<?xml version="1.0" encoding="utf-8" standalone="no"?>
<device schemaVersion="1.1">
  <name>STM32F072VBT6</name>
  <version>1.0</version>
  <description>STM32F072C8T6,STM32F072C8T7,STM32F072C8U6,STM32F072C8U7,STM32F072CBT6,STM32F072CBT7,STM32F072CBU6,STM32F072CBU7,STM32F072CBY6,STM32F072CBY7,STM32F072R8T6,STM32F072R8T7,STM32F072RBH6,STM32F072RBH7,STM32F072RBI6,STM32F072RBI7,STM32F072RBT6,STM32F072RBT7,STM32F072V8H6,STM32F072V8T6,STM32F072VBH6,STM32F072VBT6</description>
  <addressUnitBits>8</addressUnitBits>
  <width>32</width>
  <size>0x20</size>
  <resetValue>0</resetValue>
  <resetMask>0xFFFFFFFF</resetMask>
  <peripherals>
    <peripheral>
      <name>OB</name>
      <baseAddress>0x1ffff800</baseAddress>
      <registers>
        <register>
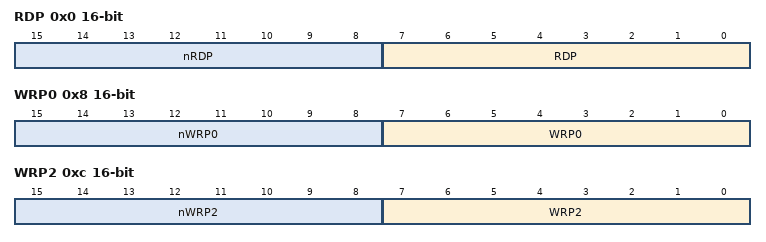
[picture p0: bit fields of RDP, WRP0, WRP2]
          <name>RDP</name>
          <addressOffset>0x0</addressOffset>
          <size>0x10</size>
          <fields>
            <field>
              <name>RDP</name>
              <bitOffset>0</bitOffset>
              <bitWidth>8</bitWidth>
            </field>
            <field>
              <name>nRDP</name>
              <bitOffset>8</bitOffset>
              <bitWidth>8</bitWidth>
            </field>
          </fields>
        </register>
        <register>
          <name>USER</name>
          <addressOffset>0x2</addressOffset>
          <size>0x10</size>
          <fields>
            <field>
              <name>USER</name>
              <bitOffset>16</bitOffset>
              <bitWidth>8</bitWidth>
            </field>
            <field>
              <name>nUSER</name>
              <bitOffset>24</bitOffset>
              <bitWidth>8</bitWidth>
            </field>
          </fields>
        </register>
        <register>
          <name>DATA0</name>
          <addressOffset>0x4</addressOffset>
          <size>0x10</size>
        </register>
        <register>
          <name>DATA1</name>
          <addressOffset>0x6</addressOffset>
          <size>0x10</size>
        </register>
        <register>
          <name>WRP0</name>
          <addressOffset>0x8</addressOffset>
          <size>0x10</size>
          <fields>
            <field>
              <name>WRP0</name>
              <bitOffset>0</bitOffset>
              <bitWidth>8</bitWidth>
            </field>
            <field>
              <name>nWRP0</name>
              <bitOffset>8</bitOffset>
              <bitWidth>8</bitWidth>
            </field>
          </fields>
        </register>
        <register>
          <name>WRP1</name>
          <addressOffset>0xa</addressOffset>
          <size>0x10</size>
          <fields>
            <field>
              <name>WRP1</name>
              <bitOffset>16</bitOffset>
              <bitWidth>8</bitWidth>
            </field>
            <field>
              <name>nWRP1</name>
              <bitOffset>24</bitOffset>
              <bitWidth>8</bitWidth>
            </field>
          </fields>
        </register>
        <register>
          <name>WRP2</name>
          <addressOffset>0xc</addressOffset>
          <size>0x10</size>
          <fields>
            <field>
              <name>WRP2</name>
              <bitOffset>0</bitOffset>
              <bitWidth>8</bitWidth>
            </field>
            <field>
              <name>nWRP2</name>
              <bitOffset>8</bitOffset>
              <bitWidth>8</bitWidth>
            </field>
          </fields>
        </register>
        <register>
          <name>WRP3</name>
          <addressOffset>0xe</addressOffset>
          <size>0x10</size>
          <fields>
            <field>
              <name>WRP3</name>
              <bitOffset>16</bitOffset>
              <bitWidth>8</bitWidth>
            </field>
            <field>
              <name>nWRP3</name>
              <bitOffset>24</bitOffset>
              <bitWidth>8</bitWidth>
            </field>
          </fields>
        </register>
      </registers>
    </peripheral>
    <peripheral>
      <name>TIM2</name>
      <baseAddress>0x40000000</baseAddress>
      <registers>
        <register>
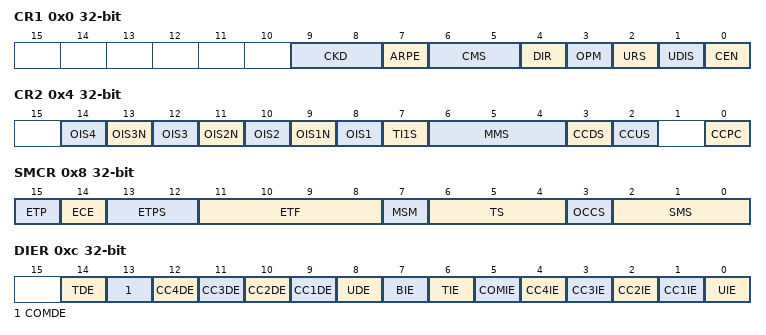
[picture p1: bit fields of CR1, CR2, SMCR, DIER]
          <name>CR1</name>
          <addressOffset>0x0</addressOffset>
          <size>0x20</size>
          <fields>
            <field>
              <name>CEN</name>
              <bitOffset>0</bitOffset>
              <bitWidth>1</bitWidth>
            </field>
            <field>
              <name>UDIS</name>
              <bitOffset>1</bitOffset>
              <bitWidth>1</bitWidth>
            </field>
            <field>
              <name>URS</name>
              <bitOffset>2</bitOffset>
              <bitWidth>1</bitWidth>
            </field>
            <field>
              <name>OPM</name>
              <bitOffset>3</bitOffset>
              <bitWidth>1</bitWidth>
            </field>
            <field>
              <name>DIR</name>
              <bitOffset>4</bitOffset>
              <bitWidth>1</bitWidth>
            </field>
            <field>
              <name>CMS</name>
              <bitOffset>5</bitOffset>
              <bitWidth>2</bitWidth>
            </field>
            <field>
              <name>ARPE</name>
              <bitOffset>7</bitOffset>
              <bitWidth>1</bitWidth>
            </field>
            <field>
              <name>CKD</name>
              <bitOffset>8</bitOffset>
              <bitWidth>2</bitWidth>
            </field>
          </fields>
        </register>
        <register>
          <name>CR2</name>
          <addressOffset>0x4</addressOffset>
          <size>0x20</size>
          <fields>
            <field>
              <name>CCPC</name>
              <bitOffset>0</bitOffset>
              <bitWidth>1</bitWidth>
            </field>
            <field>
              <name>CCUS</name>
              <bitOffset>2</bitOffset>
              <bitWidth>1</bitWidth>
            </field>
            <field>
              <name>CCDS</name>
              <bitOffset>3</bitOffset>
              <bitWidth>1</bitWidth>
            </field>
            <field>
              <name>MMS</name>
              <bitOffset>4</bitOffset>
              <bitWidth>3</bitWidth>
            </field>
            <field>
              <name>TI1S</name>
              <bitOffset>7</bitOffset>
              <bitWidth>1</bitWidth>
            </field>
            <field>
              <name>OIS1</name>
              <bitOffset>8</bitOffset>
              <bitWidth>1</bitWidth>
            </field>
            <field>
              <name>OIS1N</name>
              <bitOffset>9</bitOffset>
              <bitWidth>1</bitWidth>
            </field>
            <field>
              <name>OIS2</name>
              <bitOffset>10</bitOffset>
              <bitWidth>1</bitWidth>
            </field>
            <field>
              <name>OIS2N</name>
              <bitOffset>11</bitOffset>
              <bitWidth>1</bitWidth>
            </field>
            <field>
              <name>OIS3</name>
              <bitOffset>12</bitOffset>
              <bitWidth>1</bitWidth>
            </field>
            <field>
              <name>OIS3N</name>
              <bitOffset>13</bitOffset>
              <bitWidth>1</bitWidth>
            </field>
            <field>
              <name>OIS4</name>
              <bitOffset>14</bitOffset>
              <bitWidth>1</bitWidth>
            </field>
          </fields>
        </register>
        <register>
          <name>SMCR</name>
          <addressOffset>0x8</addressOffset>
          <size>0x20</size>
          <fields>
            <field>
              <name>SMS</name>
              <bitOffset>0</bitOffset>
              <bitWidth>3</bitWidth>
            </field>
            <field>
              <name>OCCS</name>
              <bitOffset>3</bitOffset>
              <bitWidth>1</bitWidth>
            </field>
            <field>
              <name>TS</name>
              <bitOffset>4</bitOffset>
              <bitWidth>3</bitWidth>
            </field>
            <field>
              <name>MSM</name>
              <bitOffset>7</bitOffset>
              <bitWidth>1</bitWidth>
            </field>
            <field>
              <name>ETF</name>
              <bitOffset>8</bitOffset>
              <bitWidth>4</bitWidth>
            </field>
            <field>
              <name>ETPS</name>
              <bitOffset>12</bitOffset>
              <bitWidth>2</bitWidth>
            </field>
            <field>
              <name>ECE</name>
              <bitOffset>14</bitOffset>
              <bitWidth>1</bitWidth>
            </field>
            <field>
              <name>ETP</name>
              <bitOffset>15</bitOffset>
              <bitWidth>1</bitWidth>
            </field>
          </fields>
        </register>
        <register>
          <name>DIER</name>
          <addressOffset>0xc</addressOffset>
          <size>0x20</size>
          <fields>
            <field>
              <name>UIE</name>
              <bitOffset>0</bitOffset>
              <bitWidth>1</bitWidth>
            </field>
            <field>
              <name>CC1IE</name>
              <bitOffset>1</bitOffset>
              <bitWidth>1</bitWidth>
            </field>
            <field>
              <name>CC2IE</name>
              <bitOffset>2</bitOffset>
              <bitWidth>1</bitWidth>
            </field>
            <field>
              <name>CC3IE</name>
              <bitOffset>3</bitOffset>
              <bitWidth>1</bitWidth>
            </field>
            <field>
              <name>CC4IE</name>
              <bitOffset>4</bitOffset>
              <bitWidth>1</bitWidth>
            </field>
            <field>
              <name>COMIE</name>
              <bitOffset>5</bitOffset>
              <bitWidth>1</bitWidth>
            </field>
            <field>
              <name>TIE</name>
              <bitOffset>6</bitOffset>
              <bitWidth>1</bitWidth>
            </field>
            <field>
              <name>BIE</name>
              <bitOffset>7</bitOffset>
              <bitWidth>1</bitWidth>
            </field>
            <field>
              <name>UDE</name>
              <bitOffset>8</bitOffset>
              <bitWidth>1</bitWidth>
            </field>
            <field>
              <name>CC1DE</name>
              <bitOffset>9</bitOffset>
              <bitWidth>1</bitWidth>
            </field>
            <field>
              <name>CC2DE</name>
              <bitOffset>10</bitOffset>
              <bitWidth>1</bitWidth>
            </field>
            <field>
              <name>CC3DE</name>
              <bitOffset>11</bitOffset>
              <bitWidth>1</bitWidth>
            </field>
            <field>
              <name>CC4DE</name>
              <bitOffset>12</bitOffset>
              <bitWidth>1</bitWidth>
            </field>
            <field>
              <name>COMDE</name>
              <bitOffset>13</bitOffset>
              <bitWidth>1</bitWidth>
            </field>
            <field>
              <name>TDE</name>
              <bitOffset>14</bitOffset>
              <bitWidth>1</bitWidth>
            </field>
          </fields>
        </register>
        <register>
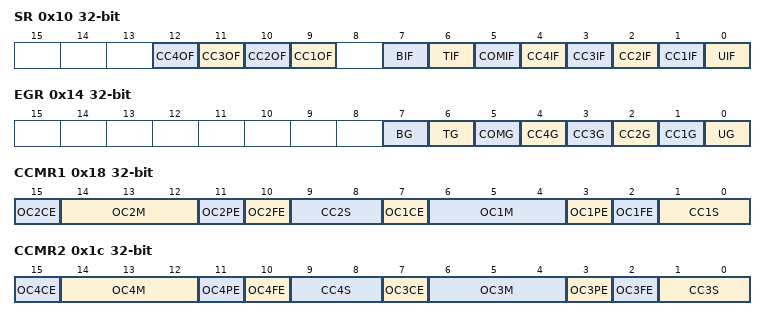
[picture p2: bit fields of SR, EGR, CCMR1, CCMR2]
          <name>SR</name>
          <addressOffset>0x10</addressOffset>
          <size>0x20</size>
          <fields>
            <field>
              <name>UIF</name>
              <bitOffset>0</bitOffset>
              <bitWidth>1</bitWidth>
            </field>
            <field>
              <name>CC1IF</name>
              <bitOffset>1</bitOffset>
              <bitWidth>1</bitWidth>
            </field>
            <field>
              <name>CC2IF</name>
              <bitOffset>2</bitOffset>
              <bitWidth>1</bitWidth>
            </field>
            <field>
              <name>CC3IF</name>
              <bitOffset>3</bitOffset>
              <bitWidth>1</bitWidth>
            </field>
            <field>
              <name>CC4IF</name>
              <bitOffset>4</bitOffset>
              <bitWidth>1</bitWidth>
            </field>
            <field>
              <name>COMIF</name>
              <bitOffset>5</bitOffset>
              <bitWidth>1</bitWidth>
            </field>
            <field>
              <name>TIF</name>
              <bitOffset>6</bitOffset>
              <bitWidth>1</bitWidth>
            </field>
            <field>
              <name>BIF</name>
              <bitOffset>7</bitOffset>
              <bitWidth>1</bitWidth>
            </field>
            <field>
              <name>CC1OF</name>
              <bitOffset>9</bitOffset>
              <bitWidth>1</bitWidth>
            </field>
            <field>
              <name>CC2OF</name>
              <bitOffset>10</bitOffset>
              <bitWidth>1</bitWidth>
            </field>
            <field>
              <name>CC3OF</name>
              <bitOffset>11</bitOffset>
              <bitWidth>1</bitWidth>
            </field>
            <field>
              <name>CC4OF</name>
              <bitOffset>12</bitOffset>
              <bitWidth>1</bitWidth>
            </field>
          </fields>
        </register>
        <register>
          <name>EGR</name>
          <addressOffset>0x14</addressOffset>
          <size>0x20</size>
          <fields>
            <field>
              <name>UG</name>
              <bitOffset>0</bitOffset>
              <bitWidth>1</bitWidth>
            </field>
            <field>
              <name>CC1G</name>
              <bitOffset>1</bitOffset>
              <bitWidth>1</bitWidth>
            </field>
            <field>
              <name>CC2G</name>
              <bitOffset>2</bitOffset>
              <bitWidth>1</bitWidth>
            </field>
            <field>
              <name>CC3G</name>
              <bitOffset>3</bitOffset>
              <bitWidth>1</bitWidth>
            </field>
            <field>
              <name>CC4G</name>
              <bitOffset>4</bitOffset>
              <bitWidth>1</bitWidth>
            </field>
            <field>
              <name>COMG</name>
              <bitOffset>5</bitOffset>
              <bitWidth>1</bitWidth>
            </field>
            <field>
              <name>TG</name>
              <bitOffset>6</bitOffset>
              <bitWidth>1</bitWidth>
            </field>
            <field>
              <name>BG</name>
              <bitOffset>7</bitOffset>
              <bitWidth>1</bitWidth>
            </field>
          </fields>
        </register>
        <register>
          <name>CCMR1</name>
          <addressOffset>0x18</addressOffset>
          <size>0x20</size>
          <fields>
            <field>
              <name>CC1S</name>
              <bitOffset>0</bitOffset>
              <bitWidth>2</bitWidth>
            </field>
            <field>
              <name>OC1FE</name>
              <bitOffset>2</bitOffset>
              <bitWidth>1</bitWidth>
            </field>
            <field>
              <name>OC1PE</name>
              <bitOffset>3</bitOffset>
              <bitWidth>1</bitWidth>
            </field>
            <field>
              <name>OC1M</name>
              <bitOffset>4</bitOffset>
              <bitWidth>3</bitWidth>
            </field>
            <field>
              <name>OC1CE</name>
              <bitOffset>7</bitOffset>
              <bitWidth>1</bitWidth>
            </field>
            <field>
              <name>CC2S</name>
              <bitOffset>8</bitOffset>
              <bitWidth>2</bitWidth>
            </field>
            <field>
              <name>OC2FE</name>
              <bitOffset>10</bitOffset>
              <bitWidth>1</bitWidth>
            </field>
            <field>
              <name>OC2PE</name>
              <bitOffset>11</bitOffset>
              <bitWidth>1</bitWidth>
            </field>
            <field>
              <name>OC2M</name>
              <bitOffset>12</bitOffset>
              <bitWidth>3</bitWidth>
            </field>
            <field>
              <name>OC2CE</name>
              <bitOffset>15</bitOffset>
              <bitWidth>1</bitWidth>
            </field>
          </fields>
        </register>
        <register>
          <name>CCMR2</name>
          <addressOffset>0x1c</addressOffset>
          <size>0x20</size>
          <fields>
            <field>
              <name>CC3S</name>
              <bitOffset>0</bitOffset>
              <bitWidth>2</bitWidth>
            </field>
            <field>
              <name>OC3FE</name>
              <bitOffset>2</bitOffset>
              <bitWidth>1</bitWidth>
            </field>
            <field>
              <name>OC3PE</name>
              <bitOffset>3</bitOffset>
              <bitWidth>1</bitWidth>
            </field>
            <field>
              <name>OC3M</name>
              <bitOffset>4</bitOffset>
              <bitWidth>3</bitWidth>
            </field>
            <field>
              <name>OC3CE</name>
              <bitOffset>7</bitOffset>
              <bitWidth>1</bitWidth>
            </field>
            <field>
              <name>CC4S</name>
              <bitOffset>8</bitOffset>
              <bitWidth>2</bitWidth>
            </field>
            <field>
              <name>OC4FE</name>
              <bitOffset>10</bitOffset>
              <bitWidth>1</bitWidth>
            </field>
            <field>
              <name>OC4PE</name>
              <bitOffset>11</bitOffset>
              <bitWidth>1</bitWidth>
            </field>
            <field>
              <name>OC4M</name>
              <bitOffset>12</bitOffset>
              <bitWidth>3</bitWidth>
            </field>
            <field>
              <name>OC4CE</name>
              <bitOffset>15</bitOffset>
              <bitWidth>1</bitWidth>
            </field>
          </fields>
        </register>
        <register>
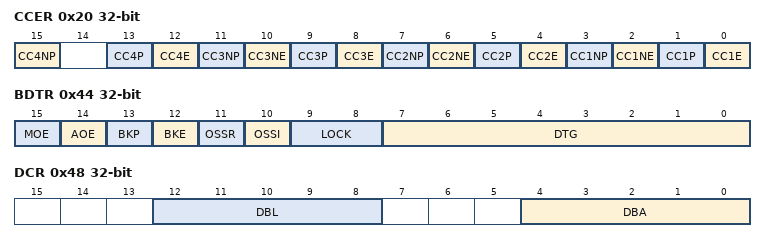
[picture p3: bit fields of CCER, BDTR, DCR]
          <name>CCER</name>
          <addressOffset>0x20</addressOffset>
          <size>0x20</size>
          <fields>
            <field>
              <name>CC1E</name>
              <bitOffset>0</bitOffset>
              <bitWidth>1</bitWidth>
            </field>
            <field>
              <name>CC1P</name>
              <bitOffset>1</bitOffset>
              <bitWidth>1</bitWidth>
            </field>
            <field>
              <name>CC1NE</name>
              <bitOffset>2</bitOffset>
              <bitWidth>1</bitWidth>
            </field>
            <field>
              <name>CC1NP</name>
              <bitOffset>3</bitOffset>
              <bitWidth>1</bitWidth>
            </field>
            <field>
              <name>CC2E</name>
              <bitOffset>4</bitOffset>
              <bitWidth>1</bitWidth>
            </field>
            <field>
              <name>CC2P</name>
              <bitOffset>5</bitOffset>
              <bitWidth>1</bitWidth>
            </field>
            <field>
              <name>CC2NE</name>
              <bitOffset>6</bitOffset>
              <bitWidth>1</bitWidth>
            </field>
            <field>
              <name>CC2NP</name>
              <bitOffset>7</bitOffset>
              <bitWidth>1</bitWidth>
            </field>
            <field>
              <name>CC3E</name>
              <bitOffset>8</bitOffset>
              <bitWidth>1</bitWidth>
            </field>
            <field>
              <name>CC3P</name>
              <bitOffset>9</bitOffset>
              <bitWidth>1</bitWidth>
            </field>
            <field>
              <name>CC3NE</name>
              <bitOffset>10</bitOffset>
              <bitWidth>1</bitWidth>
            </field>
            <field>
              <name>CC3NP</name>
              <bitOffset>11</bitOffset>
              <bitWidth>1</bitWidth>
            </field>
            <field>
              <name>CC4E</name>
              <bitOffset>12</bitOffset>
              <bitWidth>1</bitWidth>
            </field>
            <field>
              <name>CC4P</name>
              <bitOffset>13</bitOffset>
              <bitWidth>1</bitWidth>
            </field>
            <field>
              <name>CC4NP</name>
              <bitOffset>15</bitOffset>
              <bitWidth>1</bitWidth>
            </field>
          </fields>
        </register>
        <register>
          <name>CNT</name>
          <addressOffset>0x24</addressOffset>
          <size>0x20</size>
          <fields>
            <field>
              <name>CNT</name>
              <bitOffset>0</bitOffset>
              <bitWidth>32</bitWidth>
            </field>
          </fields>
        </register>
        <register>
          <name>PSC</name>
          <addressOffset>0x28</addressOffset>
          <size>0x20</size>
          <fields>
            <field>
              <name>PSC</name>
              <bitOffset>0</bitOffset>
              <bitWidth>16</bitWidth>
            </field>
          </fields>
        </register>
        <register>
          <name>ARR</name>
          <addressOffset>0x2c</addressOffset>
          <size>0x20</size>
          <fields>
            <field>
              <name>ARR</name>
              <bitOffset>0</bitOffset>
              <bitWidth>32</bitWidth>
            </field>
          </fields>
        </register>
        <register>
          <name>RCR</name>
          <addressOffset>0x30</addressOffset>
          <size>0x20</size>
          <fields>
            <field>
              <name>REP</name>
              <bitOffset>0</bitOffset>
              <bitWidth>8</bitWidth>
            </field>
          </fields>
        </register>
        <register>
          <name>CCR1</name>
          <addressOffset>0x34</addressOffset>
          <size>0x20</size>
          <fields>
            <field>
              <name>CCR1</name>
              <bitOffset>0</bitOffset>
              <bitWidth>16</bitWidth>
            </field>
          </fields>
        </register>
        <register>
          <name>CCR2</name>
          <addressOffset>0x38</addressOffset>
          <size>0x20</size>
          <fields>
            <field>
              <name>CCR2</name>
              <bitOffset>0</bitOffset>
              <bitWidth>16</bitWidth>
            </field>
          </fields>
        </register>
        <register>
          <name>CCR3</name>
          <addressOffset>0x3c</addressOffset>
          <size>0x20</size>
          <fields>
            <field>
              <name>CCR3</name>
              <bitOffset>0</bitOffset>
              <bitWidth>16</bitWidth>
            </field>
          </fields>
        </register>
        <register>
          <name>CCR4</name>
          <addressOffset>0x40</addressOffset>
          <size>0x20</size>
          <fields>
            <field>
              <name>CCR4</name>
              <bitOffset>0</bitOffset>
              <bitWidth>16</bitWidth>
            </field>
          </fields>
        </register>
        <register>
          <name>BDTR</name>
          <addressOffset>0x44</addressOffset>
          <size>0x20</size>
          <fields>
            <field>
              <name>DTG</name>
              <bitOffset>0</bitOffset>
              <bitWidth>8</bitWidth>
            </field>
            <field>
              <name>LOCK</name>
              <bitOffset>8</bitOffset>
              <bitWidth>2</bitWidth>
            </field>
            <field>
              <name>OSSI</name>
              <bitOffset>10</bitOffset>
              <bitWidth>1</bitWidth>
            </field>
            <field>
              <name>OSSR</name>
              <bitOffset>11</bitOffset>
              <bitWidth>1</bitWidth>
            </field>
            <field>
              <name>BKE</name>
              <bitOffset>12</bitOffset>
              <bitWidth>1</bitWidth>
            </field>
            <field>
              <name>BKP</name>
              <bitOffset>13</bitOffset>
              <bitWidth>1</bitWidth>
            </field>
            <field>
              <name>AOE</name>
              <bitOffset>14</bitOffset>
              <bitWidth>1</bitWidth>
            </field>
            <field>
              <name>MOE</name>
              <bitOffset>15</bitOffset>
              <bitWidth>1</bitWidth>
            </field>
          </fields>
        </register>
        <register>
          <name>DCR</name>
          <addressOffset>0x48</addressOffset>
          <size>0x20</size>
          <fields>
            <field>
              <name>DBA</name>
              <bitOffset>0</bitOffset>
              <bitWidth>5</bitWidth>
            </field>
            <field>
              <name>DBL</name>
              <bitOffset>8</bitOffset>
              <bitWidth>5</bitWidth>
            </field>
          </fields>
        </register>
        <register>
          <name>DMAR</name>
          <addressOffset>0x4c</addressOffset>
          <size>0x20</size>
          <fields>
            <field>
              <name>DMAB</name>
              <bitOffset>0</bitOffset>
              <bitWidth>16</bitWidth>
            </field>
          </fields>
        </register>
        <register>
          <name>OR</name>
          <addressOffset>0x50</addressOffset>
          <size>0x20</size>
        </register>
      </registers>
    </peripheral>
    <peripheral>
      <name>TIM3</name>
      <baseAddress>0x40000400</baseAddress>
      <registers>
        <register>
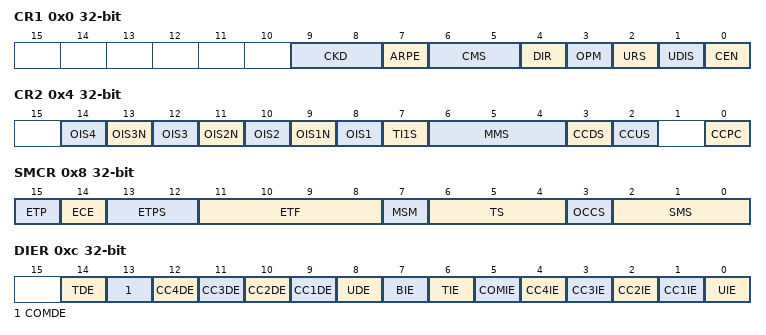
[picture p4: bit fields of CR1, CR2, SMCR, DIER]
          <name>CR1</name>
          <addressOffset>0x0</addressOffset>
          <size>0x20</size>
          <fields>
            <field>
              <name>CEN</name>
              <bitOffset>0</bitOffset>
              <bitWidth>1</bitWidth>
            </field>
            <field>
              <name>UDIS</name>
              <bitOffset>1</bitOffset>
              <bitWidth>1</bitWidth>
            </field>
            <field>
              <name>URS</name>
              <bitOffset>2</bitOffset>
              <bitWidth>1</bitWidth>
            </field>
            <field>
              <name>OPM</name>
              <bitOffset>3</bitOffset>
              <bitWidth>1</bitWidth>
            </field>
            <field>
              <name>DIR</name>
              <bitOffset>4</bitOffset>
              <bitWidth>1</bitWidth>
            </field>
            <field>
              <name>CMS</name>
              <bitOffset>5</bitOffset>
              <bitWidth>2</bitWidth>
            </field>
            <field>
              <name>ARPE</name>
              <bitOffset>7</bitOffset>
              <bitWidth>1</bitWidth>
            </field>
            <field>
              <name>CKD</name>
              <bitOffset>8</bitOffset>
              <bitWidth>2</bitWidth>
            </field>
          </fields>
        </register>
        <register>
          <name>CR2</name>
          <addressOffset>0x4</addressOffset>
          <size>0x20</size>
          <fields>
            <field>
              <name>CCPC</name>
              <bitOffset>0</bitOffset>
              <bitWidth>1</bitWidth>
            </field>
            <field>
              <name>CCUS</name>
              <bitOffset>2</bitOffset>
              <bitWidth>1</bitWidth>
            </field>
            <field>
              <name>CCDS</name>
              <bitOffset>3</bitOffset>
              <bitWidth>1</bitWidth>
            </field>
            <field>
              <name>MMS</name>
              <bitOffset>4</bitOffset>
              <bitWidth>3</bitWidth>
            </field>
            <field>
              <name>TI1S</name>
              <bitOffset>7</bitOffset>
              <bitWidth>1</bitWidth>
            </field>
            <field>
              <name>OIS1</name>
              <bitOffset>8</bitOffset>
              <bitWidth>1</bitWidth>
            </field>
            <field>
              <name>OIS1N</name>
              <bitOffset>9</bitOffset>
              <bitWidth>1</bitWidth>
            </field>
            <field>
              <name>OIS2</name>
              <bitOffset>10</bitOffset>
              <bitWidth>1</bitWidth>
            </field>
            <field>
              <name>OIS2N</name>
              <bitOffset>11</bitOffset>
              <bitWidth>1</bitWidth>
            </field>
            <field>
              <name>OIS3</name>
              <bitOffset>12</bitOffset>
              <bitWidth>1</bitWidth>
            </field>
            <field>
              <name>OIS3N</name>
              <bitOffset>13</bitOffset>
              <bitWidth>1</bitWidth>
            </field>
            <field>
              <name>OIS4</name>
              <bitOffset>14</bitOffset>
              <bitWidth>1</bitWidth>
            </field>
          </fields>
        </register>
        <register>
          <name>SMCR</name>
          <addressOffset>0x8</addressOffset>
          <size>0x20</size>
          <fields>
            <field>
              <name>SMS</name>
              <bitOffset>0</bitOffset>
              <bitWidth>3</bitWidth>
            </field>
            <field>
              <name>OCCS</name>
              <bitOffset>3</bitOffset>
              <bitWidth>1</bitWidth>
            </field>
            <field>
              <name>TS</name>
              <bitOffset>4</bitOffset>
              <bitWidth>3</bitWidth>
            </field>
            <field>
              <name>MSM</name>
              <bitOffset>7</bitOffset>
              <bitWidth>1</bitWidth>
            </field>
            <field>
              <name>ETF</name>
              <bitOffset>8</bitOffset>
              <bitWidth>4</bitWidth>
            </field>
            <field>
              <name>ETPS</name>
              <bitOffset>12</bitOffset>
              <bitWidth>2</bitWidth>
            </field>
            <field>
              <name>ECE</name>
              <bitOffset>14</bitOffset>
              <bitWidth>1</bitWidth>
            </field>
            <field>
              <name>ETP</name>
              <bitOffset>15</bitOffset>
              <bitWidth>1</bitWidth>
            </field>
          </fields>
        </register>
        <register>
          <name>DIER</name>
          <addressOffset>0xc</addressOffset>
          <size>0x20</size>
          <fields>
            <field>
              <name>UIE</name>
              <bitOffset>0</bitOffset>
              <bitWidth>1</bitWidth>
            </field>
            <field>
              <name>CC1IE</name>
              <bitOffset>1</bitOffset>
              <bitWidth>1</bitWidth>
            </field>
            <field>
              <name>CC2IE</name>
              <bitOffset>2</bitOffset>
              <bitWidth>1</bitWidth>
            </field>
            <field>
              <name>CC3IE</name>
              <bitOffset>3</bitOffset>
              <bitWidth>1</bitWidth>
            </field>
            <field>
              <name>CC4IE</name>
              <bitOffset>4</bitOffset>
              <bitWidth>1</bitWidth>
            </field>
            <field>
              <name>COMIE</name>
              <bitOffset>5</bitOffset>
              <bitWidth>1</bitWidth>
            </field>
            <field>
              <name>TIE</name>
              <bitOffset>6</bitOffset>
              <bitWidth>1</bitWidth>
            </field>
            <field>
              <name>BIE</name>
              <bitOffset>7</bitOffset>
              <bitWidth>1</bitWidth>
            </field>
            <field>
              <name>UDE</name>
              <bitOffset>8</bitOffset>
              <bitWidth>1</bitWidth>
            </field>
            <field>
              <name>CC1DE</name>
              <bitOffset>9</bitOffset>
              <bitWidth>1</bitWidth>
            </field>
            <field>
              <name>CC2DE</name>
              <bitOffset>10</bitOffset>
              <bitWidth>1</bitWidth>
            </field>
            <field>
              <name>CC3DE</name>
              <bitOffset>11</bitOffset>
              <bitWidth>1</bitWidth>
            </field>
            <field>
              <name>CC4DE</name>
              <bitOffset>12</bitOffset>
              <bitWidth>1</bitWidth>
            </field>
            <field>
              <name>COMDE</name>
              <bitOffset>13</bitOffset>
              <bitWidth>1</bitWidth>
            </field>
            <field>
              <name>TDE</name>
              <bitOffset>14</bitOffset>
              <bitWidth>1</bitWidth>
            </field>
          </fields>
        </register>
        <register>
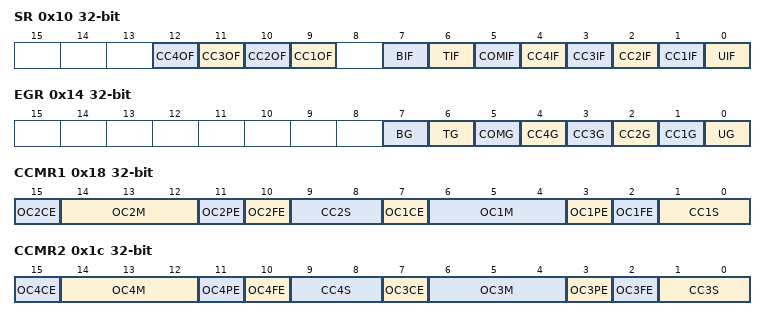
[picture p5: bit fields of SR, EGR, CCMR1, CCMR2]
          <name>SR</name>
          <addressOffset>0x10</addressOffset>
          <size>0x20</size>
          <fields>
            <field>
              <name>UIF</name>
              <bitOffset>0</bitOffset>
              <bitWidth>1</bitWidth>
            </field>
            <field>
              <name>CC1IF</name>
              <bitOffset>1</bitOffset>
              <bitWidth>1</bitWidth>
            </field>
            <field>
              <name>CC2IF</name>
              <bitOffset>2</bitOffset>
              <bitWidth>1</bitWidth>
            </field>
            <field>
              <name>CC3IF</name>
              <bitOffset>3</bitOffset>
              <bitWidth>1</bitWidth>
            </field>
            <field>
              <name>CC4IF</name>
              <bitOffset>4</bitOffset>
              <bitWidth>1</bitWidth>
            </field>
            <field>
              <name>COMIF</name>
              <bitOffset>5</bitOffset>
              <bitWidth>1</bitWidth>
            </field>
            <field>
              <name>TIF</name>
              <bitOffset>6</bitOffset>
              <bitWidth>1</bitWidth>
            </field>
            <field>
              <name>BIF</name>
              <bitOffset>7</bitOffset>
              <bitWidth>1</bitWidth>
            </field>
            <field>
              <name>CC1OF</name>
              <bitOffset>9</bitOffset>
              <bitWidth>1</bitWidth>
            </field>
            <field>
              <name>CC2OF</name>
              <bitOffset>10</bitOffset>
              <bitWidth>1</bitWidth>
            </field>
            <field>
              <name>CC3OF</name>
              <bitOffset>11</bitOffset>
              <bitWidth>1</bitWidth>
            </field>
            <field>
              <name>CC4OF</name>
              <bitOffset>12</bitOffset>
              <bitWidth>1</bitWidth>
            </field>
          </fields>
        </register>
        <register>
          <name>EGR</name>
          <addressOffset>0x14</addressOffset>
          <size>0x20</size>
          <fields>
            <field>
              <name>UG</name>
              <bitOffset>0</bitOffset>
              <bitWidth>1</bitWidth>
            </field>
            <field>
              <name>CC1G</name>
              <bitOffset>1</bitOffset>
              <bitWidth>1</bitWidth>
            </field>
            <field>
              <name>CC2G</name>
              <bitOffset>2</bitOffset>
              <bitWidth>1</bitWidth>
            </field>
            <field>
              <name>CC3G</name>
              <bitOffset>3</bitOffset>
              <bitWidth>1</bitWidth>
            </field>
            <field>
              <name>CC4G</name>
              <bitOffset>4</bitOffset>
              <bitWidth>1</bitWidth>
            </field>
            <field>
              <name>COMG</name>
              <bitOffset>5</bitOffset>
              <bitWidth>1</bitWidth>
            </field>
            <field>
              <name>TG</name>
              <bitOffset>6</bitOffset>
              <bitWidth>1</bitWidth>
            </field>
            <field>
              <name>BG</name>
              <bitOffset>7</bitOffset>
              <bitWidth>1</bitWidth>
            </field>
          </fields>
        </register>
        <register>
          <name>CCMR1</name>
          <addressOffset>0x18</addressOffset>
          <size>0x20</size>
          <fields>
            <field>
              <name>CC1S</name>
              <bitOffset>0</bitOffset>
              <bitWidth>2</bitWidth>
            </field>
            <field>
              <name>OC1FE</name>
              <bitOffset>2</bitOffset>
              <bitWidth>1</bitWidth>
            </field>
            <field>
              <name>OC1PE</name>
              <bitOffset>3</bitOffset>
              <bitWidth>1</bitWidth>
            </field>
            <field>
              <name>OC1M</name>
              <bitOffset>4</bitOffset>
              <bitWidth>3</bitWidth>
            </field>
            <field>
              <name>OC1CE</name>
              <bitOffset>7</bitOffset>
              <bitWidth>1</bitWidth>
            </field>
            <field>
              <name>CC2S</name>
              <bitOffset>8</bitOffset>
              <bitWidth>2</bitWidth>
            </field>
            <field>
              <name>OC2FE</name>
              <bitOffset>10</bitOffset>
              <bitWidth>1</bitWidth>
            </field>
            <field>
              <name>OC2PE</name>
              <bitOffset>11</bitOffset>
              <bitWidth>1</bitWidth>
            </field>
            <field>
              <name>OC2M</name>
              <bitOffset>12</bitOffset>
              <bitWidth>3</bitWidth>
            </field>
            <field>
              <name>OC2CE</name>
              <bitOffset>15</bitOffset>
              <bitWidth>1</bitWidth>
            </field>
          </fields>
        </register>
        <register>
          <name>CCMR2</name>
          <addressOffset>0x1c</addressOffset>
          <size>0x20</size>
          <fields>
            <field>
              <name>CC3S</name>
              <bitOffset>0</bitOffset>
              <bitWidth>2</bitWidth>
            </field>
            <field>
              <name>OC3FE</name>
              <bitOffset>2</bitOffset>
              <bitWidth>1</bitWidth>
            </field>
            <field>
              <name>OC3PE</name>
              <bitOffset>3</bitOffset>
              <bitWidth>1</bitWidth>
            </field>
            <field>
              <name>OC3M</name>
              <bitOffset>4</bitOffset>
              <bitWidth>3</bitWidth>
            </field>
            <field>
              <name>OC3CE</name>
              <bitOffset>7</bitOffset>
              <bitWidth>1</bitWidth>
            </field>
            <field>
              <name>CC4S</name>
              <bitOffset>8</bitOffset>
              <bitWidth>2</bitWidth>
            </field>
            <field>
              <name>OC4FE</name>
              <bitOffset>10</bitOffset>
              <bitWidth>1</bitWidth>
            </field>
            <field>
              <name>OC4PE</name>
              <bitOffset>11</bitOffset>
              <bitWidth>1</bitWidth>
            </field>
            <field>
              <name>OC4M</name>
              <bitOffset>12</bitOffset>
              <bitWidth>3</bitWidth>
            </field>
            <field>
              <name>OC4CE</name>
              <bitOffset>15</bitOffset>
              <bitWidth>1</bitWidth>
            </field>
          </fields>
        </register>
        <register>
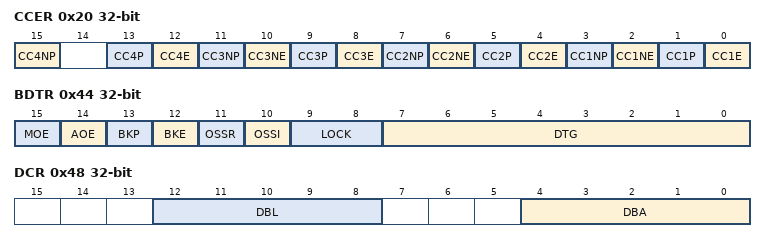
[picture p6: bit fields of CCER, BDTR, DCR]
          <name>CCER</name>
          <addressOffset>0x20</addressOffset>
          <size>0x20</size>
          <fields>
            <field>
              <name>CC1E</name>
              <bitOffset>0</bitOffset>
              <bitWidth>1</bitWidth>
            </field>
            <field>
              <name>CC1P</name>
              <bitOffset>1</bitOffset>
              <bitWidth>1</bitWidth>
            </field>
            <field>
              <name>CC1NE</name>
              <bitOffset>2</bitOffset>
              <bitWidth>1</bitWidth>
            </field>
            <field>
              <name>CC1NP</name>
              <bitOffset>3</bitOffset>
              <bitWidth>1</bitWidth>
            </field>
            <field>
              <name>CC2E</name>
              <bitOffset>4</bitOffset>
              <bitWidth>1</bitWidth>
            </field>
            <field>
              <name>CC2P</name>
              <bitOffset>5</bitOffset>
              <bitWidth>1</bitWidth>
            </field>
            <field>
              <name>CC2NE</name>
              <bitOffset>6</bitOffset>
              <bitWidth>1</bitWidth>
            </field>
            <field>
              <name>CC2NP</name>
              <bitOffset>7</bitOffset>
              <bitWidth>1</bitWidth>
            </field>
            <field>
              <name>CC3E</name>
              <bitOffset>8</bitOffset>
              <bitWidth>1</bitWidth>
            </field>
            <field>
              <name>CC3P</name>
              <bitOffset>9</bitOffset>
              <bitWidth>1</bitWidth>
            </field>
            <field>
              <name>CC3NE</name>
              <bitOffset>10</bitOffset>
              <bitWidth>1</bitWidth>
            </field>
            <field>
              <name>CC3NP</name>
              <bitOffset>11</bitOffset>
              <bitWidth>1</bitWidth>
            </field>
            <field>
              <name>CC4E</name>
              <bitOffset>12</bitOffset>
              <bitWidth>1</bitWidth>
            </field>
            <field>
              <name>CC4P</name>
              <bitOffset>13</bitOffset>
              <bitWidth>1</bitWidth>
            </field>
            <field>
              <name>CC4NP</name>
              <bitOffset>15</bitOffset>
              <bitWidth>1</bitWidth>
            </field>
          </fields>
        </register>
        <register>
          <name>CNT</name>
          <addressOffset>0x24</addressOffset>
          <size>0x20</size>
          <fields>
            <field>
              <name>CNT</name>
              <bitOffset>0</bitOffset>
              <bitWidth>32</bitWidth>
            </field>
          </fields>
        </register>
        <register>
          <name>PSC</name>
          <addressOffset>0x28</addressOffset>
          <size>0x20</size>
          <fields>
            <field>
              <name>PSC</name>
              <bitOffset>0</bitOffset>
              <bitWidth>16</bitWidth>
            </field>
          </fields>
        </register>
        <register>
          <name>ARR</name>
          <addressOffset>0x2c</addressOffset>
          <size>0x20</size>
          <fields>
            <field>
              <name>ARR</name>
              <bitOffset>0</bitOffset>
              <bitWidth>32</bitWidth>
            </field>
          </fields>
        </register>
        <register>
          <name>RCR</name>
          <addressOffset>0x30</addressOffset>
          <size>0x20</size>
          <fields>
            <field>
              <name>REP</name>
              <bitOffset>0</bitOffset>
              <bitWidth>8</bitWidth>
            </field>
          </fields>
        </register>
        <register>
          <name>CCR1</name>
          <addressOffset>0x34</addressOffset>
          <size>0x20</size>
          <fields>
            <field>
              <name>CCR1</name>
              <bitOffset>0</bitOffset>
              <bitWidth>16</bitWidth>
            </field>
          </fields>
        </register>
        <register>
          <name>CCR2</name>
          <addressOffset>0x38</addressOffset>
          <size>0x20</size>
          <fields>
            <field>
              <name>CCR2</name>
              <bitOffset>0</bitOffset>
              <bitWidth>16</bitWidth>
            </field>
          </fields>
        </register>
        <register>
          <name>CCR3</name>
          <addressOffset>0x3c</addressOffset>
          <size>0x20</size>
          <fields>
            <field>
              <name>CCR3</name>
              <bitOffset>0</bitOffset>
              <bitWidth>16</bitWidth>
            </field>
          </fields>
        </register>
        <register>
          <name>CCR4</name>
          <addressOffset>0x40</addressOffset>
          <size>0x20</size>
          <fields>
            <field>
              <name>CCR4</name>
              <bitOffset>0</bitOffset>
              <bitWidth>16</bitWidth>
            </field>
          </fields>
        </register>
        <register>
          <name>BDTR</name>
          <addressOffset>0x44</addressOffset>
          <size>0x20</size>
          <fields>
            <field>
              <name>DTG</name>
              <bitOffset>0</bitOffset>
              <bitWidth>8</bitWidth>
            </field>
            <field>
              <name>LOCK</name>
              <bitOffset>8</bitOffset>
              <bitWidth>2</bitWidth>
            </field>
            <field>
              <name>OSSI</name>
              <bitOffset>10</bitOffset>
              <bitWidth>1</bitWidth>
            </field>
            <field>
              <name>OSSR</name>
              <bitOffset>11</bitOffset>
              <bitWidth>1</bitWidth>
            </field>
            <field>
              <name>BKE</name>
              <bitOffset>12</bitOffset>
              <bitWidth>1</bitWidth>
            </field>
            <field>
              <name>BKP</name>
              <bitOffset>13</bitOffset>
              <bitWidth>1</bitWidth>
            </field>
            <field>
              <name>AOE</name>
              <bitOffset>14</bitOffset>
              <bitWidth>1</bitWidth>
            </field>
            <field>
              <name>MOE</name>
              <bitOffset>15</bitOffset>
              <bitWidth>1</bitWidth>
            </field>
          </fields>
        </register>
        <register>
          <name>DCR</name>
          <addressOffset>0x48</addressOffset>
          <size>0x20</size>
          <fields>
            <field>
              <name>DBA</name>
              <bitOffset>0</bitOffset>
              <bitWidth>5</bitWidth>
            </field>
            <field>
              <name>DBL</name>
              <bitOffset>8</bitOffset>
              <bitWidth>5</bitWidth>
            </field>
          </fields>
        </register>
        <register>
          <name>DMAR</name>
          <addressOffset>0x4c</addressOffset>
          <size>0x20</size>
          <fields>
            <field>
              <name>DMAB</name>
              <bitOffset>0</bitOffset>
              <bitWidth>16</bitWidth>
            </field>
          </fields>
        </register>
        <register>
          <name>OR</name>
          <addressOffset>0x50</addressOffset>
          <size>0x20</size>
        </register>
      </registers>
    </peripheral>
    <peripheral>
      <name>TIM6</name>
      <baseAddress>0x40001000</baseAddress>
      <registers>
        <register>
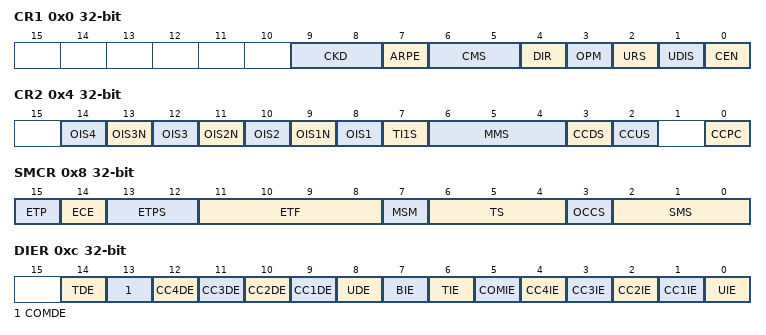
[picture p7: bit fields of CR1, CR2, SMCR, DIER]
          <name>CR1</name>
          <addressOffset>0x0</addressOffset>
          <size>0x20</size>
          <fields>
            <field>
              <name>CEN</name>
              <bitOffset>0</bitOffset>
              <bitWidth>1</bitWidth>
            </field>
            <field>
              <name>UDIS</name>
              <bitOffset>1</bitOffset>
              <bitWidth>1</bitWidth>
            </field>
            <field>
              <name>URS</name>
              <bitOffset>2</bitOffset>
              <bitWidth>1</bitWidth>
            </field>
            <field>
              <name>OPM</name>
              <bitOffset>3</bitOffset>
              <bitWidth>1</bitWidth>
            </field>
            <field>
              <name>DIR</name>
              <bitOffset>4</bitOffset>
              <bitWidth>1</bitWidth>
            </field>
            <field>
              <name>CMS</name>
              <bitOffset>5</bitOffset>
              <bitWidth>2</bitWidth>
            </field>
            <field>
              <name>ARPE</name>
              <bitOffset>7</bitOffset>
              <bitWidth>1</bitWidth>
            </field>
            <field>
              <name>CKD</name>
              <bitOffset>8</bitOffset>
              <bitWidth>2</bitWidth>
            </field>
          </fields>
        </register>
        <register>
          <name>CR2</name>
          <addressOffset>0x4</addressOffset>
          <size>0x20</size>
          <fields>
            <field>
              <name>CCPC</name>
              <bitOffset>0</bitOffset>
              <bitWidth>1</bitWidth>
            </field>
            <field>
              <name>CCUS</name>
              <bitOffset>2</bitOffset>
              <bitWidth>1</bitWidth>
            </field>
            <field>
              <name>CCDS</name>
              <bitOffset>3</bitOffset>
              <bitWidth>1</bitWidth>
            </field>
            <field>
              <name>MMS</name>
              <bitOffset>4</bitOffset>
              <bitWidth>3</bitWidth>
            </field>
            <field>
              <name>TI1S</name>
              <bitOffset>7</bitOffset>
              <bitWidth>1</bitWidth>
            </field>
            <field>
              <name>OIS1</name>
              <bitOffset>8</bitOffset>
              <bitWidth>1</bitWidth>
            </field>
            <field>
              <name>OIS1N</name>
              <bitOffset>9</bitOffset>
              <bitWidth>1</bitWidth>
            </field>
            <field>
              <name>OIS2</name>
              <bitOffset>10</bitOffset>
              <bitWidth>1</bitWidth>
            </field>
            <field>
              <name>OIS2N</name>
              <bitOffset>11</bitOffset>
              <bitWidth>1</bitWidth>
            </field>
            <field>
              <name>OIS3</name>
              <bitOffset>12</bitOffset>
              <bitWidth>1</bitWidth>
            </field>
            <field>
              <name>OIS3N</name>
              <bitOffset>13</bitOffset>
              <bitWidth>1</bitWidth>
            </field>
            <field>
              <name>OIS4</name>
              <bitOffset>14</bitOffset>
              <bitWidth>1</bitWidth>
            </field>
          </fields>
        </register>
        <register>
          <name>SMCR</name>
          <addressOffset>0x8</addressOffset>
          <size>0x20</size>
          <fields>
            <field>
              <name>SMS</name>
              <bitOffset>0</bitOffset>
              <bitWidth>3</bitWidth>
            </field>
            <field>
              <name>OCCS</name>
              <bitOffset>3</bitOffset>
              <bitWidth>1</bitWidth>
            </field>
            <field>
              <name>TS</name>
              <bitOffset>4</bitOffset>
              <bitWidth>3</bitWidth>
            </field>
            <field>
              <name>MSM</name>
              <bitOffset>7</bitOffset>
              <bitWidth>1</bitWidth>
            </field>
            <field>
              <name>ETF</name>
              <bitOffset>8</bitOffset>
              <bitWidth>4</bitWidth>
            </field>
            <field>
              <name>ETPS</name>
              <bitOffset>12</bitOffset>
              <bitWidth>2</bitWidth>
            </field>
            <field>
              <name>ECE</name>
              <bitOffset>14</bitOffset>
              <bitWidth>1</bitWidth>
            </field>
            <field>
              <name>ETP</name>
              <bitOffset>15</bitOffset>
              <bitWidth>1</bitWidth>
            </field>
          </fields>
        </register>
        <register>
          <name>DIER</name>
          <addressOffset>0xc</addressOffset>
          <size>0x20</size>
          <fields>
            <field>
              <name>UIE</name>
              <bitOffset>0</bitOffset>
              <bitWidth>1</bitWidth>
            </field>
            <field>
              <name>CC1IE</name>
              <bitOffset>1</bitOffset>
              <bitWidth>1</bitWidth>
            </field>
            <field>
              <name>CC2IE</name>
              <bitOffset>2</bitOffset>
              <bitWidth>1</bitWidth>
            </field>
            <field>
              <name>CC3IE</name>
              <bitOffset>3</bitOffset>
              <bitWidth>1</bitWidth>
            </field>
            <field>
              <name>CC4IE</name>
              <bitOffset>4</bitOffset>
              <bitWidth>1</bitWidth>
            </field>
            <field>
              <name>COMIE</name>
              <bitOffset>5</bitOffset>
              <bitWidth>1</bitWidth>
            </field>
            <field>
              <name>TIE</name>
              <bitOffset>6</bitOffset>
              <bitWidth>1</bitWidth>
            </field>
            <field>
              <name>BIE</name>
              <bitOffset>7</bitOffset>
              <bitWidth>1</bitWidth>
            </field>
            <field>
              <name>UDE</name>
              <bitOffset>8</bitOffset>
              <bitWidth>1</bitWidth>
            </field>
            <field>
              <name>CC1DE</name>
              <bitOffset>9</bitOffset>
              <bitWidth>1</bitWidth>
            </field>
            <field>
              <name>CC2DE</name>
              <bitOffset>10</bitOffset>
              <bitWidth>1</bitWidth>
            </field>
            <field>
              <name>CC3DE</name>
              <bitOffset>11</bitOffset>
              <bitWidth>1</bitWidth>
            </field>
            <field>
              <name>CC4DE</name>
              <bitOffset>12</bitOffset>
              <bitWidth>1</bitWidth>
            </field>
            <field>
              <name>COMDE</name>
              <bitOffset>13</bitOffset>
              <bitWidth>1</bitWidth>
            </field>
            <field>
              <name>TDE</name>
              <bitOffset>14</bitOffset>
              <bitWidth>1</bitWidth>
            </field>
          </fields>
        </register>
        <register>
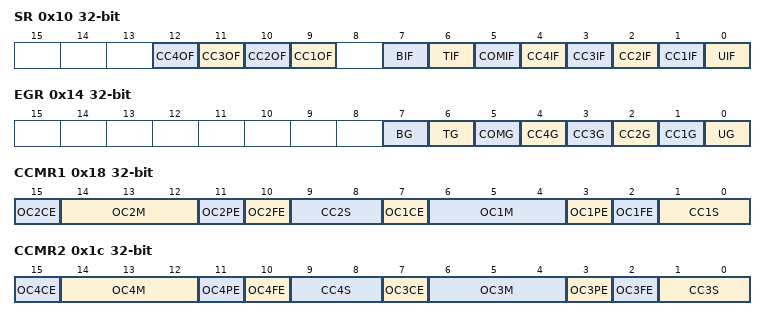
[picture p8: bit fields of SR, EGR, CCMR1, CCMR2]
          <name>SR</name>
          <addressOffset>0x10</addressOffset>
          <size>0x20</size>
          <fields>
            <field>
              <name>UIF</name>
              <bitOffset>0</bitOffset>
              <bitWidth>1</bitWidth>
            </field>
            <field>
              <name>CC1IF</name>
              <bitOffset>1</bitOffset>
              <bitWidth>1</bitWidth>
            </field>
            <field>
              <name>CC2IF</name>
              <bitOffset>2</bitOffset>
              <bitWidth>1</bitWidth>
            </field>
            <field>
              <name>CC3IF</name>
              <bitOffset>3</bitOffset>
              <bitWidth>1</bitWidth>
            </field>
            <field>
              <name>CC4IF</name>
              <bitOffset>4</bitOffset>
              <bitWidth>1</bitWidth>
            </field>
            <field>
              <name>COMIF</name>
              <bitOffset>5</bitOffset>
              <bitWidth>1</bitWidth>
            </field>
            <field>
              <name>TIF</name>
              <bitOffset>6</bitOffset>
              <bitWidth>1</bitWidth>
            </field>
            <field>
              <name>BIF</name>
              <bitOffset>7</bitOffset>
              <bitWidth>1</bitWidth>
            </field>
            <field>
              <name>CC1OF</name>
              <bitOffset>9</bitOffset>
              <bitWidth>1</bitWidth>
            </field>
            <field>
              <name>CC2OF</name>
              <bitOffset>10</bitOffset>
              <bitWidth>1</bitWidth>
            </field>
            <field>
              <name>CC3OF</name>
              <bitOffset>11</bitOffset>
              <bitWidth>1</bitWidth>
            </field>
            <field>
              <name>CC4OF</name>
              <bitOffset>12</bitOffset>
              <bitWidth>1</bitWidth>
            </field>
          </fields>
        </register>
        <register>
          <name>EGR</name>
          <addressOffset>0x14</addressOffset>
          <size>0x20</size>
          <fields>
            <field>
              <name>UG</name>
              <bitOffset>0</bitOffset>
              <bitWidth>1</bitWidth>
            </field>
            <field>
              <name>CC1G</name>
              <bitOffset>1</bitOffset>
              <bitWidth>1</bitWidth>
            </field>
            <field>
              <name>CC2G</name>
              <bitOffset>2</bitOffset>
              <bitWidth>1</bitWidth>
            </field>
            <field>
              <name>CC3G</name>
              <bitOffset>3</bitOffset>
              <bitWidth>1</bitWidth>
            </field>
            <field>
              <name>CC4G</name>
              <bitOffset>4</bitOffset>
              <bitWidth>1</bitWidth>
            </field>
            <field>
              <name>COMG</name>
              <bitOffset>5</bitOffset>
              <bitWidth>1</bitWidth>
            </field>
            <field>
              <name>TG</name>
              <bitOffset>6</bitOffset>
              <bitWidth>1</bitWidth>
            </field>
            <field>
              <name>BG</name>
              <bitOffset>7</bitOffset>
              <bitWidth>1</bitWidth>
            </field>
          </fields>
        </register>
        <register>
          <name>CCMR1</name>
          <addressOffset>0x18</addressOffset>
          <size>0x20</size>
          <fields>
            <field>
              <name>CC1S</name>
              <bitOffset>0</bitOffset>
              <bitWidth>2</bitWidth>
            </field>
            <field>
              <name>OC1FE</name>
              <bitOffset>2</bitOffset>
              <bitWidth>1</bitWidth>
            </field>
            <field>
              <name>OC1PE</name>
              <bitOffset>3</bitOffset>
              <bitWidth>1</bitWidth>
            </field>
            <field>
              <name>OC1M</name>
              <bitOffset>4</bitOffset>
              <bitWidth>3</bitWidth>
            </field>
            <field>
              <name>OC1CE</name>
              <bitOffset>7</bitOffset>
              <bitWidth>1</bitWidth>
            </field>
            <field>
              <name>CC2S</name>
              <bitOffset>8</bitOffset>
              <bitWidth>2</bitWidth>
            </field>
            <field>
              <name>OC2FE</name>
              <bitOffset>10</bitOffset>
              <bitWidth>1</bitWidth>
            </field>
            <field>
              <name>OC2PE</name>
              <bitOffset>11</bitOffset>
              <bitWidth>1</bitWidth>
            </field>
            <field>
              <name>OC2M</name>
              <bitOffset>12</bitOffset>
              <bitWidth>3</bitWidth>
            </field>
            <field>
              <name>OC2CE</name>
              <bitOffset>15</bitOffset>
              <bitWidth>1</bitWidth>
            </field>
          </fields>
        </register>
        <register>
          <name>CCMR2</name>
          <addressOffset>0x1c</addressOffset>
          <size>0x20</size>
          <fields>
            <field>
              <name>CC3S</name>
              <bitOffset>0</bitOffset>
              <bitWidth>2</bitWidth>
            </field>
            <field>
              <name>OC3FE</name>
              <bitOffset>2</bitOffset>
              <bitWidth>1</bitWidth>
            </field>
            <field>
              <name>OC3PE</name>
              <bitOffset>3</bitOffset>
              <bitWidth>1</bitWidth>
            </field>
            <field>
              <name>OC3M</name>
              <bitOffset>4</bitOffset>
              <bitWidth>3</bitWidth>
            </field>
            <field>
              <name>OC3CE</name>
              <bitOffset>7</bitOffset>
              <bitWidth>1</bitWidth>
            </field>
            <field>
              <name>CC4S</name>
              <bitOffset>8</bitOffset>
              <bitWidth>2</bitWidth>
            </field>
            <field>
              <name>OC4FE</name>
              <bitOffset>10</bitOffset>
              <bitWidth>1</bitWidth>
            </field>
            <field>
              <name>OC4PE</name>
              <bitOffset>11</bitOffset>
              <bitWidth>1</bitWidth>
            </field>
            <field>
              <name>OC4M</name>
              <bitOffset>12</bitOffset>
              <bitWidth>3</bitWidth>
            </field>
            <field>
              <name>OC4CE</name>
              <bitOffset>15</bitOffset>
              <bitWidth>1</bitWidth>
            </field>
          </fields>
        </register>
        <register>
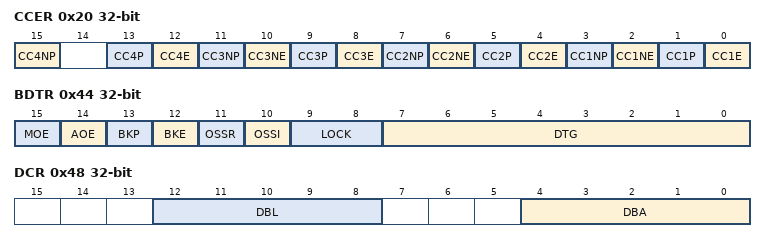
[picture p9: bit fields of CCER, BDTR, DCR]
          <name>CCER</name>
          <addressOffset>0x20</addressOffset>
          <size>0x20</size>
          <fields>
            <field>
              <name>CC1E</name>
              <bitOffset>0</bitOffset>
              <bitWidth>1</bitWidth>
            </field>
            <field>
              <name>CC1P</name>
              <bitOffset>1</bitOffset>
              <bitWidth>1</bitWidth>
            </field>
            <field>
              <name>CC1NE</name>
              <bitOffset>2</bitOffset>
              <bitWidth>1</bitWidth>
            </field>
            <field>
              <name>CC1NP</name>
              <bitOffset>3</bitOffset>
              <bitWidth>1</bitWidth>
            </field>
            <field>
              <name>CC2E</name>
              <bitOffset>4</bitOffset>
              <bitWidth>1</bitWidth>
            </field>
            <field>
              <name>CC2P</name>
              <bitOffset>5</bitOffset>
              <bitWidth>1</bitWidth>
            </field>
            <field>
              <name>CC2NE</name>
              <bitOffset>6</bitOffset>
              <bitWidth>1</bitWidth>
            </field>
            <field>
              <name>CC2NP</name>
              <bitOffset>7</bitOffset>
              <bitWidth>1</bitWidth>
            </field>
            <field>
              <name>CC3E</name>
              <bitOffset>8</bitOffset>
              <bitWidth>1</bitWidth>
            </field>
            <field>
              <name>CC3P</name>
              <bitOffset>9</bitOffset>
              <bitWidth>1</bitWidth>
            </field>
            <field>
              <name>CC3NE</name>
              <bitOffset>10</bitOffset>
              <bitWidth>1</bitWidth>
            </field>
            <field>
              <name>CC3NP</name>
              <bitOffset>11</bitOffset>
              <bitWidth>1</bitWidth>
            </field>
            <field>
              <name>CC4E</name>
              <bitOffset>12</bitOffset>
              <bitWidth>1</bitWidth>
            </field>
            <field>
              <name>CC4P</name>
              <bitOffset>13</bitOffset>
              <bitWidth>1</bitWidth>
            </field>
            <field>
              <name>CC4NP</name>
              <bitOffset>15</bitOffset>
              <bitWidth>1</bitWidth>
            </field>
          </fields>
        </register>
        <register>
          <name>CNT</name>
          <addressOffset>0x24</addressOffset>
          <size>0x20</size>
          <fields>
            <field>
              <name>CNT</name>
              <bitOffset>0</bitOffset>
              <bitWidth>32</bitWidth>
            </field>
          </fields>
        </register>
        <register>
          <name>PSC</name>
          <addressOffset>0x28</addressOffset>
          <size>0x20</size>
          <fields>
            <field>
              <name>PSC</name>
              <bitOffset>0</bitOffset>
              <bitWidth>16</bitWidth>
            </field>
          </fields>
        </register>
        <register>
          <name>ARR</name>
          <addressOffset>0x2c</addressOffset>
          <size>0x20</size>
          <fields>
            <field>
              <name>ARR</name>
              <bitOffset>0</bitOffset>
              <bitWidth>32</bitWidth>
            </field>
          </fields>
        </register>
        <register>
          <name>RCR</name>
          <addressOffset>0x30</addressOffset>
          <size>0x20</size>
          <fields>
            <field>
              <name>REP</name>
              <bitOffset>0</bitOffset>
              <bitWidth>8</bitWidth>
            </field>
          </fields>
        </register>
        <register>
          <name>CCR1</name>
          <addressOffset>0x34</addressOffset>
          <size>0x20</size>
          <fields>
            <field>
              <name>CCR1</name>
              <bitOffset>0</bitOffset>
              <bitWidth>16</bitWidth>
            </field>
          </fields>
        </register>
        <register>
          <name>CCR2</name>
          <addressOffset>0x38</addressOffset>
          <size>0x20</size>
          <fields>
            <field>
              <name>CCR2</name>
              <bitOffset>0</bitOffset>
              <bitWidth>16</bitWidth>
            </field>
          </fields>
        </register>
        <register>
          <name>CCR3</name>
          <addressOffset>0x3c</addressOffset>
          <size>0x20</size>
          <fields>
            <field>
              <name>CCR3</name>
              <bitOffset>0</bitOffset>
              <bitWidth>16</bitWidth>
            </field>
          </fields>
        </register>
        <register>
          <name>CCR4</name>
          <addressOffset>0x40</addressOffset>
          <size>0x20</size>
          <fields>
            <field>
              <name>CCR4</name>
              <bitOffset>0</bitOffset>
              <bitWidth>16</bitWidth>
            </field>
          </fields>
        </register>
        <register>
          <name>BDTR</name>
          <addressOffset>0x44</addressOffset>
          <size>0x20</size>
          <fields>
            <field>
              <name>DTG</name>
              <bitOffset>0</bitOffset>
              <bitWidth>8</bitWidth>
            </field>
            <field>
              <name>LOCK</name>
              <bitOffset>8</bitOffset>
              <bitWidth>2</bitWidth>
            </field>
            <field>
              <name>OSSI</name>
              <bitOffset>10</bitOffset>
              <bitWidth>1</bitWidth>
            </field>
            <field>
              <name>OSSR</name>
              <bitOffset>11</bitOffset>
              <bitWidth>1</bitWidth>
            </field>
            <field>
              <name>BKE</name>
              <bitOffset>12</bitOffset>
              <bitWidth>1</bitWidth>
            </field>
            <field>
              <name>BKP</name>
              <bitOffset>13</bitOffset>
              <bitWidth>1</bitWidth>
            </field>
            <field>
              <name>AOE</name>
              <bitOffset>14</bitOffset>
              <bitWidth>1</bitWidth>
            </field>
            <field>
              <name>MOE</name>
              <bitOffset>15</bitOffset>
              <bitWidth>1</bitWidth>
            </field>
          </fields>
        </register>
        <register>
          <name>DCR</name>
          <addressOffset>0x48</addressOffset>
          <size>0x20</size>
          <fields>
            <field>
              <name>DBA</name>
              <bitOffset>0</bitOffset>
              <bitWidth>5</bitWidth>
            </field>
            <field>
              <name>DBL</name>
              <bitOffset>8</bitOffset>
              <bitWidth>5</bitWidth>
            </field>
          </fields>
        </register>
        <register>
          <name>DMAR</name>
          <addressOffset>0x4c</addressOffset>
          <size>0x20</size>
          <fields>
            <field>
              <name>DMAB</name>
              <bitOffset>0</bitOffset>
              <bitWidth>16</bitWidth>
            </field>
          </fields>
        </register>
        <register>
          <name>OR</name>
          <addressOffset>0x50</addressOffset>
          <size>0x20</size>
        </register>
      </registers>
    </peripheral>
    <peripheral>
      <name>TIM7</name>
      <baseAddress>0x40001400</baseAddress>
      <registers>
        <register>
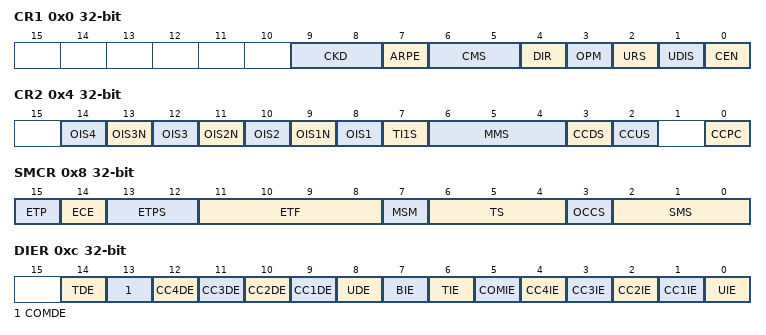
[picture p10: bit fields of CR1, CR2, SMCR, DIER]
          <name>CR1</name>
          <addressOffset>0x0</addressOffset>
          <size>0x20</size>
          <fields>
            <field>
              <name>CEN</name>
              <bitOffset>0</bitOffset>
              <bitWidth>1</bitWidth>
            </field>
            <field>
              <name>UDIS</name>
              <bitOffset>1</bitOffset>
              <bitWidth>1</bitWidth>
            </field>
            <field>
              <name>URS</name>
              <bitOffset>2</bitOffset>
              <bitWidth>1</bitWidth>
            </field>
            <field>
              <name>OPM</name>
              <bitOffset>3</bitOffset>
              <bitWidth>1</bitWidth>
            </field>
            <field>
              <name>DIR</name>
              <bitOffset>4</bitOffset>
              <bitWidth>1</bitWidth>
            </field>
            <field>
              <name>CMS</name>
              <bitOffset>5</bitOffset>
              <bitWidth>2</bitWidth>
            </field>
            <field>
              <name>ARPE</name>
              <bitOffset>7</bitOffset>
              <bitWidth>1</bitWidth>
            </field>
            <field>
              <name>CKD</name>
              <bitOffset>8</bitOffset>
              <bitWidth>2</bitWidth>
            </field>
          </fields>
        </register>
        <register>
          <name>CR2</name>
          <addressOffset>0x4</addressOffset>
          <size>0x20</size>
          <fields>
            <field>
              <name>CCPC</name>
              <bitOffset>0</bitOffset>
              <bitWidth>1</bitWidth>
            </field>
            <field>
              <name>CCUS</name>
              <bitOffset>2</bitOffset>
              <bitWidth>1</bitWidth>
            </field>
            <field>
              <name>CCDS</name>
              <bitOffset>3</bitOffset>
              <bitWidth>1</bitWidth>
            </field>
            <field>
              <name>MMS</name>
              <bitOffset>4</bitOffset>
              <bitWidth>3</bitWidth>
            </field>
            <field>
              <name>TI1S</name>
              <bitOffset>7</bitOffset>
              <bitWidth>1</bitWidth>
            </field>
            <field>
              <name>OIS1</name>
              <bitOffset>8</bitOffset>
              <bitWidth>1</bitWidth>
            </field>
            <field>
              <name>OIS1N</name>
              <bitOffset>9</bitOffset>
              <bitWidth>1</bitWidth>
            </field>
            <field>
              <name>OIS2</name>
              <bitOffset>10</bitOffset>
              <bitWidth>1</bitWidth>
            </field>
            <field>
              <name>OIS2N</name>
              <bitOffset>11</bitOffset>
              <bitWidth>1</bitWidth>
            </field>
            <field>
              <name>OIS3</name>
              <bitOffset>12</bitOffset>
              <bitWidth>1</bitWidth>
            </field>
            <field>
              <name>OIS3N</name>
              <bitOffset>13</bitOffset>
              <bitWidth>1</bitWidth>
            </field>
            <field>
              <name>OIS4</name>
              <bitOffset>14</bitOffset>
              <bitWidth>1</bitWidth>
            </field>
          </fields>
        </register>
        <register>
          <name>SMCR</name>
          <addressOffset>0x8</addressOffset>
          <size>0x20</size>
          <fields>
            <field>
              <name>SMS</name>
              <bitOffset>0</bitOffset>
              <bitWidth>3</bitWidth>
            </field>
            <field>
              <name>OCCS</name>
              <bitOffset>3</bitOffset>
              <bitWidth>1</bitWidth>
            </field>
            <field>
              <name>TS</name>
              <bitOffset>4</bitOffset>
              <bitWidth>3</bitWidth>
            </field>
            <field>
              <name>MSM</name>
              <bitOffset>7</bitOffset>
              <bitWidth>1</bitWidth>
            </field>
            <field>
              <name>ETF</name>
              <bitOffset>8</bitOffset>
              <bitWidth>4</bitWidth>
            </field>
            <field>
              <name>ETPS</name>
              <bitOffset>12</bitOffset>
              <bitWidth>2</bitWidth>
            </field>
            <field>
              <name>ECE</name>
              <bitOffset>14</bitOffset>
              <bitWidth>1</bitWidth>
            </field>
            <field>
              <name>ETP</name>
              <bitOffset>15</bitOffset>
              <bitWidth>1</bitWidth>
            </field>
          </fields>
        </register>
        <register>
          <name>DIER</name>
          <addressOffset>0xc</addressOffset>
          <size>0x20</size>
          <fields>
            <field>
              <name>UIE</name>
              <bitOffset>0</bitOffset>
              <bitWidth>1</bitWidth>
            </field>
            <field>
              <name>CC1IE</name>
              <bitOffset>1</bitOffset>
              <bitWidth>1</bitWidth>
            </field>
            <field>
              <name>CC2IE</name>
              <bitOffset>2</bitOffset>
              <bitWidth>1</bitWidth>
            </field>
            <field>
              <name>CC3IE</name>
              <bitOffset>3</bitOffset>
              <bitWidth>1</bitWidth>
            </field>
            <field>
              <name>CC4IE</name>
              <bitOffset>4</bitOffset>
              <bitWidth>1</bitWidth>
            </field>
            <field>
              <name>COMIE</name>
              <bitOffset>5</bitOffset>
              <bitWidth>1</bitWidth>
            </field>
            <field>
              <name>TIE</name>
              <bitOffset>6</bitOffset>
              <bitWidth>1</bitWidth>
            </field>
            <field>
              <name>BIE</name>
              <bitOffset>7</bitOffset>
              <bitWidth>1</bitWidth>
            </field>
            <field>
              <name>UDE</name>
              <bitOffset>8</bitOffset>
              <bitWidth>1</bitWidth>
            </field>
            <field>
              <name>CC1DE</name>
              <bitOffset>9</bitOffset>
              <bitWidth>1</bitWidth>
            </field>
            <field>
              <name>CC2DE</name>
              <bitOffset>10</bitOffset>
              <bitWidth>1</bitWidth>
            </field>
            <field>
              <name>CC3DE</name>
              <bitOffset>11</bitOffset>
              <bitWidth>1</bitWidth>
            </field>
            <field>
              <name>CC4DE</name>
              <bitOffset>12</bitOffset>
              <bitWidth>1</bitWidth>
            </field>
            <field>
              <name>COMDE</name>
              <bitOffset>13</bitOffset>
              <bitWidth>1</bitWidth>
            </field>
            <field>
              <name>TDE</name>
              <bitOffset>14</bitOffset>
              <bitWidth>1</bitWidth>
            </field>
          </fields>
        </register>
        <register>
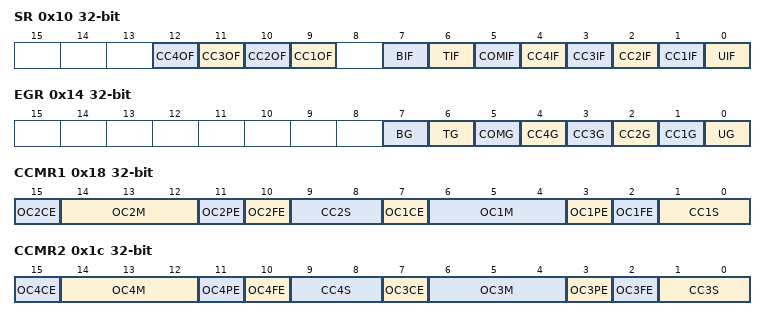
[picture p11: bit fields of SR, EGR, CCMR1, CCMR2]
          <name>SR</name>
          <addressOffset>0x10</addressOffset>
          <size>0x20</size>
          <fields>
            <field>
              <name>UIF</name>
              <bitOffset>0</bitOffset>
              <bitWidth>1</bitWidth>
            </field>
            <field>
              <name>CC1IF</name>
              <bitOffset>1</bitOffset>
              <bitWidth>1</bitWidth>
            </field>
            <field>
              <name>CC2IF</name>
              <bitOffset>2</bitOffset>
              <bitWidth>1</bitWidth>
            </field>
            <field>
              <name>CC3IF</name>
              <bitOffset>3</bitOffset>
              <bitWidth>1</bitWidth>
            </field>
            <field>
              <name>CC4IF</name>
              <bitOffset>4</bitOffset>
              <bitWidth>1</bitWidth>
            </field>
            <field>
              <name>COMIF</name>
              <bitOffset>5</bitOffset>
              <bitWidth>1</bitWidth>
            </field>
            <field>
              <name>TIF</name>
              <bitOffset>6</bitOffset>
              <bitWidth>1</bitWidth>
            </field>
            <field>
              <name>BIF</name>
              <bitOffset>7</bitOffset>
              <bitWidth>1</bitWidth>
            </field>
            <field>
              <name>CC1OF</name>
              <bitOffset>9</bitOffset>
              <bitWidth>1</bitWidth>
            </field>
            <field>
              <name>CC2OF</name>
              <bitOffset>10</bitOffset>
              <bitWidth>1</bitWidth>
            </field>
            <field>
              <name>CC3OF</name>
              <bitOffset>11</bitOffset>
              <bitWidth>1</bitWidth>
            </field>
            <field>
              <name>CC4OF</name>
              <bitOffset>12</bitOffset>
              <bitWidth>1</bitWidth>
            </field>
          </fields>
        </register>
        <register>
          <name>EGR</name>
          <addressOffset>0x14</addressOffset>
          <size>0x20</size>
          <fields>
            <field>
              <name>UG</name>
              <bitOffset>0</bitOffset>
              <bitWidth>1</bitWidth>
            </field>
            <field>
              <name>CC1G</name>
              <bitOffset>1</bitOffset>
              <bitWidth>1</bitWidth>
            </field>
            <field>
              <name>CC2G</name>
              <bitOffset>2</bitOffset>
              <bitWidth>1</bitWidth>
            </field>
            <field>
              <name>CC3G</name>
              <bitOffset>3</bitOffset>
              <bitWidth>1</bitWidth>
            </field>
            <field>
              <name>CC4G</name>
              <bitOffset>4</bitOffset>
              <bitWidth>1</bitWidth>
            </field>
            <field>
              <name>COMG</name>
              <bitOffset>5</bitOffset>
              <bitWidth>1</bitWidth>
            </field>
            <field>
              <name>TG</name>
              <bitOffset>6</bitOffset>
              <bitWidth>1</bitWidth>
            </field>
            <field>
              <name>BG</name>
              <bitOffset>7</bitOffset>
              <bitWidth>1</bitWidth>
            </field>
          </fields>
        </register>
        <register>
          <name>CCMR1</name>
          <addressOffset>0x18</addressOffset>
          <size>0x20</size>
          <fields>
            <field>
              <name>CC1S</name>
              <bitOffset>0</bitOffset>
              <bitWidth>2</bitWidth>
            </field>
            <field>
              <name>OC1FE</name>
              <bitOffset>2</bitOffset>
              <bitWidth>1</bitWidth>
            </field>
            <field>
              <name>OC1PE</name>
              <bitOffset>3</bitOffset>
              <bitWidth>1</bitWidth>
            </field>
            <field>
              <name>OC1M</name>
              <bitOffset>4</bitOffset>
              <bitWidth>3</bitWidth>
            </field>
            <field>
              <name>OC1CE</name>
              <bitOffset>7</bitOffset>
              <bitWidth>1</bitWidth>
            </field>
            <field>
              <name>CC2S</name>
              <bitOffset>8</bitOffset>
              <bitWidth>2</bitWidth>
            </field>
            <field>
              <name>OC2FE</name>
              <bitOffset>10</bitOffset>
              <bitWidth>1</bitWidth>
            </field>
            <field>
              <name>OC2PE</name>
              <bitOffset>11</bitOffset>
              <bitWidth>1</bitWidth>
            </field>
            <field>
              <name>OC2M</name>
              <bitOffset>12</bitOffset>
              <bitWidth>3</bitWidth>
            </field>
            <field>
              <name>OC2CE</name>
              <bitOffset>15</bitOffset>
              <bitWidth>1</bitWidth>
            </field>
          </fields>
        </register>
        <register>
          <name>CCMR2</name>
          <addressOffset>0x1c</addressOffset>
          <size>0x20</size>
          <fields>
            <field>
              <name>CC3S</name>
              <bitOffset>0</bitOffset>
              <bitWidth>2</bitWidth>
            </field>
            <field>
              <name>OC3FE</name>
              <bitOffset>2</bitOffset>
              <bitWidth>1</bitWidth>
            </field>
            <field>
              <name>OC3PE</name>
              <bitOffset>3</bitOffset>
              <bitWidth>1</bitWidth>
            </field>
            <field>
              <name>OC3M</name>
              <bitOffset>4</bitOffset>
              <bitWidth>3</bitWidth>
            </field>
            <field>
              <name>OC3CE</name>
              <bitOffset>7</bitOffset>
              <bitWidth>1</bitWidth>
            </field>
            <field>
              <name>CC4S</name>
              <bitOffset>8</bitOffset>
              <bitWidth>2</bitWidth>
            </field>
            <field>
              <name>OC4FE</name>
              <bitOffset>10</bitOffset>
              <bitWidth>1</bitWidth>
            </field>
            <field>
              <name>OC4PE</name>
              <bitOffset>11</bitOffset>
              <bitWidth>1</bitWidth>
            </field>
            <field>
              <name>OC4M</name>
              <bitOffset>12</bitOffset>
              <bitWidth>3</bitWidth>
            </field>
            <field>
              <name>OC4CE</name>
              <bitOffset>15</bitOffset>
              <bitWidth>1</bitWidth>
            </field>
          </fields>
        </register>
        <register>
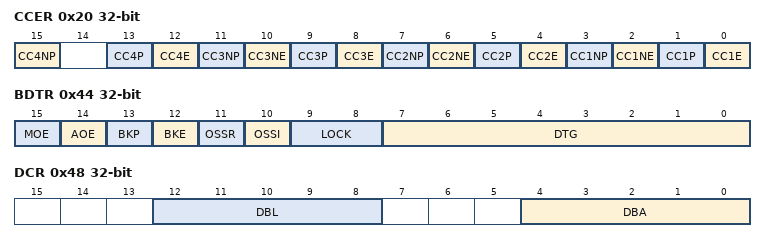
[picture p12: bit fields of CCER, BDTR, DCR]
          <name>CCER</name>
          <addressOffset>0x20</addressOffset>
          <size>0x20</size>
          <fields>
            <field>
              <name>CC1E</name>
              <bitOffset>0</bitOffset>
              <bitWidth>1</bitWidth>
            </field>
            <field>
              <name>CC1P</name>
              <bitOffset>1</bitOffset>
              <bitWidth>1</bitWidth>
            </field>
            <field>
              <name>CC1NE</name>
              <bitOffset>2</bitOffset>
              <bitWidth>1</bitWidth>
            </field>
            <field>
              <name>CC1NP</name>
              <bitOffset>3</bitOffset>
              <bitWidth>1</bitWidth>
            </field>
            <field>
              <name>CC2E</name>
              <bitOffset>4</bitOffset>
              <bitWidth>1</bitWidth>
            </field>
            <field>
              <name>CC2P</name>
              <bitOffset>5</bitOffset>
              <bitWidth>1</bitWidth>
            </field>
            <field>
              <name>CC2NE</name>
              <bitOffset>6</bitOffset>
              <bitWidth>1</bitWidth>
            </field>
            <field>
              <name>CC2NP</name>
              <bitOffset>7</bitOffset>
              <bitWidth>1</bitWidth>
            </field>
            <field>
              <name>CC3E</name>
              <bitOffset>8</bitOffset>
              <bitWidth>1</bitWidth>
            </field>
            <field>
              <name>CC3P</name>
              <bitOffset>9</bitOffset>
              <bitWidth>1</bitWidth>
            </field>
            <field>
              <name>CC3NE</name>
              <bitOffset>10</bitOffset>
              <bitWidth>1</bitWidth>
            </field>
            <field>
              <name>CC3NP</name>
              <bitOffset>11</bitOffset>
              <bitWidth>1</bitWidth>
            </field>
            <field>
              <name>CC4E</name>
              <bitOffset>12</bitOffset>
              <bitWidth>1</bitWidth>
            </field>
            <field>
              <name>CC4P</name>
              <bitOffset>13</bitOffset>
              <bitWidth>1</bitWidth>
            </field>
            <field>
              <name>CC4NP</name>
              <bitOffset>15</bitOffset>
              <bitWidth>1</bitWidth>
            </field>
          </fields>
        </register>
        <register>
          <name>CNT</name>
          <addressOffset>0x24</addressOffset>
          <size>0x20</size>
          <fields>
            <field>
              <name>CNT</name>
              <bitOffset>0</bitOffset>
              <bitWidth>32</bitWidth>
            </field>
          </fields>
        </register>
        <register>
          <name>PSC</name>
          <addressOffset>0x28</addressOffset>
          <size>0x20</size>
          <fields>
            <field>
              <name>PSC</name>
              <bitOffset>0</bitOffset>
              <bitWidth>16</bitWidth>
            </field>
          </fields>
        </register>
        <register>
          <name>ARR</name>
          <addressOffset>0x2c</addressOffset>
          <size>0x20</size>
          <fields>
            <field>
              <name>ARR</name>
              <bitOffset>0</bitOffset>
              <bitWidth>32</bitWidth>
            </field>
          </fields>
        </register>
        <register>
          <name>RCR</name>
          <addressOffset>0x30</addressOffset>
          <size>0x20</size>
          <fields>
            <field>
              <name>REP</name>
              <bitOffset>0</bitOffset>
              <bitWidth>8</bitWidth>
            </field>
          </fields>
        </register>
        <register>
          <name>CCR1</name>
          <addressOffset>0x34</addressOffset>
          <size>0x20</size>
          <fields>
            <field>
              <name>CCR1</name>
              <bitOffset>0</bitOffset>
              <bitWidth>16</bitWidth>
            </field>
          </fields>
        </register>
        <register>
          <name>CCR2</name>
          <addressOffset>0x38</addressOffset>
          <size>0x20</size>
          <fields>
            <field>
              <name>CCR2</name>
              <bitOffset>0</bitOffset>
              <bitWidth>16</bitWidth>
            </field>
          </fields>
        </register>
        <register>
          <name>CCR3</name>
          <addressOffset>0x3c</addressOffset>
          <size>0x20</size>
          <fields>
            <field>
              <name>CCR3</name>
              <bitOffset>0</bitOffset>
              <bitWidth>16</bitWidth>
            </field>
          </fields>
        </register>
        <register>
          <name>CCR4</name>
          <addressOffset>0x40</addressOffset>
          <size>0x20</size>
          <fields>
            <field>
              <name>CCR4</name>
              <bitOffset>0</bitOffset>
              <bitWidth>16</bitWidth>
            </field>
          </fields>
        </register>
        <register>
          <name>BDTR</name>
          <addressOffset>0x44</addressOffset>
          <size>0x20</size>
          <fields>
            <field>
              <name>DTG</name>
              <bitOffset>0</bitOffset>
              <bitWidth>8</bitWidth>
            </field>
            <field>
              <name>LOCK</name>
              <bitOffset>8</bitOffset>
              <bitWidth>2</bitWidth>
            </field>
            <field>
              <name>OSSI</name>
              <bitOffset>10</bitOffset>
              <bitWidth>1</bitWidth>
            </field>
            <field>
              <name>OSSR</name>
              <bitOffset>11</bitOffset>
              <bitWidth>1</bitWidth>
            </field>
            <field>
              <name>BKE</name>
              <bitOffset>12</bitOffset>
              <bitWidth>1</bitWidth>
            </field>
            <field>
              <name>BKP</name>
              <bitOffset>13</bitOffset>
              <bitWidth>1</bitWidth>
            </field>
            <field>
              <name>AOE</name>
              <bitOffset>14</bitOffset>
              <bitWidth>1</bitWidth>
            </field>
            <field>
              <name>MOE</name>
              <bitOffset>15</bitOffset>
              <bitWidth>1</bitWidth>
            </field>
          </fields>
        </register>
        <register>
          <name>DCR</name>
          <addressOffset>0x48</addressOffset>
          <size>0x20</size>
          <fields>
            <field>
              <name>DBA</name>
              <bitOffset>0</bitOffset>
              <bitWidth>5</bitWidth>
            </field>
            <field>
              <name>DBL</name>
              <bitOffset>8</bitOffset>
              <bitWidth>5</bitWidth>
            </field>
          </fields>
        </register>
        <register>
          <name>DMAR</name>
          <addressOffset>0x4c</addressOffset>
          <size>0x20</size>
          <fields>
            <field>
              <name>DMAB</name>
              <bitOffset>0</bitOffset>
              <bitWidth>16</bitWidth>
            </field>
          </fields>
        </register>
        <register>
          <name>OR</name>
          <addressOffset>0x50</addressOffset>
          <size>0x20</size>
        </register>
      </registers>
    </peripheral>
    <peripheral>
      <name>TIM14</name>
      <baseAddress>0x40002000</baseAddress>
      <registers>
        <register>
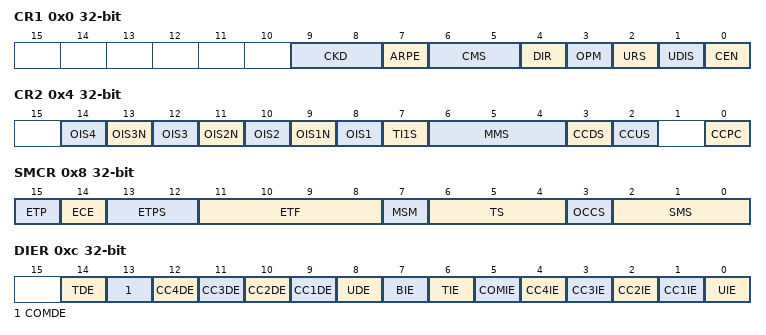
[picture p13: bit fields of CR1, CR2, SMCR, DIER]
          <name>CR1</name>
          <addressOffset>0x0</addressOffset>
          <size>0x20</size>
          <fields>
            <field>
              <name>CEN</name>
              <bitOffset>0</bitOffset>
              <bitWidth>1</bitWidth>
            </field>
            <field>
              <name>UDIS</name>
              <bitOffset>1</bitOffset>
              <bitWidth>1</bitWidth>
            </field>
            <field>
              <name>URS</name>
              <bitOffset>2</bitOffset>
              <bitWidth>1</bitWidth>
            </field>
            <field>
              <name>OPM</name>
              <bitOffset>3</bitOffset>
              <bitWidth>1</bitWidth>
            </field>
            <field>
              <name>DIR</name>
              <bitOffset>4</bitOffset>
              <bitWidth>1</bitWidth>
            </field>
            <field>
              <name>CMS</name>
              <bitOffset>5</bitOffset>
              <bitWidth>2</bitWidth>
            </field>
            <field>
              <name>ARPE</name>
              <bitOffset>7</bitOffset>
              <bitWidth>1</bitWidth>
            </field>
            <field>
              <name>CKD</name>
              <bitOffset>8</bitOffset>
              <bitWidth>2</bitWidth>
            </field>
          </fields>
        </register>
        <register>
          <name>CR2</name>
          <addressOffset>0x4</addressOffset>
          <size>0x20</size>
          <fields>
            <field>
              <name>CCPC</name>
              <bitOffset>0</bitOffset>
              <bitWidth>1</bitWidth>
            </field>
            <field>
              <name>CCUS</name>
              <bitOffset>2</bitOffset>
              <bitWidth>1</bitWidth>
            </field>
            <field>
              <name>CCDS</name>
              <bitOffset>3</bitOffset>
              <bitWidth>1</bitWidth>
            </field>
            <field>
              <name>MMS</name>
              <bitOffset>4</bitOffset>
              <bitWidth>3</bitWidth>
            </field>
            <field>
              <name>TI1S</name>
              <bitOffset>7</bitOffset>
              <bitWidth>1</bitWidth>
            </field>
            <field>
              <name>OIS1</name>
              <bitOffset>8</bitOffset>
              <bitWidth>1</bitWidth>
            </field>
            <field>
              <name>OIS1N</name>
              <bitOffset>9</bitOffset>
              <bitWidth>1</bitWidth>
            </field>
            <field>
              <name>OIS2</name>
              <bitOffset>10</bitOffset>
              <bitWidth>1</bitWidth>
            </field>
            <field>
              <name>OIS2N</name>
              <bitOffset>11</bitOffset>
              <bitWidth>1</bitWidth>
            </field>
            <field>
              <name>OIS3</name>
              <bitOffset>12</bitOffset>
              <bitWidth>1</bitWidth>
            </field>
            <field>
              <name>OIS3N</name>
              <bitOffset>13</bitOffset>
              <bitWidth>1</bitWidth>
            </field>
            <field>
              <name>OIS4</name>
              <bitOffset>14</bitOffset>
              <bitWidth>1</bitWidth>
            </field>
          </fields>
        </register>
        <register>
          <name>SMCR</name>
          <addressOffset>0x8</addressOffset>
          <size>0x20</size>
          <fields>
            <field>
              <name>SMS</name>
              <bitOffset>0</bitOffset>
              <bitWidth>3</bitWidth>
            </field>
            <field>
              <name>OCCS</name>
              <bitOffset>3</bitOffset>
              <bitWidth>1</bitWidth>
            </field>
            <field>
              <name>TS</name>
              <bitOffset>4</bitOffset>
              <bitWidth>3</bitWidth>
            </field>
            <field>
              <name>MSM</name>
              <bitOffset>7</bitOffset>
              <bitWidth>1</bitWidth>
            </field>
            <field>
              <name>ETF</name>
              <bitOffset>8</bitOffset>
              <bitWidth>4</bitWidth>
            </field>
            <field>
              <name>ETPS</name>
              <bitOffset>12</bitOffset>
              <bitWidth>2</bitWidth>
            </field>
            <field>
              <name>ECE</name>
              <bitOffset>14</bitOffset>
              <bitWidth>1</bitWidth>
            </field>
            <field>
              <name>ETP</name>
              <bitOffset>15</bitOffset>
              <bitWidth>1</bitWidth>
            </field>
          </fields>
        </register>
        <register>
          <name>DIER</name>
          <addressOffset>0xc</addressOffset>
          <size>0x20</size>
          <fields>
            <field>
              <name>UIE</name>
              <bitOffset>0</bitOffset>
              <bitWidth>1</bitWidth>
            </field>
            <field>
              <name>CC1IE</name>
              <bitOffset>1</bitOffset>
              <bitWidth>1</bitWidth>
            </field>
            <field>
              <name>CC2IE</name>
              <bitOffset>2</bitOffset>
              <bitWidth>1</bitWidth>
            </field>
            <field>
              <name>CC3IE</name>
              <bitOffset>3</bitOffset>
              <bitWidth>1</bitWidth>
            </field>
            <field>
              <name>CC4IE</name>
              <bitOffset>4</bitOffset>
              <bitWidth>1</bitWidth>
            </field>
            <field>
              <name>COMIE</name>
              <bitOffset>5</bitOffset>
              <bitWidth>1</bitWidth>
            </field>
            <field>
              <name>TIE</name>
              <bitOffset>6</bitOffset>
              <bitWidth>1</bitWidth>
            </field>
            <field>
              <name>BIE</name>
              <bitOffset>7</bitOffset>
              <bitWidth>1</bitWidth>
            </field>
            <field>
              <name>UDE</name>
              <bitOffset>8</bitOffset>
              <bitWidth>1</bitWidth>
            </field>
            <field>
              <name>CC1DE</name>
              <bitOffset>9</bitOffset>
              <bitWidth>1</bitWidth>
            </field>
            <field>
              <name>CC2DE</name>
              <bitOffset>10</bitOffset>
              <bitWidth>1</bitWidth>
            </field>
            <field>
              <name>CC3DE</name>
              <bitOffset>11</bitOffset>
              <bitWidth>1</bitWidth>
            </field>
            <field>
              <name>CC4DE</name>
              <bitOffset>12</bitOffset>
              <bitWidth>1</bitWidth>
            </field>
            <field>
              <name>COMDE</name>
              <bitOffset>13</bitOffset>
              <bitWidth>1</bitWidth>
            </field>
            <field>
              <name>TDE</name>
              <bitOffset>14</bitOffset>
              <bitWidth>1</bitWidth>
            </field>
          </fields>
        </register>
        <register>
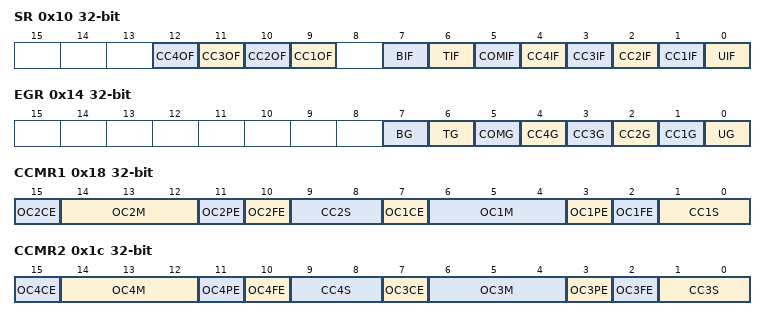
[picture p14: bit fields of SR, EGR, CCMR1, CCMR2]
          <name>SR</name>
          <addressOffset>0x10</addressOffset>
          <size>0x20</size>
          <fields>
            <field>
              <name>UIF</name>
              <bitOffset>0</bitOffset>
              <bitWidth>1</bitWidth>
            </field>
            <field>
              <name>CC1IF</name>
              <bitOffset>1</bitOffset>
              <bitWidth>1</bitWidth>
            </field>
            <field>
              <name>CC2IF</name>
              <bitOffset>2</bitOffset>
              <bitWidth>1</bitWidth>
            </field>
            <field>
              <name>CC3IF</name>
              <bitOffset>3</bitOffset>
              <bitWidth>1</bitWidth>
            </field>
            <field>
              <name>CC4IF</name>
              <bitOffset>4</bitOffset>
              <bitWidth>1</bitWidth>
            </field>
            <field>
              <name>COMIF</name>
              <bitOffset>5</bitOffset>
              <bitWidth>1</bitWidth>
            </field>
            <field>
              <name>TIF</name>
              <bitOffset>6</bitOffset>
              <bitWidth>1</bitWidth>
            </field>
            <field>
              <name>BIF</name>
              <bitOffset>7</bitOffset>
              <bitWidth>1</bitWidth>
            </field>
            <field>
              <name>CC1OF</name>
              <bitOffset>9</bitOffset>
              <bitWidth>1</bitWidth>
            </field>
            <field>
              <name>CC2OF</name>
              <bitOffset>10</bitOffset>
              <bitWidth>1</bitWidth>
            </field>
            <field>
              <name>CC3OF</name>
              <bitOffset>11</bitOffset>
              <bitWidth>1</bitWidth>
            </field>
            <field>
              <name>CC4OF</name>
              <bitOffset>12</bitOffset>
              <bitWidth>1</bitWidth>
            </field>
          </fields>
        </register>
        <register>
          <name>EGR</name>
          <addressOffset>0x14</addressOffset>
          <size>0x20</size>
          <fields>
            <field>
              <name>UG</name>
              <bitOffset>0</bitOffset>
              <bitWidth>1</bitWidth>
            </field>
            <field>
              <name>CC1G</name>
              <bitOffset>1</bitOffset>
              <bitWidth>1</bitWidth>
            </field>
            <field>
              <name>CC2G</name>
              <bitOffset>2</bitOffset>
              <bitWidth>1</bitWidth>
            </field>
            <field>
              <name>CC3G</name>
              <bitOffset>3</bitOffset>
              <bitWidth>1</bitWidth>
            </field>
            <field>
              <name>CC4G</name>
              <bitOffset>4</bitOffset>
              <bitWidth>1</bitWidth>
            </field>
            <field>
              <name>COMG</name>
              <bitOffset>5</bitOffset>
              <bitWidth>1</bitWidth>
            </field>
            <field>
              <name>TG</name>
              <bitOffset>6</bitOffset>
              <bitWidth>1</bitWidth>
            </field>
            <field>
              <name>BG</name>
              <bitOffset>7</bitOffset>
              <bitWidth>1</bitWidth>
            </field>
          </fields>
        </register>
        <register>
          <name>CCMR1</name>
          <addressOffset>0x18</addressOffset>
          <size>0x20</size>
          <fields>
            <field>
              <name>CC1S</name>
              <bitOffset>0</bitOffset>
              <bitWidth>2</bitWidth>
            </field>
            <field>
              <name>OC1FE</name>
              <bitOffset>2</bitOffset>
              <bitWidth>1</bitWidth>
            </field>
            <field>
              <name>OC1PE</name>
              <bitOffset>3</bitOffset>
              <bitWidth>1</bitWidth>
            </field>
            <field>
              <name>OC1M</name>
              <bitOffset>4</bitOffset>
              <bitWidth>3</bitWidth>
            </field>
            <field>
              <name>OC1CE</name>
              <bitOffset>7</bitOffset>
              <bitWidth>1</bitWidth>
            </field>
            <field>
              <name>CC2S</name>
              <bitOffset>8</bitOffset>
              <bitWidth>2</bitWidth>
            </field>
            <field>
              <name>OC2FE</name>
              <bitOffset>10</bitOffset>
              <bitWidth>1</bitWidth>
            </field>
            <field>
              <name>OC2PE</name>
              <bitOffset>11</bitOffset>
              <bitWidth>1</bitWidth>
            </field>
            <field>
              <name>OC2M</name>
              <bitOffset>12</bitOffset>
              <bitWidth>3</bitWidth>
            </field>
            <field>
              <name>OC2CE</name>
              <bitOffset>15</bitOffset>
              <bitWidth>1</bitWidth>
            </field>
          </fields>
        </register>
        <register>
          <name>CCMR2</name>
          <addressOffset>0x1c</addressOffset>
          <size>0x20</size>
          <fields>
            <field>
              <name>CC3S</name>
              <bitOffset>0</bitOffset>
              <bitWidth>2</bitWidth>
            </field>
            <field>
              <name>OC3FE</name>
              <bitOffset>2</bitOffset>
              <bitWidth>1</bitWidth>
            </field>
            <field>
              <name>OC3PE</name>
              <bitOffset>3</bitOffset>
              <bitWidth>1</bitWidth>
            </field>
            <field>
              <name>OC3M</name>
              <bitOffset>4</bitOffset>
              <bitWidth>3</bitWidth>
            </field>
            <field>
              <name>OC3CE</name>
              <bitOffset>7</bitOffset>
              <bitWidth>1</bitWidth>
            </field>
            <field>
              <name>CC4S</name>
              <bitOffset>8</bitOffset>
              <bitWidth>2</bitWidth>
            </field>
            <field>
              <name>OC4FE</name>
              <bitOffset>10</bitOffset>
              <bitWidth>1</bitWidth>
            </field>
            <field>
              <name>OC4PE</name>
              <bitOffset>11</bitOffset>
              <bitWidth>1</bitWidth>
            </field>
            <field>
              <name>OC4M</name>
              <bitOffset>12</bitOffset>
              <bitWidth>3</bitWidth>
            </field>
            <field>
              <name>OC4CE</name>
              <bitOffset>15</bitOffset>
              <bitWidth>1</bitWidth>
            </field>
          </fields>
        </register>
        <register>
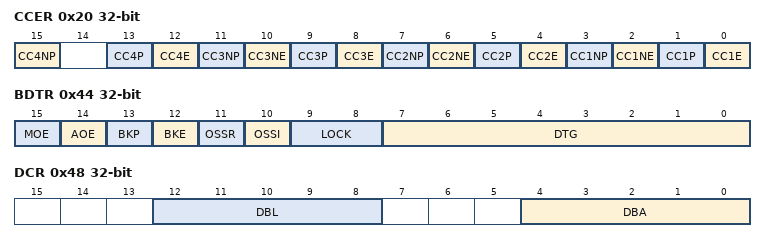
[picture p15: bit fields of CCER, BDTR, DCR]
          <name>CCER</name>
          <addressOffset>0x20</addressOffset>
          <size>0x20</size>
          <fields>
            <field>
              <name>CC1E</name>
              <bitOffset>0</bitOffset>
              <bitWidth>1</bitWidth>
            </field>
            <field>
              <name>CC1P</name>
              <bitOffset>1</bitOffset>
              <bitWidth>1</bitWidth>
            </field>
            <field>
              <name>CC1NE</name>
              <bitOffset>2</bitOffset>
              <bitWidth>1</bitWidth>
            </field>
            <field>
              <name>CC1NP</name>
              <bitOffset>3</bitOffset>
              <bitWidth>1</bitWidth>
            </field>
            <field>
              <name>CC2E</name>
              <bitOffset>4</bitOffset>
              <bitWidth>1</bitWidth>
            </field>
            <field>
              <name>CC2P</name>
              <bitOffset>5</bitOffset>
              <bitWidth>1</bitWidth>
            </field>
            <field>
              <name>CC2NE</name>
              <bitOffset>6</bitOffset>
              <bitWidth>1</bitWidth>
            </field>
            <field>
              <name>CC2NP</name>
              <bitOffset>7</bitOffset>
              <bitWidth>1</bitWidth>
            </field>
            <field>
              <name>CC3E</name>
              <bitOffset>8</bitOffset>
              <bitWidth>1</bitWidth>
            </field>
            <field>
              <name>CC3P</name>
              <bitOffset>9</bitOffset>
              <bitWidth>1</bitWidth>
            </field>
            <field>
              <name>CC3NE</name>
              <bitOffset>10</bitOffset>
              <bitWidth>1</bitWidth>
            </field>
            <field>
              <name>CC3NP</name>
              <bitOffset>11</bitOffset>
              <bitWidth>1</bitWidth>
            </field>
            <field>
              <name>CC4E</name>
              <bitOffset>12</bitOffset>
              <bitWidth>1</bitWidth>
            </field>
            <field>
              <name>CC4P</name>
              <bitOffset>13</bitOffset>
              <bitWidth>1</bitWidth>
            </field>
            <field>
              <name>CC4NP</name>
              <bitOffset>15</bitOffset>
              <bitWidth>1</bitWidth>
            </field>
          </fields>
        </register>
        <register>
          <name>CNT</name>
          <addressOffset>0x24</addressOffset>
          <size>0x20</size>
          <fields>
            <field>
              <name>CNT</name>
              <bitOffset>0</bitOffset>
              <bitWidth>32</bitWidth>
            </field>
          </fields>
        </register>
        <register>
          <name>PSC</name>
          <addressOffset>0x28</addressOffset>
          <size>0x20</size>
          <fields>
            <field>
              <name>PSC</name>
              <bitOffset>0</bitOffset>
              <bitWidth>16</bitWidth>
            </field>
          </fields>
        </register>
        <register>
          <name>ARR</name>
          <addressOffset>0x2c</addressOffset>
          <size>0x20</size>
          <fields>
            <field>
              <name>ARR</name>
              <bitOffset>0</bitOffset>
              <bitWidth>32</bitWidth>
            </field>
          </fields>
        </register>
        <register>
          <name>RCR</name>
          <addressOffset>0x30</addressOffset>
          <size>0x20</size>
          <fields>
            <field>
              <name>REP</name>
              <bitOffset>0</bitOffset>
              <bitWidth>8</bitWidth>
            </field>
          </fields>
        </register>
        <register>
          <name>CCR1</name>
          <addressOffset>0x34</addressOffset>
          <size>0x20</size>
          <fields>
            <field>
              <name>CCR1</name>
              <bitOffset>0</bitOffset>
              <bitWidth>16</bitWidth>
            </field>
          </fields>
        </register>
        <register>
          <name>CCR2</name>
          <addressOffset>0x38</addressOffset>
          <size>0x20</size>
          <fields>
            <field>
              <name>CCR2</name>
              <bitOffset>0</bitOffset>
              <bitWidth>16</bitWidth>
            </field>
          </fields>
        </register>
        <register>
          <name>CCR3</name>
          <addressOffset>0x3c</addressOffset>
          <size>0x20</size>
          <fields>
            <field>
              <name>CCR3</name>
              <bitOffset>0</bitOffset>
              <bitWidth>16</bitWidth>
            </field>
          </fields>
        </register>
        <register>
          <name>CCR4</name>
          <addressOffset>0x40</addressOffset>
          <size>0x20</size>
          <fields>
            <field>
              <name>CCR4</name>
              <bitOffset>0</bitOffset>
              <bitWidth>16</bitWidth>
            </field>
          </fields>
        </register>
        <register>
          <name>BDTR</name>
          <addressOffset>0x44</addressOffset>
          <size>0x20</size>
          <fields>
            <field>
              <name>DTG</name>
              <bitOffset>0</bitOffset>
              <bitWidth>8</bitWidth>
            </field>
            <field>
              <name>LOCK</name>
              <bitOffset>8</bitOffset>
              <bitWidth>2</bitWidth>
            </field>
            <field>
              <name>OSSI</name>
              <bitOffset>10</bitOffset>
              <bitWidth>1</bitWidth>
            </field>
            <field>
              <name>OSSR</name>
              <bitOffset>11</bitOffset>
              <bitWidth>1</bitWidth>
            </field>
            <field>
              <name>BKE</name>
              <bitOffset>12</bitOffset>
              <bitWidth>1</bitWidth>
            </field>
            <field>
              <name>BKP</name>
              <bitOffset>13</bitOffset>
              <bitWidth>1</bitWidth>
            </field>
            <field>
              <name>AOE</name>
              <bitOffset>14</bitOffset>
              <bitWidth>1</bitWidth>
            </field>
            <field>
              <name>MOE</name>
              <bitOffset>15</bitOffset>
              <bitWidth>1</bitWidth>
            </field>
          </fields>
        </register>
        <register>
          <name>DCR</name>
          <addressOffset>0x48</addressOffset>
          <size>0x20</size>
          <fields>
            <field>
              <name>DBA</name>
              <bitOffset>0</bitOffset>
              <bitWidth>5</bitWidth>
            </field>
            <field>
              <name>DBL</name>
              <bitOffset>8</bitOffset>
              <bitWidth>5</bitWidth>
            </field>
          </fields>
        </register>
        <register>
          <name>DMAR</name>
          <addressOffset>0x4c</addressOffset>
          <size>0x20</size>
          <fields>
            <field>
              <name>DMAB</name>
              <bitOffset>0</bitOffset>
              <bitWidth>16</bitWidth>
            </field>
          </fields>
        </register>
        <register>
          <name>OR</name>
          <addressOffset>0x50</addressOffset>
          <size>0x20</size>
        </register>
      </registers>
    </peripheral>
    <peripheral>
      <name>RTC</name>
      <baseAddress>0x40002800</baseAddress>
      <registers>
        <register>
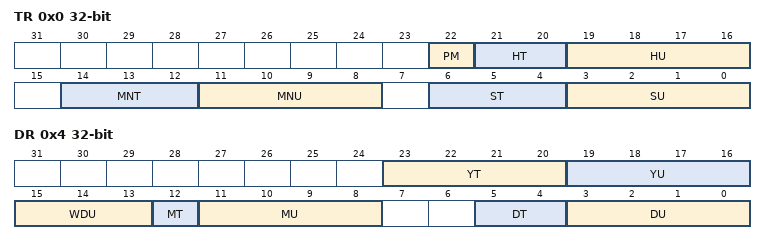
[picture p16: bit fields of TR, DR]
          <name>TR</name>
          <addressOffset>0x0</addressOffset>
          <size>0x20</size>
          <fields>
            <field>
              <name>SU</name>
              <bitOffset>0</bitOffset>
              <bitWidth>4</bitWidth>
            </field>
            <field>
              <name>ST</name>
              <bitOffset>4</bitOffset>
              <bitWidth>3</bitWidth>
            </field>
            <field>
              <name>MNU</name>
              <bitOffset>8</bitOffset>
              <bitWidth>4</bitWidth>
            </field>
            <field>
              <name>MNT</name>
              <bitOffset>12</bitOffset>
              <bitWidth>3</bitWidth>
            </field>
            <field>
              <name>HU</name>
              <bitOffset>16</bitOffset>
              <bitWidth>4</bitWidth>
            </field>
            <field>
              <name>HT</name>
              <bitOffset>20</bitOffset>
              <bitWidth>2</bitWidth>
            </field>
            <field>
              <name>PM</name>
              <bitOffset>22</bitOffset>
              <bitWidth>1</bitWidth>
            </field>
          </fields>
        </register>
        <register>
          <name>DR</name>
          <addressOffset>0x4</addressOffset>
          <size>0x20</size>
          <fields>
            <field>
              <name>DU</name>
              <bitOffset>0</bitOffset>
              <bitWidth>4</bitWidth>
            </field>
            <field>
              <name>DT</name>
              <bitOffset>4</bitOffset>
              <bitWidth>2</bitWidth>
            </field>
            <field>
              <name>MU</name>
              <bitOffset>8</bitOffset>
              <bitWidth>4</bitWidth>
            </field>
            <field>
              <name>MT</name>
              <bitOffset>12</bitOffset>
              <bitWidth>1</bitWidth>
            </field>
            <field>
              <name>WDU</name>
              <bitOffset>13</bitOffset>
              <bitWidth>3</bitWidth>
            </field>
            <field>
              <name>YU</name>
              <bitOffset>16</bitOffset>
              <bitWidth>4</bitWidth>
            </field>
            <field>
              <name>YT</name>
              <bitOffset>20</bitOffset>
              <bitWidth>4</bitWidth>
            </field>
          </fields>
        </register>
        <register>
          <name>CR</name>
          <addressOffset>0x8</addressOffset>
          <size>0x20</size>
          <fields>
            <field>
              <name>WUCKSEL</name>
              <bitOffset>0</bitOffset>
              <bitWidth>3</bitWidth>
            </field>
            <field>
              <name>TSEDGE</name>
              <bitOffset>3</bitOffset>
              <bitWidth>1</bitWidth>
            </field>
            <field>
              <name>REFCKON</name>
              <bitOffset>4</bitOffset>
              <bitWidth>1</bitWidth>
            </field>
            <field>
              <name>BYPSHAD</name>
              <bitOffset>5</bitOffset>
              <bitWidth>1</bitWidth>
            </field>
            <field>
              <name>FMT</name>
              <bitOffset>6</bitOffset>
              <bitWidth>1</bitWidth>
            </field>
            <field>
              <name>ALRAE</name>
              <bitOffset>8</bitOffset>
              <bitWidth>1</bitWidth>
            </field>
            <field>
              <name>WUTE</name>
              <bitOffset>10</bitOffset>
              <bitWidth>1</bitWidth>
            </field>
            <field>
              <name>TSE</name>
              <bitOffset>11</bitOffset>
              <bitWidth>1</bitWidth>
            </field>
            <field>
              <name>ALRAIE</name>
              <bitOffset>12</bitOffset>
              <bitWidth>1</bitWidth>
            </field>
            <field>
              <name>WUTIE</name>
              <bitOffset>14</bitOffset>
              <bitWidth>1</bitWidth>
            </field>
            <field>
              <name>TSIE</name>
              <bitOffset>15</bitOffset>
              <bitWidth>1</bitWidth>
            </field>
            <field>
              <name>ADD1H</name>
              <bitOffset>16</bitOffset>
              <bitWidth>1</bitWidth>
            </field>
            <field>
              <name>SUB1H</name>
              <bitOffset>17</bitOffset>
              <bitWidth>1</bitWidth>
            </field>
            <field>
              <name>BKP</name>
              <bitOffset>18</bitOffset>
              <bitWidth>1</bitWidth>
            </field>
            <field>
              <name>COSEL</name>
              <bitOffset>19</bitOffset>
              <bitWidth>1</bitWidth>
            </field>
            <field>
              <name>POL</name>
              <bitOffset>20</bitOffset>
              <bitWidth>1</bitWidth>
            </field>
            <field>
              <name>OSEL</name>
              <bitOffset>21</bitOffset>
              <bitWidth>2</bitWidth>
            </field>
            <field>
              <name>COE</name>
              <bitOffset>23</bitOffset>
              <bitWidth>1</bitWidth>
            </field>
          </fields>
        </register>
        <register>
          <name>ISR</name>
          <addressOffset>0xc</addressOffset>
          <size>0x20</size>
          <fields>
            <field>
              <name>ALRAWF</name>
              <bitOffset>0</bitOffset>
              <bitWidth>1</bitWidth>
            </field>
            <field>
              <name>WUTWF</name>
              <bitOffset>2</bitOffset>
              <bitWidth>1</bitWidth>
            </field>
            <field>
              <name>SHPF</name>
              <bitOffset>3</bitOffset>
              <bitWidth>1</bitWidth>
            </field>
            <field>
              <name>INITS</name>
              <bitOffset>4</bitOffset>
              <bitWidth>1</bitWidth>
            </field>
            <field>
              <name>RSF</name>
              <bitOffset>5</bitOffset>
              <bitWidth>1</bitWidth>
            </field>
            <field>
              <name>INITF</name>
              <bitOffset>6</bitOffset>
              <bitWidth>1</bitWidth>
            </field>
            <field>
              <name>INIT</name>
              <bitOffset>7</bitOffset>
              <bitWidth>1</bitWidth>
            </field>
            <field>
              <name>ALRAF</name>
              <bitOffset>8</bitOffset>
              <bitWidth>1</bitWidth>
            </field>
            <field>
              <name>WUTF</name>
              <bitOffset>10</bitOffset>
              <bitWidth>1</bitWidth>
            </field>
            <field>
              <name>TSF</name>
              <bitOffset>11</bitOffset>
              <bitWidth>1</bitWidth>
            </field>
            <field>
              <name>TSOVF</name>
              <bitOffset>12</bitOffset>
              <bitWidth>1</bitWidth>
            </field>
            <field>
              <name>TAMP1F</name>
              <bitOffset>13</bitOffset>
              <bitWidth>1</bitWidth>
            </field>
            <field>
              <name>TAMP2F</name>
              <bitOffset>14</bitOffset>
              <bitWidth>1</bitWidth>
            </field>
            <field>
              <name>TAMP3F</name>
              <bitOffset>15</bitOffset>
              <bitWidth>1</bitWidth>
            </field>
            <field>
              <name>RECALPF</name>
              <bitOffset>16</bitOffset>
              <bitWidth>1</bitWidth>
            </field>
          </fields>
        </register>
        <register>
          <name>PRER</name>
          <addressOffset>0x10</addressOffset>
          <size>0x20</size>
          <fields>
            <field>
              <name>PREDIV_S</name>
              <bitOffset>0</bitOffset>
              <bitWidth>15</bitWidth>
            </field>
            <field>
              <name>PREDIV_A</name>
              <bitOffset>16</bitOffset>
              <bitWidth>7</bitWidth>
            </field>
          </fields>
        </register>
        <register>
          <name>WUTR</name>
          <addressOffset>0x14</addressOffset>
          <size>0x20</size>
          <fields>
            <field>
              <name>WUT</name>
              <bitOffset>0</bitOffset>
              <bitWidth>16</bitWidth>
            </field>
          </fields>
        </register>
        <register>
          <name>ALRMAR</name>
          <addressOffset>0x1c</addressOffset>
          <size>0x20</size>
          <fields>
            <field>
              <name>SU</name>
              <bitOffset>0</bitOffset>
              <bitWidth>4</bitWidth>
            </field>
            <field>
              <name>ST</name>
              <bitOffset>4</bitOffset>
              <bitWidth>3</bitWidth>
            </field>
            <field>
              <name>MSK1</name>
              <bitOffset>7</bitOffset>
              <bitWidth>1</bitWidth>
            </field>
            <field>
              <name>MNU</name>
              <bitOffset>8</bitOffset>
              <bitWidth>4</bitWidth>
            </field>
            <field>
              <name>MNT</name>
              <bitOffset>12</bitOffset>
              <bitWidth>3</bitWidth>
            </field>
            <field>
              <name>MSK2</name>
              <bitOffset>15</bitOffset>
              <bitWidth>1</bitWidth>
            </field>
            <field>
              <name>HU</name>
              <bitOffset>16</bitOffset>
              <bitWidth>4</bitWidth>
            </field>
            <field>
              <name>HT</name>
              <bitOffset>20</bitOffset>
              <bitWidth>2</bitWidth>
            </field>
            <field>
              <name>PM</name>
              <bitOffset>22</bitOffset>
              <bitWidth>1</bitWidth>
            </field>
            <field>
              <name>MSK3</name>
              <bitOffset>23</bitOffset>
              <bitWidth>1</bitWidth>
            </field>
            <field>
              <name>DU</name>
              <bitOffset>24</bitOffset>
              <bitWidth>4</bitWidth>
            </field>
            <field>
              <name>DT</name>
              <bitOffset>28</bitOffset>
              <bitWidth>2</bitWidth>
            </field>
            <field>
              <name>WDSEL</name>
              <bitOffset>30</bitOffset>
              <bitWidth>1</bitWidth>
            </field>
            <field>
              <name>MSK4</name>
              <bitOffset>31</bitOffset>
              <bitWidth>1</bitWidth>
            </field>
          </fields>
        </register>
        <register>
          <name>WPR</name>
          <addressOffset>0x24</addressOffset>
          <size>0x20</size>
          <fields>
            <field>
              <name>KEY</name>
              <bitOffset>0</bitOffset>
              <bitWidth>8</bitWidth>
            </field>
          </fields>
        </register>
        <register>
          <name>SSR</name>
          <addressOffset>0x28</addressOffset>
          <size>0x20</size>
          <fields>
            <field>
              <name>SS</name>
              <bitOffset>0</bitOffset>
              <bitWidth>16</bitWidth>
            </field>
          </fields>
        </register>
        <register>
          <name>SHIFTR</name>
          <addressOffset>0x2c</addressOffset>
          <size>0x20</size>
          <fields>
            <field>
              <name>SUBFS</name>
              <bitOffset>0</bitOffset>
              <bitWidth>15</bitWidth>
            </field>
            <field>
              <name>ADD1S</name>
              <bitOffset>31</bitOffset>
              <bitWidth>1</bitWidth>
            </field>
          </fields>
        </register>
        <register>
          <name>TSTR</name>
          <addressOffset>0x30</addressOffset>
          <size>0x20</size>
          <fields>
            <field>
              <name>SU</name>
              <bitOffset>0</bitOffset>
              <bitWidth>4</bitWidth>
            </field>
            <field>
              <name>ST</name>
              <bitOffset>4</bitOffset>
              <bitWidth>3</bitWidth>
            </field>
            <field>
              <name>MNU</name>
              <bitOffset>8</bitOffset>
              <bitWidth>4</bitWidth>
            </field>
            <field>
              <name>MNT</name>
              <bitOffset>12</bitOffset>
              <bitWidth>3</bitWidth>
            </field>
            <field>
              <name>HU</name>
              <bitOffset>16</bitOffset>
              <bitWidth>4</bitWidth>
            </field>
            <field>
              <name>HT</name>
              <bitOffset>20</bitOffset>
              <bitWidth>2</bitWidth>
            </field>
            <field>
              <name>PM</name>
              <bitOffset>22</bitOffset>
              <bitWidth>1</bitWidth>
            </field>
          </fields>
        </register>
        <register>
          <name>TSDR</name>
          <addressOffset>0x34</addressOffset>
          <size>0x20</size>
          <fields>
            <field>
              <name>DU</name>
              <bitOffset>0</bitOffset>
              <bitWidth>4</bitWidth>
            </field>
            <field>
              <name>DT</name>
              <bitOffset>4</bitOffset>
              <bitWidth>2</bitWidth>
            </field>
            <field>
              <name>MU</name>
              <bitOffset>8</bitOffset>
              <bitWidth>4</bitWidth>
            </field>
            <field>
              <name>MT</name>
              <bitOffset>12</bitOffset>
              <bitWidth>1</bitWidth>
            </field>
            <field>
              <name>WDU</name>
              <bitOffset>13</bitOffset>
              <bitWidth>3</bitWidth>
            </field>
          </fields>
        </register>
        <register>
          <name>TSSSR</name>
          <addressOffset>0x38</addressOffset>
          <size>0x20</size>
          <fields>
            <field>
              <name>SS</name>
              <bitOffset>0</bitOffset>
              <bitWidth>16</bitWidth>
            </field>
          </fields>
        </register>
        <register>
          <name>CALR</name>
          <addressOffset>0x3c</addressOffset>
          <size>0x20</size>
          <fields>
            <field>
              <name>CALM</name>
              <bitOffset>0</bitOffset>
              <bitWidth>9</bitWidth>
            </field>
            <field>
              <name>CALW16</name>
              <bitOffset>13</bitOffset>
              <bitWidth>1</bitWidth>
            </field>
            <field>
              <name>CALW8</name>
              <bitOffset>14</bitOffset>
              <bitWidth>1</bitWidth>
            </field>
            <field>
              <name>CALP</name>
              <bitOffset>15</bitOffset>
              <bitWidth>1</bitWidth>
            </field>
          </fields>
        </register>
        <register>
          <name>TAFCR</name>
          <addressOffset>0x40</addressOffset>
          <size>0x20</size>
          <fields>
            <field>
              <name>TAMP1E</name>
              <bitOffset>0</bitOffset>
              <bitWidth>1</bitWidth>
            </field>
            <field>
              <name>TAMP1TRG</name>
              <bitOffset>1</bitOffset>
              <bitWidth>1</bitWidth>
            </field>
            <field>
              <name>TAMPIE</name>
              <bitOffset>2</bitOffset>
              <bitWidth>1</bitWidth>
            </field>
            <field>
              <name>TAMP2E</name>
              <bitOffset>3</bitOffset>
              <bitWidth>1</bitWidth>
            </field>
            <field>
              <name>TAMP2TRG</name>
              <bitOffset>4</bitOffset>
              <bitWidth>1</bitWidth>
            </field>
            <field>
              <name>TAMP3E</name>
              <bitOffset>5</bitOffset>
              <bitWidth>1</bitWidth>
            </field>
            <field>
              <name>TAMP3TRG</name>
              <bitOffset>6</bitOffset>
              <bitWidth>1</bitWidth>
            </field>
            <field>
              <name>TAMPTS</name>
              <bitOffset>7</bitOffset>
              <bitWidth>1</bitWidth>
            </field>
            <field>
              <name>TAMPFREQ</name>
              <bitOffset>8</bitOffset>
              <bitWidth>3</bitWidth>
            </field>
            <field>
              <name>TAMPFLT</name>
              <bitOffset>11</bitOffset>
              <bitWidth>2</bitWidth>
            </field>
            <field>
              <name>TAMPPRCH</name>
              <bitOffset>13</bitOffset>
              <bitWidth>2</bitWidth>
            </field>
            <field>
              <name>TAMPPUDIS</name>
              <bitOffset>15</bitOffset>
              <bitWidth>1</bitWidth>
            </field>
            <field>
              <name>PC13VALUE</name>
              <bitOffset>18</bitOffset>
              <bitWidth>1</bitWidth>
            </field>
            <field>
              <name>PC13MODE</name>
              <bitOffset>19</bitOffset>
              <bitWidth>1</bitWidth>
            </field>
            <field>
              <name>PC14VALUE</name>
              <bitOffset>20</bitOffset>
              <bitWidth>1</bitWidth>
            </field>
            <field>
              <name>PC14MODE</name>
              <bitOffset>21</bitOffset>
              <bitWidth>1</bitWidth>
            </field>
            <field>
              <name>PC15VALUE</name>
              <bitOffset>22</bitOffset>
              <bitWidth>1</bitWidth>
            </field>
            <field>
              <name>PC15MODE</name>
              <bitOffset>23</bitOffset>
              <bitWidth>1</bitWidth>
            </field>
          </fields>
        </register>
        <register>
          <name>ALRMASSR</name>
          <addressOffset>0x44</addressOffset>
          <size>0x20</size>
          <fields>
            <field>
              <name>SS</name>
              <bitOffset>0</bitOffset>
              <bitWidth>15</bitWidth>
            </field>
            <field>
              <name>MASKSS</name>
              <bitOffset>24</bitOffset>
              <bitWidth>4</bitWidth>
            </field>
          </fields>
        </register>
        <register>
          <name>BKP0R</name>
          <addressOffset>0x50</addressOffset>
          <size>0x20</size>
        </register>
        <register>
          <name>BKP1R</name>
          <addressOffset>0x54</addressOffset>
          <size>0x20</size>
        </register>
        <register>
          <name>BKP2R</name>
          <addressOffset>0x58</addressOffset>
          <size>0x20</size>
        </register>
        <register>
          <name>BKP3R</name>
          <addressOffset>0x5c</addressOffset>
          <size>0x20</size>
        </register>
        <register>
          <name>BKP4R</name>
          <addressOffset>0x60</addressOffset>
          <size>0x20</size>
        </register>
      </registers>
    </peripheral>
    <peripheral>
      <name>WWDG</name>
      <baseAddress>0x40002c00</baseAddress>
      <registers>
        <register>
          <name>CR</name>
          <addressOffset>0x0</addressOffset>
          <size>0x20</size>
          <fields>
            <field>
              <name>T</name>
              <bitOffset>0</bitOffset>
              <bitWidth>7</bitWidth>
            </field>
            <field>
              <name>WDGA</name>
              <bitOffset>7</bitOffset>
              <bitWidth>1</bitWidth>
            </field>
          </fields>
        </register>
        <register>
          <name>CFR</name>
          <addressOffset>0x4</addressOffset>
          <size>0x20</size>
          <fields>
            <field>
              <name>W</name>
              <bitOffset>0</bitOffset>
              <bitWidth>7</bitWidth>
            </field>
            <field>
              <name>WDGTB</name>
              <bitOffset>7</bitOffset>
              <bitWidth>2</bitWidth>
            </field>
            <field>
              <name>EWI</name>
              <bitOffset>9</bitOffset>
              <bitWidth>1</bitWidth>
            </field>
          </fields>
        </register>
        <register>
          <name>SR</name>
          <addressOffset>0x8</addressOffset>
          <size>0x20</size>
          <fields>
            <field>
              <name>EWIF</name>
              <bitOffset>0</bitOffset>
              <bitWidth>1</bitWidth>
            </field>
          </fields>
        </register>
      </registers>
    </peripheral>
    <peripheral>
      <name>IWDG</name>
      <baseAddress>0x40003000</baseAddress>
      <registers>
        <register>
          <name>KR</name>
          <addressOffset>0x0</addressOffset>
          <size>0x20</size>
          <fields>
            <field>
              <name>KEY</name>
              <bitOffset>0</bitOffset>
              <bitWidth>16</bitWidth>
            </field>
          </fields>
        </register>
        <register>
          <name>PR</name>
          <addressOffset>0x4</addressOffset>
          <size>0x20</size>
          <fields>
            <field>
              <name>PR</name>
              <bitOffset>0</bitOffset>
              <bitWidth>3</bitWidth>
            </field>
          </fields>
        </register>
        <register>
          <name>RLR</name>
          <addressOffset>0x8</addressOffset>
          <size>0x20</size>
          <fields>
            <field>
              <name>RL</name>
              <bitOffset>0</bitOffset>
              <bitWidth>12</bitWidth>
            </field>
          </fields>
        </register>
        <register>
          <name>SR</name>
          <addressOffset>0xc</addressOffset>
          <size>0x20</size>
          <fields>
            <field>
              <name>PVU</name>
              <bitOffset>0</bitOffset>
              <bitWidth>1</bitWidth>
            </field>
            <field>
              <name>RVU</name>
              <bitOffset>1</bitOffset>
              <bitWidth>1</bitWidth>
            </field>
            <field>
              <name>WVU</name>
              <bitOffset>2</bitOffset>
              <bitWidth>1</bitWidth>
            </field>
          </fields>
        </register>
        <register>
          <name>WINR</name>
          <addressOffset>0x10</addressOffset>
          <size>0x20</size>
          <fields>
            <field>
              <name>WIN</name>
              <bitOffset>0</bitOffset>
              <bitWidth>12</bitWidth>
            </field>
          </fields>
        </register>
      </registers>
    </peripheral>
    <peripheral>
      <name>SPI2</name>
      <baseAddress>0x40003800</baseAddress>
      <registers>
        <register>
          <name>CR1</name>
          <addressOffset>0x0</addressOffset>
          <size>0x20</size>
          <fields>
            <field>
              <name>CPHA</name>
              <bitOffset>0</bitOffset>
              <bitWidth>1</bitWidth>
            </field>
            <field>
              <name>CPOL</name>
              <bitOffset>1</bitOffset>
              <bitWidth>1</bitWidth>
            </field>
            <field>
              <name>MSTR</name>
              <bitOffset>2</bitOffset>
              <bitWidth>1</bitWidth>
            </field>
            <field>
              <name>BR</name>
              <bitOffset>3</bitOffset>
              <bitWidth>3</bitWidth>
            </field>
            <field>
              <name>SPE</name>
              <bitOffset>6</bitOffset>
              <bitWidth>1</bitWidth>
            </field>
            <field>
              <name>LSBFIRST</name>
              <bitOffset>7</bitOffset>
              <bitWidth>1</bitWidth>
            </field>
            <field>
              <name>SSI</name>
              <bitOffset>8</bitOffset>
              <bitWidth>1</bitWidth>
            </field>
            <field>
              <name>SSM</name>
              <bitOffset>9</bitOffset>
              <bitWidth>1</bitWidth>
            </field>
            <field>
              <name>RXONLY</name>
              <bitOffset>10</bitOffset>
              <bitWidth>1</bitWidth>
            </field>
            <field>
              <name>CRCL</name>
              <bitOffset>11</bitOffset>
              <bitWidth>1</bitWidth>
            </field>
            <field>
              <name>CRCNEXT</name>
              <bitOffset>12</bitOffset>
              <bitWidth>1</bitWidth>
            </field>
            <field>
              <name>CRCEN</name>
              <bitOffset>13</bitOffset>
              <bitWidth>1</bitWidth>
            </field>
            <field>
              <name>BIDIOE</name>
              <bitOffset>14</bitOffset>
              <bitWidth>1</bitWidth>
            </field>
            <field>
              <name>BIDIMODE</name>
              <bitOffset>15</bitOffset>
              <bitWidth>1</bitWidth>
            </field>
          </fields>
        </register>
        <register>
          <name>CR2</name>
          <addressOffset>0x4</addressOffset>
          <size>0x20</size>
          <fields>
            <field>
              <name>RXDMAEN</name>
              <bitOffset>0</bitOffset>
              <bitWidth>1</bitWidth>
            </field>
            <field>
              <name>TXDMAEN</name>
              <bitOffset>1</bitOffset>
              <bitWidth>1</bitWidth>
            </field>
            <field>
              <name>SSOE</name>
              <bitOffset>2</bitOffset>
              <bitWidth>1</bitWidth>
            </field>
            <field>
              <name>NSSP</name>
              <bitOffset>3</bitOffset>
              <bitWidth>1</bitWidth>
            </field>
            <field>
              <name>FRF</name>
              <bitOffset>4</bitOffset>
              <bitWidth>1</bitWidth>
            </field>
            <field>
              <name>ERRIE</name>
              <bitOffset>5</bitOffset>
              <bitWidth>1</bitWidth>
            </field>
            <field>
              <name>RXNEIE</name>
              <bitOffset>6</bitOffset>
              <bitWidth>1</bitWidth>
            </field>
            <field>
              <name>TXEIE</name>
              <bitOffset>7</bitOffset>
              <bitWidth>1</bitWidth>
            </field>
            <field>
              <name>DS</name>
              <bitOffset>8</bitOffset>
              <bitWidth>4</bitWidth>
            </field>
            <field>
              <name>FRXTH</name>
              <bitOffset>12</bitOffset>
              <bitWidth>1</bitWidth>
            </field>
            <field>
              <name>LDMARX</name>
              <bitOffset>13</bitOffset>
              <bitWidth>1</bitWidth>
            </field>
            <field>
              <name>LDMATX</name>
              <bitOffset>14</bitOffset>
              <bitWidth>1</bitWidth>
            </field>
          </fields>
        </register>
        <register>
          <name>SR</name>
          <addressOffset>0x8</addressOffset>
          <size>0x20</size>
          <fields>
            <field>
              <name>RXNE</name>
              <bitOffset>0</bitOffset>
              <bitWidth>1</bitWidth>
            </field>
            <field>
              <name>TXE</name>
              <bitOffset>1</bitOffset>
              <bitWidth>1</bitWidth>
            </field>
            <field>
              <name>CHSIDE</name>
              <bitOffset>2</bitOffset>
              <bitWidth>1</bitWidth>
            </field>
            <field>
              <name>UDR</name>
              <bitOffset>3</bitOffset>
              <bitWidth>1</bitWidth>
            </field>
            <field>
              <name>CRCERR</name>
              <bitOffset>4</bitOffset>
              <bitWidth>1</bitWidth>
            </field>
            <field>
              <name>MODF</name>
              <bitOffset>5</bitOffset>
              <bitWidth>1</bitWidth>
            </field>
            <field>
              <name>OVR</name>
              <bitOffset>6</bitOffset>
              <bitWidth>1</bitWidth>
            </field>
            <field>
              <name>BSY</name>
              <bitOffset>7</bitOffset>
              <bitWidth>1</bitWidth>
            </field>
            <field>
              <name>FRE</name>
              <bitOffset>8</bitOffset>
              <bitWidth>1</bitWidth>
            </field>
            <field>
              <name>FRLVL</name>
              <bitOffset>9</bitOffset>
              <bitWidth>2</bitWidth>
            </field>
            <field>
              <name>FTLVL</name>
              <bitOffset>11</bitOffset>
              <bitWidth>2</bitWidth>
            </field>
          </fields>
        </register>
        <register>
          <name>DR</name>
          <addressOffset>0xc</addressOffset>
          <size>0x20</size>
          <fields>
            <field>
              <name>DR</name>
              <bitOffset>0</bitOffset>
              <bitWidth>32</bitWidth>
            </field>
          </fields>
        </register>
        <register>
          <name>CRCPR</name>
          <addressOffset>0x10</addressOffset>
          <size>0x20</size>
          <fields>
            <field>
              <name>CRCPOLY</name>
              <bitOffset>0</bitOffset>
              <bitWidth>32</bitWidth>
            </field>
          </fields>
        </register>
        <register>
          <name>RXCRCR</name>
          <addressOffset>0x14</addressOffset>
          <size>0x20</size>
          <fields>
            <field>
              <name>RXCRC</name>
              <bitOffset>0</bitOffset>
              <bitWidth>32</bitWidth>
            </field>
          </fields>
        </register>
        <register>
          <name>TXCRCR</name>
          <addressOffset>0x18</addressOffset>
          <size>0x20</size>
          <fields>
            <field>
              <name>TXCRC</name>
              <bitOffset>0</bitOffset>
              <bitWidth>32</bitWidth>
            </field>
          </fields>
        </register>
        <register>
          <name>I2SCFGR</name>
          <addressOffset>0x1c</addressOffset>
          <size>0x20</size>
          <fields>
            <field>
              <name>CHLEN</name>
              <bitOffset>0</bitOffset>
              <bitWidth>1</bitWidth>
            </field>
            <field>
              <name>DATLEN</name>
              <bitOffset>1</bitOffset>
              <bitWidth>2</bitWidth>
            </field>
            <field>
              <name>CKPOL</name>
              <bitOffset>3</bitOffset>
              <bitWidth>1</bitWidth>
            </field>
            <field>
              <name>I2SSTD</name>
              <bitOffset>4</bitOffset>
              <bitWidth>2</bitWidth>
            </field>
            <field>
              <name>PCMSYNC</name>
              <bitOffset>7</bitOffset>
              <bitWidth>1</bitWidth>
            </field>
            <field>
              <name>I2SCFG</name>
              <bitOffset>8</bitOffset>
              <bitWidth>2</bitWidth>
            </field>
            <field>
              <name>I2SE</name>
              <bitOffset>10</bitOffset>
              <bitWidth>1</bitWidth>
            </field>
            <field>
              <name>I2SMOD</name>
              <bitOffset>11</bitOffset>
              <bitWidth>1</bitWidth>
            </field>
          </fields>
        </register>
        <register>
          <name>I2SPR</name>
          <addressOffset>0x20</addressOffset>
          <size>0x20</size>
          <fields>
            <field>
              <name>I2SDIV</name>
              <bitOffset>0</bitOffset>
              <bitWidth>8</bitWidth>
            </field>
            <field>
              <name>ODD</name>
              <bitOffset>8</bitOffset>
              <bitWidth>1</bitWidth>
            </field>
            <field>
              <name>MCKOE</name>
              <bitOffset>9</bitOffset>
              <bitWidth>1</bitWidth>
            </field>
          </fields>
        </register>
      </registers>
    </peripheral>
    <peripheral>
      <name>USART2</name>
      <baseAddress>0x40004400</baseAddress>
      <registers>
        <register>
          <name>CR1</name>
          <addressOffset>0x0</addressOffset>
          <size>0x20</size>
          <fields>
            <field>
              <name>UE</name>
              <bitOffset>0</bitOffset>
              <bitWidth>1</bitWidth>
            </field>
            <field>
              <name>UESM</name>
              <bitOffset>1</bitOffset>
              <bitWidth>1</bitWidth>
            </field>
            <field>
              <name>RE</name>
              <bitOffset>2</bitOffset>
              <bitWidth>1</bitWidth>
            </field>
            <field>
              <name>TE</name>
              <bitOffset>3</bitOffset>
              <bitWidth>1</bitWidth>
            </field>
            <field>
              <name>IDLEIE</name>
              <bitOffset>4</bitOffset>
              <bitWidth>1</bitWidth>
            </field>
            <field>
              <name>RXNEIE</name>
              <bitOffset>5</bitOffset>
              <bitWidth>1</bitWidth>
            </field>
            <field>
              <name>TCIE</name>
              <bitOffset>6</bitOffset>
              <bitWidth>1</bitWidth>
            </field>
            <field>
              <name>TXEIE</name>
              <bitOffset>7</bitOffset>
              <bitWidth>1</bitWidth>
            </field>
            <field>
              <name>PEIE</name>
              <bitOffset>8</bitOffset>
              <bitWidth>1</bitWidth>
            </field>
            <field>
              <name>PS</name>
              <bitOffset>9</bitOffset>
              <bitWidth>1</bitWidth>
            </field>
            <field>
              <name>PCE</name>
              <bitOffset>10</bitOffset>
              <bitWidth>1</bitWidth>
            </field>
            <field>
              <name>WAKE</name>
              <bitOffset>11</bitOffset>
              <bitWidth>1</bitWidth>
            </field>
            <field>
              <name>M0</name>
              <bitOffset>12</bitOffset>
              <bitWidth>1</bitWidth>
            </field>
            <field>
              <name>MME</name>
              <bitOffset>13</bitOffset>
              <bitWidth>1</bitWidth>
            </field>
            <field>
              <name>CMIE</name>
              <bitOffset>14</bitOffset>
              <bitWidth>1</bitWidth>
            </field>
            <field>
              <name>OVER8</name>
              <bitOffset>15</bitOffset>
              <bitWidth>1</bitWidth>
            </field>
            <field>
              <name>DEDT</name>
              <bitOffset>16</bitOffset>
              <bitWidth>5</bitWidth>
            </field>
            <field>
              <name>DEAT</name>
              <bitOffset>21</bitOffset>
              <bitWidth>5</bitWidth>
            </field>
            <field>
              <name>RTOIE</name>
              <bitOffset>26</bitOffset>
              <bitWidth>1</bitWidth>
            </field>
            <field>
              <name>EOBIE</name>
              <bitOffset>27</bitOffset>
              <bitWidth>1</bitWidth>
            </field>
            <field>
              <name>M1</name>
              <bitOffset>28</bitOffset>
              <bitWidth>1</bitWidth>
            </field>
          </fields>
        </register>
        <register>
          <name>CR2</name>
          <addressOffset>0x4</addressOffset>
          <size>0x20</size>
          <fields>
            <field>
              <name>ADDM7</name>
              <bitOffset>4</bitOffset>
              <bitWidth>1</bitWidth>
            </field>
            <field>
              <name>LBDL</name>
              <bitOffset>5</bitOffset>
              <bitWidth>1</bitWidth>
            </field>
            <field>
              <name>LBDIE</name>
              <bitOffset>6</bitOffset>
              <bitWidth>1</bitWidth>
            </field>
            <field>
              <name>LBCL</name>
              <bitOffset>8</bitOffset>
              <bitWidth>1</bitWidth>
            </field>
            <field>
              <name>CPHA</name>
              <bitOffset>9</bitOffset>
              <bitWidth>1</bitWidth>
            </field>
            <field>
              <name>CPOL</name>
              <bitOffset>10</bitOffset>
              <bitWidth>1</bitWidth>
            </field>
            <field>
              <name>CLKEN</name>
              <bitOffset>11</bitOffset>
              <bitWidth>1</bitWidth>
            </field>
            <field>
              <name>STOP</name>
              <bitOffset>12</bitOffset>
              <bitWidth>2</bitWidth>
            </field>
            <field>
              <name>LINEN</name>
              <bitOffset>14</bitOffset>
              <bitWidth>1</bitWidth>
            </field>
            <field>
              <name>SWAP</name>
              <bitOffset>15</bitOffset>
              <bitWidth>1</bitWidth>
            </field>
            <field>
              <name>RXINV</name>
              <bitOffset>16</bitOffset>
              <bitWidth>1</bitWidth>
            </field>
            <field>
              <name>TXINV</name>
              <bitOffset>17</bitOffset>
              <bitWidth>1</bitWidth>
            </field>
            <field>
              <name>DATAINV</name>
              <bitOffset>18</bitOffset>
              <bitWidth>1</bitWidth>
            </field>
            <field>
              <name>MSBFIRST</name>
              <bitOffset>19</bitOffset>
              <bitWidth>1</bitWidth>
            </field>
            <field>
              <name>ABREN</name>
              <bitOffset>20</bitOffset>
              <bitWidth>1</bitWidth>
            </field>
            <field>
              <name>ABRMODE</name>
              <bitOffset>21</bitOffset>
              <bitWidth>2</bitWidth>
            </field>
            <field>
              <name>RTOEN</name>
              <bitOffset>23</bitOffset>
              <bitWidth>1</bitWidth>
            </field>
            <field>
              <name>ADD</name>
              <bitOffset>24</bitOffset>
              <bitWidth>8</bitWidth>
            </field>
          </fields>
        </register>
        <register>
          <name>CR3</name>
          <addressOffset>0x8</addressOffset>
          <size>0x20</size>
          <fields>
            <field>
              <name>EIE</name>
              <bitOffset>0</bitOffset>
              <bitWidth>1</bitWidth>
            </field>
            <field>
              <name>IREN</name>
              <bitOffset>1</bitOffset>
              <bitWidth>1</bitWidth>
            </field>
            <field>
              <name>IRLP</name>
              <bitOffset>2</bitOffset>
              <bitWidth>1</bitWidth>
            </field>
            <field>
              <name>HDSEL</name>
              <bitOffset>3</bitOffset>
              <bitWidth>1</bitWidth>
            </field>
            <field>
              <name>NACK</name>
              <bitOffset>4</bitOffset>
              <bitWidth>1</bitWidth>
            </field>
            <field>
              <name>SCEN</name>
              <bitOffset>5</bitOffset>
              <bitWidth>1</bitWidth>
            </field>
            <field>
              <name>DMAR</name>
              <bitOffset>6</bitOffset>
              <bitWidth>1</bitWidth>
            </field>
            <field>
              <name>DMAT</name>
              <bitOffset>7</bitOffset>
              <bitWidth>1</bitWidth>
            </field>
            <field>
              <name>RTSE</name>
              <bitOffset>8</bitOffset>
              <bitWidth>1</bitWidth>
            </field>
            <field>
              <name>CTSE</name>
              <bitOffset>9</bitOffset>
              <bitWidth>1</bitWidth>
            </field>
            <field>
              <name>CTSIE</name>
              <bitOffset>10</bitOffset>
              <bitWidth>1</bitWidth>
            </field>
            <field>
              <name>ONEBIT</name>
              <bitOffset>11</bitOffset>
              <bitWidth>1</bitWidth>
            </field>
            <field>
              <name>OVRDIS</name>
              <bitOffset>12</bitOffset>
              <bitWidth>1</bitWidth>
            </field>
            <field>
              <name>DDRE</name>
              <bitOffset>13</bitOffset>
              <bitWidth>1</bitWidth>
            </field>
            <field>
              <name>DEM</name>
              <bitOffset>14</bitOffset>
              <bitWidth>1</bitWidth>
            </field>
            <field>
              <name>DEP</name>
              <bitOffset>15</bitOffset>
              <bitWidth>1</bitWidth>
            </field>
            <field>
              <name>SCARCNT</name>
              <bitOffset>17</bitOffset>
              <bitWidth>3</bitWidth>
            </field>
            <field>
              <name>WUS</name>
              <bitOffset>20</bitOffset>
              <bitWidth>2</bitWidth>
            </field>
            <field>
              <name>WUFIE</name>
              <bitOffset>22</bitOffset>
              <bitWidth>1</bitWidth>
            </field>
          </fields>
        </register>
        <register>
          <name>BRR</name>
          <addressOffset>0xc</addressOffset>
          <size>0x20</size>
          <fields>
            <field>
              <name>DIV_FRACTION</name>
              <bitOffset>0</bitOffset>
              <bitWidth>4</bitWidth>
            </field>
            <field>
              <name>DIV_MANTISSA</name>
              <bitOffset>4</bitOffset>
              <bitWidth>12</bitWidth>
            </field>
          </fields>
        </register>
        <register>
          <name>GTPR</name>
          <addressOffset>0x10</addressOffset>
          <size>0x20</size>
          <fields>
            <field>
              <name>PSC</name>
              <bitOffset>0</bitOffset>
              <bitWidth>8</bitWidth>
            </field>
            <field>
              <name>GT</name>
              <bitOffset>8</bitOffset>
              <bitWidth>8</bitWidth>
            </field>
          </fields>
        </register>
        <register>
          <name>RTOR</name>
          <addressOffset>0x14</addressOffset>
          <size>0x20</size>
          <fields>
            <field>
              <name>RTO</name>
              <bitOffset>0</bitOffset>
              <bitWidth>24</bitWidth>
            </field>
            <field>
              <name>BLEN</name>
              <bitOffset>24</bitOffset>
              <bitWidth>8</bitWidth>
            </field>
          </fields>
        </register>
        <register>
          <name>RQR</name>
          <addressOffset>0x18</addressOffset>
          <size>0x20</size>
          <fields>
            <field>
              <name>ABRRQ</name>
              <bitOffset>0</bitOffset>
              <bitWidth>1</bitWidth>
            </field>
            <field>
              <name>SBKRQ</name>
              <bitOffset>1</bitOffset>
              <bitWidth>1</bitWidth>
            </field>
            <field>
              <name>MMRQ</name>
              <bitOffset>2</bitOffset>
              <bitWidth>1</bitWidth>
            </field>
            <field>
              <name>RXFRQ</name>
              <bitOffset>3</bitOffset>
              <bitWidth>1</bitWidth>
            </field>
            <field>
              <name>TXFRQ</name>
              <bitOffset>4</bitOffset>
              <bitWidth>1</bitWidth>
            </field>
          </fields>
        </register>
        <register>
          <name>ISR</name>
          <addressOffset>0x1c</addressOffset>
          <size>0x20</size>
          <fields>
            <field>
              <name>PE</name>
              <bitOffset>0</bitOffset>
              <bitWidth>1</bitWidth>
            </field>
            <field>
              <name>FE</name>
              <bitOffset>1</bitOffset>
              <bitWidth>1</bitWidth>
            </field>
            <field>
              <name>NE</name>
              <bitOffset>2</bitOffset>
              <bitWidth>1</bitWidth>
            </field>
            <field>
              <name>ORE</name>
              <bitOffset>3</bitOffset>
              <bitWidth>1</bitWidth>
            </field>
            <field>
              <name>IDLE</name>
              <bitOffset>4</bitOffset>
              <bitWidth>1</bitWidth>
            </field>
            <field>
              <name>RXNE</name>
              <bitOffset>5</bitOffset>
              <bitWidth>1</bitWidth>
            </field>
            <field>
              <name>TC</name>
              <bitOffset>6</bitOffset>
              <bitWidth>1</bitWidth>
            </field>
            <field>
              <name>TXE</name>
              <bitOffset>7</bitOffset>
              <bitWidth>1</bitWidth>
            </field>
            <field>
              <name>LBDF</name>
              <bitOffset>8</bitOffset>
              <bitWidth>1</bitWidth>
            </field>
            <field>
              <name>CTSIF</name>
              <bitOffset>9</bitOffset>
              <bitWidth>1</bitWidth>
            </field>
            <field>
              <name>CTS</name>
              <bitOffset>10</bitOffset>
              <bitWidth>1</bitWidth>
            </field>
            <field>
              <name>RTOF</name>
              <bitOffset>11</bitOffset>
              <bitWidth>1</bitWidth>
            </field>
            <field>
              <name>EOBF</name>
              <bitOffset>12</bitOffset>
              <bitWidth>1</bitWidth>
            </field>
            <field>
              <name>ABRE</name>
              <bitOffset>14</bitOffset>
              <bitWidth>1</bitWidth>
            </field>
            <field>
              <name>ABRF</name>
              <bitOffset>15</bitOffset>
              <bitWidth>1</bitWidth>
            </field>
            <field>
              <name>BUSY</name>
              <bitOffset>16</bitOffset>
              <bitWidth>1</bitWidth>
            </field>
            <field>
              <name>CMF</name>
              <bitOffset>17</bitOffset>
              <bitWidth>1</bitWidth>
            </field>
            <field>
              <name>SBKF</name>
              <bitOffset>18</bitOffset>
              <bitWidth>1</bitWidth>
            </field>
            <field>
              <name>RWU</name>
              <bitOffset>19</bitOffset>
              <bitWidth>1</bitWidth>
            </field>
            <field>
              <name>WUF</name>
              <bitOffset>20</bitOffset>
              <bitWidth>1</bitWidth>
            </field>
            <field>
              <name>TEACK</name>
              <bitOffset>21</bitOffset>
              <bitWidth>1</bitWidth>
            </field>
            <field>
              <name>REACK</name>
              <bitOffset>22</bitOffset>
              <bitWidth>1</bitWidth>
            </field>
          </fields>
        </register>
        <register>
          <name>ICR</name>
          <addressOffset>0x20</addressOffset>
          <size>0x20</size>
          <fields>
            <field>
              <name>PECF</name>
              <bitOffset>0</bitOffset>
              <bitWidth>1</bitWidth>
            </field>
            <field>
              <name>FECF</name>
              <bitOffset>1</bitOffset>
              <bitWidth>1</bitWidth>
            </field>
            <field>
              <name>NCF</name>
              <bitOffset>2</bitOffset>
              <bitWidth>1</bitWidth>
            </field>
            <field>
              <name>ORECF</name>
              <bitOffset>3</bitOffset>
              <bitWidth>1</bitWidth>
            </field>
            <field>
              <name>IDLECF</name>
              <bitOffset>4</bitOffset>
              <bitWidth>1</bitWidth>
            </field>
            <field>
              <name>TCCF</name>
              <bitOffset>6</bitOffset>
              <bitWidth>1</bitWidth>
            </field>
            <field>
              <name>LBDCF</name>
              <bitOffset>8</bitOffset>
              <bitWidth>1</bitWidth>
            </field>
            <field>
              <name>CTSCF</name>
              <bitOffset>9</bitOffset>
              <bitWidth>1</bitWidth>
            </field>
            <field>
              <name>RTOCF</name>
              <bitOffset>11</bitOffset>
              <bitWidth>1</bitWidth>
            </field>
            <field>
              <name>EOBCF</name>
              <bitOffset>12</bitOffset>
              <bitWidth>1</bitWidth>
            </field>
            <field>
              <name>CMCF</name>
              <bitOffset>17</bitOffset>
              <bitWidth>1</bitWidth>
            </field>
            <field>
              <name>WUCF</name>
              <bitOffset>20</bitOffset>
              <bitWidth>1</bitWidth>
            </field>
          </fields>
        </register>
        <register>
          <name>RDR</name>
          <addressOffset>0x24</addressOffset>
          <size>0x10</size>
        </register>
        <register>
          <name>TDR</name>
          <addressOffset>0x28</addressOffset>
          <size>0x10</size>
        </register>
      </registers>
    </peripheral>
    <peripheral>
      <name>USART3</name>
      <baseAddress>0x40004800</baseAddress>
      <registers>
        <register>
          <name>CR1</name>
          <addressOffset>0x0</addressOffset>
          <size>0x20</size>
          <fields>
            <field>
              <name>UE</name>
              <bitOffset>0</bitOffset>
              <bitWidth>1</bitWidth>
            </field>
            <field>
              <name>UESM</name>
              <bitOffset>1</bitOffset>
              <bitWidth>1</bitWidth>
            </field>
            <field>
              <name>RE</name>
              <bitOffset>2</bitOffset>
              <bitWidth>1</bitWidth>
            </field>
            <field>
              <name>TE</name>
              <bitOffset>3</bitOffset>
              <bitWidth>1</bitWidth>
            </field>
            <field>
              <name>IDLEIE</name>
              <bitOffset>4</bitOffset>
              <bitWidth>1</bitWidth>
            </field>
            <field>
              <name>RXNEIE</name>
              <bitOffset>5</bitOffset>
              <bitWidth>1</bitWidth>
            </field>
            <field>
              <name>TCIE</name>
              <bitOffset>6</bitOffset>
              <bitWidth>1</bitWidth>
            </field>
            <field>
              <name>TXEIE</name>
              <bitOffset>7</bitOffset>
              <bitWidth>1</bitWidth>
            </field>
            <field>
              <name>PEIE</name>
              <bitOffset>8</bitOffset>
              <bitWidth>1</bitWidth>
            </field>
            <field>
              <name>PS</name>
              <bitOffset>9</bitOffset>
              <bitWidth>1</bitWidth>
            </field>
            <field>
              <name>PCE</name>
              <bitOffset>10</bitOffset>
              <bitWidth>1</bitWidth>
            </field>
            <field>
              <name>WAKE</name>
              <bitOffset>11</bitOffset>
              <bitWidth>1</bitWidth>
            </field>
            <field>
              <name>M0</name>
              <bitOffset>12</bitOffset>
              <bitWidth>1</bitWidth>
            </field>
            <field>
              <name>MME</name>
              <bitOffset>13</bitOffset>
              <bitWidth>1</bitWidth>
            </field>
            <field>
              <name>CMIE</name>
              <bitOffset>14</bitOffset>
              <bitWidth>1</bitWidth>
            </field>
            <field>
              <name>OVER8</name>
              <bitOffset>15</bitOffset>
              <bitWidth>1</bitWidth>
            </field>
            <field>
              <name>DEDT</name>
              <bitOffset>16</bitOffset>
              <bitWidth>5</bitWidth>
            </field>
            <field>
              <name>DEAT</name>
              <bitOffset>21</bitOffset>
              <bitWidth>5</bitWidth>
            </field>
            <field>
              <name>RTOIE</name>
              <bitOffset>26</bitOffset>
              <bitWidth>1</bitWidth>
            </field>
            <field>
              <name>EOBIE</name>
              <bitOffset>27</bitOffset>
              <bitWidth>1</bitWidth>
            </field>
            <field>
              <name>M1</name>
              <bitOffset>28</bitOffset>
              <bitWidth>1</bitWidth>
            </field>
          </fields>
        </register>
        <register>
          <name>CR2</name>
          <addressOffset>0x4</addressOffset>
          <size>0x20</size>
          <fields>
            <field>
              <name>ADDM7</name>
              <bitOffset>4</bitOffset>
              <bitWidth>1</bitWidth>
            </field>
            <field>
              <name>LBDL</name>
              <bitOffset>5</bitOffset>
              <bitWidth>1</bitWidth>
            </field>
            <field>
              <name>LBDIE</name>
              <bitOffset>6</bitOffset>
              <bitWidth>1</bitWidth>
            </field>
            <field>
              <name>LBCL</name>
              <bitOffset>8</bitOffset>
              <bitWidth>1</bitWidth>
            </field>
            <field>
              <name>CPHA</name>
              <bitOffset>9</bitOffset>
              <bitWidth>1</bitWidth>
            </field>
            <field>
              <name>CPOL</name>
              <bitOffset>10</bitOffset>
              <bitWidth>1</bitWidth>
            </field>
            <field>
              <name>CLKEN</name>
              <bitOffset>11</bitOffset>
              <bitWidth>1</bitWidth>
            </field>
            <field>
              <name>STOP</name>
              <bitOffset>12</bitOffset>
              <bitWidth>2</bitWidth>
            </field>
            <field>
              <name>LINEN</name>
              <bitOffset>14</bitOffset>
              <bitWidth>1</bitWidth>
            </field>
            <field>
              <name>SWAP</name>
              <bitOffset>15</bitOffset>
              <bitWidth>1</bitWidth>
            </field>
            <field>
              <name>RXINV</name>
              <bitOffset>16</bitOffset>
              <bitWidth>1</bitWidth>
            </field>
            <field>
              <name>TXINV</name>
              <bitOffset>17</bitOffset>
              <bitWidth>1</bitWidth>
            </field>
            <field>
              <name>DATAINV</name>
              <bitOffset>18</bitOffset>
              <bitWidth>1</bitWidth>
            </field>
            <field>
              <name>MSBFIRST</name>
              <bitOffset>19</bitOffset>
              <bitWidth>1</bitWidth>
            </field>
            <field>
              <name>ABREN</name>
              <bitOffset>20</bitOffset>
              <bitWidth>1</bitWidth>
            </field>
            <field>
              <name>ABRMODE</name>
              <bitOffset>21</bitOffset>
              <bitWidth>2</bitWidth>
            </field>
            <field>
              <name>RTOEN</name>
              <bitOffset>23</bitOffset>
              <bitWidth>1</bitWidth>
            </field>
            <field>
              <name>ADD</name>
              <bitOffset>24</bitOffset>
              <bitWidth>8</bitWidth>
            </field>
          </fields>
        </register>
        <register>
          <name>CR3</name>
          <addressOffset>0x8</addressOffset>
          <size>0x20</size>
          <fields>
            <field>
              <name>EIE</name>
              <bitOffset>0</bitOffset>
              <bitWidth>1</bitWidth>
            </field>
            <field>
              <name>IREN</name>
              <bitOffset>1</bitOffset>
              <bitWidth>1</bitWidth>
            </field>
            <field>
              <name>IRLP</name>
              <bitOffset>2</bitOffset>
              <bitWidth>1</bitWidth>
            </field>
            <field>
              <name>HDSEL</name>
              <bitOffset>3</bitOffset>
              <bitWidth>1</bitWidth>
            </field>
            <field>
              <name>NACK</name>
              <bitOffset>4</bitOffset>
              <bitWidth>1</bitWidth>
            </field>
            <field>
              <name>SCEN</name>
              <bitOffset>5</bitOffset>
              <bitWidth>1</bitWidth>
            </field>
            <field>
              <name>DMAR</name>
              <bitOffset>6</bitOffset>
              <bitWidth>1</bitWidth>
            </field>
            <field>
              <name>DMAT</name>
              <bitOffset>7</bitOffset>
              <bitWidth>1</bitWidth>
            </field>
            <field>
              <name>RTSE</name>
              <bitOffset>8</bitOffset>
              <bitWidth>1</bitWidth>
            </field>
            <field>
              <name>CTSE</name>
              <bitOffset>9</bitOffset>
              <bitWidth>1</bitWidth>
            </field>
            <field>
              <name>CTSIE</name>
              <bitOffset>10</bitOffset>
              <bitWidth>1</bitWidth>
            </field>
            <field>
              <name>ONEBIT</name>
              <bitOffset>11</bitOffset>
              <bitWidth>1</bitWidth>
            </field>
            <field>
              <name>OVRDIS</name>
              <bitOffset>12</bitOffset>
              <bitWidth>1</bitWidth>
            </field>
            <field>
              <name>DDRE</name>
              <bitOffset>13</bitOffset>
              <bitWidth>1</bitWidth>
            </field>
            <field>
              <name>DEM</name>
              <bitOffset>14</bitOffset>
              <bitWidth>1</bitWidth>
            </field>
            <field>
              <name>DEP</name>
              <bitOffset>15</bitOffset>
              <bitWidth>1</bitWidth>
            </field>
            <field>
              <name>SCARCNT</name>
              <bitOffset>17</bitOffset>
              <bitWidth>3</bitWidth>
            </field>
            <field>
              <name>WUS</name>
              <bitOffset>20</bitOffset>
              <bitWidth>2</bitWidth>
            </field>
            <field>
              <name>WUFIE</name>
              <bitOffset>22</bitOffset>
              <bitWidth>1</bitWidth>
            </field>
          </fields>
        </register>
        <register>
          <name>BRR</name>
          <addressOffset>0xc</addressOffset>
          <size>0x20</size>
          <fields>
            <field>
              <name>DIV_FRACTION</name>
              <bitOffset>0</bitOffset>
              <bitWidth>4</bitWidth>
            </field>
            <field>
              <name>DIV_MANTISSA</name>
              <bitOffset>4</bitOffset>
              <bitWidth>12</bitWidth>
            </field>
          </fields>
        </register>
        <register>
          <name>GTPR</name>
          <addressOffset>0x10</addressOffset>
          <size>0x20</size>
          <fields>
            <field>
              <name>PSC</name>
              <bitOffset>0</bitOffset>
              <bitWidth>8</bitWidth>
            </field>
            <field>
              <name>GT</name>
              <bitOffset>8</bitOffset>
              <bitWidth>8</bitWidth>
            </field>
          </fields>
        </register>
        <register>
          <name>RTOR</name>
          <addressOffset>0x14</addressOffset>
          <size>0x20</size>
          <fields>
            <field>
              <name>RTO</name>
              <bitOffset>0</bitOffset>
              <bitWidth>24</bitWidth>
            </field>
            <field>
              <name>BLEN</name>
              <bitOffset>24</bitOffset>
              <bitWidth>8</bitWidth>
            </field>
          </fields>
        </register>
        <register>
          <name>RQR</name>
          <addressOffset>0x18</addressOffset>
          <size>0x20</size>
          <fields>
            <field>
              <name>ABRRQ</name>
              <bitOffset>0</bitOffset>
              <bitWidth>1</bitWidth>
            </field>
            <field>
              <name>SBKRQ</name>
              <bitOffset>1</bitOffset>
              <bitWidth>1</bitWidth>
            </field>
            <field>
              <name>MMRQ</name>
              <bitOffset>2</bitOffset>
              <bitWidth>1</bitWidth>
            </field>
            <field>
              <name>RXFRQ</name>
              <bitOffset>3</bitOffset>
              <bitWidth>1</bitWidth>
            </field>
            <field>
              <name>TXFRQ</name>
              <bitOffset>4</bitOffset>
              <bitWidth>1</bitWidth>
            </field>
          </fields>
        </register>
        <register>
          <name>ISR</name>
          <addressOffset>0x1c</addressOffset>
          <size>0x20</size>
          <fields>
            <field>
              <name>PE</name>
              <bitOffset>0</bitOffset>
              <bitWidth>1</bitWidth>
            </field>
            <field>
              <name>FE</name>
              <bitOffset>1</bitOffset>
              <bitWidth>1</bitWidth>
            </field>
            <field>
              <name>NE</name>
              <bitOffset>2</bitOffset>
              <bitWidth>1</bitWidth>
            </field>
            <field>
              <name>ORE</name>
              <bitOffset>3</bitOffset>
              <bitWidth>1</bitWidth>
            </field>
            <field>
              <name>IDLE</name>
              <bitOffset>4</bitOffset>
              <bitWidth>1</bitWidth>
            </field>
            <field>
              <name>RXNE</name>
              <bitOffset>5</bitOffset>
              <bitWidth>1</bitWidth>
            </field>
            <field>
              <name>TC</name>
              <bitOffset>6</bitOffset>
              <bitWidth>1</bitWidth>
            </field>
            <field>
              <name>TXE</name>
              <bitOffset>7</bitOffset>
              <bitWidth>1</bitWidth>
            </field>
            <field>
              <name>LBDF</name>
              <bitOffset>8</bitOffset>
              <bitWidth>1</bitWidth>
            </field>
            <field>
              <name>CTSIF</name>
              <bitOffset>9</bitOffset>
              <bitWidth>1</bitWidth>
            </field>
            <field>
              <name>CTS</name>
              <bitOffset>10</bitOffset>
              <bitWidth>1</bitWidth>
            </field>
            <field>
              <name>RTOF</name>
              <bitOffset>11</bitOffset>
              <bitWidth>1</bitWidth>
            </field>
            <field>
              <name>EOBF</name>
              <bitOffset>12</bitOffset>
              <bitWidth>1</bitWidth>
            </field>
            <field>
              <name>ABRE</name>
              <bitOffset>14</bitOffset>
              <bitWidth>1</bitWidth>
            </field>
            <field>
              <name>ABRF</name>
              <bitOffset>15</bitOffset>
              <bitWidth>1</bitWidth>
            </field>
            <field>
              <name>BUSY</name>
              <bitOffset>16</bitOffset>
              <bitWidth>1</bitWidth>
            </field>
            <field>
              <name>CMF</name>
              <bitOffset>17</bitOffset>
              <bitWidth>1</bitWidth>
            </field>
            <field>
              <name>SBKF</name>
              <bitOffset>18</bitOffset>
              <bitWidth>1</bitWidth>
            </field>
            <field>
              <name>RWU</name>
              <bitOffset>19</bitOffset>
              <bitWidth>1</bitWidth>
            </field>
            <field>
              <name>WUF</name>
              <bitOffset>20</bitOffset>
              <bitWidth>1</bitWidth>
            </field>
            <field>
              <name>TEACK</name>
              <bitOffset>21</bitOffset>
              <bitWidth>1</bitWidth>
            </field>
            <field>
              <name>REACK</name>
              <bitOffset>22</bitOffset>
              <bitWidth>1</bitWidth>
            </field>
          </fields>
        </register>
        <register>
          <name>ICR</name>
          <addressOffset>0x20</addressOffset>
          <size>0x20</size>
          <fields>
            <field>
              <name>PECF</name>
              <bitOffset>0</bitOffset>
              <bitWidth>1</bitWidth>
            </field>
            <field>
              <name>FECF</name>
              <bitOffset>1</bitOffset>
              <bitWidth>1</bitWidth>
            </field>
            <field>
              <name>NCF</name>
              <bitOffset>2</bitOffset>
              <bitWidth>1</bitWidth>
            </field>
            <field>
              <name>ORECF</name>
              <bitOffset>3</bitOffset>
              <bitWidth>1</bitWidth>
            </field>
            <field>
              <name>IDLECF</name>
              <bitOffset>4</bitOffset>
              <bitWidth>1</bitWidth>
            </field>
            <field>
              <name>TCCF</name>
              <bitOffset>6</bitOffset>
              <bitWidth>1</bitWidth>
            </field>
            <field>
              <name>LBDCF</name>
              <bitOffset>8</bitOffset>
              <bitWidth>1</bitWidth>
            </field>
            <field>
              <name>CTSCF</name>
              <bitOffset>9</bitOffset>
              <bitWidth>1</bitWidth>
            </field>
            <field>
              <name>RTOCF</name>
              <bitOffset>11</bitOffset>
              <bitWidth>1</bitWidth>
            </field>
            <field>
              <name>EOBCF</name>
              <bitOffset>12</bitOffset>
              <bitWidth>1</bitWidth>
            </field>
            <field>
              <name>CMCF</name>
              <bitOffset>17</bitOffset>
              <bitWidth>1</bitWidth>
            </field>
            <field>
              <name>WUCF</name>
              <bitOffset>20</bitOffset>
              <bitWidth>1</bitWidth>
            </field>
          </fields>
        </register>
        <register>
          <name>RDR</name>
          <addressOffset>0x24</addressOffset>
          <size>0x10</size>
        </register>
        <register>
          <name>TDR</name>
          <addressOffset>0x28</addressOffset>
          <size>0x10</size>
        </register>
      </registers>
    </peripheral>
    <peripheral>
      <name>USART4</name>
      <baseAddress>0x40004c00</baseAddress>
      <registers>
        <register>
          <name>CR1</name>
          <addressOffset>0x0</addressOffset>
          <size>0x20</size>
          <fields>
            <field>
              <name>UE</name>
              <bitOffset>0</bitOffset>
              <bitWidth>1</bitWidth>
            </field>
            <field>
              <name>UESM</name>
              <bitOffset>1</bitOffset>
              <bitWidth>1</bitWidth>
            </field>
            <field>
              <name>RE</name>
              <bitOffset>2</bitOffset>
              <bitWidth>1</bitWidth>
            </field>
            <field>
              <name>TE</name>
              <bitOffset>3</bitOffset>
              <bitWidth>1</bitWidth>
            </field>
            <field>
              <name>IDLEIE</name>
              <bitOffset>4</bitOffset>
              <bitWidth>1</bitWidth>
            </field>
            <field>
              <name>RXNEIE</name>
              <bitOffset>5</bitOffset>
              <bitWidth>1</bitWidth>
            </field>
            <field>
              <name>TCIE</name>
              <bitOffset>6</bitOffset>
              <bitWidth>1</bitWidth>
            </field>
            <field>
              <name>TXEIE</name>
              <bitOffset>7</bitOffset>
              <bitWidth>1</bitWidth>
            </field>
            <field>
              <name>PEIE</name>
              <bitOffset>8</bitOffset>
              <bitWidth>1</bitWidth>
            </field>
            <field>
              <name>PS</name>
              <bitOffset>9</bitOffset>
              <bitWidth>1</bitWidth>
            </field>
            <field>
              <name>PCE</name>
              <bitOffset>10</bitOffset>
              <bitWidth>1</bitWidth>
            </field>
            <field>
              <name>WAKE</name>
              <bitOffset>11</bitOffset>
              <bitWidth>1</bitWidth>
            </field>
            <field>
              <name>M0</name>
              <bitOffset>12</bitOffset>
              <bitWidth>1</bitWidth>
            </field>
            <field>
              <name>MME</name>
              <bitOffset>13</bitOffset>
              <bitWidth>1</bitWidth>
            </field>
            <field>
              <name>CMIE</name>
              <bitOffset>14</bitOffset>
              <bitWidth>1</bitWidth>
            </field>
            <field>
              <name>OVER8</name>
              <bitOffset>15</bitOffset>
              <bitWidth>1</bitWidth>
            </field>
            <field>
              <name>DEDT</name>
              <bitOffset>16</bitOffset>
              <bitWidth>5</bitWidth>
            </field>
            <field>
              <name>DEAT</name>
              <bitOffset>21</bitOffset>
              <bitWidth>5</bitWidth>
            </field>
            <field>
              <name>RTOIE</name>
              <bitOffset>26</bitOffset>
              <bitWidth>1</bitWidth>
            </field>
            <field>
              <name>EOBIE</name>
              <bitOffset>27</bitOffset>
              <bitWidth>1</bitWidth>
            </field>
            <field>
              <name>M1</name>
              <bitOffset>28</bitOffset>
              <bitWidth>1</bitWidth>
            </field>
          </fields>
        </register>
        <register>
          <name>CR2</name>
          <addressOffset>0x4</addressOffset>
          <size>0x20</size>
          <fields>
            <field>
              <name>ADDM7</name>
              <bitOffset>4</bitOffset>
              <bitWidth>1</bitWidth>
            </field>
            <field>
              <name>LBDL</name>
              <bitOffset>5</bitOffset>
              <bitWidth>1</bitWidth>
            </field>
            <field>
              <name>LBDIE</name>
              <bitOffset>6</bitOffset>
              <bitWidth>1</bitWidth>
            </field>
            <field>
              <name>LBCL</name>
              <bitOffset>8</bitOffset>
              <bitWidth>1</bitWidth>
            </field>
            <field>
              <name>CPHA</name>
              <bitOffset>9</bitOffset>
              <bitWidth>1</bitWidth>
            </field>
            <field>
              <name>CPOL</name>
              <bitOffset>10</bitOffset>
              <bitWidth>1</bitWidth>
            </field>
            <field>
              <name>CLKEN</name>
              <bitOffset>11</bitOffset>
              <bitWidth>1</bitWidth>
            </field>
            <field>
              <name>STOP</name>
              <bitOffset>12</bitOffset>
              <bitWidth>2</bitWidth>
            </field>
            <field>
              <name>LINEN</name>
              <bitOffset>14</bitOffset>
              <bitWidth>1</bitWidth>
            </field>
            <field>
              <name>SWAP</name>
              <bitOffset>15</bitOffset>
              <bitWidth>1</bitWidth>
            </field>
            <field>
              <name>RXINV</name>
              <bitOffset>16</bitOffset>
              <bitWidth>1</bitWidth>
            </field>
            <field>
              <name>TXINV</name>
              <bitOffset>17</bitOffset>
              <bitWidth>1</bitWidth>
            </field>
            <field>
              <name>DATAINV</name>
              <bitOffset>18</bitOffset>
              <bitWidth>1</bitWidth>
            </field>
            <field>
              <name>MSBFIRST</name>
              <bitOffset>19</bitOffset>
              <bitWidth>1</bitWidth>
            </field>
            <field>
              <name>ABREN</name>
              <bitOffset>20</bitOffset>
              <bitWidth>1</bitWidth>
            </field>
            <field>
              <name>ABRMODE</name>
              <bitOffset>21</bitOffset>
              <bitWidth>2</bitWidth>
            </field>
            <field>
              <name>RTOEN</name>
              <bitOffset>23</bitOffset>
              <bitWidth>1</bitWidth>
            </field>
            <field>
              <name>ADD</name>
              <bitOffset>24</bitOffset>
              <bitWidth>8</bitWidth>
            </field>
          </fields>
        </register>
        <register>
          <name>CR3</name>
          <addressOffset>0x8</addressOffset>
          <size>0x20</size>
          <fields>
            <field>
              <name>EIE</name>
              <bitOffset>0</bitOffset>
              <bitWidth>1</bitWidth>
            </field>
            <field>
              <name>IREN</name>
              <bitOffset>1</bitOffset>
              <bitWidth>1</bitWidth>
            </field>
            <field>
              <name>IRLP</name>
              <bitOffset>2</bitOffset>
              <bitWidth>1</bitWidth>
            </field>
            <field>
              <name>HDSEL</name>
              <bitOffset>3</bitOffset>
              <bitWidth>1</bitWidth>
            </field>
            <field>
              <name>NACK</name>
              <bitOffset>4</bitOffset>
              <bitWidth>1</bitWidth>
            </field>
            <field>
              <name>SCEN</name>
              <bitOffset>5</bitOffset>
              <bitWidth>1</bitWidth>
            </field>
            <field>
              <name>DMAR</name>
              <bitOffset>6</bitOffset>
              <bitWidth>1</bitWidth>
            </field>
            <field>
              <name>DMAT</name>
              <bitOffset>7</bitOffset>
              <bitWidth>1</bitWidth>
            </field>
            <field>
              <name>RTSE</name>
              <bitOffset>8</bitOffset>
              <bitWidth>1</bitWidth>
            </field>
            <field>
              <name>CTSE</name>
              <bitOffset>9</bitOffset>
              <bitWidth>1</bitWidth>
            </field>
            <field>
              <name>CTSIE</name>
              <bitOffset>10</bitOffset>
              <bitWidth>1</bitWidth>
            </field>
            <field>
              <name>ONEBIT</name>
              <bitOffset>11</bitOffset>
              <bitWidth>1</bitWidth>
            </field>
            <field>
              <name>OVRDIS</name>
              <bitOffset>12</bitOffset>
              <bitWidth>1</bitWidth>
            </field>
            <field>
              <name>DDRE</name>
              <bitOffset>13</bitOffset>
              <bitWidth>1</bitWidth>
            </field>
            <field>
              <name>DEM</name>
              <bitOffset>14</bitOffset>
              <bitWidth>1</bitWidth>
            </field>
            <field>
              <name>DEP</name>
              <bitOffset>15</bitOffset>
              <bitWidth>1</bitWidth>
            </field>
            <field>
              <name>SCARCNT</name>
              <bitOffset>17</bitOffset>
              <bitWidth>3</bitWidth>
            </field>
            <field>
              <name>WUS</name>
              <bitOffset>20</bitOffset>
              <bitWidth>2</bitWidth>
            </field>
            <field>
              <name>WUFIE</name>
              <bitOffset>22</bitOffset>
              <bitWidth>1</bitWidth>
            </field>
          </fields>
        </register>
        <register>
          <name>BRR</name>
          <addressOffset>0xc</addressOffset>
          <size>0x20</size>
          <fields>
            <field>
              <name>DIV_FRACTION</name>
              <bitOffset>0</bitOffset>
              <bitWidth>4</bitWidth>
            </field>
            <field>
              <name>DIV_MANTISSA</name>
              <bitOffset>4</bitOffset>
              <bitWidth>12</bitWidth>
            </field>
          </fields>
        </register>
        <register>
          <name>GTPR</name>
          <addressOffset>0x10</addressOffset>
          <size>0x20</size>
          <fields>
            <field>
              <name>PSC</name>
              <bitOffset>0</bitOffset>
              <bitWidth>8</bitWidth>
            </field>
            <field>
              <name>GT</name>
              <bitOffset>8</bitOffset>
              <bitWidth>8</bitWidth>
            </field>
          </fields>
        </register>
        <register>
          <name>RTOR</name>
          <addressOffset>0x14</addressOffset>
          <size>0x20</size>
          <fields>
            <field>
              <name>RTO</name>
              <bitOffset>0</bitOffset>
              <bitWidth>24</bitWidth>
            </field>
            <field>
              <name>BLEN</name>
              <bitOffset>24</bitOffset>
              <bitWidth>8</bitWidth>
            </field>
          </fields>
        </register>
        <register>
          <name>RQR</name>
          <addressOffset>0x18</addressOffset>
          <size>0x20</size>
          <fields>
            <field>
              <name>ABRRQ</name>
              <bitOffset>0</bitOffset>
              <bitWidth>1</bitWidth>
            </field>
            <field>
              <name>SBKRQ</name>
              <bitOffset>1</bitOffset>
              <bitWidth>1</bitWidth>
            </field>
            <field>
              <name>MMRQ</name>
              <bitOffset>2</bitOffset>
              <bitWidth>1</bitWidth>
            </field>
            <field>
              <name>RXFRQ</name>
              <bitOffset>3</bitOffset>
              <bitWidth>1</bitWidth>
            </field>
            <field>
              <name>TXFRQ</name>
              <bitOffset>4</bitOffset>
              <bitWidth>1</bitWidth>
            </field>
          </fields>
        </register>
        <register>
          <name>ISR</name>
          <addressOffset>0x1c</addressOffset>
          <size>0x20</size>
          <fields>
            <field>
              <name>PE</name>
              <bitOffset>0</bitOffset>
              <bitWidth>1</bitWidth>
            </field>
            <field>
              <name>FE</name>
              <bitOffset>1</bitOffset>
              <bitWidth>1</bitWidth>
            </field>
            <field>
              <name>NE</name>
              <bitOffset>2</bitOffset>
              <bitWidth>1</bitWidth>
            </field>
            <field>
              <name>ORE</name>
              <bitOffset>3</bitOffset>
              <bitWidth>1</bitWidth>
            </field>
            <field>
              <name>IDLE</name>
              <bitOffset>4</bitOffset>
              <bitWidth>1</bitWidth>
            </field>
            <field>
              <name>RXNE</name>
              <bitOffset>5</bitOffset>
              <bitWidth>1</bitWidth>
            </field>
            <field>
              <name>TC</name>
              <bitOffset>6</bitOffset>
              <bitWidth>1</bitWidth>
            </field>
            <field>
              <name>TXE</name>
              <bitOffset>7</bitOffset>
              <bitWidth>1</bitWidth>
            </field>
            <field>
              <name>LBDF</name>
              <bitOffset>8</bitOffset>
              <bitWidth>1</bitWidth>
            </field>
            <field>
              <name>CTSIF</name>
              <bitOffset>9</bitOffset>
              <bitWidth>1</bitWidth>
            </field>
            <field>
              <name>CTS</name>
              <bitOffset>10</bitOffset>
              <bitWidth>1</bitWidth>
            </field>
            <field>
              <name>RTOF</name>
              <bitOffset>11</bitOffset>
              <bitWidth>1</bitWidth>
            </field>
            <field>
              <name>EOBF</name>
              <bitOffset>12</bitOffset>
              <bitWidth>1</bitWidth>
            </field>
            <field>
              <name>ABRE</name>
              <bitOffset>14</bitOffset>
              <bitWidth>1</bitWidth>
            </field>
            <field>
              <name>ABRF</name>
              <bitOffset>15</bitOffset>
              <bitWidth>1</bitWidth>
            </field>
            <field>
              <name>BUSY</name>
              <bitOffset>16</bitOffset>
              <bitWidth>1</bitWidth>
            </field>
            <field>
              <name>CMF</name>
              <bitOffset>17</bitOffset>
              <bitWidth>1</bitWidth>
            </field>
            <field>
              <name>SBKF</name>
              <bitOffset>18</bitOffset>
              <bitWidth>1</bitWidth>
            </field>
            <field>
              <name>RWU</name>
              <bitOffset>19</bitOffset>
              <bitWidth>1</bitWidth>
            </field>
            <field>
              <name>WUF</name>
              <bitOffset>20</bitOffset>
              <bitWidth>1</bitWidth>
            </field>
            <field>
              <name>TEACK</name>
              <bitOffset>21</bitOffset>
              <bitWidth>1</bitWidth>
            </field>
            <field>
              <name>REACK</name>
              <bitOffset>22</bitOffset>
              <bitWidth>1</bitWidth>
            </field>
          </fields>
        </register>
        <register>
          <name>ICR</name>
          <addressOffset>0x20</addressOffset>
          <size>0x20</size>
          <fields>
            <field>
              <name>PECF</name>
              <bitOffset>0</bitOffset>
              <bitWidth>1</bitWidth>
            </field>
            <field>
              <name>FECF</name>
              <bitOffset>1</bitOffset>
              <bitWidth>1</bitWidth>
            </field>
            <field>
              <name>NCF</name>
              <bitOffset>2</bitOffset>
              <bitWidth>1</bitWidth>
            </field>
            <field>
              <name>ORECF</name>
              <bitOffset>3</bitOffset>
              <bitWidth>1</bitWidth>
            </field>
            <field>
              <name>IDLECF</name>
              <bitOffset>4</bitOffset>
              <bitWidth>1</bitWidth>
            </field>
            <field>
              <name>TCCF</name>
              <bitOffset>6</bitOffset>
              <bitWidth>1</bitWidth>
            </field>
            <field>
              <name>LBDCF</name>
              <bitOffset>8</bitOffset>
              <bitWidth>1</bitWidth>
            </field>
            <field>
              <name>CTSCF</name>
              <bitOffset>9</bitOffset>
              <bitWidth>1</bitWidth>
            </field>
            <field>
              <name>RTOCF</name>
              <bitOffset>11</bitOffset>
              <bitWidth>1</bitWidth>
            </field>
            <field>
              <name>EOBCF</name>
              <bitOffset>12</bitOffset>
              <bitWidth>1</bitWidth>
            </field>
            <field>
              <name>CMCF</name>
              <bitOffset>17</bitOffset>
              <bitWidth>1</bitWidth>
            </field>
            <field>
              <name>WUCF</name>
              <bitOffset>20</bitOffset>
              <bitWidth>1</bitWidth>
            </field>
          </fields>
        </register>
        <register>
          <name>RDR</name>
          <addressOffset>0x24</addressOffset>
          <size>0x10</size>
        </register>
        <register>
          <name>TDR</name>
          <addressOffset>0x28</addressOffset>
          <size>0x10</size>
        </register>
      </registers>
    </peripheral>
    <peripheral>
      <name>I2C1</name>
      <baseAddress>0x40005400</baseAddress>
      <registers>
        <register>
          <name>CR1</name>
          <addressOffset>0x0</addressOffset>
          <size>0x20</size>
          <fields>
            <field>
              <name>PE</name>
              <bitOffset>0</bitOffset>
              <bitWidth>1</bitWidth>
            </field>
            <field>
              <name>TXIE</name>
              <bitOffset>1</bitOffset>
              <bitWidth>1</bitWidth>
            </field>
            <field>
              <name>RXIE</name>
              <bitOffset>2</bitOffset>
              <bitWidth>1</bitWidth>
            </field>
            <field>
              <name>ADDRIE</name>
              <bitOffset>3</bitOffset>
              <bitWidth>1</bitWidth>
            </field>
            <field>
              <name>NACKIE</name>
              <bitOffset>4</bitOffset>
              <bitWidth>1</bitWidth>
            </field>
            <field>
              <name>STOPIE</name>
              <bitOffset>5</bitOffset>
              <bitWidth>1</bitWidth>
            </field>
            <field>
              <name>TCIE</name>
              <bitOffset>6</bitOffset>
              <bitWidth>1</bitWidth>
            </field>
            <field>
              <name>ERRIE</name>
              <bitOffset>7</bitOffset>
              <bitWidth>1</bitWidth>
            </field>
            <field>
              <name>DNF</name>
              <bitOffset>8</bitOffset>
              <bitWidth>4</bitWidth>
            </field>
            <field>
              <name>ANFOFF</name>
              <bitOffset>12</bitOffset>
              <bitWidth>1</bitWidth>
            </field>
            <field>
              <name>SWRST</name>
              <bitOffset>13</bitOffset>
              <bitWidth>1</bitWidth>
            </field>
            <field>
              <name>TXDMAEN</name>
              <bitOffset>14</bitOffset>
              <bitWidth>1</bitWidth>
            </field>
            <field>
              <name>RXDMAEN</name>
              <bitOffset>15</bitOffset>
              <bitWidth>1</bitWidth>
            </field>
            <field>
              <name>SBC</name>
              <bitOffset>16</bitOffset>
              <bitWidth>1</bitWidth>
            </field>
            <field>
              <name>NOSTRETCH</name>
              <bitOffset>17</bitOffset>
              <bitWidth>1</bitWidth>
            </field>
            <field>
              <name>WUPEN</name>
              <bitOffset>18</bitOffset>
              <bitWidth>1</bitWidth>
            </field>
            <field>
              <name>GCEN</name>
              <bitOffset>19</bitOffset>
              <bitWidth>1</bitWidth>
            </field>
            <field>
              <name>SMBHEN</name>
              <bitOffset>20</bitOffset>
              <bitWidth>1</bitWidth>
            </field>
            <field>
              <name>SMBDEN</name>
              <bitOffset>21</bitOffset>
              <bitWidth>1</bitWidth>
            </field>
            <field>
              <name>ALERTEN</name>
              <bitOffset>22</bitOffset>
              <bitWidth>1</bitWidth>
            </field>
            <field>
              <name>PECEN</name>
              <bitOffset>23</bitOffset>
              <bitWidth>1</bitWidth>
            </field>
          </fields>
        </register>
        <register>
          <name>CR2</name>
          <addressOffset>0x4</addressOffset>
          <size>0x20</size>
          <fields>
            <field>
              <name>SADD</name>
              <bitOffset>0</bitOffset>
              <bitWidth>10</bitWidth>
            </field>
            <field>
              <name>RD_WRN</name>
              <bitOffset>10</bitOffset>
              <bitWidth>1</bitWidth>
            </field>
            <field>
              <name>ADD10</name>
              <bitOffset>11</bitOffset>
              <bitWidth>1</bitWidth>
            </field>
            <field>
              <name>HEAD10R</name>
              <bitOffset>12</bitOffset>
              <bitWidth>1</bitWidth>
            </field>
            <field>
              <name>START</name>
              <bitOffset>13</bitOffset>
              <bitWidth>1</bitWidth>
            </field>
            <field>
              <name>STOP</name>
              <bitOffset>14</bitOffset>
              <bitWidth>1</bitWidth>
            </field>
            <field>
              <name>NACK</name>
              <bitOffset>15</bitOffset>
              <bitWidth>1</bitWidth>
            </field>
            <field>
              <name>NBYTES</name>
              <bitOffset>16</bitOffset>
              <bitWidth>8</bitWidth>
            </field>
            <field>
              <name>RELOAD</name>
              <bitOffset>24</bitOffset>
              <bitWidth>1</bitWidth>
            </field>
            <field>
              <name>AUTOEND</name>
              <bitOffset>25</bitOffset>
              <bitWidth>1</bitWidth>
            </field>
            <field>
              <name>PECBYTE</name>
              <bitOffset>26</bitOffset>
              <bitWidth>1</bitWidth>
            </field>
          </fields>
        </register>
        <register>
          <name>OAR1</name>
          <addressOffset>0x8</addressOffset>
          <size>0x20</size>
          <fields>
            <field>
              <name>OA1</name>
              <bitOffset>0</bitOffset>
              <bitWidth>10</bitWidth>
            </field>
            <field>
              <name>OA1MODE</name>
              <bitOffset>10</bitOffset>
              <bitWidth>1</bitWidth>
            </field>
            <field>
              <name>OA1EN</name>
              <bitOffset>15</bitOffset>
              <bitWidth>1</bitWidth>
            </field>
          </fields>
        </register>
        <register>
          <name>OAR2</name>
          <addressOffset>0xc</addressOffset>
          <size>0x20</size>
          <fields>
            <field>
              <name>OA2</name>
              <bitOffset>1</bitOffset>
              <bitWidth>7</bitWidth>
            </field>
            <field>
              <name>OA2MSK</name>
              <bitOffset>8</bitOffset>
              <bitWidth>3</bitWidth>
            </field>
            <field>
              <name>OA2MASK06</name>
              <bitOffset>9</bitOffset>
              <bitWidth>2</bitWidth>
            </field>
            <field>
              <name>OA2MASK04</name>
              <bitOffset>10</bitOffset>
              <bitWidth>1</bitWidth>
            </field>
            <field>
              <name>OA2EN</name>
              <bitOffset>15</bitOffset>
              <bitWidth>1</bitWidth>
            </field>
          </fields>
        </register>
        <register>
          <name>TIMINGR</name>
          <addressOffset>0x10</addressOffset>
          <size>0x20</size>
          <fields>
            <field>
              <name>SCLL</name>
              <bitOffset>0</bitOffset>
              <bitWidth>8</bitWidth>
            </field>
            <field>
              <name>SCLH</name>
              <bitOffset>8</bitOffset>
              <bitWidth>8</bitWidth>
            </field>
            <field>
              <name>SDADEL</name>
              <bitOffset>16</bitOffset>
              <bitWidth>4</bitWidth>
            </field>
            <field>
              <name>SCLDEL</name>
              <bitOffset>20</bitOffset>
              <bitWidth>4</bitWidth>
            </field>
            <field>
              <name>PRESC</name>
              <bitOffset>28</bitOffset>
              <bitWidth>4</bitWidth>
            </field>
          </fields>
        </register>
        <register>
          <name>TIMEOUTR</name>
          <addressOffset>0x14</addressOffset>
          <size>0x20</size>
          <fields>
            <field>
              <name>TIMEOUTA</name>
              <bitOffset>0</bitOffset>
              <bitWidth>12</bitWidth>
            </field>
            <field>
              <name>TIDLE</name>
              <bitOffset>12</bitOffset>
              <bitWidth>1</bitWidth>
            </field>
            <field>
              <name>TIMOUTEN</name>
              <bitOffset>15</bitOffset>
              <bitWidth>1</bitWidth>
            </field>
            <field>
              <name>TIMEOUTB</name>
              <bitOffset>16</bitOffset>
              <bitWidth>12</bitWidth>
            </field>
            <field>
              <name>TEXTEN</name>
              <bitOffset>31</bitOffset>
              <bitWidth>1</bitWidth>
            </field>
          </fields>
        </register>
        <register>
          <name>ISR</name>
          <addressOffset>0x18</addressOffset>
          <size>0x20</size>
          <fields>
            <field>
              <name>TXE</name>
              <bitOffset>0</bitOffset>
              <bitWidth>1</bitWidth>
            </field>
            <field>
              <name>TXIS</name>
              <bitOffset>1</bitOffset>
              <bitWidth>1</bitWidth>
            </field>
            <field>
              <name>RXNE</name>
              <bitOffset>2</bitOffset>
              <bitWidth>1</bitWidth>
            </field>
            <field>
              <name>ADDR</name>
              <bitOffset>3</bitOffset>
              <bitWidth>1</bitWidth>
            </field>
            <field>
              <name>NACKF</name>
              <bitOffset>4</bitOffset>
              <bitWidth>1</bitWidth>
            </field>
            <field>
              <name>STOPF</name>
              <bitOffset>5</bitOffset>
              <bitWidth>1</bitWidth>
            </field>
            <field>
              <name>TC</name>
              <bitOffset>6</bitOffset>
              <bitWidth>1</bitWidth>
            </field>
            <field>
              <name>TCR</name>
              <bitOffset>7</bitOffset>
              <bitWidth>1</bitWidth>
            </field>
            <field>
              <name>BERR</name>
              <bitOffset>8</bitOffset>
              <bitWidth>1</bitWidth>
            </field>
            <field>
              <name>ARLO</name>
              <bitOffset>9</bitOffset>
              <bitWidth>1</bitWidth>
            </field>
            <field>
              <name>OVR</name>
              <bitOffset>10</bitOffset>
              <bitWidth>1</bitWidth>
            </field>
            <field>
              <name>PECERR</name>
              <bitOffset>11</bitOffset>
              <bitWidth>1</bitWidth>
            </field>
            <field>
              <name>TIMEOUT</name>
              <bitOffset>12</bitOffset>
              <bitWidth>1</bitWidth>
            </field>
            <field>
              <name>ALERT</name>
              <bitOffset>13</bitOffset>
              <bitWidth>1</bitWidth>
            </field>
            <field>
              <name>BUSY</name>
              <bitOffset>15</bitOffset>
              <bitWidth>1</bitWidth>
            </field>
            <field>
              <name>DIR</name>
              <bitOffset>16</bitOffset>
              <bitWidth>1</bitWidth>
            </field>
            <field>
              <name>ADDCODE</name>
              <bitOffset>17</bitOffset>
              <bitWidth>7</bitWidth>
            </field>
          </fields>
        </register>
        <register>
          <name>ICR</name>
          <addressOffset>0x1c</addressOffset>
          <size>0x20</size>
          <fields>
            <field>
              <name>ADDRCF</name>
              <bitOffset>3</bitOffset>
              <bitWidth>1</bitWidth>
            </field>
            <field>
              <name>NACKCF</name>
              <bitOffset>4</bitOffset>
              <bitWidth>1</bitWidth>
            </field>
            <field>
              <name>STOPCF</name>
              <bitOffset>5</bitOffset>
              <bitWidth>1</bitWidth>
            </field>
            <field>
              <name>BERRCF</name>
              <bitOffset>8</bitOffset>
              <bitWidth>1</bitWidth>
            </field>
            <field>
              <name>ARLOCF</name>
              <bitOffset>9</bitOffset>
              <bitWidth>1</bitWidth>
            </field>
            <field>
              <name>OVRCF</name>
              <bitOffset>10</bitOffset>
              <bitWidth>1</bitWidth>
            </field>
            <field>
              <name>PECCF</name>
              <bitOffset>11</bitOffset>
              <bitWidth>1</bitWidth>
            </field>
            <field>
              <name>TIMOUTCF</name>
              <bitOffset>12</bitOffset>
              <bitWidth>1</bitWidth>
            </field>
            <field>
              <name>ALERTCF</name>
              <bitOffset>13</bitOffset>
              <bitWidth>1</bitWidth>
            </field>
          </fields>
        </register>
        <register>
          <name>PECR</name>
          <addressOffset>0x20</addressOffset>
          <size>0x20</size>
          <fields>
            <field>
              <name>PEC</name>
              <bitOffset>0</bitOffset>
              <bitWidth>8</bitWidth>
            </field>
          </fields>
        </register>
        <register>
          <name>RXDR</name>
          <addressOffset>0x24</addressOffset>
          <size>0x20</size>
          <fields>
            <field>
              <name>RXDATA</name>
              <bitOffset>0</bitOffset>
              <bitWidth>8</bitWidth>
            </field>
          </fields>
        </register>
        <register>
          <name>TXDR</name>
          <addressOffset>0x28</addressOffset>
          <size>0x20</size>
          <fields>
            <field>
              <name>TXDATA</name>
              <bitOffset>0</bitOffset>
              <bitWidth>8</bitWidth>
            </field>
          </fields>
        </register>
      </registers>
    </peripheral>
    <peripheral>
      <name>I2C2</name>
      <baseAddress>0x40005800</baseAddress>
      <registers>
        <register>
          <name>CR1</name>
          <addressOffset>0x0</addressOffset>
          <size>0x20</size>
          <fields>
            <field>
              <name>PE</name>
              <bitOffset>0</bitOffset>
              <bitWidth>1</bitWidth>
            </field>
            <field>
              <name>TXIE</name>
              <bitOffset>1</bitOffset>
              <bitWidth>1</bitWidth>
            </field>
            <field>
              <name>RXIE</name>
              <bitOffset>2</bitOffset>
              <bitWidth>1</bitWidth>
            </field>
            <field>
              <name>ADDRIE</name>
              <bitOffset>3</bitOffset>
              <bitWidth>1</bitWidth>
            </field>
            <field>
              <name>NACKIE</name>
              <bitOffset>4</bitOffset>
              <bitWidth>1</bitWidth>
            </field>
            <field>
              <name>STOPIE</name>
              <bitOffset>5</bitOffset>
              <bitWidth>1</bitWidth>
            </field>
            <field>
              <name>TCIE</name>
              <bitOffset>6</bitOffset>
              <bitWidth>1</bitWidth>
            </field>
            <field>
              <name>ERRIE</name>
              <bitOffset>7</bitOffset>
              <bitWidth>1</bitWidth>
            </field>
            <field>
              <name>DNF</name>
              <bitOffset>8</bitOffset>
              <bitWidth>4</bitWidth>
            </field>
            <field>
              <name>ANFOFF</name>
              <bitOffset>12</bitOffset>
              <bitWidth>1</bitWidth>
            </field>
            <field>
              <name>SWRST</name>
              <bitOffset>13</bitOffset>
              <bitWidth>1</bitWidth>
            </field>
            <field>
              <name>TXDMAEN</name>
              <bitOffset>14</bitOffset>
              <bitWidth>1</bitWidth>
            </field>
            <field>
              <name>RXDMAEN</name>
              <bitOffset>15</bitOffset>
              <bitWidth>1</bitWidth>
            </field>
            <field>
              <name>SBC</name>
              <bitOffset>16</bitOffset>
              <bitWidth>1</bitWidth>
            </field>
            <field>
              <name>NOSTRETCH</name>
              <bitOffset>17</bitOffset>
              <bitWidth>1</bitWidth>
            </field>
            <field>
              <name>WUPEN</name>
              <bitOffset>18</bitOffset>
              <bitWidth>1</bitWidth>
            </field>
            <field>
              <name>GCEN</name>
              <bitOffset>19</bitOffset>
              <bitWidth>1</bitWidth>
            </field>
            <field>
              <name>SMBHEN</name>
              <bitOffset>20</bitOffset>
              <bitWidth>1</bitWidth>
            </field>
            <field>
              <name>SMBDEN</name>
              <bitOffset>21</bitOffset>
              <bitWidth>1</bitWidth>
            </field>
            <field>
              <name>ALERTEN</name>
              <bitOffset>22</bitOffset>
              <bitWidth>1</bitWidth>
            </field>
            <field>
              <name>PECEN</name>
              <bitOffset>23</bitOffset>
              <bitWidth>1</bitWidth>
            </field>
          </fields>
        </register>
        <register>
          <name>CR2</name>
          <addressOffset>0x4</addressOffset>
          <size>0x20</size>
          <fields>
            <field>
              <name>SADD</name>
              <bitOffset>0</bitOffset>
              <bitWidth>10</bitWidth>
            </field>
            <field>
              <name>RD_WRN</name>
              <bitOffset>10</bitOffset>
              <bitWidth>1</bitWidth>
            </field>
            <field>
              <name>ADD10</name>
              <bitOffset>11</bitOffset>
              <bitWidth>1</bitWidth>
            </field>
            <field>
              <name>HEAD10R</name>
              <bitOffset>12</bitOffset>
              <bitWidth>1</bitWidth>
            </field>
            <field>
              <name>START</name>
              <bitOffset>13</bitOffset>
              <bitWidth>1</bitWidth>
            </field>
            <field>
              <name>STOP</name>
              <bitOffset>14</bitOffset>
              <bitWidth>1</bitWidth>
            </field>
            <field>
              <name>NACK</name>
              <bitOffset>15</bitOffset>
              <bitWidth>1</bitWidth>
            </field>
            <field>
              <name>NBYTES</name>
              <bitOffset>16</bitOffset>
              <bitWidth>8</bitWidth>
            </field>
            <field>
              <name>RELOAD</name>
              <bitOffset>24</bitOffset>
              <bitWidth>1</bitWidth>
            </field>
            <field>
              <name>AUTOEND</name>
              <bitOffset>25</bitOffset>
              <bitWidth>1</bitWidth>
            </field>
            <field>
              <name>PECBYTE</name>
              <bitOffset>26</bitOffset>
              <bitWidth>1</bitWidth>
            </field>
          </fields>
        </register>
        <register>
          <name>OAR1</name>
          <addressOffset>0x8</addressOffset>
          <size>0x20</size>
          <fields>
            <field>
              <name>OA1</name>
              <bitOffset>0</bitOffset>
              <bitWidth>10</bitWidth>
            </field>
            <field>
              <name>OA1MODE</name>
              <bitOffset>10</bitOffset>
              <bitWidth>1</bitWidth>
            </field>
            <field>
              <name>OA1EN</name>
              <bitOffset>15</bitOffset>
              <bitWidth>1</bitWidth>
            </field>
          </fields>
        </register>
        <register>
          <name>OAR2</name>
          <addressOffset>0xc</addressOffset>
          <size>0x20</size>
          <fields>
            <field>
              <name>OA2</name>
              <bitOffset>1</bitOffset>
              <bitWidth>7</bitWidth>
            </field>
            <field>
              <name>OA2MSK</name>
              <bitOffset>8</bitOffset>
              <bitWidth>3</bitWidth>
            </field>
            <field>
              <name>OA2MASK06</name>
              <bitOffset>9</bitOffset>
              <bitWidth>2</bitWidth>
            </field>
            <field>
              <name>OA2MASK04</name>
              <bitOffset>10</bitOffset>
              <bitWidth>1</bitWidth>
            </field>
            <field>
              <name>OA2EN</name>
              <bitOffset>15</bitOffset>
              <bitWidth>1</bitWidth>
            </field>
          </fields>
        </register>
        <register>
          <name>TIMINGR</name>
          <addressOffset>0x10</addressOffset>
          <size>0x20</size>
          <fields>
            <field>
              <name>SCLL</name>
              <bitOffset>0</bitOffset>
              <bitWidth>8</bitWidth>
            </field>
            <field>
              <name>SCLH</name>
              <bitOffset>8</bitOffset>
              <bitWidth>8</bitWidth>
            </field>
            <field>
              <name>SDADEL</name>
              <bitOffset>16</bitOffset>
              <bitWidth>4</bitWidth>
            </field>
            <field>
              <name>SCLDEL</name>
              <bitOffset>20</bitOffset>
              <bitWidth>4</bitWidth>
            </field>
            <field>
              <name>PRESC</name>
              <bitOffset>28</bitOffset>
              <bitWidth>4</bitWidth>
            </field>
          </fields>
        </register>
        <register>
          <name>TIMEOUTR</name>
          <addressOffset>0x14</addressOffset>
          <size>0x20</size>
          <fields>
            <field>
              <name>TIMEOUTA</name>
              <bitOffset>0</bitOffset>
              <bitWidth>12</bitWidth>
            </field>
            <field>
              <name>TIDLE</name>
              <bitOffset>12</bitOffset>
              <bitWidth>1</bitWidth>
            </field>
            <field>
              <name>TIMOUTEN</name>
              <bitOffset>15</bitOffset>
              <bitWidth>1</bitWidth>
            </field>
            <field>
              <name>TIMEOUTB</name>
              <bitOffset>16</bitOffset>
              <bitWidth>12</bitWidth>
            </field>
            <field>
              <name>TEXTEN</name>
              <bitOffset>31</bitOffset>
              <bitWidth>1</bitWidth>
            </field>
          </fields>
        </register>
        <register>
          <name>ISR</name>
          <addressOffset>0x18</addressOffset>
          <size>0x20</size>
          <fields>
            <field>
              <name>TXE</name>
              <bitOffset>0</bitOffset>
              <bitWidth>1</bitWidth>
            </field>
            <field>
              <name>TXIS</name>
              <bitOffset>1</bitOffset>
              <bitWidth>1</bitWidth>
            </field>
            <field>
              <name>RXNE</name>
              <bitOffset>2</bitOffset>
              <bitWidth>1</bitWidth>
            </field>
            <field>
              <name>ADDR</name>
              <bitOffset>3</bitOffset>
              <bitWidth>1</bitWidth>
            </field>
            <field>
              <name>NACKF</name>
              <bitOffset>4</bitOffset>
              <bitWidth>1</bitWidth>
            </field>
            <field>
              <name>STOPF</name>
              <bitOffset>5</bitOffset>
              <bitWidth>1</bitWidth>
            </field>
            <field>
              <name>TC</name>
              <bitOffset>6</bitOffset>
              <bitWidth>1</bitWidth>
            </field>
            <field>
              <name>TCR</name>
              <bitOffset>7</bitOffset>
              <bitWidth>1</bitWidth>
            </field>
            <field>
              <name>BERR</name>
              <bitOffset>8</bitOffset>
              <bitWidth>1</bitWidth>
            </field>
            <field>
              <name>ARLO</name>
              <bitOffset>9</bitOffset>
              <bitWidth>1</bitWidth>
            </field>
            <field>
              <name>OVR</name>
              <bitOffset>10</bitOffset>
              <bitWidth>1</bitWidth>
            </field>
            <field>
              <name>PECERR</name>
              <bitOffset>11</bitOffset>
              <bitWidth>1</bitWidth>
            </field>
            <field>
              <name>TIMEOUT</name>
              <bitOffset>12</bitOffset>
              <bitWidth>1</bitWidth>
            </field>
            <field>
              <name>ALERT</name>
              <bitOffset>13</bitOffset>
              <bitWidth>1</bitWidth>
            </field>
            <field>
              <name>BUSY</name>
              <bitOffset>15</bitOffset>
              <bitWidth>1</bitWidth>
            </field>
            <field>
              <name>DIR</name>
              <bitOffset>16</bitOffset>
              <bitWidth>1</bitWidth>
            </field>
            <field>
              <name>ADDCODE</name>
              <bitOffset>17</bitOffset>
              <bitWidth>7</bitWidth>
            </field>
          </fields>
        </register>
        <register>
          <name>ICR</name>
          <addressOffset>0x1c</addressOffset>
          <size>0x20</size>
          <fields>
            <field>
              <name>ADDRCF</name>
              <bitOffset>3</bitOffset>
              <bitWidth>1</bitWidth>
            </field>
            <field>
              <name>NACKCF</name>
              <bitOffset>4</bitOffset>
              <bitWidth>1</bitWidth>
            </field>
            <field>
              <name>STOPCF</name>
              <bitOffset>5</bitOffset>
              <bitWidth>1</bitWidth>
            </field>
            <field>
              <name>BERRCF</name>
              <bitOffset>8</bitOffset>
              <bitWidth>1</bitWidth>
            </field>
            <field>
              <name>ARLOCF</name>
              <bitOffset>9</bitOffset>
              <bitWidth>1</bitWidth>
            </field>
            <field>
              <name>OVRCF</name>
              <bitOffset>10</bitOffset>
              <bitWidth>1</bitWidth>
            </field>
            <field>
              <name>PECCF</name>
              <bitOffset>11</bitOffset>
              <bitWidth>1</bitWidth>
            </field>
            <field>
              <name>TIMOUTCF</name>
              <bitOffset>12</bitOffset>
              <bitWidth>1</bitWidth>
            </field>
            <field>
              <name>ALERTCF</name>
              <bitOffset>13</bitOffset>
              <bitWidth>1</bitWidth>
            </field>
          </fields>
        </register>
        <register>
          <name>PECR</name>
          <addressOffset>0x20</addressOffset>
          <size>0x20</size>
          <fields>
            <field>
              <name>PEC</name>
              <bitOffset>0</bitOffset>
              <bitWidth>8</bitWidth>
            </field>
          </fields>
        </register>
        <register>
          <name>RXDR</name>
          <addressOffset>0x24</addressOffset>
          <size>0x20</size>
          <fields>
            <field>
              <name>RXDATA</name>
              <bitOffset>0</bitOffset>
              <bitWidth>8</bitWidth>
            </field>
          </fields>
        </register>
        <register>
          <name>TXDR</name>
          <addressOffset>0x28</addressOffset>
          <size>0x20</size>
          <fields>
            <field>
              <name>TXDATA</name>
              <bitOffset>0</bitOffset>
              <bitWidth>8</bitWidth>
            </field>
          </fields>
        </register>
      </registers>
    </peripheral>
    <peripheral>
      <name>USB</name>
      <baseAddress>0x40005c00</baseAddress>
      <registers>
        <register>
          <name>EP0R</name>
          <addressOffset>0x0</addressOffset>
          <size>0x10</size>
        </register>
        <register>
          <name>EP1R</name>
          <addressOffset>0x4</addressOffset>
          <size>0x10</size>
        </register>
        <register>
          <name>EP2R</name>
          <addressOffset>0x8</addressOffset>
          <size>0x10</size>
        </register>
        <register>
          <name>EP3R</name>
          <addressOffset>0xc</addressOffset>
          <size>0x10</size>
        </register>
        <register>
          <name>EP4R</name>
          <addressOffset>0x10</addressOffset>
          <size>0x10</size>
        </register>
        <register>
          <name>EP5R</name>
          <addressOffset>0x14</addressOffset>
          <size>0x10</size>
        </register>
        <register>
          <name>EP6R</name>
          <addressOffset>0x18</addressOffset>
          <size>0x10</size>
        </register>
        <register>
          <name>EP7R</name>
          <addressOffset>0x1c</addressOffset>
          <size>0x10</size>
        </register>
        <register>
          <name>CNTR</name>
          <addressOffset>0x40</addressOffset>
          <size>0x10</size>
        </register>
        <register>
          <name>ISTR</name>
          <addressOffset>0x44</addressOffset>
          <size>0x10</size>
        </register>
        <register>
          <name>FNR</name>
          <addressOffset>0x48</addressOffset>
          <size>0x10</size>
        </register>
        <register>
          <name>DADDR</name>
          <addressOffset>0x4c</addressOffset>
          <size>0x10</size>
        </register>
        <register>
          <name>BTABLE</name>
          <addressOffset>0x50</addressOffset>
          <size>0x10</size>
        </register>
        <register>
          <name>LPMCSR</name>
          <addressOffset>0x54</addressOffset>
          <size>0x10</size>
        </register>
        <register>
          <name>BCDR</name>
          <addressOffset>0x58</addressOffset>
          <size>0x10</size>
        </register>
      </registers>
    </peripheral>
    <peripheral>
      <name>CAN</name>
      <baseAddress>0x40006400</baseAddress>
      <registers>
        <register>
          <name>MCR</name>
          <addressOffset>0x0</addressOffset>
          <size>0x20</size>
          <fields>
            <field>
              <name>INRQ</name>
              <bitOffset>0</bitOffset>
              <bitWidth>1</bitWidth>
            </field>
            <field>
              <name>SLEEP</name>
              <bitOffset>1</bitOffset>
              <bitWidth>1</bitWidth>
            </field>
            <field>
              <name>TXFP</name>
              <bitOffset>2</bitOffset>
              <bitWidth>1</bitWidth>
            </field>
            <field>
              <name>RFLM</name>
              <bitOffset>3</bitOffset>
              <bitWidth>1</bitWidth>
            </field>
            <field>
              <name>NART</name>
              <bitOffset>4</bitOffset>
              <bitWidth>1</bitWidth>
            </field>
            <field>
              <name>AWUM</name>
              <bitOffset>5</bitOffset>
              <bitWidth>1</bitWidth>
            </field>
            <field>
              <name>ABOM</name>
              <bitOffset>6</bitOffset>
              <bitWidth>1</bitWidth>
            </field>
            <field>
              <name>TTCM</name>
              <bitOffset>7</bitOffset>
              <bitWidth>1</bitWidth>
            </field>
            <field>
              <name>RESET</name>
              <bitOffset>15</bitOffset>
              <bitWidth>1</bitWidth>
            </field>
          </fields>
        </register>
        <register>
          <name>MSR</name>
          <addressOffset>0x4</addressOffset>
          <size>0x20</size>
          <fields>
            <field>
              <name>INAK</name>
              <bitOffset>0</bitOffset>
              <bitWidth>1</bitWidth>
            </field>
            <field>
              <name>SLAK</name>
              <bitOffset>1</bitOffset>
              <bitWidth>1</bitWidth>
            </field>
            <field>
              <name>ERRI</name>
              <bitOffset>2</bitOffset>
              <bitWidth>1</bitWidth>
            </field>
            <field>
              <name>WKUI</name>
              <bitOffset>3</bitOffset>
              <bitWidth>1</bitWidth>
            </field>
            <field>
              <name>SLAKI</name>
              <bitOffset>4</bitOffset>
              <bitWidth>1</bitWidth>
            </field>
            <field>
              <name>TXM</name>
              <bitOffset>8</bitOffset>
              <bitWidth>1</bitWidth>
            </field>
            <field>
              <name>RXM</name>
              <bitOffset>9</bitOffset>
              <bitWidth>1</bitWidth>
            </field>
            <field>
              <name>SAMP</name>
              <bitOffset>10</bitOffset>
              <bitWidth>1</bitWidth>
            </field>
            <field>
              <name>RX</name>
              <bitOffset>11</bitOffset>
              <bitWidth>1</bitWidth>
            </field>
          </fields>
        </register>
        <register>
          <name>TSR</name>
          <addressOffset>0x8</addressOffset>
          <size>0x20</size>
          <fields>
            <field>
              <name>RQCP0</name>
              <bitOffset>0</bitOffset>
              <bitWidth>1</bitWidth>
            </field>
            <field>
              <name>TXOK0</name>
              <bitOffset>1</bitOffset>
              <bitWidth>1</bitWidth>
            </field>
            <field>
              <name>ALST0</name>
              <bitOffset>2</bitOffset>
              <bitWidth>1</bitWidth>
            </field>
            <field>
              <name>TERR0</name>
              <bitOffset>3</bitOffset>
              <bitWidth>1</bitWidth>
            </field>
            <field>
              <name>ABRQ0</name>
              <bitOffset>7</bitOffset>
              <bitWidth>1</bitWidth>
            </field>
            <field>
              <name>RQCP1</name>
              <bitOffset>8</bitOffset>
              <bitWidth>1</bitWidth>
            </field>
            <field>
              <name>TXOK1</name>
              <bitOffset>9</bitOffset>
              <bitWidth>1</bitWidth>
            </field>
            <field>
              <name>ALST1</name>
              <bitOffset>10</bitOffset>
              <bitWidth>1</bitWidth>
            </field>
            <field>
              <name>TERR1</name>
              <bitOffset>11</bitOffset>
              <bitWidth>1</bitWidth>
            </field>
            <field>
              <name>ABRQ1</name>
              <bitOffset>15</bitOffset>
              <bitWidth>1</bitWidth>
            </field>
            <field>
              <name>RQCP2</name>
              <bitOffset>16</bitOffset>
              <bitWidth>1</bitWidth>
            </field>
            <field>
              <name>TXOK2</name>
              <bitOffset>17</bitOffset>
              <bitWidth>1</bitWidth>
            </field>
            <field>
              <name>ALST2</name>
              <bitOffset>18</bitOffset>
              <bitWidth>1</bitWidth>
            </field>
            <field>
              <name>TERR2</name>
              <bitOffset>19</bitOffset>
              <bitWidth>1</bitWidth>
            </field>
            <field>
              <name>ABRQ2</name>
              <bitOffset>23</bitOffset>
              <bitWidth>1</bitWidth>
            </field>
            <field>
              <name>CODE</name>
              <bitOffset>24</bitOffset>
              <bitWidth>2</bitWidth>
            </field>
            <field>
              <name>TME0</name>
              <bitOffset>26</bitOffset>
              <bitWidth>1</bitWidth>
            </field>
            <field>
              <name>TME1</name>
              <bitOffset>27</bitOffset>
              <bitWidth>1</bitWidth>
            </field>
            <field>
              <name>TME2</name>
              <bitOffset>28</bitOffset>
              <bitWidth>1</bitWidth>
            </field>
            <field>
              <name>LOW0</name>
              <bitOffset>29</bitOffset>
              <bitWidth>1</bitWidth>
            </field>
            <field>
              <name>LOW1</name>
              <bitOffset>30</bitOffset>
              <bitWidth>1</bitWidth>
            </field>
            <field>
              <name>LOW2</name>
              <bitOffset>31</bitOffset>
              <bitWidth>1</bitWidth>
            </field>
          </fields>
        </register>
        <register>
          <name>RF0R</name>
          <addressOffset>0xc</addressOffset>
          <size>0x20</size>
          <fields>
            <field>
              <name>FMP0</name>
              <bitOffset>0</bitOffset>
              <bitWidth>2</bitWidth>
            </field>
            <field>
              <name>FULL0</name>
              <bitOffset>3</bitOffset>
              <bitWidth>1</bitWidth>
            </field>
            <field>
              <name>FOVR0</name>
              <bitOffset>4</bitOffset>
              <bitWidth>1</bitWidth>
            </field>
            <field>
              <name>RFOM0</name>
              <bitOffset>5</bitOffset>
              <bitWidth>1</bitWidth>
            </field>
          </fields>
        </register>
        <register>
          <name>RF1R</name>
          <addressOffset>0x10</addressOffset>
          <size>0x20</size>
          <fields>
            <field>
              <name>FMP1</name>
              <bitOffset>0</bitOffset>
              <bitWidth>2</bitWidth>
            </field>
            <field>
              <name>FULL1</name>
              <bitOffset>3</bitOffset>
              <bitWidth>1</bitWidth>
            </field>
            <field>
              <name>FOVR1</name>
              <bitOffset>4</bitOffset>
              <bitWidth>1</bitWidth>
            </field>
            <field>
              <name>RFOM1</name>
              <bitOffset>5</bitOffset>
              <bitWidth>1</bitWidth>
            </field>
          </fields>
        </register>
        <register>
          <name>IER</name>
          <addressOffset>0x14</addressOffset>
          <size>0x20</size>
          <fields>
            <field>
              <name>TMEIE</name>
              <bitOffset>0</bitOffset>
              <bitWidth>1</bitWidth>
            </field>
            <field>
              <name>FMPIE0</name>
              <bitOffset>1</bitOffset>
              <bitWidth>1</bitWidth>
            </field>
            <field>
              <name>FFIE0</name>
              <bitOffset>2</bitOffset>
              <bitWidth>1</bitWidth>
            </field>
            <field>
              <name>FOVIE0</name>
              <bitOffset>3</bitOffset>
              <bitWidth>1</bitWidth>
            </field>
            <field>
              <name>FMPIE1</name>
              <bitOffset>4</bitOffset>
              <bitWidth>1</bitWidth>
            </field>
            <field>
              <name>FFIE1</name>
              <bitOffset>5</bitOffset>
              <bitWidth>1</bitWidth>
            </field>
            <field>
              <name>FOVIE1</name>
              <bitOffset>6</bitOffset>
              <bitWidth>1</bitWidth>
            </field>
            <field>
              <name>EWGIE</name>
              <bitOffset>8</bitOffset>
              <bitWidth>1</bitWidth>
            </field>
            <field>
              <name>EPVIE</name>
              <bitOffset>9</bitOffset>
              <bitWidth>1</bitWidth>
            </field>
            <field>
              <name>BOFIE</name>
              <bitOffset>10</bitOffset>
              <bitWidth>1</bitWidth>
            </field>
            <field>
              <name>LECIE</name>
              <bitOffset>11</bitOffset>
              <bitWidth>1</bitWidth>
            </field>
            <field>
              <name>ERRIE</name>
              <bitOffset>15</bitOffset>
              <bitWidth>1</bitWidth>
            </field>
            <field>
              <name>WKUIE</name>
              <bitOffset>16</bitOffset>
              <bitWidth>1</bitWidth>
            </field>
            <field>
              <name>SLKIE</name>
              <bitOffset>17</bitOffset>
              <bitWidth>1</bitWidth>
            </field>
          </fields>
        </register>
        <register>
          <name>ESR</name>
          <addressOffset>0x18</addressOffset>
          <size>0x20</size>
          <fields>
            <field>
              <name>EWGF</name>
              <bitOffset>0</bitOffset>
              <bitWidth>1</bitWidth>
            </field>
            <field>
              <name>EPVF</name>
              <bitOffset>1</bitOffset>
              <bitWidth>1</bitWidth>
            </field>
            <field>
              <name>BOFF</name>
              <bitOffset>2</bitOffset>
              <bitWidth>1</bitWidth>
            </field>
            <field>
              <name>LEC</name>
              <bitOffset>4</bitOffset>
              <bitWidth>3</bitWidth>
            </field>
            <field>
              <name>TEC</name>
              <bitOffset>16</bitOffset>
              <bitWidth>8</bitWidth>
            </field>
            <field>
              <name>REC</name>
              <bitOffset>24</bitOffset>
              <bitWidth>8</bitWidth>
            </field>
          </fields>
        </register>
        <register>
          <name>BTR</name>
          <addressOffset>0x1c</addressOffset>
          <size>0x20</size>
          <fields>
            <field>
              <name>BRP</name>
              <bitOffset>0</bitOffset>
              <bitWidth>10</bitWidth>
            </field>
            <field>
              <name>TS1</name>
              <bitOffset>16</bitOffset>
              <bitWidth>4</bitWidth>
            </field>
            <field>
              <name>TS2</name>
              <bitOffset>20</bitOffset>
              <bitWidth>3</bitWidth>
            </field>
            <field>
              <name>SJW</name>
              <bitOffset>24</bitOffset>
              <bitWidth>2</bitWidth>
            </field>
            <field>
              <name>LBKM</name>
              <bitOffset>30</bitOffset>
              <bitWidth>1</bitWidth>
            </field>
            <field>
              <name>SILM</name>
              <bitOffset>31</bitOffset>
              <bitWidth>1</bitWidth>
            </field>
          </fields>
        </register>
        <register>
          <name>sTxMailBox.0.TIR</name>
          <addressOffset>0x180</addressOffset>
          <size>0x20</size>
          <fields>
            <field>
              <name>TXRQ</name>
              <bitOffset>0</bitOffset>
              <bitWidth>1</bitWidth>
            </field>
            <field>
              <name>RTR</name>
              <bitOffset>1</bitOffset>
              <bitWidth>1</bitWidth>
            </field>
            <field>
              <name>IDE</name>
              <bitOffset>2</bitOffset>
              <bitWidth>1</bitWidth>
            </field>
            <field>
              <name>EXID</name>
              <bitOffset>3</bitOffset>
              <bitWidth>18</bitWidth>
            </field>
            <field>
              <name>STID</name>
              <bitOffset>21</bitOffset>
              <bitWidth>11</bitWidth>
            </field>
          </fields>
        </register>
        <register>
          <name>sTxMailBox.0.TDTR</name>
          <addressOffset>0x184</addressOffset>
          <size>0x20</size>
          <fields>
            <field>
              <name>DLC</name>
              <bitOffset>0</bitOffset>
              <bitWidth>4</bitWidth>
            </field>
            <field>
              <name>TGT</name>
              <bitOffset>8</bitOffset>
              <bitWidth>1</bitWidth>
            </field>
            <field>
              <name>TIME</name>
              <bitOffset>16</bitOffset>
              <bitWidth>16</bitWidth>
            </field>
          </fields>
        </register>
        <register>
          <name>sTxMailBox.0.TDLR</name>
          <addressOffset>0x188</addressOffset>
          <size>0x20</size>
          <fields>
            <field>
              <name>DATA0</name>
              <bitOffset>0</bitOffset>
              <bitWidth>8</bitWidth>
            </field>
            <field>
              <name>DATA1</name>
              <bitOffset>8</bitOffset>
              <bitWidth>8</bitWidth>
            </field>
            <field>
              <name>DATA2</name>
              <bitOffset>16</bitOffset>
              <bitWidth>8</bitWidth>
            </field>
            <field>
              <name>DATA3</name>
              <bitOffset>24</bitOffset>
              <bitWidth>8</bitWidth>
            </field>
          </fields>
        </register>
        <register>
          <name>sTxMailBox.0.TDHR</name>
          <addressOffset>0x18c</addressOffset>
          <size>0x20</size>
          <fields>
            <field>
              <name>DATA4</name>
              <bitOffset>0</bitOffset>
              <bitWidth>8</bitWidth>
            </field>
            <field>
              <name>DATA5</name>
              <bitOffset>8</bitOffset>
              <bitWidth>8</bitWidth>
            </field>
            <field>
              <name>DATA6</name>
              <bitOffset>16</bitOffset>
              <bitWidth>8</bitWidth>
            </field>
            <field>
              <name>DATA7</name>
              <bitOffset>24</bitOffset>
              <bitWidth>8</bitWidth>
            </field>
          </fields>
        </register>
        <register>
          <name>sTxMailBox.1.TIR</name>
          <addressOffset>0x190</addressOffset>
          <size>0x20</size>
          <fields>
            <field>
              <name>TXRQ</name>
              <bitOffset>0</bitOffset>
              <bitWidth>1</bitWidth>
            </field>
            <field>
              <name>RTR</name>
              <bitOffset>1</bitOffset>
              <bitWidth>1</bitWidth>
            </field>
            <field>
              <name>IDE</name>
              <bitOffset>2</bitOffset>
              <bitWidth>1</bitWidth>
            </field>
            <field>
              <name>EXID</name>
              <bitOffset>3</bitOffset>
              <bitWidth>18</bitWidth>
            </field>
            <field>
              <name>STID</name>
              <bitOffset>21</bitOffset>
              <bitWidth>11</bitWidth>
            </field>
          </fields>
        </register>
        <register>
          <name>sTxMailBox.1.TDTR</name>
          <addressOffset>0x194</addressOffset>
          <size>0x20</size>
          <fields>
            <field>
              <name>DLC</name>
              <bitOffset>0</bitOffset>
              <bitWidth>4</bitWidth>
            </field>
            <field>
              <name>TGT</name>
              <bitOffset>8</bitOffset>
              <bitWidth>1</bitWidth>
            </field>
            <field>
              <name>TIME</name>
              <bitOffset>16</bitOffset>
              <bitWidth>16</bitWidth>
            </field>
          </fields>
        </register>
        <register>
          <name>sTxMailBox.1.TDLR</name>
          <addressOffset>0x198</addressOffset>
          <size>0x20</size>
          <fields>
            <field>
              <name>DATA0</name>
              <bitOffset>0</bitOffset>
              <bitWidth>8</bitWidth>
            </field>
            <field>
              <name>DATA1</name>
              <bitOffset>8</bitOffset>
              <bitWidth>8</bitWidth>
            </field>
            <field>
              <name>DATA2</name>
              <bitOffset>16</bitOffset>
              <bitWidth>8</bitWidth>
            </field>
            <field>
              <name>DATA3</name>
              <bitOffset>24</bitOffset>
              <bitWidth>8</bitWidth>
            </field>
          </fields>
        </register>
        <register>
          <name>sTxMailBox.1.TDHR</name>
          <addressOffset>0x19c</addressOffset>
          <size>0x20</size>
          <fields>
            <field>
              <name>DATA4</name>
              <bitOffset>0</bitOffset>
              <bitWidth>8</bitWidth>
            </field>
            <field>
              <name>DATA5</name>
              <bitOffset>8</bitOffset>
              <bitWidth>8</bitWidth>
            </field>
            <field>
              <name>DATA6</name>
              <bitOffset>16</bitOffset>
              <bitWidth>8</bitWidth>
            </field>
            <field>
              <name>DATA7</name>
              <bitOffset>24</bitOffset>
              <bitWidth>8</bitWidth>
            </field>
          </fields>
        </register>
        <register>
          <name>sTxMailBox.2.TIR</name>
          <addressOffset>0x1a0</addressOffset>
          <size>0x20</size>
          <fields>
            <field>
              <name>TXRQ</name>
              <bitOffset>0</bitOffset>
              <bitWidth>1</bitWidth>
            </field>
            <field>
              <name>RTR</name>
              <bitOffset>1</bitOffset>
              <bitWidth>1</bitWidth>
            </field>
            <field>
              <name>IDE</name>
              <bitOffset>2</bitOffset>
              <bitWidth>1</bitWidth>
            </field>
            <field>
              <name>EXID</name>
              <bitOffset>3</bitOffset>
              <bitWidth>18</bitWidth>
            </field>
            <field>
              <name>STID</name>
              <bitOffset>21</bitOffset>
              <bitWidth>11</bitWidth>
            </field>
          </fields>
        </register>
        <register>
          <name>sTxMailBox.2.TDTR</name>
          <addressOffset>0x1a4</addressOffset>
          <size>0x20</size>
          <fields>
            <field>
              <name>DLC</name>
              <bitOffset>0</bitOffset>
              <bitWidth>4</bitWidth>
            </field>
            <field>
              <name>TGT</name>
              <bitOffset>8</bitOffset>
              <bitWidth>1</bitWidth>
            </field>
            <field>
              <name>TIME</name>
              <bitOffset>16</bitOffset>
              <bitWidth>16</bitWidth>
            </field>
          </fields>
        </register>
        <register>
          <name>sTxMailBox.2.TDLR</name>
          <addressOffset>0x1a8</addressOffset>
          <size>0x20</size>
          <fields>
            <field>
              <name>DATA0</name>
              <bitOffset>0</bitOffset>
              <bitWidth>8</bitWidth>
            </field>
            <field>
              <name>DATA1</name>
              <bitOffset>8</bitOffset>
              <bitWidth>8</bitWidth>
            </field>
            <field>
              <name>DATA2</name>
              <bitOffset>16</bitOffset>
              <bitWidth>8</bitWidth>
            </field>
            <field>
              <name>DATA3</name>
              <bitOffset>24</bitOffset>
              <bitWidth>8</bitWidth>
            </field>
          </fields>
        </register>
        <register>
          <name>sTxMailBox.2.TDHR</name>
          <addressOffset>0x1ac</addressOffset>
          <size>0x20</size>
          <fields>
            <field>
              <name>DATA4</name>
              <bitOffset>0</bitOffset>
              <bitWidth>8</bitWidth>
            </field>
            <field>
              <name>DATA5</name>
              <bitOffset>8</bitOffset>
              <bitWidth>8</bitWidth>
            </field>
            <field>
              <name>DATA6</name>
              <bitOffset>16</bitOffset>
              <bitWidth>8</bitWidth>
            </field>
            <field>
              <name>DATA7</name>
              <bitOffset>24</bitOffset>
              <bitWidth>8</bitWidth>
            </field>
          </fields>
        </register>
        <register>
          <name>sFIFOMailBox.0.RIR</name>
          <addressOffset>0x1b0</addressOffset>
          <size>0x20</size>
          <fields>
            <field>
              <name>RTR</name>
              <bitOffset>1</bitOffset>
              <bitWidth>1</bitWidth>
            </field>
            <field>
              <name>IDE</name>
              <bitOffset>2</bitOffset>
              <bitWidth>1</bitWidth>
            </field>
            <field>
              <name>EXID</name>
              <bitOffset>3</bitOffset>
              <bitWidth>18</bitWidth>
            </field>
            <field>
              <name>STID</name>
              <bitOffset>21</bitOffset>
              <bitWidth>11</bitWidth>
            </field>
          </fields>
        </register>
        <register>
          <name>sFIFOMailBox.0.RDTR</name>
          <addressOffset>0x1b4</addressOffset>
          <size>0x20</size>
          <fields>
            <field>
              <name>DLC</name>
              <bitOffset>0</bitOffset>
              <bitWidth>4</bitWidth>
            </field>
            <field>
              <name>FMI</name>
              <bitOffset>8</bitOffset>
              <bitWidth>8</bitWidth>
            </field>
            <field>
              <name>TIME</name>
              <bitOffset>16</bitOffset>
              <bitWidth>16</bitWidth>
            </field>
          </fields>
        </register>
        <register>
          <name>sFIFOMailBox.0.RDLR</name>
          <addressOffset>0x1b8</addressOffset>
          <size>0x20</size>
          <fields>
            <field>
              <name>DATA0</name>
              <bitOffset>0</bitOffset>
              <bitWidth>8</bitWidth>
            </field>
            <field>
              <name>DATA1</name>
              <bitOffset>8</bitOffset>
              <bitWidth>8</bitWidth>
            </field>
            <field>
              <name>DATA2</name>
              <bitOffset>16</bitOffset>
              <bitWidth>8</bitWidth>
            </field>
            <field>
              <name>DATA3</name>
              <bitOffset>24</bitOffset>
              <bitWidth>8</bitWidth>
            </field>
          </fields>
        </register>
        <register>
          <name>sFIFOMailBox.0.RDHR</name>
          <addressOffset>0x1bc</addressOffset>
          <size>0x20</size>
          <fields>
            <field>
              <name>DATA4</name>
              <bitOffset>0</bitOffset>
              <bitWidth>8</bitWidth>
            </field>
            <field>
              <name>DATA5</name>
              <bitOffset>8</bitOffset>
              <bitWidth>8</bitWidth>
            </field>
            <field>
              <name>DATA6</name>
              <bitOffset>16</bitOffset>
              <bitWidth>8</bitWidth>
            </field>
            <field>
              <name>DATA7</name>
              <bitOffset>24</bitOffset>
              <bitWidth>8</bitWidth>
            </field>
          </fields>
        </register>
        <register>
          <name>sFIFOMailBox.1.RIR</name>
          <addressOffset>0x1c0</addressOffset>
          <size>0x20</size>
          <fields>
            <field>
              <name>RTR</name>
              <bitOffset>1</bitOffset>
              <bitWidth>1</bitWidth>
            </field>
            <field>
              <name>IDE</name>
              <bitOffset>2</bitOffset>
              <bitWidth>1</bitWidth>
            </field>
            <field>
              <name>EXID</name>
              <bitOffset>3</bitOffset>
              <bitWidth>18</bitWidth>
            </field>
            <field>
              <name>STID</name>
              <bitOffset>21</bitOffset>
              <bitWidth>11</bitWidth>
            </field>
          </fields>
        </register>
        <register>
          <name>sFIFOMailBox.1.RDTR</name>
          <addressOffset>0x1c4</addressOffset>
          <size>0x20</size>
          <fields>
            <field>
              <name>DLC</name>
              <bitOffset>0</bitOffset>
              <bitWidth>4</bitWidth>
            </field>
            <field>
              <name>FMI</name>
              <bitOffset>8</bitOffset>
              <bitWidth>8</bitWidth>
            </field>
            <field>
              <name>TIME</name>
              <bitOffset>16</bitOffset>
              <bitWidth>16</bitWidth>
            </field>
          </fields>
        </register>
        <register>
          <name>sFIFOMailBox.1.RDLR</name>
          <addressOffset>0x1c8</addressOffset>
          <size>0x20</size>
          <fields>
            <field>
              <name>DATA0</name>
              <bitOffset>0</bitOffset>
              <bitWidth>8</bitWidth>
            </field>
            <field>
              <name>DATA1</name>
              <bitOffset>8</bitOffset>
              <bitWidth>8</bitWidth>
            </field>
            <field>
              <name>DATA2</name>
              <bitOffset>16</bitOffset>
              <bitWidth>8</bitWidth>
            </field>
            <field>
              <name>DATA3</name>
              <bitOffset>24</bitOffset>
              <bitWidth>8</bitWidth>
            </field>
          </fields>
        </register>
        <register>
          <name>sFIFOMailBox.1.RDHR</name>
          <addressOffset>0x1cc</addressOffset>
          <size>0x20</size>
          <fields>
            <field>
              <name>DATA4</name>
              <bitOffset>0</bitOffset>
              <bitWidth>8</bitWidth>
            </field>
            <field>
              <name>DATA5</name>
              <bitOffset>8</bitOffset>
              <bitWidth>8</bitWidth>
            </field>
            <field>
              <name>DATA6</name>
              <bitOffset>16</bitOffset>
              <bitWidth>8</bitWidth>
            </field>
            <field>
              <name>DATA7</name>
              <bitOffset>24</bitOffset>
              <bitWidth>8</bitWidth>
            </field>
          </fields>
        </register>
        <register>
          <name>FMR</name>
          <addressOffset>0x200</addressOffset>
          <size>0x20</size>
          <fields>
            <field>
              <name>FINIT</name>
              <bitOffset>0</bitOffset>
              <bitWidth>1</bitWidth>
            </field>
            <field>
              <name>CAN2SB</name>
              <bitOffset>8</bitOffset>
              <bitWidth>6</bitWidth>
            </field>
          </fields>
        </register>
        <register>
          <name>FM1R</name>
          <addressOffset>0x204</addressOffset>
          <size>0x20</size>
          <fields>
            <field>
              <name>FBM0</name>
              <bitOffset>0</bitOffset>
              <bitWidth>1</bitWidth>
            </field>
            <field>
              <name>FBM1</name>
              <bitOffset>1</bitOffset>
              <bitWidth>1</bitWidth>
            </field>
            <field>
              <name>FBM2</name>
              <bitOffset>2</bitOffset>
              <bitWidth>1</bitWidth>
            </field>
            <field>
              <name>FBM3</name>
              <bitOffset>3</bitOffset>
              <bitWidth>1</bitWidth>
            </field>
            <field>
              <name>FBM4</name>
              <bitOffset>4</bitOffset>
              <bitWidth>1</bitWidth>
            </field>
            <field>
              <name>FBM5</name>
              <bitOffset>5</bitOffset>
              <bitWidth>1</bitWidth>
            </field>
            <field>
              <name>FBM6</name>
              <bitOffset>6</bitOffset>
              <bitWidth>1</bitWidth>
            </field>
            <field>
              <name>FBM7</name>
              <bitOffset>7</bitOffset>
              <bitWidth>1</bitWidth>
            </field>
            <field>
              <name>FBM8</name>
              <bitOffset>8</bitOffset>
              <bitWidth>1</bitWidth>
            </field>
            <field>
              <name>FBM9</name>
              <bitOffset>9</bitOffset>
              <bitWidth>1</bitWidth>
            </field>
            <field>
              <name>FBM10</name>
              <bitOffset>10</bitOffset>
              <bitWidth>1</bitWidth>
            </field>
            <field>
              <name>FBM11</name>
              <bitOffset>11</bitOffset>
              <bitWidth>1</bitWidth>
            </field>
            <field>
              <name>FBM12</name>
              <bitOffset>12</bitOffset>
              <bitWidth>1</bitWidth>
            </field>
            <field>
              <name>FBM13</name>
              <bitOffset>13</bitOffset>
              <bitWidth>1</bitWidth>
            </field>
            <field>
              <name>FBM14</name>
              <bitOffset>14</bitOffset>
              <bitWidth>1</bitWidth>
            </field>
            <field>
              <name>FBM15</name>
              <bitOffset>15</bitOffset>
              <bitWidth>1</bitWidth>
            </field>
            <field>
              <name>FBM16</name>
              <bitOffset>16</bitOffset>
              <bitWidth>1</bitWidth>
            </field>
            <field>
              <name>FBM17</name>
              <bitOffset>17</bitOffset>
              <bitWidth>1</bitWidth>
            </field>
            <field>
              <name>FBM18</name>
              <bitOffset>18</bitOffset>
              <bitWidth>1</bitWidth>
            </field>
            <field>
              <name>FBM19</name>
              <bitOffset>19</bitOffset>
              <bitWidth>1</bitWidth>
            </field>
            <field>
              <name>FBM20</name>
              <bitOffset>20</bitOffset>
              <bitWidth>1</bitWidth>
            </field>
            <field>
              <name>FBM21</name>
              <bitOffset>21</bitOffset>
              <bitWidth>1</bitWidth>
            </field>
            <field>
              <name>FBM22</name>
              <bitOffset>22</bitOffset>
              <bitWidth>1</bitWidth>
            </field>
            <field>
              <name>FBM23</name>
              <bitOffset>23</bitOffset>
              <bitWidth>1</bitWidth>
            </field>
            <field>
              <name>FBM24</name>
              <bitOffset>24</bitOffset>
              <bitWidth>1</bitWidth>
            </field>
            <field>
              <name>FBM25</name>
              <bitOffset>25</bitOffset>
              <bitWidth>1</bitWidth>
            </field>
            <field>
              <name>FBM26</name>
              <bitOffset>26</bitOffset>
              <bitWidth>1</bitWidth>
            </field>
            <field>
              <name>FBM27</name>
              <bitOffset>27</bitOffset>
              <bitWidth>1</bitWidth>
            </field>
          </fields>
        </register>
        <register>
          <name>FS1R</name>
          <addressOffset>0x20c</addressOffset>
          <size>0x20</size>
          <fields>
            <field>
              <name>FSC0</name>
              <bitOffset>0</bitOffset>
              <bitWidth>1</bitWidth>
            </field>
            <field>
              <name>FSC1</name>
              <bitOffset>1</bitOffset>
              <bitWidth>1</bitWidth>
            </field>
            <field>
              <name>FSC2</name>
              <bitOffset>2</bitOffset>
              <bitWidth>1</bitWidth>
            </field>
            <field>
              <name>FSC3</name>
              <bitOffset>3</bitOffset>
              <bitWidth>1</bitWidth>
            </field>
            <field>
              <name>FSC4</name>
              <bitOffset>4</bitOffset>
              <bitWidth>1</bitWidth>
            </field>
            <field>
              <name>FSC5</name>
              <bitOffset>5</bitOffset>
              <bitWidth>1</bitWidth>
            </field>
            <field>
              <name>FSC6</name>
              <bitOffset>6</bitOffset>
              <bitWidth>1</bitWidth>
            </field>
            <field>
              <name>FSC7</name>
              <bitOffset>7</bitOffset>
              <bitWidth>1</bitWidth>
            </field>
            <field>
              <name>FSC8</name>
              <bitOffset>8</bitOffset>
              <bitWidth>1</bitWidth>
            </field>
            <field>
              <name>FSC9</name>
              <bitOffset>9</bitOffset>
              <bitWidth>1</bitWidth>
            </field>
            <field>
              <name>FSC10</name>
              <bitOffset>10</bitOffset>
              <bitWidth>1</bitWidth>
            </field>
            <field>
              <name>FSC11</name>
              <bitOffset>11</bitOffset>
              <bitWidth>1</bitWidth>
            </field>
            <field>
              <name>FSC12</name>
              <bitOffset>12</bitOffset>
              <bitWidth>1</bitWidth>
            </field>
            <field>
              <name>FSC13</name>
              <bitOffset>13</bitOffset>
              <bitWidth>1</bitWidth>
            </field>
            <field>
              <name>FSC14</name>
              <bitOffset>14</bitOffset>
              <bitWidth>1</bitWidth>
            </field>
            <field>
              <name>FSC15</name>
              <bitOffset>15</bitOffset>
              <bitWidth>1</bitWidth>
            </field>
            <field>
              <name>FSC16</name>
              <bitOffset>16</bitOffset>
              <bitWidth>1</bitWidth>
            </field>
            <field>
              <name>FSC17</name>
              <bitOffset>17</bitOffset>
              <bitWidth>1</bitWidth>
            </field>
            <field>
              <name>FSC18</name>
              <bitOffset>18</bitOffset>
              <bitWidth>1</bitWidth>
            </field>
            <field>
              <name>FSC19</name>
              <bitOffset>19</bitOffset>
              <bitWidth>1</bitWidth>
            </field>
            <field>
              <name>FSC20</name>
              <bitOffset>20</bitOffset>
              <bitWidth>1</bitWidth>
            </field>
            <field>
              <name>FSC21</name>
              <bitOffset>21</bitOffset>
              <bitWidth>1</bitWidth>
            </field>
            <field>
              <name>FSC22</name>
              <bitOffset>22</bitOffset>
              <bitWidth>1</bitWidth>
            </field>
            <field>
              <name>FSC23</name>
              <bitOffset>23</bitOffset>
              <bitWidth>1</bitWidth>
            </field>
            <field>
              <name>FSC24</name>
              <bitOffset>24</bitOffset>
              <bitWidth>1</bitWidth>
            </field>
            <field>
              <name>FSC25</name>
              <bitOffset>25</bitOffset>
              <bitWidth>1</bitWidth>
            </field>
            <field>
              <name>FSC26</name>
              <bitOffset>26</bitOffset>
              <bitWidth>1</bitWidth>
            </field>
            <field>
              <name>FSC27</name>
              <bitOffset>27</bitOffset>
              <bitWidth>1</bitWidth>
            </field>
          </fields>
        </register>
        <register>
          <name>FFA1R</name>
          <addressOffset>0x214</addressOffset>
          <size>0x20</size>
          <fields>
            <field>
              <name>FFA0</name>
              <bitOffset>0</bitOffset>
              <bitWidth>1</bitWidth>
            </field>
            <field>
              <name>FFA1</name>
              <bitOffset>1</bitOffset>
              <bitWidth>1</bitWidth>
            </field>
            <field>
              <name>FFA2</name>
              <bitOffset>2</bitOffset>
              <bitWidth>1</bitWidth>
            </field>
            <field>
              <name>FFA3</name>
              <bitOffset>3</bitOffset>
              <bitWidth>1</bitWidth>
            </field>
            <field>
              <name>FFA4</name>
              <bitOffset>4</bitOffset>
              <bitWidth>1</bitWidth>
            </field>
            <field>
              <name>FFA5</name>
              <bitOffset>5</bitOffset>
              <bitWidth>1</bitWidth>
            </field>
            <field>
              <name>FFA6</name>
              <bitOffset>6</bitOffset>
              <bitWidth>1</bitWidth>
            </field>
            <field>
              <name>FFA7</name>
              <bitOffset>7</bitOffset>
              <bitWidth>1</bitWidth>
            </field>
            <field>
              <name>FFA8</name>
              <bitOffset>8</bitOffset>
              <bitWidth>1</bitWidth>
            </field>
            <field>
              <name>FFA9</name>
              <bitOffset>9</bitOffset>
              <bitWidth>1</bitWidth>
            </field>
            <field>
              <name>FFA10</name>
              <bitOffset>10</bitOffset>
              <bitWidth>1</bitWidth>
            </field>
            <field>
              <name>FFA11</name>
              <bitOffset>11</bitOffset>
              <bitWidth>1</bitWidth>
            </field>
            <field>
              <name>FFA12</name>
              <bitOffset>12</bitOffset>
              <bitWidth>1</bitWidth>
            </field>
            <field>
              <name>FFA13</name>
              <bitOffset>13</bitOffset>
              <bitWidth>1</bitWidth>
            </field>
            <field>
              <name>FFA14</name>
              <bitOffset>14</bitOffset>
              <bitWidth>1</bitWidth>
            </field>
            <field>
              <name>FFA15</name>
              <bitOffset>15</bitOffset>
              <bitWidth>1</bitWidth>
            </field>
            <field>
              <name>FFA16</name>
              <bitOffset>16</bitOffset>
              <bitWidth>1</bitWidth>
            </field>
            <field>
              <name>FFA17</name>
              <bitOffset>17</bitOffset>
              <bitWidth>1</bitWidth>
            </field>
            <field>
              <name>FFA18</name>
              <bitOffset>18</bitOffset>
              <bitWidth>1</bitWidth>
            </field>
            <field>
              <name>FFA19</name>
              <bitOffset>19</bitOffset>
              <bitWidth>1</bitWidth>
            </field>
            <field>
              <name>FFA20</name>
              <bitOffset>20</bitOffset>
              <bitWidth>1</bitWidth>
            </field>
            <field>
              <name>FFA21</name>
              <bitOffset>21</bitOffset>
              <bitWidth>1</bitWidth>
            </field>
            <field>
              <name>FFA22</name>
              <bitOffset>22</bitOffset>
              <bitWidth>1</bitWidth>
            </field>
            <field>
              <name>FFA23</name>
              <bitOffset>23</bitOffset>
              <bitWidth>1</bitWidth>
            </field>
            <field>
              <name>FFA24</name>
              <bitOffset>24</bitOffset>
              <bitWidth>1</bitWidth>
            </field>
            <field>
              <name>FFA25</name>
              <bitOffset>25</bitOffset>
              <bitWidth>1</bitWidth>
            </field>
            <field>
              <name>FFA26</name>
              <bitOffset>26</bitOffset>
              <bitWidth>1</bitWidth>
            </field>
            <field>
              <name>FFA27</name>
              <bitOffset>27</bitOffset>
              <bitWidth>1</bitWidth>
            </field>
          </fields>
        </register>
        <register>
          <name>FA1R</name>
          <addressOffset>0x21c</addressOffset>
          <size>0x20</size>
          <fields>
            <field>
              <name>FACT0</name>
              <bitOffset>0</bitOffset>
              <bitWidth>1</bitWidth>
            </field>
            <field>
              <name>FACT1</name>
              <bitOffset>1</bitOffset>
              <bitWidth>1</bitWidth>
            </field>
            <field>
              <name>FACT2</name>
              <bitOffset>2</bitOffset>
              <bitWidth>1</bitWidth>
            </field>
            <field>
              <name>FACT3</name>
              <bitOffset>3</bitOffset>
              <bitWidth>1</bitWidth>
            </field>
            <field>
              <name>FACT4</name>
              <bitOffset>4</bitOffset>
              <bitWidth>1</bitWidth>
            </field>
            <field>
              <name>FACT5</name>
              <bitOffset>5</bitOffset>
              <bitWidth>1</bitWidth>
            </field>
            <field>
              <name>FACT6</name>
              <bitOffset>6</bitOffset>
              <bitWidth>1</bitWidth>
            </field>
            <field>
              <name>FACT7</name>
              <bitOffset>7</bitOffset>
              <bitWidth>1</bitWidth>
            </field>
            <field>
              <name>FACT8</name>
              <bitOffset>8</bitOffset>
              <bitWidth>1</bitWidth>
            </field>
            <field>
              <name>FACT9</name>
              <bitOffset>9</bitOffset>
              <bitWidth>1</bitWidth>
            </field>
            <field>
              <name>FACT10</name>
              <bitOffset>10</bitOffset>
              <bitWidth>1</bitWidth>
            </field>
            <field>
              <name>FACT11</name>
              <bitOffset>11</bitOffset>
              <bitWidth>1</bitWidth>
            </field>
            <field>
              <name>FACT12</name>
              <bitOffset>12</bitOffset>
              <bitWidth>1</bitWidth>
            </field>
            <field>
              <name>FACT13</name>
              <bitOffset>13</bitOffset>
              <bitWidth>1</bitWidth>
            </field>
            <field>
              <name>FACT14</name>
              <bitOffset>14</bitOffset>
              <bitWidth>1</bitWidth>
            </field>
            <field>
              <name>FACT15</name>
              <bitOffset>15</bitOffset>
              <bitWidth>1</bitWidth>
            </field>
            <field>
              <name>FACT16</name>
              <bitOffset>16</bitOffset>
              <bitWidth>1</bitWidth>
            </field>
            <field>
              <name>FACT17</name>
              <bitOffset>17</bitOffset>
              <bitWidth>1</bitWidth>
            </field>
            <field>
              <name>FACT18</name>
              <bitOffset>18</bitOffset>
              <bitWidth>1</bitWidth>
            </field>
            <field>
              <name>FACT19</name>
              <bitOffset>19</bitOffset>
              <bitWidth>1</bitWidth>
            </field>
            <field>
              <name>FACT20</name>
              <bitOffset>20</bitOffset>
              <bitWidth>1</bitWidth>
            </field>
            <field>
              <name>FACT21</name>
              <bitOffset>21</bitOffset>
              <bitWidth>1</bitWidth>
            </field>
            <field>
              <name>FACT22</name>
              <bitOffset>22</bitOffset>
              <bitWidth>1</bitWidth>
            </field>
            <field>
              <name>FACT23</name>
              <bitOffset>23</bitOffset>
              <bitWidth>1</bitWidth>
            </field>
            <field>
              <name>FACT24</name>
              <bitOffset>24</bitOffset>
              <bitWidth>1</bitWidth>
            </field>
            <field>
              <name>FACT25</name>
              <bitOffset>25</bitOffset>
              <bitWidth>1</bitWidth>
            </field>
            <field>
              <name>FACT26</name>
              <bitOffset>26</bitOffset>
              <bitWidth>1</bitWidth>
            </field>
            <field>
              <name>FACT27</name>
              <bitOffset>27</bitOffset>
              <bitWidth>1</bitWidth>
            </field>
          </fields>
        </register>
        <register>
          <name>sFilterRegister.0.FR1</name>
          <addressOffset>0x240</addressOffset>
          <size>0x20</size>
          <fields>
            <field>
              <name>FB0</name>
              <bitOffset>0</bitOffset>
              <bitWidth>1</bitWidth>
            </field>
            <field>
              <name>FB1</name>
              <bitOffset>1</bitOffset>
              <bitWidth>1</bitWidth>
            </field>
            <field>
              <name>FB2</name>
              <bitOffset>2</bitOffset>
              <bitWidth>1</bitWidth>
            </field>
            <field>
              <name>FB3</name>
              <bitOffset>3</bitOffset>
              <bitWidth>1</bitWidth>
            </field>
            <field>
              <name>FB4</name>
              <bitOffset>4</bitOffset>
              <bitWidth>1</bitWidth>
            </field>
            <field>
              <name>FB5</name>
              <bitOffset>5</bitOffset>
              <bitWidth>1</bitWidth>
            </field>
            <field>
              <name>FB6</name>
              <bitOffset>6</bitOffset>
              <bitWidth>1</bitWidth>
            </field>
            <field>
              <name>FB7</name>
              <bitOffset>7</bitOffset>
              <bitWidth>1</bitWidth>
            </field>
            <field>
              <name>FB8</name>
              <bitOffset>8</bitOffset>
              <bitWidth>1</bitWidth>
            </field>
            <field>
              <name>FB9</name>
              <bitOffset>9</bitOffset>
              <bitWidth>1</bitWidth>
            </field>
            <field>
              <name>FB10</name>
              <bitOffset>10</bitOffset>
              <bitWidth>1</bitWidth>
            </field>
            <field>
              <name>FB11</name>
              <bitOffset>11</bitOffset>
              <bitWidth>1</bitWidth>
            </field>
            <field>
              <name>FB12</name>
              <bitOffset>12</bitOffset>
              <bitWidth>1</bitWidth>
            </field>
            <field>
              <name>FB13</name>
              <bitOffset>13</bitOffset>
              <bitWidth>1</bitWidth>
            </field>
            <field>
              <name>FB14</name>
              <bitOffset>14</bitOffset>
              <bitWidth>1</bitWidth>
            </field>
            <field>
              <name>FB15</name>
              <bitOffset>15</bitOffset>
              <bitWidth>1</bitWidth>
            </field>
            <field>
              <name>FB16</name>
              <bitOffset>16</bitOffset>
              <bitWidth>1</bitWidth>
            </field>
            <field>
              <name>FB17</name>
              <bitOffset>17</bitOffset>
              <bitWidth>1</bitWidth>
            </field>
            <field>
              <name>FB18</name>
              <bitOffset>18</bitOffset>
              <bitWidth>1</bitWidth>
            </field>
            <field>
              <name>FB19</name>
              <bitOffset>19</bitOffset>
              <bitWidth>1</bitWidth>
            </field>
            <field>
              <name>FB20</name>
              <bitOffset>20</bitOffset>
              <bitWidth>1</bitWidth>
            </field>
            <field>
              <name>FB21</name>
              <bitOffset>21</bitOffset>
              <bitWidth>1</bitWidth>
            </field>
            <field>
              <name>FB22</name>
              <bitOffset>22</bitOffset>
              <bitWidth>1</bitWidth>
            </field>
            <field>
              <name>FB23</name>
              <bitOffset>23</bitOffset>
              <bitWidth>1</bitWidth>
            </field>
            <field>
              <name>FB24</name>
              <bitOffset>24</bitOffset>
              <bitWidth>1</bitWidth>
            </field>
            <field>
              <name>FB25</name>
              <bitOffset>25</bitOffset>
              <bitWidth>1</bitWidth>
            </field>
            <field>
              <name>FB26</name>
              <bitOffset>26</bitOffset>
              <bitWidth>1</bitWidth>
            </field>
            <field>
              <name>FB27</name>
              <bitOffset>27</bitOffset>
              <bitWidth>1</bitWidth>
            </field>
            <field>
              <name>FB28</name>
              <bitOffset>28</bitOffset>
              <bitWidth>1</bitWidth>
            </field>
            <field>
              <name>FB29</name>
              <bitOffset>29</bitOffset>
              <bitWidth>1</bitWidth>
            </field>
            <field>
              <name>FB30</name>
              <bitOffset>30</bitOffset>
              <bitWidth>1</bitWidth>
            </field>
            <field>
              <name>FB31</name>
              <bitOffset>31</bitOffset>
              <bitWidth>1</bitWidth>
            </field>
          </fields>
        </register>
        <register>
          <name>sFilterRegister.0.FR2</name>
          <addressOffset>0x244</addressOffset>
          <size>0x20</size>
          <fields>
            <field>
              <name>FB0</name>
              <bitOffset>0</bitOffset>
              <bitWidth>1</bitWidth>
            </field>
            <field>
              <name>FB1</name>
              <bitOffset>1</bitOffset>
              <bitWidth>1</bitWidth>
            </field>
            <field>
              <name>FB2</name>
              <bitOffset>2</bitOffset>
              <bitWidth>1</bitWidth>
            </field>
            <field>
              <name>FB3</name>
              <bitOffset>3</bitOffset>
              <bitWidth>1</bitWidth>
            </field>
            <field>
              <name>FB4</name>
              <bitOffset>4</bitOffset>
              <bitWidth>1</bitWidth>
            </field>
            <field>
              <name>FB5</name>
              <bitOffset>5</bitOffset>
              <bitWidth>1</bitWidth>
            </field>
            <field>
              <name>FB6</name>
              <bitOffset>6</bitOffset>
              <bitWidth>1</bitWidth>
            </field>
            <field>
              <name>FB7</name>
              <bitOffset>7</bitOffset>
              <bitWidth>1</bitWidth>
            </field>
            <field>
              <name>FB8</name>
              <bitOffset>8</bitOffset>
              <bitWidth>1</bitWidth>
            </field>
            <field>
              <name>FB9</name>
              <bitOffset>9</bitOffset>
              <bitWidth>1</bitWidth>
            </field>
            <field>
              <name>FB10</name>
              <bitOffset>10</bitOffset>
              <bitWidth>1</bitWidth>
            </field>
            <field>
              <name>FB11</name>
              <bitOffset>11</bitOffset>
              <bitWidth>1</bitWidth>
            </field>
            <field>
              <name>FB12</name>
              <bitOffset>12</bitOffset>
              <bitWidth>1</bitWidth>
            </field>
            <field>
              <name>FB13</name>
              <bitOffset>13</bitOffset>
              <bitWidth>1</bitWidth>
            </field>
            <field>
              <name>FB14</name>
              <bitOffset>14</bitOffset>
              <bitWidth>1</bitWidth>
            </field>
            <field>
              <name>FB15</name>
              <bitOffset>15</bitOffset>
              <bitWidth>1</bitWidth>
            </field>
            <field>
              <name>FB16</name>
              <bitOffset>16</bitOffset>
              <bitWidth>1</bitWidth>
            </field>
            <field>
              <name>FB17</name>
              <bitOffset>17</bitOffset>
              <bitWidth>1</bitWidth>
            </field>
            <field>
              <name>FB18</name>
              <bitOffset>18</bitOffset>
              <bitWidth>1</bitWidth>
            </field>
            <field>
              <name>FB19</name>
              <bitOffset>19</bitOffset>
              <bitWidth>1</bitWidth>
            </field>
            <field>
              <name>FB20</name>
              <bitOffset>20</bitOffset>
              <bitWidth>1</bitWidth>
            </field>
            <field>
              <name>FB21</name>
              <bitOffset>21</bitOffset>
              <bitWidth>1</bitWidth>
            </field>
            <field>
              <name>FB22</name>
              <bitOffset>22</bitOffset>
              <bitWidth>1</bitWidth>
            </field>
            <field>
              <name>FB23</name>
              <bitOffset>23</bitOffset>
              <bitWidth>1</bitWidth>
            </field>
            <field>
              <name>FB24</name>
              <bitOffset>24</bitOffset>
              <bitWidth>1</bitWidth>
            </field>
            <field>
              <name>FB25</name>
              <bitOffset>25</bitOffset>
              <bitWidth>1</bitWidth>
            </field>
            <field>
              <name>FB26</name>
              <bitOffset>26</bitOffset>
              <bitWidth>1</bitWidth>
            </field>
            <field>
              <name>FB27</name>
              <bitOffset>27</bitOffset>
              <bitWidth>1</bitWidth>
            </field>
            <field>
              <name>FB28</name>
              <bitOffset>28</bitOffset>
              <bitWidth>1</bitWidth>
            </field>
            <field>
              <name>FB29</name>
              <bitOffset>29</bitOffset>
              <bitWidth>1</bitWidth>
            </field>
            <field>
              <name>FB30</name>
              <bitOffset>30</bitOffset>
              <bitWidth>1</bitWidth>
            </field>
            <field>
              <name>FB31</name>
              <bitOffset>31</bitOffset>
              <bitWidth>1</bitWidth>
            </field>
          </fields>
        </register>
        <register>
          <name>sFilterRegister.1.FR1</name>
          <addressOffset>0x248</addressOffset>
          <size>0x20</size>
          <fields>
            <field>
              <name>FB0</name>
              <bitOffset>0</bitOffset>
              <bitWidth>1</bitWidth>
            </field>
            <field>
              <name>FB1</name>
              <bitOffset>1</bitOffset>
              <bitWidth>1</bitWidth>
            </field>
            <field>
              <name>FB2</name>
              <bitOffset>2</bitOffset>
              <bitWidth>1</bitWidth>
            </field>
            <field>
              <name>FB3</name>
              <bitOffset>3</bitOffset>
              <bitWidth>1</bitWidth>
            </field>
            <field>
              <name>FB4</name>
              <bitOffset>4</bitOffset>
              <bitWidth>1</bitWidth>
            </field>
            <field>
              <name>FB5</name>
              <bitOffset>5</bitOffset>
              <bitWidth>1</bitWidth>
            </field>
            <field>
              <name>FB6</name>
              <bitOffset>6</bitOffset>
              <bitWidth>1</bitWidth>
            </field>
            <field>
              <name>FB7</name>
              <bitOffset>7</bitOffset>
              <bitWidth>1</bitWidth>
            </field>
            <field>
              <name>FB8</name>
              <bitOffset>8</bitOffset>
              <bitWidth>1</bitWidth>
            </field>
            <field>
              <name>FB9</name>
              <bitOffset>9</bitOffset>
              <bitWidth>1</bitWidth>
            </field>
            <field>
              <name>FB10</name>
              <bitOffset>10</bitOffset>
              <bitWidth>1</bitWidth>
            </field>
            <field>
              <name>FB11</name>
              <bitOffset>11</bitOffset>
              <bitWidth>1</bitWidth>
            </field>
            <field>
              <name>FB12</name>
              <bitOffset>12</bitOffset>
              <bitWidth>1</bitWidth>
            </field>
            <field>
              <name>FB13</name>
              <bitOffset>13</bitOffset>
              <bitWidth>1</bitWidth>
            </field>
            <field>
              <name>FB14</name>
              <bitOffset>14</bitOffset>
              <bitWidth>1</bitWidth>
            </field>
            <field>
              <name>FB15</name>
              <bitOffset>15</bitOffset>
              <bitWidth>1</bitWidth>
            </field>
            <field>
              <name>FB16</name>
              <bitOffset>16</bitOffset>
              <bitWidth>1</bitWidth>
            </field>
            <field>
              <name>FB17</name>
              <bitOffset>17</bitOffset>
              <bitWidth>1</bitWidth>
            </field>
            <field>
              <name>FB18</name>
              <bitOffset>18</bitOffset>
              <bitWidth>1</bitWidth>
            </field>
            <field>
              <name>FB19</name>
              <bitOffset>19</bitOffset>
              <bitWidth>1</bitWidth>
            </field>
            <field>
              <name>FB20</name>
              <bitOffset>20</bitOffset>
              <bitWidth>1</bitWidth>
            </field>
            <field>
              <name>FB21</name>
              <bitOffset>21</bitOffset>
              <bitWidth>1</bitWidth>
            </field>
            <field>
              <name>FB22</name>
              <bitOffset>22</bitOffset>
              <bitWidth>1</bitWidth>
            </field>
            <field>
              <name>FB23</name>
              <bitOffset>23</bitOffset>
              <bitWidth>1</bitWidth>
            </field>
            <field>
              <name>FB24</name>
              <bitOffset>24</bitOffset>
              <bitWidth>1</bitWidth>
            </field>
            <field>
              <name>FB25</name>
              <bitOffset>25</bitOffset>
              <bitWidth>1</bitWidth>
            </field>
            <field>
              <name>FB26</name>
              <bitOffset>26</bitOffset>
              <bitWidth>1</bitWidth>
            </field>
            <field>
              <name>FB27</name>
              <bitOffset>27</bitOffset>
              <bitWidth>1</bitWidth>
            </field>
            <field>
              <name>FB28</name>
              <bitOffset>28</bitOffset>
              <bitWidth>1</bitWidth>
            </field>
            <field>
              <name>FB29</name>
              <bitOffset>29</bitOffset>
              <bitWidth>1</bitWidth>
            </field>
            <field>
              <name>FB30</name>
              <bitOffset>30</bitOffset>
              <bitWidth>1</bitWidth>
            </field>
            <field>
              <name>FB31</name>
              <bitOffset>31</bitOffset>
              <bitWidth>1</bitWidth>
            </field>
          </fields>
        </register>
        <register>
          <name>sFilterRegister.1.FR2</name>
          <addressOffset>0x24c</addressOffset>
          <size>0x20</size>
          <fields>
            <field>
              <name>FB0</name>
              <bitOffset>0</bitOffset>
              <bitWidth>1</bitWidth>
            </field>
            <field>
              <name>FB1</name>
              <bitOffset>1</bitOffset>
              <bitWidth>1</bitWidth>
            </field>
            <field>
              <name>FB2</name>
              <bitOffset>2</bitOffset>
              <bitWidth>1</bitWidth>
            </field>
            <field>
              <name>FB3</name>
              <bitOffset>3</bitOffset>
              <bitWidth>1</bitWidth>
            </field>
            <field>
              <name>FB4</name>
              <bitOffset>4</bitOffset>
              <bitWidth>1</bitWidth>
            </field>
            <field>
              <name>FB5</name>
              <bitOffset>5</bitOffset>
              <bitWidth>1</bitWidth>
            </field>
            <field>
              <name>FB6</name>
              <bitOffset>6</bitOffset>
              <bitWidth>1</bitWidth>
            </field>
            <field>
              <name>FB7</name>
              <bitOffset>7</bitOffset>
              <bitWidth>1</bitWidth>
            </field>
            <field>
              <name>FB8</name>
              <bitOffset>8</bitOffset>
              <bitWidth>1</bitWidth>
            </field>
            <field>
              <name>FB9</name>
              <bitOffset>9</bitOffset>
              <bitWidth>1</bitWidth>
            </field>
            <field>
              <name>FB10</name>
              <bitOffset>10</bitOffset>
              <bitWidth>1</bitWidth>
            </field>
            <field>
              <name>FB11</name>
              <bitOffset>11</bitOffset>
              <bitWidth>1</bitWidth>
            </field>
            <field>
              <name>FB12</name>
              <bitOffset>12</bitOffset>
              <bitWidth>1</bitWidth>
            </field>
            <field>
              <name>FB13</name>
              <bitOffset>13</bitOffset>
              <bitWidth>1</bitWidth>
            </field>
            <field>
              <name>FB14</name>
              <bitOffset>14</bitOffset>
              <bitWidth>1</bitWidth>
            </field>
            <field>
              <name>FB15</name>
              <bitOffset>15</bitOffset>
              <bitWidth>1</bitWidth>
            </field>
            <field>
              <name>FB16</name>
              <bitOffset>16</bitOffset>
              <bitWidth>1</bitWidth>
            </field>
            <field>
              <name>FB17</name>
              <bitOffset>17</bitOffset>
              <bitWidth>1</bitWidth>
            </field>
            <field>
              <name>FB18</name>
              <bitOffset>18</bitOffset>
              <bitWidth>1</bitWidth>
            </field>
            <field>
              <name>FB19</name>
              <bitOffset>19</bitOffset>
              <bitWidth>1</bitWidth>
            </field>
            <field>
              <name>FB20</name>
              <bitOffset>20</bitOffset>
              <bitWidth>1</bitWidth>
            </field>
            <field>
              <name>FB21</name>
              <bitOffset>21</bitOffset>
              <bitWidth>1</bitWidth>
            </field>
            <field>
              <name>FB22</name>
              <bitOffset>22</bitOffset>
              <bitWidth>1</bitWidth>
            </field>
            <field>
              <name>FB23</name>
              <bitOffset>23</bitOffset>
              <bitWidth>1</bitWidth>
            </field>
            <field>
              <name>FB24</name>
              <bitOffset>24</bitOffset>
              <bitWidth>1</bitWidth>
            </field>
            <field>
              <name>FB25</name>
              <bitOffset>25</bitOffset>
              <bitWidth>1</bitWidth>
            </field>
            <field>
              <name>FB26</name>
              <bitOffset>26</bitOffset>
              <bitWidth>1</bitWidth>
            </field>
            <field>
              <name>FB27</name>
              <bitOffset>27</bitOffset>
              <bitWidth>1</bitWidth>
            </field>
            <field>
              <name>FB28</name>
              <bitOffset>28</bitOffset>
              <bitWidth>1</bitWidth>
            </field>
            <field>
              <name>FB29</name>
              <bitOffset>29</bitOffset>
              <bitWidth>1</bitWidth>
            </field>
            <field>
              <name>FB30</name>
              <bitOffset>30</bitOffset>
              <bitWidth>1</bitWidth>
            </field>
            <field>
              <name>FB31</name>
              <bitOffset>31</bitOffset>
              <bitWidth>1</bitWidth>
            </field>
          </fields>
        </register>
        <register>
          <name>sFilterRegister.2.FR1</name>
          <addressOffset>0x250</addressOffset>
          <size>0x20</size>
          <fields>
            <field>
              <name>FB0</name>
              <bitOffset>0</bitOffset>
              <bitWidth>1</bitWidth>
            </field>
            <field>
              <name>FB1</name>
              <bitOffset>1</bitOffset>
              <bitWidth>1</bitWidth>
            </field>
            <field>
              <name>FB2</name>
              <bitOffset>2</bitOffset>
              <bitWidth>1</bitWidth>
            </field>
            <field>
              <name>FB3</name>
              <bitOffset>3</bitOffset>
              <bitWidth>1</bitWidth>
            </field>
            <field>
              <name>FB4</name>
              <bitOffset>4</bitOffset>
              <bitWidth>1</bitWidth>
            </field>
            <field>
              <name>FB5</name>
              <bitOffset>5</bitOffset>
              <bitWidth>1</bitWidth>
            </field>
            <field>
              <name>FB6</name>
              <bitOffset>6</bitOffset>
              <bitWidth>1</bitWidth>
            </field>
            <field>
              <name>FB7</name>
              <bitOffset>7</bitOffset>
              <bitWidth>1</bitWidth>
            </field>
            <field>
              <name>FB8</name>
              <bitOffset>8</bitOffset>
              <bitWidth>1</bitWidth>
            </field>
            <field>
              <name>FB9</name>
              <bitOffset>9</bitOffset>
              <bitWidth>1</bitWidth>
            </field>
            <field>
              <name>FB10</name>
              <bitOffset>10</bitOffset>
              <bitWidth>1</bitWidth>
            </field>
            <field>
              <name>FB11</name>
              <bitOffset>11</bitOffset>
              <bitWidth>1</bitWidth>
            </field>
            <field>
              <name>FB12</name>
              <bitOffset>12</bitOffset>
              <bitWidth>1</bitWidth>
            </field>
            <field>
              <name>FB13</name>
              <bitOffset>13</bitOffset>
              <bitWidth>1</bitWidth>
            </field>
            <field>
              <name>FB14</name>
              <bitOffset>14</bitOffset>
              <bitWidth>1</bitWidth>
            </field>
            <field>
              <name>FB15</name>
              <bitOffset>15</bitOffset>
              <bitWidth>1</bitWidth>
            </field>
            <field>
              <name>FB16</name>
              <bitOffset>16</bitOffset>
              <bitWidth>1</bitWidth>
            </field>
            <field>
              <name>FB17</name>
              <bitOffset>17</bitOffset>
              <bitWidth>1</bitWidth>
            </field>
            <field>
              <name>FB18</name>
              <bitOffset>18</bitOffset>
              <bitWidth>1</bitWidth>
            </field>
            <field>
              <name>FB19</name>
              <bitOffset>19</bitOffset>
              <bitWidth>1</bitWidth>
            </field>
            <field>
              <name>FB20</name>
              <bitOffset>20</bitOffset>
              <bitWidth>1</bitWidth>
            </field>
            <field>
              <name>FB21</name>
              <bitOffset>21</bitOffset>
              <bitWidth>1</bitWidth>
            </field>
            <field>
              <name>FB22</name>
              <bitOffset>22</bitOffset>
              <bitWidth>1</bitWidth>
            </field>
            <field>
              <name>FB23</name>
              <bitOffset>23</bitOffset>
              <bitWidth>1</bitWidth>
            </field>
            <field>
              <name>FB24</name>
              <bitOffset>24</bitOffset>
              <bitWidth>1</bitWidth>
            </field>
            <field>
              <name>FB25</name>
              <bitOffset>25</bitOffset>
              <bitWidth>1</bitWidth>
            </field>
            <field>
              <name>FB26</name>
              <bitOffset>26</bitOffset>
              <bitWidth>1</bitWidth>
            </field>
            <field>
              <name>FB27</name>
              <bitOffset>27</bitOffset>
              <bitWidth>1</bitWidth>
            </field>
            <field>
              <name>FB28</name>
              <bitOffset>28</bitOffset>
              <bitWidth>1</bitWidth>
            </field>
            <field>
              <name>FB29</name>
              <bitOffset>29</bitOffset>
              <bitWidth>1</bitWidth>
            </field>
            <field>
              <name>FB30</name>
              <bitOffset>30</bitOffset>
              <bitWidth>1</bitWidth>
            </field>
            <field>
              <name>FB31</name>
              <bitOffset>31</bitOffset>
              <bitWidth>1</bitWidth>
            </field>
          </fields>
        </register>
        <register>
          <name>sFilterRegister.2.FR2</name>
          <addressOffset>0x254</addressOffset>
          <size>0x20</size>
          <fields>
            <field>
              <name>FB0</name>
              <bitOffset>0</bitOffset>
              <bitWidth>1</bitWidth>
            </field>
            <field>
              <name>FB1</name>
              <bitOffset>1</bitOffset>
              <bitWidth>1</bitWidth>
            </field>
            <field>
              <name>FB2</name>
              <bitOffset>2</bitOffset>
              <bitWidth>1</bitWidth>
            </field>
            <field>
              <name>FB3</name>
              <bitOffset>3</bitOffset>
              <bitWidth>1</bitWidth>
            </field>
            <field>
              <name>FB4</name>
              <bitOffset>4</bitOffset>
              <bitWidth>1</bitWidth>
            </field>
            <field>
              <name>FB5</name>
              <bitOffset>5</bitOffset>
              <bitWidth>1</bitWidth>
            </field>
            <field>
              <name>FB6</name>
              <bitOffset>6</bitOffset>
              <bitWidth>1</bitWidth>
            </field>
            <field>
              <name>FB7</name>
              <bitOffset>7</bitOffset>
              <bitWidth>1</bitWidth>
            </field>
            <field>
              <name>FB8</name>
              <bitOffset>8</bitOffset>
              <bitWidth>1</bitWidth>
            </field>
            <field>
              <name>FB9</name>
              <bitOffset>9</bitOffset>
              <bitWidth>1</bitWidth>
            </field>
            <field>
              <name>FB10</name>
              <bitOffset>10</bitOffset>
              <bitWidth>1</bitWidth>
            </field>
            <field>
              <name>FB11</name>
              <bitOffset>11</bitOffset>
              <bitWidth>1</bitWidth>
            </field>
            <field>
              <name>FB12</name>
              <bitOffset>12</bitOffset>
              <bitWidth>1</bitWidth>
            </field>
            <field>
              <name>FB13</name>
              <bitOffset>13</bitOffset>
              <bitWidth>1</bitWidth>
            </field>
            <field>
              <name>FB14</name>
              <bitOffset>14</bitOffset>
              <bitWidth>1</bitWidth>
            </field>
            <field>
              <name>FB15</name>
              <bitOffset>15</bitOffset>
              <bitWidth>1</bitWidth>
            </field>
            <field>
              <name>FB16</name>
              <bitOffset>16</bitOffset>
              <bitWidth>1</bitWidth>
            </field>
            <field>
              <name>FB17</name>
              <bitOffset>17</bitOffset>
              <bitWidth>1</bitWidth>
            </field>
            <field>
              <name>FB18</name>
              <bitOffset>18</bitOffset>
              <bitWidth>1</bitWidth>
            </field>
            <field>
              <name>FB19</name>
              <bitOffset>19</bitOffset>
              <bitWidth>1</bitWidth>
            </field>
            <field>
              <name>FB20</name>
              <bitOffset>20</bitOffset>
              <bitWidth>1</bitWidth>
            </field>
            <field>
              <name>FB21</name>
              <bitOffset>21</bitOffset>
              <bitWidth>1</bitWidth>
            </field>
            <field>
              <name>FB22</name>
              <bitOffset>22</bitOffset>
              <bitWidth>1</bitWidth>
            </field>
            <field>
              <name>FB23</name>
              <bitOffset>23</bitOffset>
              <bitWidth>1</bitWidth>
            </field>
            <field>
              <name>FB24</name>
              <bitOffset>24</bitOffset>
              <bitWidth>1</bitWidth>
            </field>
            <field>
              <name>FB25</name>
              <bitOffset>25</bitOffset>
              <bitWidth>1</bitWidth>
            </field>
            <field>
              <name>FB26</name>
              <bitOffset>26</bitOffset>
              <bitWidth>1</bitWidth>
            </field>
            <field>
              <name>FB27</name>
              <bitOffset>27</bitOffset>
              <bitWidth>1</bitWidth>
            </field>
            <field>
              <name>FB28</name>
              <bitOffset>28</bitOffset>
              <bitWidth>1</bitWidth>
            </field>
            <field>
              <name>FB29</name>
              <bitOffset>29</bitOffset>
              <bitWidth>1</bitWidth>
            </field>
            <field>
              <name>FB30</name>
              <bitOffset>30</bitOffset>
              <bitWidth>1</bitWidth>
            </field>
            <field>
              <name>FB31</name>
              <bitOffset>31</bitOffset>
              <bitWidth>1</bitWidth>
            </field>
          </fields>
        </register>
        <register>
          <name>sFilterRegister.3.FR1</name>
          <addressOffset>0x258</addressOffset>
          <size>0x20</size>
          <fields>
            <field>
              <name>FB0</name>
              <bitOffset>0</bitOffset>
              <bitWidth>1</bitWidth>
            </field>
            <field>
              <name>FB1</name>
              <bitOffset>1</bitOffset>
              <bitWidth>1</bitWidth>
            </field>
            <field>
              <name>FB2</name>
              <bitOffset>2</bitOffset>
              <bitWidth>1</bitWidth>
            </field>
            <field>
              <name>FB3</name>
              <bitOffset>3</bitOffset>
              <bitWidth>1</bitWidth>
            </field>
            <field>
              <name>FB4</name>
              <bitOffset>4</bitOffset>
              <bitWidth>1</bitWidth>
            </field>
            <field>
              <name>FB5</name>
              <bitOffset>5</bitOffset>
              <bitWidth>1</bitWidth>
            </field>
            <field>
              <name>FB6</name>
              <bitOffset>6</bitOffset>
              <bitWidth>1</bitWidth>
            </field>
            <field>
              <name>FB7</name>
              <bitOffset>7</bitOffset>
              <bitWidth>1</bitWidth>
            </field>
            <field>
              <name>FB8</name>
              <bitOffset>8</bitOffset>
              <bitWidth>1</bitWidth>
            </field>
            <field>
              <name>FB9</name>
              <bitOffset>9</bitOffset>
              <bitWidth>1</bitWidth>
            </field>
            <field>
              <name>FB10</name>
              <bitOffset>10</bitOffset>
              <bitWidth>1</bitWidth>
            </field>
            <field>
              <name>FB11</name>
              <bitOffset>11</bitOffset>
              <bitWidth>1</bitWidth>
            </field>
            <field>
              <name>FB12</name>
              <bitOffset>12</bitOffset>
              <bitWidth>1</bitWidth>
            </field>
            <field>
              <name>FB13</name>
              <bitOffset>13</bitOffset>
              <bitWidth>1</bitWidth>
            </field>
            <field>
              <name>FB14</name>
              <bitOffset>14</bitOffset>
              <bitWidth>1</bitWidth>
            </field>
            <field>
              <name>FB15</name>
              <bitOffset>15</bitOffset>
              <bitWidth>1</bitWidth>
            </field>
            <field>
              <name>FB16</name>
              <bitOffset>16</bitOffset>
              <bitWidth>1</bitWidth>
            </field>
            <field>
              <name>FB17</name>
              <bitOffset>17</bitOffset>
              <bitWidth>1</bitWidth>
            </field>
            <field>
              <name>FB18</name>
              <bitOffset>18</bitOffset>
              <bitWidth>1</bitWidth>
            </field>
            <field>
              <name>FB19</name>
              <bitOffset>19</bitOffset>
              <bitWidth>1</bitWidth>
            </field>
            <field>
              <name>FB20</name>
              <bitOffset>20</bitOffset>
              <bitWidth>1</bitWidth>
            </field>
            <field>
              <name>FB21</name>
              <bitOffset>21</bitOffset>
              <bitWidth>1</bitWidth>
            </field>
            <field>
              <name>FB22</name>
              <bitOffset>22</bitOffset>
              <bitWidth>1</bitWidth>
            </field>
            <field>
              <name>FB23</name>
              <bitOffset>23</bitOffset>
              <bitWidth>1</bitWidth>
            </field>
            <field>
              <name>FB24</name>
              <bitOffset>24</bitOffset>
              <bitWidth>1</bitWidth>
            </field>
            <field>
              <name>FB25</name>
              <bitOffset>25</bitOffset>
              <bitWidth>1</bitWidth>
            </field>
            <field>
              <name>FB26</name>
              <bitOffset>26</bitOffset>
              <bitWidth>1</bitWidth>
            </field>
            <field>
              <name>FB27</name>
              <bitOffset>27</bitOffset>
              <bitWidth>1</bitWidth>
            </field>
            <field>
              <name>FB28</name>
              <bitOffset>28</bitOffset>
              <bitWidth>1</bitWidth>
            </field>
            <field>
              <name>FB29</name>
              <bitOffset>29</bitOffset>
              <bitWidth>1</bitWidth>
            </field>
            <field>
              <name>FB30</name>
              <bitOffset>30</bitOffset>
              <bitWidth>1</bitWidth>
            </field>
            <field>
              <name>FB31</name>
              <bitOffset>31</bitOffset>
              <bitWidth>1</bitWidth>
            </field>
          </fields>
        </register>
        <register>
          <name>sFilterRegister.3.FR2</name>
          <addressOffset>0x25c</addressOffset>
          <size>0x20</size>
          <fields>
            <field>
              <name>FB0</name>
              <bitOffset>0</bitOffset>
              <bitWidth>1</bitWidth>
            </field>
            <field>
              <name>FB1</name>
              <bitOffset>1</bitOffset>
              <bitWidth>1</bitWidth>
            </field>
            <field>
              <name>FB2</name>
              <bitOffset>2</bitOffset>
              <bitWidth>1</bitWidth>
            </field>
            <field>
              <name>FB3</name>
              <bitOffset>3</bitOffset>
              <bitWidth>1</bitWidth>
            </field>
            <field>
              <name>FB4</name>
              <bitOffset>4</bitOffset>
              <bitWidth>1</bitWidth>
            </field>
            <field>
              <name>FB5</name>
              <bitOffset>5</bitOffset>
              <bitWidth>1</bitWidth>
            </field>
            <field>
              <name>FB6</name>
              <bitOffset>6</bitOffset>
              <bitWidth>1</bitWidth>
            </field>
            <field>
              <name>FB7</name>
              <bitOffset>7</bitOffset>
              <bitWidth>1</bitWidth>
            </field>
            <field>
              <name>FB8</name>
              <bitOffset>8</bitOffset>
              <bitWidth>1</bitWidth>
            </field>
            <field>
              <name>FB9</name>
              <bitOffset>9</bitOffset>
              <bitWidth>1</bitWidth>
            </field>
            <field>
              <name>FB10</name>
              <bitOffset>10</bitOffset>
              <bitWidth>1</bitWidth>
            </field>
            <field>
              <name>FB11</name>
              <bitOffset>11</bitOffset>
              <bitWidth>1</bitWidth>
            </field>
            <field>
              <name>FB12</name>
              <bitOffset>12</bitOffset>
              <bitWidth>1</bitWidth>
            </field>
            <field>
              <name>FB13</name>
              <bitOffset>13</bitOffset>
              <bitWidth>1</bitWidth>
            </field>
            <field>
              <name>FB14</name>
              <bitOffset>14</bitOffset>
              <bitWidth>1</bitWidth>
            </field>
            <field>
              <name>FB15</name>
              <bitOffset>15</bitOffset>
              <bitWidth>1</bitWidth>
            </field>
            <field>
              <name>FB16</name>
              <bitOffset>16</bitOffset>
              <bitWidth>1</bitWidth>
            </field>
            <field>
              <name>FB17</name>
              <bitOffset>17</bitOffset>
              <bitWidth>1</bitWidth>
            </field>
            <field>
              <name>FB18</name>
              <bitOffset>18</bitOffset>
              <bitWidth>1</bitWidth>
            </field>
            <field>
              <name>FB19</name>
              <bitOffset>19</bitOffset>
              <bitWidth>1</bitWidth>
            </field>
            <field>
              <name>FB20</name>
              <bitOffset>20</bitOffset>
              <bitWidth>1</bitWidth>
            </field>
            <field>
              <name>FB21</name>
              <bitOffset>21</bitOffset>
              <bitWidth>1</bitWidth>
            </field>
            <field>
              <name>FB22</name>
              <bitOffset>22</bitOffset>
              <bitWidth>1</bitWidth>
            </field>
            <field>
              <name>FB23</name>
              <bitOffset>23</bitOffset>
              <bitWidth>1</bitWidth>
            </field>
            <field>
              <name>FB24</name>
              <bitOffset>24</bitOffset>
              <bitWidth>1</bitWidth>
            </field>
            <field>
              <name>FB25</name>
              <bitOffset>25</bitOffset>
              <bitWidth>1</bitWidth>
            </field>
            <field>
              <name>FB26</name>
              <bitOffset>26</bitOffset>
              <bitWidth>1</bitWidth>
            </field>
            <field>
              <name>FB27</name>
              <bitOffset>27</bitOffset>
              <bitWidth>1</bitWidth>
            </field>
            <field>
              <name>FB28</name>
              <bitOffset>28</bitOffset>
              <bitWidth>1</bitWidth>
            </field>
            <field>
              <name>FB29</name>
              <bitOffset>29</bitOffset>
              <bitWidth>1</bitWidth>
            </field>
            <field>
              <name>FB30</name>
              <bitOffset>30</bitOffset>
              <bitWidth>1</bitWidth>
            </field>
            <field>
              <name>FB31</name>
              <bitOffset>31</bitOffset>
              <bitWidth>1</bitWidth>
            </field>
          </fields>
        </register>
        <register>
          <name>sFilterRegister.4.FR1</name>
          <addressOffset>0x260</addressOffset>
          <size>0x20</size>
          <fields>
            <field>
              <name>FB0</name>
              <bitOffset>0</bitOffset>
              <bitWidth>1</bitWidth>
            </field>
            <field>
              <name>FB1</name>
              <bitOffset>1</bitOffset>
              <bitWidth>1</bitWidth>
            </field>
            <field>
              <name>FB2</name>
              <bitOffset>2</bitOffset>
              <bitWidth>1</bitWidth>
            </field>
            <field>
              <name>FB3</name>
              <bitOffset>3</bitOffset>
              <bitWidth>1</bitWidth>
            </field>
            <field>
              <name>FB4</name>
              <bitOffset>4</bitOffset>
              <bitWidth>1</bitWidth>
            </field>
            <field>
              <name>FB5</name>
              <bitOffset>5</bitOffset>
              <bitWidth>1</bitWidth>
            </field>
            <field>
              <name>FB6</name>
              <bitOffset>6</bitOffset>
              <bitWidth>1</bitWidth>
            </field>
            <field>
              <name>FB7</name>
              <bitOffset>7</bitOffset>
              <bitWidth>1</bitWidth>
            </field>
            <field>
              <name>FB8</name>
              <bitOffset>8</bitOffset>
              <bitWidth>1</bitWidth>
            </field>
            <field>
              <name>FB9</name>
              <bitOffset>9</bitOffset>
              <bitWidth>1</bitWidth>
            </field>
            <field>
              <name>FB10</name>
              <bitOffset>10</bitOffset>
              <bitWidth>1</bitWidth>
            </field>
            <field>
              <name>FB11</name>
              <bitOffset>11</bitOffset>
              <bitWidth>1</bitWidth>
            </field>
            <field>
              <name>FB12</name>
              <bitOffset>12</bitOffset>
              <bitWidth>1</bitWidth>
            </field>
            <field>
              <name>FB13</name>
              <bitOffset>13</bitOffset>
              <bitWidth>1</bitWidth>
            </field>
            <field>
              <name>FB14</name>
              <bitOffset>14</bitOffset>
              <bitWidth>1</bitWidth>
            </field>
            <field>
              <name>FB15</name>
              <bitOffset>15</bitOffset>
              <bitWidth>1</bitWidth>
            </field>
            <field>
              <name>FB16</name>
              <bitOffset>16</bitOffset>
              <bitWidth>1</bitWidth>
            </field>
            <field>
              <name>FB17</name>
              <bitOffset>17</bitOffset>
              <bitWidth>1</bitWidth>
            </field>
            <field>
              <name>FB18</name>
              <bitOffset>18</bitOffset>
              <bitWidth>1</bitWidth>
            </field>
            <field>
              <name>FB19</name>
              <bitOffset>19</bitOffset>
              <bitWidth>1</bitWidth>
            </field>
            <field>
              <name>FB20</name>
              <bitOffset>20</bitOffset>
              <bitWidth>1</bitWidth>
            </field>
            <field>
              <name>FB21</name>
              <bitOffset>21</bitOffset>
              <bitWidth>1</bitWidth>
            </field>
            <field>
              <name>FB22</name>
              <bitOffset>22</bitOffset>
              <bitWidth>1</bitWidth>
            </field>
            <field>
              <name>FB23</name>
              <bitOffset>23</bitOffset>
              <bitWidth>1</bitWidth>
            </field>
            <field>
              <name>FB24</name>
              <bitOffset>24</bitOffset>
              <bitWidth>1</bitWidth>
            </field>
            <field>
              <name>FB25</name>
              <bitOffset>25</bitOffset>
              <bitWidth>1</bitWidth>
            </field>
            <field>
              <name>FB26</name>
              <bitOffset>26</bitOffset>
              <bitWidth>1</bitWidth>
            </field>
            <field>
              <name>FB27</name>
              <bitOffset>27</bitOffset>
              <bitWidth>1</bitWidth>
            </field>
            <field>
              <name>FB28</name>
              <bitOffset>28</bitOffset>
              <bitWidth>1</bitWidth>
            </field>
            <field>
              <name>FB29</name>
              <bitOffset>29</bitOffset>
              <bitWidth>1</bitWidth>
            </field>
            <field>
              <name>FB30</name>
              <bitOffset>30</bitOffset>
              <bitWidth>1</bitWidth>
            </field>
            <field>
              <name>FB31</name>
              <bitOffset>31</bitOffset>
              <bitWidth>1</bitWidth>
            </field>
          </fields>
        </register>
        <register>
          <name>sFilterRegister.4.FR2</name>
          <addressOffset>0x264</addressOffset>
          <size>0x20</size>
          <fields>
            <field>
              <name>FB0</name>
              <bitOffset>0</bitOffset>
              <bitWidth>1</bitWidth>
            </field>
            <field>
              <name>FB1</name>
              <bitOffset>1</bitOffset>
              <bitWidth>1</bitWidth>
            </field>
            <field>
              <name>FB2</name>
              <bitOffset>2</bitOffset>
              <bitWidth>1</bitWidth>
            </field>
            <field>
              <name>FB3</name>
              <bitOffset>3</bitOffset>
              <bitWidth>1</bitWidth>
            </field>
            <field>
              <name>FB4</name>
              <bitOffset>4</bitOffset>
              <bitWidth>1</bitWidth>
            </field>
            <field>
              <name>FB5</name>
              <bitOffset>5</bitOffset>
              <bitWidth>1</bitWidth>
            </field>
            <field>
              <name>FB6</name>
              <bitOffset>6</bitOffset>
              <bitWidth>1</bitWidth>
            </field>
            <field>
              <name>FB7</name>
              <bitOffset>7</bitOffset>
              <bitWidth>1</bitWidth>
            </field>
            <field>
              <name>FB8</name>
              <bitOffset>8</bitOffset>
              <bitWidth>1</bitWidth>
            </field>
            <field>
              <name>FB9</name>
              <bitOffset>9</bitOffset>
              <bitWidth>1</bitWidth>
            </field>
            <field>
              <name>FB10</name>
              <bitOffset>10</bitOffset>
              <bitWidth>1</bitWidth>
            </field>
            <field>
              <name>FB11</name>
              <bitOffset>11</bitOffset>
              <bitWidth>1</bitWidth>
            </field>
            <field>
              <name>FB12</name>
              <bitOffset>12</bitOffset>
              <bitWidth>1</bitWidth>
            </field>
            <field>
              <name>FB13</name>
              <bitOffset>13</bitOffset>
              <bitWidth>1</bitWidth>
            </field>
            <field>
              <name>FB14</name>
              <bitOffset>14</bitOffset>
              <bitWidth>1</bitWidth>
            </field>
            <field>
              <name>FB15</name>
              <bitOffset>15</bitOffset>
              <bitWidth>1</bitWidth>
            </field>
            <field>
              <name>FB16</name>
              <bitOffset>16</bitOffset>
              <bitWidth>1</bitWidth>
            </field>
            <field>
              <name>FB17</name>
              <bitOffset>17</bitOffset>
              <bitWidth>1</bitWidth>
            </field>
            <field>
              <name>FB18</name>
              <bitOffset>18</bitOffset>
              <bitWidth>1</bitWidth>
            </field>
            <field>
              <name>FB19</name>
              <bitOffset>19</bitOffset>
              <bitWidth>1</bitWidth>
            </field>
            <field>
              <name>FB20</name>
              <bitOffset>20</bitOffset>
              <bitWidth>1</bitWidth>
            </field>
            <field>
              <name>FB21</name>
              <bitOffset>21</bitOffset>
              <bitWidth>1</bitWidth>
            </field>
            <field>
              <name>FB22</name>
              <bitOffset>22</bitOffset>
              <bitWidth>1</bitWidth>
            </field>
            <field>
              <name>FB23</name>
              <bitOffset>23</bitOffset>
              <bitWidth>1</bitWidth>
            </field>
            <field>
              <name>FB24</name>
              <bitOffset>24</bitOffset>
              <bitWidth>1</bitWidth>
            </field>
            <field>
              <name>FB25</name>
              <bitOffset>25</bitOffset>
              <bitWidth>1</bitWidth>
            </field>
            <field>
              <name>FB26</name>
              <bitOffset>26</bitOffset>
              <bitWidth>1</bitWidth>
            </field>
            <field>
              <name>FB27</name>
              <bitOffset>27</bitOffset>
              <bitWidth>1</bitWidth>
            </field>
            <field>
              <name>FB28</name>
              <bitOffset>28</bitOffset>
              <bitWidth>1</bitWidth>
            </field>
            <field>
              <name>FB29</name>
              <bitOffset>29</bitOffset>
              <bitWidth>1</bitWidth>
            </field>
            <field>
              <name>FB30</name>
              <bitOffset>30</bitOffset>
              <bitWidth>1</bitWidth>
            </field>
            <field>
              <name>FB31</name>
              <bitOffset>31</bitOffset>
              <bitWidth>1</bitWidth>
            </field>
          </fields>
        </register>
        <register>
          <name>sFilterRegister.5.FR1</name>
          <addressOffset>0x268</addressOffset>
          <size>0x20</size>
          <fields>
            <field>
              <name>FB0</name>
              <bitOffset>0</bitOffset>
              <bitWidth>1</bitWidth>
            </field>
            <field>
              <name>FB1</name>
              <bitOffset>1</bitOffset>
              <bitWidth>1</bitWidth>
            </field>
            <field>
              <name>FB2</name>
              <bitOffset>2</bitOffset>
              <bitWidth>1</bitWidth>
            </field>
            <field>
              <name>FB3</name>
              <bitOffset>3</bitOffset>
              <bitWidth>1</bitWidth>
            </field>
            <field>
              <name>FB4</name>
              <bitOffset>4</bitOffset>
              <bitWidth>1</bitWidth>
            </field>
            <field>
              <name>FB5</name>
              <bitOffset>5</bitOffset>
              <bitWidth>1</bitWidth>
            </field>
            <field>
              <name>FB6</name>
              <bitOffset>6</bitOffset>
              <bitWidth>1</bitWidth>
            </field>
            <field>
              <name>FB7</name>
              <bitOffset>7</bitOffset>
              <bitWidth>1</bitWidth>
            </field>
            <field>
              <name>FB8</name>
              <bitOffset>8</bitOffset>
              <bitWidth>1</bitWidth>
            </field>
            <field>
              <name>FB9</name>
              <bitOffset>9</bitOffset>
              <bitWidth>1</bitWidth>
            </field>
            <field>
              <name>FB10</name>
              <bitOffset>10</bitOffset>
              <bitWidth>1</bitWidth>
            </field>
            <field>
              <name>FB11</name>
              <bitOffset>11</bitOffset>
              <bitWidth>1</bitWidth>
            </field>
            <field>
              <name>FB12</name>
              <bitOffset>12</bitOffset>
              <bitWidth>1</bitWidth>
            </field>
            <field>
              <name>FB13</name>
              <bitOffset>13</bitOffset>
              <bitWidth>1</bitWidth>
            </field>
            <field>
              <name>FB14</name>
              <bitOffset>14</bitOffset>
              <bitWidth>1</bitWidth>
            </field>
            <field>
              <name>FB15</name>
              <bitOffset>15</bitOffset>
              <bitWidth>1</bitWidth>
            </field>
            <field>
              <name>FB16</name>
              <bitOffset>16</bitOffset>
              <bitWidth>1</bitWidth>
            </field>
            <field>
              <name>FB17</name>
              <bitOffset>17</bitOffset>
              <bitWidth>1</bitWidth>
            </field>
            <field>
              <name>FB18</name>
              <bitOffset>18</bitOffset>
              <bitWidth>1</bitWidth>
            </field>
            <field>
              <name>FB19</name>
              <bitOffset>19</bitOffset>
              <bitWidth>1</bitWidth>
            </field>
            <field>
              <name>FB20</name>
              <bitOffset>20</bitOffset>
              <bitWidth>1</bitWidth>
            </field>
            <field>
              <name>FB21</name>
              <bitOffset>21</bitOffset>
              <bitWidth>1</bitWidth>
            </field>
            <field>
              <name>FB22</name>
              <bitOffset>22</bitOffset>
              <bitWidth>1</bitWidth>
            </field>
            <field>
              <name>FB23</name>
              <bitOffset>23</bitOffset>
              <bitWidth>1</bitWidth>
            </field>
            <field>
              <name>FB24</name>
              <bitOffset>24</bitOffset>
              <bitWidth>1</bitWidth>
            </field>
            <field>
              <name>FB25</name>
              <bitOffset>25</bitOffset>
              <bitWidth>1</bitWidth>
            </field>
            <field>
              <name>FB26</name>
              <bitOffset>26</bitOffset>
              <bitWidth>1</bitWidth>
            </field>
            <field>
              <name>FB27</name>
              <bitOffset>27</bitOffset>
              <bitWidth>1</bitWidth>
            </field>
            <field>
              <name>FB28</name>
              <bitOffset>28</bitOffset>
              <bitWidth>1</bitWidth>
            </field>
            <field>
              <name>FB29</name>
              <bitOffset>29</bitOffset>
              <bitWidth>1</bitWidth>
            </field>
            <field>
              <name>FB30</name>
              <bitOffset>30</bitOffset>
              <bitWidth>1</bitWidth>
            </field>
            <field>
              <name>FB31</name>
              <bitOffset>31</bitOffset>
              <bitWidth>1</bitWidth>
            </field>
          </fields>
        </register>
        <register>
          <name>sFilterRegister.5.FR2</name>
          <addressOffset>0x26c</addressOffset>
          <size>0x20</size>
          <fields>
            <field>
              <name>FB0</name>
              <bitOffset>0</bitOffset>
              <bitWidth>1</bitWidth>
            </field>
            <field>
              <name>FB1</name>
              <bitOffset>1</bitOffset>
              <bitWidth>1</bitWidth>
            </field>
            <field>
              <name>FB2</name>
              <bitOffset>2</bitOffset>
              <bitWidth>1</bitWidth>
            </field>
            <field>
              <name>FB3</name>
              <bitOffset>3</bitOffset>
              <bitWidth>1</bitWidth>
            </field>
            <field>
              <name>FB4</name>
              <bitOffset>4</bitOffset>
              <bitWidth>1</bitWidth>
            </field>
            <field>
              <name>FB5</name>
              <bitOffset>5</bitOffset>
              <bitWidth>1</bitWidth>
            </field>
            <field>
              <name>FB6</name>
              <bitOffset>6</bitOffset>
              <bitWidth>1</bitWidth>
            </field>
            <field>
              <name>FB7</name>
              <bitOffset>7</bitOffset>
              <bitWidth>1</bitWidth>
            </field>
            <field>
              <name>FB8</name>
              <bitOffset>8</bitOffset>
              <bitWidth>1</bitWidth>
            </field>
            <field>
              <name>FB9</name>
              <bitOffset>9</bitOffset>
              <bitWidth>1</bitWidth>
            </field>
            <field>
              <name>FB10</name>
              <bitOffset>10</bitOffset>
              <bitWidth>1</bitWidth>
            </field>
            <field>
              <name>FB11</name>
              <bitOffset>11</bitOffset>
              <bitWidth>1</bitWidth>
            </field>
            <field>
              <name>FB12</name>
              <bitOffset>12</bitOffset>
              <bitWidth>1</bitWidth>
            </field>
            <field>
              <name>FB13</name>
              <bitOffset>13</bitOffset>
              <bitWidth>1</bitWidth>
            </field>
            <field>
              <name>FB14</name>
              <bitOffset>14</bitOffset>
              <bitWidth>1</bitWidth>
            </field>
            <field>
              <name>FB15</name>
              <bitOffset>15</bitOffset>
              <bitWidth>1</bitWidth>
            </field>
            <field>
              <name>FB16</name>
              <bitOffset>16</bitOffset>
              <bitWidth>1</bitWidth>
            </field>
            <field>
              <name>FB17</name>
              <bitOffset>17</bitOffset>
              <bitWidth>1</bitWidth>
            </field>
            <field>
              <name>FB18</name>
              <bitOffset>18</bitOffset>
              <bitWidth>1</bitWidth>
            </field>
            <field>
              <name>FB19</name>
              <bitOffset>19</bitOffset>
              <bitWidth>1</bitWidth>
            </field>
            <field>
              <name>FB20</name>
              <bitOffset>20</bitOffset>
              <bitWidth>1</bitWidth>
            </field>
            <field>
              <name>FB21</name>
              <bitOffset>21</bitOffset>
              <bitWidth>1</bitWidth>
            </field>
            <field>
              <name>FB22</name>
              <bitOffset>22</bitOffset>
              <bitWidth>1</bitWidth>
            </field>
            <field>
              <name>FB23</name>
              <bitOffset>23</bitOffset>
              <bitWidth>1</bitWidth>
            </field>
            <field>
              <name>FB24</name>
              <bitOffset>24</bitOffset>
              <bitWidth>1</bitWidth>
            </field>
            <field>
              <name>FB25</name>
              <bitOffset>25</bitOffset>
              <bitWidth>1</bitWidth>
            </field>
            <field>
              <name>FB26</name>
              <bitOffset>26</bitOffset>
              <bitWidth>1</bitWidth>
            </field>
            <field>
              <name>FB27</name>
              <bitOffset>27</bitOffset>
              <bitWidth>1</bitWidth>
            </field>
            <field>
              <name>FB28</name>
              <bitOffset>28</bitOffset>
              <bitWidth>1</bitWidth>
            </field>
            <field>
              <name>FB29</name>
              <bitOffset>29</bitOffset>
              <bitWidth>1</bitWidth>
            </field>
            <field>
              <name>FB30</name>
              <bitOffset>30</bitOffset>
              <bitWidth>1</bitWidth>
            </field>
            <field>
              <name>FB31</name>
              <bitOffset>31</bitOffset>
              <bitWidth>1</bitWidth>
            </field>
          </fields>
        </register>
        <register>
          <name>sFilterRegister.6.FR1</name>
          <addressOffset>0x270</addressOffset>
          <size>0x20</size>
          <fields>
            <field>
              <name>FB0</name>
              <bitOffset>0</bitOffset>
              <bitWidth>1</bitWidth>
            </field>
            <field>
              <name>FB1</name>
              <bitOffset>1</bitOffset>
              <bitWidth>1</bitWidth>
            </field>
            <field>
              <name>FB2</name>
              <bitOffset>2</bitOffset>
              <bitWidth>1</bitWidth>
            </field>
            <field>
              <name>FB3</name>
              <bitOffset>3</bitOffset>
              <bitWidth>1</bitWidth>
            </field>
            <field>
              <name>FB4</name>
              <bitOffset>4</bitOffset>
              <bitWidth>1</bitWidth>
            </field>
            <field>
              <name>FB5</name>
              <bitOffset>5</bitOffset>
              <bitWidth>1</bitWidth>
            </field>
            <field>
              <name>FB6</name>
              <bitOffset>6</bitOffset>
              <bitWidth>1</bitWidth>
            </field>
            <field>
              <name>FB7</name>
              <bitOffset>7</bitOffset>
              <bitWidth>1</bitWidth>
            </field>
            <field>
              <name>FB8</name>
              <bitOffset>8</bitOffset>
              <bitWidth>1</bitWidth>
            </field>
            <field>
              <name>FB9</name>
              <bitOffset>9</bitOffset>
              <bitWidth>1</bitWidth>
            </field>
            <field>
              <name>FB10</name>
              <bitOffset>10</bitOffset>
              <bitWidth>1</bitWidth>
            </field>
            <field>
              <name>FB11</name>
              <bitOffset>11</bitOffset>
              <bitWidth>1</bitWidth>
            </field>
            <field>
              <name>FB12</name>
              <bitOffset>12</bitOffset>
              <bitWidth>1</bitWidth>
            </field>
            <field>
              <name>FB13</name>
              <bitOffset>13</bitOffset>
              <bitWidth>1</bitWidth>
            </field>
            <field>
              <name>FB14</name>
              <bitOffset>14</bitOffset>
              <bitWidth>1</bitWidth>
            </field>
            <field>
              <name>FB15</name>
              <bitOffset>15</bitOffset>
              <bitWidth>1</bitWidth>
            </field>
            <field>
              <name>FB16</name>
              <bitOffset>16</bitOffset>
              <bitWidth>1</bitWidth>
            </field>
            <field>
              <name>FB17</name>
              <bitOffset>17</bitOffset>
              <bitWidth>1</bitWidth>
            </field>
            <field>
              <name>FB18</name>
              <bitOffset>18</bitOffset>
              <bitWidth>1</bitWidth>
            </field>
            <field>
              <name>FB19</name>
              <bitOffset>19</bitOffset>
              <bitWidth>1</bitWidth>
            </field>
            <field>
              <name>FB20</name>
              <bitOffset>20</bitOffset>
              <bitWidth>1</bitWidth>
            </field>
            <field>
              <name>FB21</name>
              <bitOffset>21</bitOffset>
              <bitWidth>1</bitWidth>
            </field>
            <field>
              <name>FB22</name>
              <bitOffset>22</bitOffset>
              <bitWidth>1</bitWidth>
            </field>
            <field>
              <name>FB23</name>
              <bitOffset>23</bitOffset>
              <bitWidth>1</bitWidth>
            </field>
            <field>
              <name>FB24</name>
              <bitOffset>24</bitOffset>
              <bitWidth>1</bitWidth>
            </field>
            <field>
              <name>FB25</name>
              <bitOffset>25</bitOffset>
              <bitWidth>1</bitWidth>
            </field>
            <field>
              <name>FB26</name>
              <bitOffset>26</bitOffset>
              <bitWidth>1</bitWidth>
            </field>
            <field>
              <name>FB27</name>
              <bitOffset>27</bitOffset>
              <bitWidth>1</bitWidth>
            </field>
            <field>
              <name>FB28</name>
              <bitOffset>28</bitOffset>
              <bitWidth>1</bitWidth>
            </field>
            <field>
              <name>FB29</name>
              <bitOffset>29</bitOffset>
              <bitWidth>1</bitWidth>
            </field>
            <field>
              <name>FB30</name>
              <bitOffset>30</bitOffset>
              <bitWidth>1</bitWidth>
            </field>
            <field>
              <name>FB31</name>
              <bitOffset>31</bitOffset>
              <bitWidth>1</bitWidth>
            </field>
          </fields>
        </register>
        <register>
          <name>sFilterRegister.6.FR2</name>
          <addressOffset>0x274</addressOffset>
          <size>0x20</size>
          <fields>
            <field>
              <name>FB0</name>
              <bitOffset>0</bitOffset>
              <bitWidth>1</bitWidth>
            </field>
            <field>
              <name>FB1</name>
              <bitOffset>1</bitOffset>
              <bitWidth>1</bitWidth>
            </field>
            <field>
              <name>FB2</name>
              <bitOffset>2</bitOffset>
              <bitWidth>1</bitWidth>
            </field>
            <field>
              <name>FB3</name>
              <bitOffset>3</bitOffset>
              <bitWidth>1</bitWidth>
            </field>
            <field>
              <name>FB4</name>
              <bitOffset>4</bitOffset>
              <bitWidth>1</bitWidth>
            </field>
            <field>
              <name>FB5</name>
              <bitOffset>5</bitOffset>
              <bitWidth>1</bitWidth>
            </field>
            <field>
              <name>FB6</name>
              <bitOffset>6</bitOffset>
              <bitWidth>1</bitWidth>
            </field>
            <field>
              <name>FB7</name>
              <bitOffset>7</bitOffset>
              <bitWidth>1</bitWidth>
            </field>
            <field>
              <name>FB8</name>
              <bitOffset>8</bitOffset>
              <bitWidth>1</bitWidth>
            </field>
            <field>
              <name>FB9</name>
              <bitOffset>9</bitOffset>
              <bitWidth>1</bitWidth>
            </field>
            <field>
              <name>FB10</name>
              <bitOffset>10</bitOffset>
              <bitWidth>1</bitWidth>
            </field>
            <field>
              <name>FB11</name>
              <bitOffset>11</bitOffset>
              <bitWidth>1</bitWidth>
            </field>
            <field>
              <name>FB12</name>
              <bitOffset>12</bitOffset>
              <bitWidth>1</bitWidth>
            </field>
            <field>
              <name>FB13</name>
              <bitOffset>13</bitOffset>
              <bitWidth>1</bitWidth>
            </field>
            <field>
              <name>FB14</name>
              <bitOffset>14</bitOffset>
              <bitWidth>1</bitWidth>
            </field>
            <field>
              <name>FB15</name>
              <bitOffset>15</bitOffset>
              <bitWidth>1</bitWidth>
            </field>
            <field>
              <name>FB16</name>
              <bitOffset>16</bitOffset>
              <bitWidth>1</bitWidth>
            </field>
            <field>
              <name>FB17</name>
              <bitOffset>17</bitOffset>
              <bitWidth>1</bitWidth>
            </field>
            <field>
              <name>FB18</name>
              <bitOffset>18</bitOffset>
              <bitWidth>1</bitWidth>
            </field>
            <field>
              <name>FB19</name>
              <bitOffset>19</bitOffset>
              <bitWidth>1</bitWidth>
            </field>
            <field>
              <name>FB20</name>
              <bitOffset>20</bitOffset>
              <bitWidth>1</bitWidth>
            </field>
            <field>
              <name>FB21</name>
              <bitOffset>21</bitOffset>
              <bitWidth>1</bitWidth>
            </field>
            <field>
              <name>FB22</name>
              <bitOffset>22</bitOffset>
              <bitWidth>1</bitWidth>
            </field>
            <field>
              <name>FB23</name>
              <bitOffset>23</bitOffset>
              <bitWidth>1</bitWidth>
            </field>
            <field>
              <name>FB24</name>
              <bitOffset>24</bitOffset>
              <bitWidth>1</bitWidth>
            </field>
            <field>
              <name>FB25</name>
              <bitOffset>25</bitOffset>
              <bitWidth>1</bitWidth>
            </field>
            <field>
              <name>FB26</name>
              <bitOffset>26</bitOffset>
              <bitWidth>1</bitWidth>
            </field>
            <field>
              <name>FB27</name>
              <bitOffset>27</bitOffset>
              <bitWidth>1</bitWidth>
            </field>
            <field>
              <name>FB28</name>
              <bitOffset>28</bitOffset>
              <bitWidth>1</bitWidth>
            </field>
            <field>
              <name>FB29</name>
              <bitOffset>29</bitOffset>
              <bitWidth>1</bitWidth>
            </field>
            <field>
              <name>FB30</name>
              <bitOffset>30</bitOffset>
              <bitWidth>1</bitWidth>
            </field>
            <field>
              <name>FB31</name>
              <bitOffset>31</bitOffset>
              <bitWidth>1</bitWidth>
            </field>
          </fields>
        </register>
        <register>
          <name>sFilterRegister.7.FR1</name>
          <addressOffset>0x278</addressOffset>
          <size>0x20</size>
          <fields>
            <field>
              <name>FB0</name>
              <bitOffset>0</bitOffset>
              <bitWidth>1</bitWidth>
            </field>
            <field>
              <name>FB1</name>
              <bitOffset>1</bitOffset>
              <bitWidth>1</bitWidth>
            </field>
            <field>
              <name>FB2</name>
              <bitOffset>2</bitOffset>
              <bitWidth>1</bitWidth>
            </field>
            <field>
              <name>FB3</name>
              <bitOffset>3</bitOffset>
              <bitWidth>1</bitWidth>
            </field>
            <field>
              <name>FB4</name>
              <bitOffset>4</bitOffset>
              <bitWidth>1</bitWidth>
            </field>
            <field>
              <name>FB5</name>
              <bitOffset>5</bitOffset>
              <bitWidth>1</bitWidth>
            </field>
            <field>
              <name>FB6</name>
              <bitOffset>6</bitOffset>
              <bitWidth>1</bitWidth>
            </field>
            <field>
              <name>FB7</name>
              <bitOffset>7</bitOffset>
              <bitWidth>1</bitWidth>
            </field>
            <field>
              <name>FB8</name>
              <bitOffset>8</bitOffset>
              <bitWidth>1</bitWidth>
            </field>
            <field>
              <name>FB9</name>
              <bitOffset>9</bitOffset>
              <bitWidth>1</bitWidth>
            </field>
            <field>
              <name>FB10</name>
              <bitOffset>10</bitOffset>
              <bitWidth>1</bitWidth>
            </field>
            <field>
              <name>FB11</name>
              <bitOffset>11</bitOffset>
              <bitWidth>1</bitWidth>
            </field>
            <field>
              <name>FB12</name>
              <bitOffset>12</bitOffset>
              <bitWidth>1</bitWidth>
            </field>
            <field>
              <name>FB13</name>
              <bitOffset>13</bitOffset>
              <bitWidth>1</bitWidth>
            </field>
            <field>
              <name>FB14</name>
              <bitOffset>14</bitOffset>
              <bitWidth>1</bitWidth>
            </field>
            <field>
              <name>FB15</name>
              <bitOffset>15</bitOffset>
              <bitWidth>1</bitWidth>
            </field>
            <field>
              <name>FB16</name>
              <bitOffset>16</bitOffset>
              <bitWidth>1</bitWidth>
            </field>
            <field>
              <name>FB17</name>
              <bitOffset>17</bitOffset>
              <bitWidth>1</bitWidth>
            </field>
            <field>
              <name>FB18</name>
              <bitOffset>18</bitOffset>
              <bitWidth>1</bitWidth>
            </field>
            <field>
              <name>FB19</name>
              <bitOffset>19</bitOffset>
              <bitWidth>1</bitWidth>
            </field>
            <field>
              <name>FB20</name>
              <bitOffset>20</bitOffset>
              <bitWidth>1</bitWidth>
            </field>
            <field>
              <name>FB21</name>
              <bitOffset>21</bitOffset>
              <bitWidth>1</bitWidth>
            </field>
            <field>
              <name>FB22</name>
              <bitOffset>22</bitOffset>
              <bitWidth>1</bitWidth>
            </field>
            <field>
              <name>FB23</name>
              <bitOffset>23</bitOffset>
              <bitWidth>1</bitWidth>
            </field>
            <field>
              <name>FB24</name>
              <bitOffset>24</bitOffset>
              <bitWidth>1</bitWidth>
            </field>
            <field>
              <name>FB25</name>
              <bitOffset>25</bitOffset>
              <bitWidth>1</bitWidth>
            </field>
            <field>
              <name>FB26</name>
              <bitOffset>26</bitOffset>
              <bitWidth>1</bitWidth>
            </field>
            <field>
              <name>FB27</name>
              <bitOffset>27</bitOffset>
              <bitWidth>1</bitWidth>
            </field>
            <field>
              <name>FB28</name>
              <bitOffset>28</bitOffset>
              <bitWidth>1</bitWidth>
            </field>
            <field>
              <name>FB29</name>
              <bitOffset>29</bitOffset>
              <bitWidth>1</bitWidth>
            </field>
            <field>
              <name>FB30</name>
              <bitOffset>30</bitOffset>
              <bitWidth>1</bitWidth>
            </field>
            <field>
              <name>FB31</name>
              <bitOffset>31</bitOffset>
              <bitWidth>1</bitWidth>
            </field>
          </fields>
        </register>
        <register>
          <name>sFilterRegister.7.FR2</name>
          <addressOffset>0x27c</addressOffset>
          <size>0x20</size>
          <fields>
            <field>
              <name>FB0</name>
              <bitOffset>0</bitOffset>
              <bitWidth>1</bitWidth>
            </field>
            <field>
              <name>FB1</name>
              <bitOffset>1</bitOffset>
              <bitWidth>1</bitWidth>
            </field>
            <field>
              <name>FB2</name>
              <bitOffset>2</bitOffset>
              <bitWidth>1</bitWidth>
            </field>
            <field>
              <name>FB3</name>
              <bitOffset>3</bitOffset>
              <bitWidth>1</bitWidth>
            </field>
            <field>
              <name>FB4</name>
              <bitOffset>4</bitOffset>
              <bitWidth>1</bitWidth>
            </field>
            <field>
              <name>FB5</name>
              <bitOffset>5</bitOffset>
              <bitWidth>1</bitWidth>
            </field>
            <field>
              <name>FB6</name>
              <bitOffset>6</bitOffset>
              <bitWidth>1</bitWidth>
            </field>
            <field>
              <name>FB7</name>
              <bitOffset>7</bitOffset>
              <bitWidth>1</bitWidth>
            </field>
            <field>
              <name>FB8</name>
              <bitOffset>8</bitOffset>
              <bitWidth>1</bitWidth>
            </field>
            <field>
              <name>FB9</name>
              <bitOffset>9</bitOffset>
              <bitWidth>1</bitWidth>
            </field>
            <field>
              <name>FB10</name>
              <bitOffset>10</bitOffset>
              <bitWidth>1</bitWidth>
            </field>
            <field>
              <name>FB11</name>
              <bitOffset>11</bitOffset>
              <bitWidth>1</bitWidth>
            </field>
            <field>
              <name>FB12</name>
              <bitOffset>12</bitOffset>
              <bitWidth>1</bitWidth>
            </field>
            <field>
              <name>FB13</name>
              <bitOffset>13</bitOffset>
              <bitWidth>1</bitWidth>
            </field>
            <field>
              <name>FB14</name>
              <bitOffset>14</bitOffset>
              <bitWidth>1</bitWidth>
            </field>
            <field>
              <name>FB15</name>
              <bitOffset>15</bitOffset>
              <bitWidth>1</bitWidth>
            </field>
            <field>
              <name>FB16</name>
              <bitOffset>16</bitOffset>
              <bitWidth>1</bitWidth>
            </field>
            <field>
              <name>FB17</name>
              <bitOffset>17</bitOffset>
              <bitWidth>1</bitWidth>
            </field>
            <field>
              <name>FB18</name>
              <bitOffset>18</bitOffset>
              <bitWidth>1</bitWidth>
            </field>
            <field>
              <name>FB19</name>
              <bitOffset>19</bitOffset>
              <bitWidth>1</bitWidth>
            </field>
            <field>
              <name>FB20</name>
              <bitOffset>20</bitOffset>
              <bitWidth>1</bitWidth>
            </field>
            <field>
              <name>FB21</name>
              <bitOffset>21</bitOffset>
              <bitWidth>1</bitWidth>
            </field>
            <field>
              <name>FB22</name>
              <bitOffset>22</bitOffset>
              <bitWidth>1</bitWidth>
            </field>
            <field>
              <name>FB23</name>
              <bitOffset>23</bitOffset>
              <bitWidth>1</bitWidth>
            </field>
            <field>
              <name>FB24</name>
              <bitOffset>24</bitOffset>
              <bitWidth>1</bitWidth>
            </field>
            <field>
              <name>FB25</name>
              <bitOffset>25</bitOffset>
              <bitWidth>1</bitWidth>
            </field>
            <field>
              <name>FB26</name>
              <bitOffset>26</bitOffset>
              <bitWidth>1</bitWidth>
            </field>
            <field>
              <name>FB27</name>
              <bitOffset>27</bitOffset>
              <bitWidth>1</bitWidth>
            </field>
            <field>
              <name>FB28</name>
              <bitOffset>28</bitOffset>
              <bitWidth>1</bitWidth>
            </field>
            <field>
              <name>FB29</name>
              <bitOffset>29</bitOffset>
              <bitWidth>1</bitWidth>
            </field>
            <field>
              <name>FB30</name>
              <bitOffset>30</bitOffset>
              <bitWidth>1</bitWidth>
            </field>
            <field>
              <name>FB31</name>
              <bitOffset>31</bitOffset>
              <bitWidth>1</bitWidth>
            </field>
          </fields>
        </register>
        <register>
          <name>sFilterRegister.8.FR1</name>
          <addressOffset>0x280</addressOffset>
          <size>0x20</size>
          <fields>
            <field>
              <name>FB0</name>
              <bitOffset>0</bitOffset>
              <bitWidth>1</bitWidth>
            </field>
            <field>
              <name>FB1</name>
              <bitOffset>1</bitOffset>
              <bitWidth>1</bitWidth>
            </field>
            <field>
              <name>FB2</name>
              <bitOffset>2</bitOffset>
              <bitWidth>1</bitWidth>
            </field>
            <field>
              <name>FB3</name>
              <bitOffset>3</bitOffset>
              <bitWidth>1</bitWidth>
            </field>
            <field>
              <name>FB4</name>
              <bitOffset>4</bitOffset>
              <bitWidth>1</bitWidth>
            </field>
            <field>
              <name>FB5</name>
              <bitOffset>5</bitOffset>
              <bitWidth>1</bitWidth>
            </field>
            <field>
              <name>FB6</name>
              <bitOffset>6</bitOffset>
              <bitWidth>1</bitWidth>
            </field>
            <field>
              <name>FB7</name>
              <bitOffset>7</bitOffset>
              <bitWidth>1</bitWidth>
            </field>
            <field>
              <name>FB8</name>
              <bitOffset>8</bitOffset>
              <bitWidth>1</bitWidth>
            </field>
            <field>
              <name>FB9</name>
              <bitOffset>9</bitOffset>
              <bitWidth>1</bitWidth>
            </field>
            <field>
              <name>FB10</name>
              <bitOffset>10</bitOffset>
              <bitWidth>1</bitWidth>
            </field>
            <field>
              <name>FB11</name>
              <bitOffset>11</bitOffset>
              <bitWidth>1</bitWidth>
            </field>
            <field>
              <name>FB12</name>
              <bitOffset>12</bitOffset>
              <bitWidth>1</bitWidth>
            </field>
            <field>
              <name>FB13</name>
              <bitOffset>13</bitOffset>
              <bitWidth>1</bitWidth>
            </field>
            <field>
              <name>FB14</name>
              <bitOffset>14</bitOffset>
              <bitWidth>1</bitWidth>
            </field>
            <field>
              <name>FB15</name>
              <bitOffset>15</bitOffset>
              <bitWidth>1</bitWidth>
            </field>
            <field>
              <name>FB16</name>
              <bitOffset>16</bitOffset>
              <bitWidth>1</bitWidth>
            </field>
            <field>
              <name>FB17</name>
              <bitOffset>17</bitOffset>
              <bitWidth>1</bitWidth>
            </field>
            <field>
              <name>FB18</name>
              <bitOffset>18</bitOffset>
              <bitWidth>1</bitWidth>
            </field>
            <field>
              <name>FB19</name>
              <bitOffset>19</bitOffset>
              <bitWidth>1</bitWidth>
            </field>
            <field>
              <name>FB20</name>
              <bitOffset>20</bitOffset>
              <bitWidth>1</bitWidth>
            </field>
            <field>
              <name>FB21</name>
              <bitOffset>21</bitOffset>
              <bitWidth>1</bitWidth>
            </field>
            <field>
              <name>FB22</name>
              <bitOffset>22</bitOffset>
              <bitWidth>1</bitWidth>
            </field>
            <field>
              <name>FB23</name>
              <bitOffset>23</bitOffset>
              <bitWidth>1</bitWidth>
            </field>
            <field>
              <name>FB24</name>
              <bitOffset>24</bitOffset>
              <bitWidth>1</bitWidth>
            </field>
            <field>
              <name>FB25</name>
              <bitOffset>25</bitOffset>
              <bitWidth>1</bitWidth>
            </field>
            <field>
              <name>FB26</name>
              <bitOffset>26</bitOffset>
              <bitWidth>1</bitWidth>
            </field>
            <field>
              <name>FB27</name>
              <bitOffset>27</bitOffset>
              <bitWidth>1</bitWidth>
            </field>
            <field>
              <name>FB28</name>
              <bitOffset>28</bitOffset>
              <bitWidth>1</bitWidth>
            </field>
            <field>
              <name>FB29</name>
              <bitOffset>29</bitOffset>
              <bitWidth>1</bitWidth>
            </field>
            <field>
              <name>FB30</name>
              <bitOffset>30</bitOffset>
              <bitWidth>1</bitWidth>
            </field>
            <field>
              <name>FB31</name>
              <bitOffset>31</bitOffset>
              <bitWidth>1</bitWidth>
            </field>
          </fields>
        </register>
        <register>
          <name>sFilterRegister.8.FR2</name>
          <addressOffset>0x284</addressOffset>
          <size>0x20</size>
          <fields>
            <field>
              <name>FB0</name>
              <bitOffset>0</bitOffset>
              <bitWidth>1</bitWidth>
            </field>
            <field>
              <name>FB1</name>
              <bitOffset>1</bitOffset>
              <bitWidth>1</bitWidth>
            </field>
            <field>
              <name>FB2</name>
              <bitOffset>2</bitOffset>
              <bitWidth>1</bitWidth>
            </field>
            <field>
              <name>FB3</name>
              <bitOffset>3</bitOffset>
              <bitWidth>1</bitWidth>
            </field>
            <field>
              <name>FB4</name>
              <bitOffset>4</bitOffset>
              <bitWidth>1</bitWidth>
            </field>
            <field>
              <name>FB5</name>
              <bitOffset>5</bitOffset>
              <bitWidth>1</bitWidth>
            </field>
            <field>
              <name>FB6</name>
              <bitOffset>6</bitOffset>
              <bitWidth>1</bitWidth>
            </field>
            <field>
              <name>FB7</name>
              <bitOffset>7</bitOffset>
              <bitWidth>1</bitWidth>
            </field>
            <field>
              <name>FB8</name>
              <bitOffset>8</bitOffset>
              <bitWidth>1</bitWidth>
            </field>
            <field>
              <name>FB9</name>
              <bitOffset>9</bitOffset>
              <bitWidth>1</bitWidth>
            </field>
            <field>
              <name>FB10</name>
              <bitOffset>10</bitOffset>
              <bitWidth>1</bitWidth>
            </field>
            <field>
              <name>FB11</name>
              <bitOffset>11</bitOffset>
              <bitWidth>1</bitWidth>
            </field>
            <field>
              <name>FB12</name>
              <bitOffset>12</bitOffset>
              <bitWidth>1</bitWidth>
            </field>
            <field>
              <name>FB13</name>
              <bitOffset>13</bitOffset>
              <bitWidth>1</bitWidth>
            </field>
            <field>
              <name>FB14</name>
              <bitOffset>14</bitOffset>
              <bitWidth>1</bitWidth>
            </field>
            <field>
              <name>FB15</name>
              <bitOffset>15</bitOffset>
              <bitWidth>1</bitWidth>
            </field>
            <field>
              <name>FB16</name>
              <bitOffset>16</bitOffset>
              <bitWidth>1</bitWidth>
            </field>
            <field>
              <name>FB17</name>
              <bitOffset>17</bitOffset>
              <bitWidth>1</bitWidth>
            </field>
            <field>
              <name>FB18</name>
              <bitOffset>18</bitOffset>
              <bitWidth>1</bitWidth>
            </field>
            <field>
              <name>FB19</name>
              <bitOffset>19</bitOffset>
              <bitWidth>1</bitWidth>
            </field>
            <field>
              <name>FB20</name>
              <bitOffset>20</bitOffset>
              <bitWidth>1</bitWidth>
            </field>
            <field>
              <name>FB21</name>
              <bitOffset>21</bitOffset>
              <bitWidth>1</bitWidth>
            </field>
            <field>
              <name>FB22</name>
              <bitOffset>22</bitOffset>
              <bitWidth>1</bitWidth>
            </field>
            <field>
              <name>FB23</name>
              <bitOffset>23</bitOffset>
              <bitWidth>1</bitWidth>
            </field>
            <field>
              <name>FB24</name>
              <bitOffset>24</bitOffset>
              <bitWidth>1</bitWidth>
            </field>
            <field>
              <name>FB25</name>
              <bitOffset>25</bitOffset>
              <bitWidth>1</bitWidth>
            </field>
            <field>
              <name>FB26</name>
              <bitOffset>26</bitOffset>
              <bitWidth>1</bitWidth>
            </field>
            <field>
              <name>FB27</name>
              <bitOffset>27</bitOffset>
              <bitWidth>1</bitWidth>
            </field>
            <field>
              <name>FB28</name>
              <bitOffset>28</bitOffset>
              <bitWidth>1</bitWidth>
            </field>
            <field>
              <name>FB29</name>
              <bitOffset>29</bitOffset>
              <bitWidth>1</bitWidth>
            </field>
            <field>
              <name>FB30</name>
              <bitOffset>30</bitOffset>
              <bitWidth>1</bitWidth>
            </field>
            <field>
              <name>FB31</name>
              <bitOffset>31</bitOffset>
              <bitWidth>1</bitWidth>
            </field>
          </fields>
        </register>
        <register>
          <name>sFilterRegister.9.FR1</name>
          <addressOffset>0x288</addressOffset>
          <size>0x20</size>
          <fields>
            <field>
              <name>FB0</name>
              <bitOffset>0</bitOffset>
              <bitWidth>1</bitWidth>
            </field>
            <field>
              <name>FB1</name>
              <bitOffset>1</bitOffset>
              <bitWidth>1</bitWidth>
            </field>
            <field>
              <name>FB2</name>
              <bitOffset>2</bitOffset>
              <bitWidth>1</bitWidth>
            </field>
            <field>
              <name>FB3</name>
              <bitOffset>3</bitOffset>
              <bitWidth>1</bitWidth>
            </field>
            <field>
              <name>FB4</name>
              <bitOffset>4</bitOffset>
              <bitWidth>1</bitWidth>
            </field>
            <field>
              <name>FB5</name>
              <bitOffset>5</bitOffset>
              <bitWidth>1</bitWidth>
            </field>
            <field>
              <name>FB6</name>
              <bitOffset>6</bitOffset>
              <bitWidth>1</bitWidth>
            </field>
            <field>
              <name>FB7</name>
              <bitOffset>7</bitOffset>
              <bitWidth>1</bitWidth>
            </field>
            <field>
              <name>FB8</name>
              <bitOffset>8</bitOffset>
              <bitWidth>1</bitWidth>
            </field>
            <field>
              <name>FB9</name>
              <bitOffset>9</bitOffset>
              <bitWidth>1</bitWidth>
            </field>
            <field>
              <name>FB10</name>
              <bitOffset>10</bitOffset>
              <bitWidth>1</bitWidth>
            </field>
            <field>
              <name>FB11</name>
              <bitOffset>11</bitOffset>
              <bitWidth>1</bitWidth>
            </field>
            <field>
              <name>FB12</name>
              <bitOffset>12</bitOffset>
              <bitWidth>1</bitWidth>
            </field>
            <field>
              <name>FB13</name>
              <bitOffset>13</bitOffset>
              <bitWidth>1</bitWidth>
            </field>
            <field>
              <name>FB14</name>
              <bitOffset>14</bitOffset>
              <bitWidth>1</bitWidth>
            </field>
            <field>
              <name>FB15</name>
              <bitOffset>15</bitOffset>
              <bitWidth>1</bitWidth>
            </field>
            <field>
              <name>FB16</name>
              <bitOffset>16</bitOffset>
              <bitWidth>1</bitWidth>
            </field>
            <field>
              <name>FB17</name>
              <bitOffset>17</bitOffset>
              <bitWidth>1</bitWidth>
            </field>
            <field>
              <name>FB18</name>
              <bitOffset>18</bitOffset>
              <bitWidth>1</bitWidth>
            </field>
            <field>
              <name>FB19</name>
              <bitOffset>19</bitOffset>
              <bitWidth>1</bitWidth>
            </field>
            <field>
              <name>FB20</name>
              <bitOffset>20</bitOffset>
              <bitWidth>1</bitWidth>
            </field>
            <field>
              <name>FB21</name>
              <bitOffset>21</bitOffset>
              <bitWidth>1</bitWidth>
            </field>
            <field>
              <name>FB22</name>
              <bitOffset>22</bitOffset>
              <bitWidth>1</bitWidth>
            </field>
            <field>
              <name>FB23</name>
              <bitOffset>23</bitOffset>
              <bitWidth>1</bitWidth>
            </field>
            <field>
              <name>FB24</name>
              <bitOffset>24</bitOffset>
              <bitWidth>1</bitWidth>
            </field>
            <field>
              <name>FB25</name>
              <bitOffset>25</bitOffset>
              <bitWidth>1</bitWidth>
            </field>
            <field>
              <name>FB26</name>
              <bitOffset>26</bitOffset>
              <bitWidth>1</bitWidth>
            </field>
            <field>
              <name>FB27</name>
              <bitOffset>27</bitOffset>
              <bitWidth>1</bitWidth>
            </field>
            <field>
              <name>FB28</name>
              <bitOffset>28</bitOffset>
              <bitWidth>1</bitWidth>
            </field>
            <field>
              <name>FB29</name>
              <bitOffset>29</bitOffset>
              <bitWidth>1</bitWidth>
            </field>
            <field>
              <name>FB30</name>
              <bitOffset>30</bitOffset>
              <bitWidth>1</bitWidth>
            </field>
            <field>
              <name>FB31</name>
              <bitOffset>31</bitOffset>
              <bitWidth>1</bitWidth>
            </field>
          </fields>
        </register>
        <register>
          <name>sFilterRegister.9.FR2</name>
          <addressOffset>0x28c</addressOffset>
          <size>0x20</size>
          <fields>
            <field>
              <name>FB0</name>
              <bitOffset>0</bitOffset>
              <bitWidth>1</bitWidth>
            </field>
            <field>
              <name>FB1</name>
              <bitOffset>1</bitOffset>
              <bitWidth>1</bitWidth>
            </field>
            <field>
              <name>FB2</name>
              <bitOffset>2</bitOffset>
              <bitWidth>1</bitWidth>
            </field>
            <field>
              <name>FB3</name>
              <bitOffset>3</bitOffset>
              <bitWidth>1</bitWidth>
            </field>
            <field>
              <name>FB4</name>
              <bitOffset>4</bitOffset>
              <bitWidth>1</bitWidth>
            </field>
            <field>
              <name>FB5</name>
              <bitOffset>5</bitOffset>
              <bitWidth>1</bitWidth>
            </field>
            <field>
              <name>FB6</name>
              <bitOffset>6</bitOffset>
              <bitWidth>1</bitWidth>
            </field>
            <field>
              <name>FB7</name>
              <bitOffset>7</bitOffset>
              <bitWidth>1</bitWidth>
            </field>
            <field>
              <name>FB8</name>
              <bitOffset>8</bitOffset>
              <bitWidth>1</bitWidth>
            </field>
            <field>
              <name>FB9</name>
              <bitOffset>9</bitOffset>
              <bitWidth>1</bitWidth>
            </field>
            <field>
              <name>FB10</name>
              <bitOffset>10</bitOffset>
              <bitWidth>1</bitWidth>
            </field>
            <field>
              <name>FB11</name>
              <bitOffset>11</bitOffset>
              <bitWidth>1</bitWidth>
            </field>
            <field>
              <name>FB12</name>
              <bitOffset>12</bitOffset>
              <bitWidth>1</bitWidth>
            </field>
            <field>
              <name>FB13</name>
              <bitOffset>13</bitOffset>
              <bitWidth>1</bitWidth>
            </field>
            <field>
              <name>FB14</name>
              <bitOffset>14</bitOffset>
              <bitWidth>1</bitWidth>
            </field>
            <field>
              <name>FB15</name>
              <bitOffset>15</bitOffset>
              <bitWidth>1</bitWidth>
            </field>
            <field>
              <name>FB16</name>
              <bitOffset>16</bitOffset>
              <bitWidth>1</bitWidth>
            </field>
            <field>
              <name>FB17</name>
              <bitOffset>17</bitOffset>
              <bitWidth>1</bitWidth>
            </field>
            <field>
              <name>FB18</name>
              <bitOffset>18</bitOffset>
              <bitWidth>1</bitWidth>
            </field>
            <field>
              <name>FB19</name>
              <bitOffset>19</bitOffset>
              <bitWidth>1</bitWidth>
            </field>
            <field>
              <name>FB20</name>
              <bitOffset>20</bitOffset>
              <bitWidth>1</bitWidth>
            </field>
            <field>
              <name>FB21</name>
              <bitOffset>21</bitOffset>
              <bitWidth>1</bitWidth>
            </field>
            <field>
              <name>FB22</name>
              <bitOffset>22</bitOffset>
              <bitWidth>1</bitWidth>
            </field>
            <field>
              <name>FB23</name>
              <bitOffset>23</bitOffset>
              <bitWidth>1</bitWidth>
            </field>
            <field>
              <name>FB24</name>
              <bitOffset>24</bitOffset>
              <bitWidth>1</bitWidth>
            </field>
            <field>
              <name>FB25</name>
              <bitOffset>25</bitOffset>
              <bitWidth>1</bitWidth>
            </field>
            <field>
              <name>FB26</name>
              <bitOffset>26</bitOffset>
              <bitWidth>1</bitWidth>
            </field>
            <field>
              <name>FB27</name>
              <bitOffset>27</bitOffset>
              <bitWidth>1</bitWidth>
            </field>
            <field>
              <name>FB28</name>
              <bitOffset>28</bitOffset>
              <bitWidth>1</bitWidth>
            </field>
            <field>
              <name>FB29</name>
              <bitOffset>29</bitOffset>
              <bitWidth>1</bitWidth>
            </field>
            <field>
              <name>FB30</name>
              <bitOffset>30</bitOffset>
              <bitWidth>1</bitWidth>
            </field>
            <field>
              <name>FB31</name>
              <bitOffset>31</bitOffset>
              <bitWidth>1</bitWidth>
            </field>
          </fields>
        </register>
        <register>
          <name>sFilterRegister.10.FR1</name>
          <addressOffset>0x290</addressOffset>
          <size>0x20</size>
          <fields>
            <field>
              <name>FB0</name>
              <bitOffset>0</bitOffset>
              <bitWidth>1</bitWidth>
            </field>
            <field>
              <name>FB1</name>
              <bitOffset>1</bitOffset>
              <bitWidth>1</bitWidth>
            </field>
            <field>
              <name>FB2</name>
              <bitOffset>2</bitOffset>
              <bitWidth>1</bitWidth>
            </field>
            <field>
              <name>FB3</name>
              <bitOffset>3</bitOffset>
              <bitWidth>1</bitWidth>
            </field>
            <field>
              <name>FB4</name>
              <bitOffset>4</bitOffset>
              <bitWidth>1</bitWidth>
            </field>
            <field>
              <name>FB5</name>
              <bitOffset>5</bitOffset>
              <bitWidth>1</bitWidth>
            </field>
            <field>
              <name>FB6</name>
              <bitOffset>6</bitOffset>
              <bitWidth>1</bitWidth>
            </field>
            <field>
              <name>FB7</name>
              <bitOffset>7</bitOffset>
              <bitWidth>1</bitWidth>
            </field>
            <field>
              <name>FB8</name>
              <bitOffset>8</bitOffset>
              <bitWidth>1</bitWidth>
            </field>
            <field>
              <name>FB9</name>
              <bitOffset>9</bitOffset>
              <bitWidth>1</bitWidth>
            </field>
            <field>
              <name>FB10</name>
              <bitOffset>10</bitOffset>
              <bitWidth>1</bitWidth>
            </field>
            <field>
              <name>FB11</name>
              <bitOffset>11</bitOffset>
              <bitWidth>1</bitWidth>
            </field>
            <field>
              <name>FB12</name>
              <bitOffset>12</bitOffset>
              <bitWidth>1</bitWidth>
            </field>
            <field>
              <name>FB13</name>
              <bitOffset>13</bitOffset>
              <bitWidth>1</bitWidth>
            </field>
            <field>
              <name>FB14</name>
              <bitOffset>14</bitOffset>
              <bitWidth>1</bitWidth>
            </field>
            <field>
              <name>FB15</name>
              <bitOffset>15</bitOffset>
              <bitWidth>1</bitWidth>
            </field>
            <field>
              <name>FB16</name>
              <bitOffset>16</bitOffset>
              <bitWidth>1</bitWidth>
            </field>
            <field>
              <name>FB17</name>
              <bitOffset>17</bitOffset>
              <bitWidth>1</bitWidth>
            </field>
            <field>
              <name>FB18</name>
              <bitOffset>18</bitOffset>
              <bitWidth>1</bitWidth>
            </field>
            <field>
              <name>FB19</name>
              <bitOffset>19</bitOffset>
              <bitWidth>1</bitWidth>
            </field>
            <field>
              <name>FB20</name>
              <bitOffset>20</bitOffset>
              <bitWidth>1</bitWidth>
            </field>
            <field>
              <name>FB21</name>
              <bitOffset>21</bitOffset>
              <bitWidth>1</bitWidth>
            </field>
            <field>
              <name>FB22</name>
              <bitOffset>22</bitOffset>
              <bitWidth>1</bitWidth>
            </field>
            <field>
              <name>FB23</name>
              <bitOffset>23</bitOffset>
              <bitWidth>1</bitWidth>
            </field>
            <field>
              <name>FB24</name>
              <bitOffset>24</bitOffset>
              <bitWidth>1</bitWidth>
            </field>
            <field>
              <name>FB25</name>
              <bitOffset>25</bitOffset>
              <bitWidth>1</bitWidth>
            </field>
            <field>
              <name>FB26</name>
              <bitOffset>26</bitOffset>
              <bitWidth>1</bitWidth>
            </field>
            <field>
              <name>FB27</name>
              <bitOffset>27</bitOffset>
              <bitWidth>1</bitWidth>
            </field>
            <field>
              <name>FB28</name>
              <bitOffset>28</bitOffset>
              <bitWidth>1</bitWidth>
            </field>
            <field>
              <name>FB29</name>
              <bitOffset>29</bitOffset>
              <bitWidth>1</bitWidth>
            </field>
            <field>
              <name>FB30</name>
              <bitOffset>30</bitOffset>
              <bitWidth>1</bitWidth>
            </field>
            <field>
              <name>FB31</name>
              <bitOffset>31</bitOffset>
              <bitWidth>1</bitWidth>
            </field>
          </fields>
        </register>
        <register>
          <name>sFilterRegister.10.FR2</name>
          <addressOffset>0x294</addressOffset>
          <size>0x20</size>
          <fields>
            <field>
              <name>FB0</name>
              <bitOffset>0</bitOffset>
              <bitWidth>1</bitWidth>
            </field>
            <field>
              <name>FB1</name>
              <bitOffset>1</bitOffset>
              <bitWidth>1</bitWidth>
            </field>
            <field>
              <name>FB2</name>
              <bitOffset>2</bitOffset>
              <bitWidth>1</bitWidth>
            </field>
            <field>
              <name>FB3</name>
              <bitOffset>3</bitOffset>
              <bitWidth>1</bitWidth>
            </field>
            <field>
              <name>FB4</name>
              <bitOffset>4</bitOffset>
              <bitWidth>1</bitWidth>
            </field>
            <field>
              <name>FB5</name>
              <bitOffset>5</bitOffset>
              <bitWidth>1</bitWidth>
            </field>
            <field>
              <name>FB6</name>
              <bitOffset>6</bitOffset>
              <bitWidth>1</bitWidth>
            </field>
            <field>
              <name>FB7</name>
              <bitOffset>7</bitOffset>
              <bitWidth>1</bitWidth>
            </field>
            <field>
              <name>FB8</name>
              <bitOffset>8</bitOffset>
              <bitWidth>1</bitWidth>
            </field>
            <field>
              <name>FB9</name>
              <bitOffset>9</bitOffset>
              <bitWidth>1</bitWidth>
            </field>
            <field>
              <name>FB10</name>
              <bitOffset>10</bitOffset>
              <bitWidth>1</bitWidth>
            </field>
            <field>
              <name>FB11</name>
              <bitOffset>11</bitOffset>
              <bitWidth>1</bitWidth>
            </field>
            <field>
              <name>FB12</name>
              <bitOffset>12</bitOffset>
              <bitWidth>1</bitWidth>
            </field>
            <field>
              <name>FB13</name>
              <bitOffset>13</bitOffset>
              <bitWidth>1</bitWidth>
            </field>
            <field>
              <name>FB14</name>
              <bitOffset>14</bitOffset>
              <bitWidth>1</bitWidth>
            </field>
            <field>
              <name>FB15</name>
              <bitOffset>15</bitOffset>
              <bitWidth>1</bitWidth>
            </field>
            <field>
              <name>FB16</name>
              <bitOffset>16</bitOffset>
              <bitWidth>1</bitWidth>
            </field>
            <field>
              <name>FB17</name>
              <bitOffset>17</bitOffset>
              <bitWidth>1</bitWidth>
            </field>
            <field>
              <name>FB18</name>
              <bitOffset>18</bitOffset>
              <bitWidth>1</bitWidth>
            </field>
            <field>
              <name>FB19</name>
              <bitOffset>19</bitOffset>
              <bitWidth>1</bitWidth>
            </field>
            <field>
              <name>FB20</name>
              <bitOffset>20</bitOffset>
              <bitWidth>1</bitWidth>
            </field>
            <field>
              <name>FB21</name>
              <bitOffset>21</bitOffset>
              <bitWidth>1</bitWidth>
            </field>
            <field>
              <name>FB22</name>
              <bitOffset>22</bitOffset>
              <bitWidth>1</bitWidth>
            </field>
            <field>
              <name>FB23</name>
              <bitOffset>23</bitOffset>
              <bitWidth>1</bitWidth>
            </field>
            <field>
              <name>FB24</name>
              <bitOffset>24</bitOffset>
              <bitWidth>1</bitWidth>
            </field>
            <field>
              <name>FB25</name>
              <bitOffset>25</bitOffset>
              <bitWidth>1</bitWidth>
            </field>
            <field>
              <name>FB26</name>
              <bitOffset>26</bitOffset>
              <bitWidth>1</bitWidth>
            </field>
            <field>
              <name>FB27</name>
              <bitOffset>27</bitOffset>
              <bitWidth>1</bitWidth>
            </field>
            <field>
              <name>FB28</name>
              <bitOffset>28</bitOffset>
              <bitWidth>1</bitWidth>
            </field>
            <field>
              <name>FB29</name>
              <bitOffset>29</bitOffset>
              <bitWidth>1</bitWidth>
            </field>
            <field>
              <name>FB30</name>
              <bitOffset>30</bitOffset>
              <bitWidth>1</bitWidth>
            </field>
            <field>
              <name>FB31</name>
              <bitOffset>31</bitOffset>
              <bitWidth>1</bitWidth>
            </field>
          </fields>
        </register>
        <register>
          <name>sFilterRegister.11.FR1</name>
          <addressOffset>0x298</addressOffset>
          <size>0x20</size>
          <fields>
            <field>
              <name>FB0</name>
              <bitOffset>0</bitOffset>
              <bitWidth>1</bitWidth>
            </field>
            <field>
              <name>FB1</name>
              <bitOffset>1</bitOffset>
              <bitWidth>1</bitWidth>
            </field>
            <field>
              <name>FB2</name>
              <bitOffset>2</bitOffset>
              <bitWidth>1</bitWidth>
            </field>
            <field>
              <name>FB3</name>
              <bitOffset>3</bitOffset>
              <bitWidth>1</bitWidth>
            </field>
            <field>
              <name>FB4</name>
              <bitOffset>4</bitOffset>
              <bitWidth>1</bitWidth>
            </field>
            <field>
              <name>FB5</name>
              <bitOffset>5</bitOffset>
              <bitWidth>1</bitWidth>
            </field>
            <field>
              <name>FB6</name>
              <bitOffset>6</bitOffset>
              <bitWidth>1</bitWidth>
            </field>
            <field>
              <name>FB7</name>
              <bitOffset>7</bitOffset>
              <bitWidth>1</bitWidth>
            </field>
            <field>
              <name>FB8</name>
              <bitOffset>8</bitOffset>
              <bitWidth>1</bitWidth>
            </field>
            <field>
              <name>FB9</name>
              <bitOffset>9</bitOffset>
              <bitWidth>1</bitWidth>
            </field>
            <field>
              <name>FB10</name>
              <bitOffset>10</bitOffset>
              <bitWidth>1</bitWidth>
            </field>
            <field>
              <name>FB11</name>
              <bitOffset>11</bitOffset>
              <bitWidth>1</bitWidth>
            </field>
            <field>
              <name>FB12</name>
              <bitOffset>12</bitOffset>
              <bitWidth>1</bitWidth>
            </field>
            <field>
              <name>FB13</name>
              <bitOffset>13</bitOffset>
              <bitWidth>1</bitWidth>
            </field>
            <field>
              <name>FB14</name>
              <bitOffset>14</bitOffset>
              <bitWidth>1</bitWidth>
            </field>
            <field>
              <name>FB15</name>
              <bitOffset>15</bitOffset>
              <bitWidth>1</bitWidth>
            </field>
            <field>
              <name>FB16</name>
              <bitOffset>16</bitOffset>
              <bitWidth>1</bitWidth>
            </field>
            <field>
              <name>FB17</name>
              <bitOffset>17</bitOffset>
              <bitWidth>1</bitWidth>
            </field>
            <field>
              <name>FB18</name>
              <bitOffset>18</bitOffset>
              <bitWidth>1</bitWidth>
            </field>
            <field>
              <name>FB19</name>
              <bitOffset>19</bitOffset>
              <bitWidth>1</bitWidth>
            </field>
            <field>
              <name>FB20</name>
              <bitOffset>20</bitOffset>
              <bitWidth>1</bitWidth>
            </field>
            <field>
              <name>FB21</name>
              <bitOffset>21</bitOffset>
              <bitWidth>1</bitWidth>
            </field>
            <field>
              <name>FB22</name>
              <bitOffset>22</bitOffset>
              <bitWidth>1</bitWidth>
            </field>
            <field>
              <name>FB23</name>
              <bitOffset>23</bitOffset>
              <bitWidth>1</bitWidth>
            </field>
            <field>
              <name>FB24</name>
              <bitOffset>24</bitOffset>
              <bitWidth>1</bitWidth>
            </field>
            <field>
              <name>FB25</name>
              <bitOffset>25</bitOffset>
              <bitWidth>1</bitWidth>
            </field>
            <field>
              <name>FB26</name>
              <bitOffset>26</bitOffset>
              <bitWidth>1</bitWidth>
            </field>
            <field>
              <name>FB27</name>
              <bitOffset>27</bitOffset>
              <bitWidth>1</bitWidth>
            </field>
            <field>
              <name>FB28</name>
              <bitOffset>28</bitOffset>
              <bitWidth>1</bitWidth>
            </field>
            <field>
              <name>FB29</name>
              <bitOffset>29</bitOffset>
              <bitWidth>1</bitWidth>
            </field>
            <field>
              <name>FB30</name>
              <bitOffset>30</bitOffset>
              <bitWidth>1</bitWidth>
            </field>
            <field>
              <name>FB31</name>
              <bitOffset>31</bitOffset>
              <bitWidth>1</bitWidth>
            </field>
          </fields>
        </register>
        <register>
          <name>sFilterRegister.11.FR2</name>
          <addressOffset>0x29c</addressOffset>
          <size>0x20</size>
          <fields>
            <field>
              <name>FB0</name>
              <bitOffset>0</bitOffset>
              <bitWidth>1</bitWidth>
            </field>
            <field>
              <name>FB1</name>
              <bitOffset>1</bitOffset>
              <bitWidth>1</bitWidth>
            </field>
            <field>
              <name>FB2</name>
              <bitOffset>2</bitOffset>
              <bitWidth>1</bitWidth>
            </field>
            <field>
              <name>FB3</name>
              <bitOffset>3</bitOffset>
              <bitWidth>1</bitWidth>
            </field>
            <field>
              <name>FB4</name>
              <bitOffset>4</bitOffset>
              <bitWidth>1</bitWidth>
            </field>
            <field>
              <name>FB5</name>
              <bitOffset>5</bitOffset>
              <bitWidth>1</bitWidth>
            </field>
            <field>
              <name>FB6</name>
              <bitOffset>6</bitOffset>
              <bitWidth>1</bitWidth>
            </field>
            <field>
              <name>FB7</name>
              <bitOffset>7</bitOffset>
              <bitWidth>1</bitWidth>
            </field>
            <field>
              <name>FB8</name>
              <bitOffset>8</bitOffset>
              <bitWidth>1</bitWidth>
            </field>
            <field>
              <name>FB9</name>
              <bitOffset>9</bitOffset>
              <bitWidth>1</bitWidth>
            </field>
            <field>
              <name>FB10</name>
              <bitOffset>10</bitOffset>
              <bitWidth>1</bitWidth>
            </field>
            <field>
              <name>FB11</name>
              <bitOffset>11</bitOffset>
              <bitWidth>1</bitWidth>
            </field>
            <field>
              <name>FB12</name>
              <bitOffset>12</bitOffset>
              <bitWidth>1</bitWidth>
            </field>
            <field>
              <name>FB13</name>
              <bitOffset>13</bitOffset>
              <bitWidth>1</bitWidth>
            </field>
            <field>
              <name>FB14</name>
              <bitOffset>14</bitOffset>
              <bitWidth>1</bitWidth>
            </field>
            <field>
              <name>FB15</name>
              <bitOffset>15</bitOffset>
              <bitWidth>1</bitWidth>
            </field>
            <field>
              <name>FB16</name>
              <bitOffset>16</bitOffset>
              <bitWidth>1</bitWidth>
            </field>
            <field>
              <name>FB17</name>
              <bitOffset>17</bitOffset>
              <bitWidth>1</bitWidth>
            </field>
            <field>
              <name>FB18</name>
              <bitOffset>18</bitOffset>
              <bitWidth>1</bitWidth>
            </field>
            <field>
              <name>FB19</name>
              <bitOffset>19</bitOffset>
              <bitWidth>1</bitWidth>
            </field>
            <field>
              <name>FB20</name>
              <bitOffset>20</bitOffset>
              <bitWidth>1</bitWidth>
            </field>
            <field>
              <name>FB21</name>
              <bitOffset>21</bitOffset>
              <bitWidth>1</bitWidth>
            </field>
            <field>
              <name>FB22</name>
              <bitOffset>22</bitOffset>
              <bitWidth>1</bitWidth>
            </field>
            <field>
              <name>FB23</name>
              <bitOffset>23</bitOffset>
              <bitWidth>1</bitWidth>
            </field>
            <field>
              <name>FB24</name>
              <bitOffset>24</bitOffset>
              <bitWidth>1</bitWidth>
            </field>
            <field>
              <name>FB25</name>
              <bitOffset>25</bitOffset>
              <bitWidth>1</bitWidth>
            </field>
            <field>
              <name>FB26</name>
              <bitOffset>26</bitOffset>
              <bitWidth>1</bitWidth>
            </field>
            <field>
              <name>FB27</name>
              <bitOffset>27</bitOffset>
              <bitWidth>1</bitWidth>
            </field>
            <field>
              <name>FB28</name>
              <bitOffset>28</bitOffset>
              <bitWidth>1</bitWidth>
            </field>
            <field>
              <name>FB29</name>
              <bitOffset>29</bitOffset>
              <bitWidth>1</bitWidth>
            </field>
            <field>
              <name>FB30</name>
              <bitOffset>30</bitOffset>
              <bitWidth>1</bitWidth>
            </field>
            <field>
              <name>FB31</name>
              <bitOffset>31</bitOffset>
              <bitWidth>1</bitWidth>
            </field>
          </fields>
        </register>
        <register>
          <name>sFilterRegister.12.FR1</name>
          <addressOffset>0x2a0</addressOffset>
          <size>0x20</size>
          <fields>
            <field>
              <name>FB0</name>
              <bitOffset>0</bitOffset>
              <bitWidth>1</bitWidth>
            </field>
            <field>
              <name>FB1</name>
              <bitOffset>1</bitOffset>
              <bitWidth>1</bitWidth>
            </field>
            <field>
              <name>FB2</name>
              <bitOffset>2</bitOffset>
              <bitWidth>1</bitWidth>
            </field>
            <field>
              <name>FB3</name>
              <bitOffset>3</bitOffset>
              <bitWidth>1</bitWidth>
            </field>
            <field>
              <name>FB4</name>
              <bitOffset>4</bitOffset>
              <bitWidth>1</bitWidth>
            </field>
            <field>
              <name>FB5</name>
              <bitOffset>5</bitOffset>
              <bitWidth>1</bitWidth>
            </field>
            <field>
              <name>FB6</name>
              <bitOffset>6</bitOffset>
              <bitWidth>1</bitWidth>
            </field>
            <field>
              <name>FB7</name>
              <bitOffset>7</bitOffset>
              <bitWidth>1</bitWidth>
            </field>
            <field>
              <name>FB8</name>
              <bitOffset>8</bitOffset>
              <bitWidth>1</bitWidth>
            </field>
            <field>
              <name>FB9</name>
              <bitOffset>9</bitOffset>
              <bitWidth>1</bitWidth>
            </field>
            <field>
              <name>FB10</name>
              <bitOffset>10</bitOffset>
              <bitWidth>1</bitWidth>
            </field>
            <field>
              <name>FB11</name>
              <bitOffset>11</bitOffset>
              <bitWidth>1</bitWidth>
            </field>
            <field>
              <name>FB12</name>
              <bitOffset>12</bitOffset>
              <bitWidth>1</bitWidth>
            </field>
            <field>
              <name>FB13</name>
              <bitOffset>13</bitOffset>
              <bitWidth>1</bitWidth>
            </field>
            <field>
              <name>FB14</name>
              <bitOffset>14</bitOffset>
              <bitWidth>1</bitWidth>
            </field>
            <field>
              <name>FB15</name>
              <bitOffset>15</bitOffset>
              <bitWidth>1</bitWidth>
            </field>
            <field>
              <name>FB16</name>
              <bitOffset>16</bitOffset>
              <bitWidth>1</bitWidth>
            </field>
            <field>
              <name>FB17</name>
              <bitOffset>17</bitOffset>
              <bitWidth>1</bitWidth>
            </field>
            <field>
              <name>FB18</name>
              <bitOffset>18</bitOffset>
              <bitWidth>1</bitWidth>
            </field>
            <field>
              <name>FB19</name>
              <bitOffset>19</bitOffset>
              <bitWidth>1</bitWidth>
            </field>
            <field>
              <name>FB20</name>
              <bitOffset>20</bitOffset>
              <bitWidth>1</bitWidth>
            </field>
            <field>
              <name>FB21</name>
              <bitOffset>21</bitOffset>
              <bitWidth>1</bitWidth>
            </field>
            <field>
              <name>FB22</name>
              <bitOffset>22</bitOffset>
              <bitWidth>1</bitWidth>
            </field>
            <field>
              <name>FB23</name>
              <bitOffset>23</bitOffset>
              <bitWidth>1</bitWidth>
            </field>
            <field>
              <name>FB24</name>
              <bitOffset>24</bitOffset>
              <bitWidth>1</bitWidth>
            </field>
            <field>
              <name>FB25</name>
              <bitOffset>25</bitOffset>
              <bitWidth>1</bitWidth>
            </field>
            <field>
              <name>FB26</name>
              <bitOffset>26</bitOffset>
              <bitWidth>1</bitWidth>
            </field>
            <field>
              <name>FB27</name>
              <bitOffset>27</bitOffset>
              <bitWidth>1</bitWidth>
            </field>
            <field>
              <name>FB28</name>
              <bitOffset>28</bitOffset>
              <bitWidth>1</bitWidth>
            </field>
            <field>
              <name>FB29</name>
              <bitOffset>29</bitOffset>
              <bitWidth>1</bitWidth>
            </field>
            <field>
              <name>FB30</name>
              <bitOffset>30</bitOffset>
              <bitWidth>1</bitWidth>
            </field>
            <field>
              <name>FB31</name>
              <bitOffset>31</bitOffset>
              <bitWidth>1</bitWidth>
            </field>
          </fields>
        </register>
        <register>
          <name>sFilterRegister.12.FR2</name>
          <addressOffset>0x2a4</addressOffset>
          <size>0x20</size>
          <fields>
            <field>
              <name>FB0</name>
              <bitOffset>0</bitOffset>
              <bitWidth>1</bitWidth>
            </field>
            <field>
              <name>FB1</name>
              <bitOffset>1</bitOffset>
              <bitWidth>1</bitWidth>
            </field>
            <field>
              <name>FB2</name>
              <bitOffset>2</bitOffset>
              <bitWidth>1</bitWidth>
            </field>
            <field>
              <name>FB3</name>
              <bitOffset>3</bitOffset>
              <bitWidth>1</bitWidth>
            </field>
            <field>
              <name>FB4</name>
              <bitOffset>4</bitOffset>
              <bitWidth>1</bitWidth>
            </field>
            <field>
              <name>FB5</name>
              <bitOffset>5</bitOffset>
              <bitWidth>1</bitWidth>
            </field>
            <field>
              <name>FB6</name>
              <bitOffset>6</bitOffset>
              <bitWidth>1</bitWidth>
            </field>
            <field>
              <name>FB7</name>
              <bitOffset>7</bitOffset>
              <bitWidth>1</bitWidth>
            </field>
            <field>
              <name>FB8</name>
              <bitOffset>8</bitOffset>
              <bitWidth>1</bitWidth>
            </field>
            <field>
              <name>FB9</name>
              <bitOffset>9</bitOffset>
              <bitWidth>1</bitWidth>
            </field>
            <field>
              <name>FB10</name>
              <bitOffset>10</bitOffset>
              <bitWidth>1</bitWidth>
            </field>
            <field>
              <name>FB11</name>
              <bitOffset>11</bitOffset>
              <bitWidth>1</bitWidth>
            </field>
            <field>
              <name>FB12</name>
              <bitOffset>12</bitOffset>
              <bitWidth>1</bitWidth>
            </field>
            <field>
              <name>FB13</name>
              <bitOffset>13</bitOffset>
              <bitWidth>1</bitWidth>
            </field>
            <field>
              <name>FB14</name>
              <bitOffset>14</bitOffset>
              <bitWidth>1</bitWidth>
            </field>
            <field>
              <name>FB15</name>
              <bitOffset>15</bitOffset>
              <bitWidth>1</bitWidth>
            </field>
            <field>
              <name>FB16</name>
              <bitOffset>16</bitOffset>
              <bitWidth>1</bitWidth>
            </field>
            <field>
              <name>FB17</name>
              <bitOffset>17</bitOffset>
              <bitWidth>1</bitWidth>
            </field>
            <field>
              <name>FB18</name>
              <bitOffset>18</bitOffset>
              <bitWidth>1</bitWidth>
            </field>
            <field>
              <name>FB19</name>
              <bitOffset>19</bitOffset>
              <bitWidth>1</bitWidth>
            </field>
            <field>
              <name>FB20</name>
              <bitOffset>20</bitOffset>
              <bitWidth>1</bitWidth>
            </field>
            <field>
              <name>FB21</name>
              <bitOffset>21</bitOffset>
              <bitWidth>1</bitWidth>
            </field>
            <field>
              <name>FB22</name>
              <bitOffset>22</bitOffset>
              <bitWidth>1</bitWidth>
            </field>
            <field>
              <name>FB23</name>
              <bitOffset>23</bitOffset>
              <bitWidth>1</bitWidth>
            </field>
            <field>
              <name>FB24</name>
              <bitOffset>24</bitOffset>
              <bitWidth>1</bitWidth>
            </field>
            <field>
              <name>FB25</name>
              <bitOffset>25</bitOffset>
              <bitWidth>1</bitWidth>
            </field>
            <field>
              <name>FB26</name>
              <bitOffset>26</bitOffset>
              <bitWidth>1</bitWidth>
            </field>
            <field>
              <name>FB27</name>
              <bitOffset>27</bitOffset>
              <bitWidth>1</bitWidth>
            </field>
            <field>
              <name>FB28</name>
              <bitOffset>28</bitOffset>
              <bitWidth>1</bitWidth>
            </field>
            <field>
              <name>FB29</name>
              <bitOffset>29</bitOffset>
              <bitWidth>1</bitWidth>
            </field>
            <field>
              <name>FB30</name>
              <bitOffset>30</bitOffset>
              <bitWidth>1</bitWidth>
            </field>
            <field>
              <name>FB31</name>
              <bitOffset>31</bitOffset>
              <bitWidth>1</bitWidth>
            </field>
          </fields>
        </register>
        <register>
          <name>sFilterRegister.13.FR1</name>
          <addressOffset>0x2a8</addressOffset>
          <size>0x20</size>
          <fields>
            <field>
              <name>FB0</name>
              <bitOffset>0</bitOffset>
              <bitWidth>1</bitWidth>
            </field>
            <field>
              <name>FB1</name>
              <bitOffset>1</bitOffset>
              <bitWidth>1</bitWidth>
            </field>
            <field>
              <name>FB2</name>
              <bitOffset>2</bitOffset>
              <bitWidth>1</bitWidth>
            </field>
            <field>
              <name>FB3</name>
              <bitOffset>3</bitOffset>
              <bitWidth>1</bitWidth>
            </field>
            <field>
              <name>FB4</name>
              <bitOffset>4</bitOffset>
              <bitWidth>1</bitWidth>
            </field>
            <field>
              <name>FB5</name>
              <bitOffset>5</bitOffset>
              <bitWidth>1</bitWidth>
            </field>
            <field>
              <name>FB6</name>
              <bitOffset>6</bitOffset>
              <bitWidth>1</bitWidth>
            </field>
            <field>
              <name>FB7</name>
              <bitOffset>7</bitOffset>
              <bitWidth>1</bitWidth>
            </field>
            <field>
              <name>FB8</name>
              <bitOffset>8</bitOffset>
              <bitWidth>1</bitWidth>
            </field>
            <field>
              <name>FB9</name>
              <bitOffset>9</bitOffset>
              <bitWidth>1</bitWidth>
            </field>
            <field>
              <name>FB10</name>
              <bitOffset>10</bitOffset>
              <bitWidth>1</bitWidth>
            </field>
            <field>
              <name>FB11</name>
              <bitOffset>11</bitOffset>
              <bitWidth>1</bitWidth>
            </field>
            <field>
              <name>FB12</name>
              <bitOffset>12</bitOffset>
              <bitWidth>1</bitWidth>
            </field>
            <field>
              <name>FB13</name>
              <bitOffset>13</bitOffset>
              <bitWidth>1</bitWidth>
            </field>
            <field>
              <name>FB14</name>
              <bitOffset>14</bitOffset>
              <bitWidth>1</bitWidth>
            </field>
            <field>
              <name>FB15</name>
              <bitOffset>15</bitOffset>
              <bitWidth>1</bitWidth>
            </field>
            <field>
              <name>FB16</name>
              <bitOffset>16</bitOffset>
              <bitWidth>1</bitWidth>
            </field>
            <field>
              <name>FB17</name>
              <bitOffset>17</bitOffset>
              <bitWidth>1</bitWidth>
            </field>
            <field>
              <name>FB18</name>
              <bitOffset>18</bitOffset>
              <bitWidth>1</bitWidth>
            </field>
            <field>
              <name>FB19</name>
              <bitOffset>19</bitOffset>
              <bitWidth>1</bitWidth>
            </field>
            <field>
              <name>FB20</name>
              <bitOffset>20</bitOffset>
              <bitWidth>1</bitWidth>
            </field>
            <field>
              <name>FB21</name>
              <bitOffset>21</bitOffset>
              <bitWidth>1</bitWidth>
            </field>
            <field>
              <name>FB22</name>
              <bitOffset>22</bitOffset>
              <bitWidth>1</bitWidth>
            </field>
            <field>
              <name>FB23</name>
              <bitOffset>23</bitOffset>
              <bitWidth>1</bitWidth>
            </field>
            <field>
              <name>FB24</name>
              <bitOffset>24</bitOffset>
              <bitWidth>1</bitWidth>
            </field>
            <field>
              <name>FB25</name>
              <bitOffset>25</bitOffset>
              <bitWidth>1</bitWidth>
            </field>
            <field>
              <name>FB26</name>
              <bitOffset>26</bitOffset>
              <bitWidth>1</bitWidth>
            </field>
            <field>
              <name>FB27</name>
              <bitOffset>27</bitOffset>
              <bitWidth>1</bitWidth>
            </field>
            <field>
              <name>FB28</name>
              <bitOffset>28</bitOffset>
              <bitWidth>1</bitWidth>
            </field>
            <field>
              <name>FB29</name>
              <bitOffset>29</bitOffset>
              <bitWidth>1</bitWidth>
            </field>
            <field>
              <name>FB30</name>
              <bitOffset>30</bitOffset>
              <bitWidth>1</bitWidth>
            </field>
            <field>
              <name>FB31</name>
              <bitOffset>31</bitOffset>
              <bitWidth>1</bitWidth>
            </field>
          </fields>
        </register>
        <register>
          <name>sFilterRegister.13.FR2</name>
          <addressOffset>0x2ac</addressOffset>
          <size>0x20</size>
          <fields>
            <field>
              <name>FB0</name>
              <bitOffset>0</bitOffset>
              <bitWidth>1</bitWidth>
            </field>
            <field>
              <name>FB1</name>
              <bitOffset>1</bitOffset>
              <bitWidth>1</bitWidth>
            </field>
            <field>
              <name>FB2</name>
              <bitOffset>2</bitOffset>
              <bitWidth>1</bitWidth>
            </field>
            <field>
              <name>FB3</name>
              <bitOffset>3</bitOffset>
              <bitWidth>1</bitWidth>
            </field>
            <field>
              <name>FB4</name>
              <bitOffset>4</bitOffset>
              <bitWidth>1</bitWidth>
            </field>
            <field>
              <name>FB5</name>
              <bitOffset>5</bitOffset>
              <bitWidth>1</bitWidth>
            </field>
            <field>
              <name>FB6</name>
              <bitOffset>6</bitOffset>
              <bitWidth>1</bitWidth>
            </field>
            <field>
              <name>FB7</name>
              <bitOffset>7</bitOffset>
              <bitWidth>1</bitWidth>
            </field>
            <field>
              <name>FB8</name>
              <bitOffset>8</bitOffset>
              <bitWidth>1</bitWidth>
            </field>
            <field>
              <name>FB9</name>
              <bitOffset>9</bitOffset>
              <bitWidth>1</bitWidth>
            </field>
            <field>
              <name>FB10</name>
              <bitOffset>10</bitOffset>
              <bitWidth>1</bitWidth>
            </field>
            <field>
              <name>FB11</name>
              <bitOffset>11</bitOffset>
              <bitWidth>1</bitWidth>
            </field>
            <field>
              <name>FB12</name>
              <bitOffset>12</bitOffset>
              <bitWidth>1</bitWidth>
            </field>
            <field>
              <name>FB13</name>
              <bitOffset>13</bitOffset>
              <bitWidth>1</bitWidth>
            </field>
            <field>
              <name>FB14</name>
              <bitOffset>14</bitOffset>
              <bitWidth>1</bitWidth>
            </field>
            <field>
              <name>FB15</name>
              <bitOffset>15</bitOffset>
              <bitWidth>1</bitWidth>
            </field>
            <field>
              <name>FB16</name>
              <bitOffset>16</bitOffset>
              <bitWidth>1</bitWidth>
            </field>
            <field>
              <name>FB17</name>
              <bitOffset>17</bitOffset>
              <bitWidth>1</bitWidth>
            </field>
            <field>
              <name>FB18</name>
              <bitOffset>18</bitOffset>
              <bitWidth>1</bitWidth>
            </field>
            <field>
              <name>FB19</name>
              <bitOffset>19</bitOffset>
              <bitWidth>1</bitWidth>
            </field>
            <field>
              <name>FB20</name>
              <bitOffset>20</bitOffset>
              <bitWidth>1</bitWidth>
            </field>
            <field>
              <name>FB21</name>
              <bitOffset>21</bitOffset>
              <bitWidth>1</bitWidth>
            </field>
            <field>
              <name>FB22</name>
              <bitOffset>22</bitOffset>
              <bitWidth>1</bitWidth>
            </field>
            <field>
              <name>FB23</name>
              <bitOffset>23</bitOffset>
              <bitWidth>1</bitWidth>
            </field>
            <field>
              <name>FB24</name>
              <bitOffset>24</bitOffset>
              <bitWidth>1</bitWidth>
            </field>
            <field>
              <name>FB25</name>
              <bitOffset>25</bitOffset>
              <bitWidth>1</bitWidth>
            </field>
            <field>
              <name>FB26</name>
              <bitOffset>26</bitOffset>
              <bitWidth>1</bitWidth>
            </field>
            <field>
              <name>FB27</name>
              <bitOffset>27</bitOffset>
              <bitWidth>1</bitWidth>
            </field>
            <field>
              <name>FB28</name>
              <bitOffset>28</bitOffset>
              <bitWidth>1</bitWidth>
            </field>
            <field>
              <name>FB29</name>
              <bitOffset>29</bitOffset>
              <bitWidth>1</bitWidth>
            </field>
            <field>
              <name>FB30</name>
              <bitOffset>30</bitOffset>
              <bitWidth>1</bitWidth>
            </field>
            <field>
              <name>FB31</name>
              <bitOffset>31</bitOffset>
              <bitWidth>1</bitWidth>
            </field>
          </fields>
        </register>
      </registers>
    </peripheral>
    <peripheral>
      <name>CRS</name>
      <baseAddress>0x40006c00</baseAddress>
      <registers>
        <register>
          <name>CR</name>
          <addressOffset>0x0</addressOffset>
          <size>0x20</size>
          <fields>
            <field>
              <name>SYNCOKIE</name>
              <bitOffset>0</bitOffset>
              <bitWidth>1</bitWidth>
            </field>
            <field>
              <name>SYNCWARNIE</name>
              <bitOffset>1</bitOffset>
              <bitWidth>1</bitWidth>
            </field>
            <field>
              <name>ERRIE</name>
              <bitOffset>2</bitOffset>
              <bitWidth>1</bitWidth>
            </field>
            <field>
              <name>ESYNCIE</name>
              <bitOffset>3</bitOffset>
              <bitWidth>1</bitWidth>
            </field>
            <field>
              <name>CEN</name>
              <bitOffset>5</bitOffset>
              <bitWidth>1</bitWidth>
            </field>
            <field>
              <name>AUTOTRIMEN</name>
              <bitOffset>6</bitOffset>
              <bitWidth>1</bitWidth>
            </field>
            <field>
              <name>SWSYNC</name>
              <bitOffset>7</bitOffset>
              <bitWidth>1</bitWidth>
            </field>
            <field>
              <name>TRIM</name>
              <bitOffset>8</bitOffset>
              <bitWidth>6</bitWidth>
            </field>
          </fields>
        </register>
        <register>
          <name>CFGR</name>
          <addressOffset>0x4</addressOffset>
          <size>0x20</size>
          <fields>
            <field>
              <name>RELOAD</name>
              <bitOffset>0</bitOffset>
              <bitWidth>16</bitWidth>
            </field>
            <field>
              <name>FELIM</name>
              <bitOffset>16</bitOffset>
              <bitWidth>8</bitWidth>
            </field>
            <field>
              <name>SYNCDIV</name>
              <bitOffset>24</bitOffset>
              <bitWidth>3</bitWidth>
            </field>
            <field>
              <name>SYNCSRC</name>
              <bitOffset>28</bitOffset>
              <bitWidth>2</bitWidth>
            </field>
            <field>
              <name>SYNCPOL</name>
              <bitOffset>31</bitOffset>
              <bitWidth>1</bitWidth>
            </field>
          </fields>
        </register>
        <register>
          <name>ISR</name>
          <addressOffset>0x8</addressOffset>
          <size>0x20</size>
          <fields>
            <field>
              <name>SYNCOKF</name>
              <bitOffset>0</bitOffset>
              <bitWidth>1</bitWidth>
            </field>
            <field>
              <name>SYNCWARNF</name>
              <bitOffset>1</bitOffset>
              <bitWidth>1</bitWidth>
            </field>
            <field>
              <name>ERRF</name>
              <bitOffset>2</bitOffset>
              <bitWidth>1</bitWidth>
            </field>
            <field>
              <name>ESYNCF</name>
              <bitOffset>3</bitOffset>
              <bitWidth>1</bitWidth>
            </field>
            <field>
              <name>SYNCERR</name>
              <bitOffset>8</bitOffset>
              <bitWidth>1</bitWidth>
            </field>
            <field>
              <name>SYNCMISS</name>
              <bitOffset>9</bitOffset>
              <bitWidth>1</bitWidth>
            </field>
            <field>
              <name>TRIMOVF</name>
              <bitOffset>10</bitOffset>
              <bitWidth>1</bitWidth>
            </field>
            <field>
              <name>FEDIR</name>
              <bitOffset>15</bitOffset>
              <bitWidth>1</bitWidth>
            </field>
            <field>
              <name>FECAP</name>
              <bitOffset>16</bitOffset>
              <bitWidth>16</bitWidth>
            </field>
          </fields>
        </register>
        <register>
          <name>ICR</name>
          <addressOffset>0xc</addressOffset>
          <size>0x20</size>
          <fields>
            <field>
              <name>SYNCOKC</name>
              <bitOffset>0</bitOffset>
              <bitWidth>1</bitWidth>
            </field>
            <field>
              <name>SYNCWARNC</name>
              <bitOffset>1</bitOffset>
              <bitWidth>1</bitWidth>
            </field>
            <field>
              <name>ERRC</name>
              <bitOffset>2</bitOffset>
              <bitWidth>1</bitWidth>
            </field>
            <field>
              <name>ESYNCC</name>
              <bitOffset>3</bitOffset>
              <bitWidth>1</bitWidth>
            </field>
          </fields>
        </register>
      </registers>
    </peripheral>
    <peripheral>
      <name>PWR</name>
      <baseAddress>0x40007000</baseAddress>
      <registers>
        <register>
          <name>CR</name>
          <addressOffset>0x0</addressOffset>
          <size>0x20</size>
          <fields>
            <field>
              <name>LPDS</name>
              <bitOffset>0</bitOffset>
              <bitWidth>1</bitWidth>
            </field>
            <field>
              <name>PDDS</name>
              <bitOffset>1</bitOffset>
              <bitWidth>1</bitWidth>
            </field>
            <field>
              <name>CWUF</name>
              <bitOffset>2</bitOffset>
              <bitWidth>1</bitWidth>
            </field>
            <field>
              <name>CSBF</name>
              <bitOffset>3</bitOffset>
              <bitWidth>1</bitWidth>
            </field>
            <field>
              <name>PVDE</name>
              <bitOffset>4</bitOffset>
              <bitWidth>1</bitWidth>
            </field>
            <field>
              <name>PLS</name>
              <bitOffset>5</bitOffset>
              <bitWidth>3</bitWidth>
            </field>
            <field>
              <name>DBP</name>
              <bitOffset>8</bitOffset>
              <bitWidth>1</bitWidth>
            </field>
          </fields>
        </register>
        <register>
          <name>CSR</name>
          <addressOffset>0x4</addressOffset>
          <size>0x20</size>
          <fields>
            <field>
              <name>WUF</name>
              <bitOffset>0</bitOffset>
              <bitWidth>1</bitWidth>
            </field>
            <field>
              <name>SBF</name>
              <bitOffset>1</bitOffset>
              <bitWidth>1</bitWidth>
            </field>
            <field>
              <name>PVDO</name>
              <bitOffset>2</bitOffset>
              <bitWidth>1</bitWidth>
            </field>
            <field>
              <name>VREFINTRDYF</name>
              <bitOffset>3</bitOffset>
              <bitWidth>1</bitWidth>
            </field>
            <field>
              <name>EWUP1</name>
              <bitOffset>8</bitOffset>
              <bitWidth>1</bitWidth>
            </field>
            <field>
              <name>EWUP2</name>
              <bitOffset>9</bitOffset>
              <bitWidth>1</bitWidth>
            </field>
            <field>
              <name>EWUP3</name>
              <bitOffset>10</bitOffset>
              <bitWidth>1</bitWidth>
            </field>
            <field>
              <name>EWUP4</name>
              <bitOffset>11</bitOffset>
              <bitWidth>1</bitWidth>
            </field>
            <field>
              <name>EWUP5</name>
              <bitOffset>12</bitOffset>
              <bitWidth>1</bitWidth>
            </field>
            <field>
              <name>EWUP6</name>
              <bitOffset>13</bitOffset>
              <bitWidth>1</bitWidth>
            </field>
            <field>
              <name>EWUP7</name>
              <bitOffset>14</bitOffset>
              <bitWidth>1</bitWidth>
            </field>
            <field>
              <name>EWUP8</name>
              <bitOffset>15</bitOffset>
              <bitWidth>1</bitWidth>
            </field>
          </fields>
        </register>
      </registers>
    </peripheral>
    <peripheral>
      <name>DAC1</name>
      <baseAddress>0x40007400</baseAddress>
      <registers>
        <register>
          <name>CR</name>
          <addressOffset>0x0</addressOffset>
          <size>0x20</size>
          <fields>
            <field>
              <name>EN1</name>
              <bitOffset>0</bitOffset>
              <bitWidth>1</bitWidth>
            </field>
            <field>
              <name>BOFF1</name>
              <bitOffset>1</bitOffset>
              <bitWidth>1</bitWidth>
            </field>
            <field>
              <name>TEN1</name>
              <bitOffset>2</bitOffset>
              <bitWidth>1</bitWidth>
            </field>
            <field>
              <name>TSEL1</name>
              <bitOffset>3</bitOffset>
              <bitWidth>3</bitWidth>
            </field>
            <field>
              <name>WAVE1</name>
              <bitOffset>6</bitOffset>
              <bitWidth>2</bitWidth>
            </field>
            <field>
              <name>MAMP1</name>
              <bitOffset>8</bitOffset>
              <bitWidth>4</bitWidth>
            </field>
            <field>
              <name>DMAEN1</name>
              <bitOffset>12</bitOffset>
              <bitWidth>1</bitWidth>
            </field>
            <field>
              <name>DMAUDRIE1</name>
              <bitOffset>13</bitOffset>
              <bitWidth>1</bitWidth>
            </field>
            <field>
              <name>EN2</name>
              <bitOffset>16</bitOffset>
              <bitWidth>1</bitWidth>
            </field>
            <field>
              <name>BOFF2</name>
              <bitOffset>17</bitOffset>
              <bitWidth>1</bitWidth>
            </field>
            <field>
              <name>TEN2</name>
              <bitOffset>18</bitOffset>
              <bitWidth>1</bitWidth>
            </field>
            <field>
              <name>TSEL2</name>
              <bitOffset>19</bitOffset>
              <bitWidth>3</bitWidth>
            </field>
            <field>
              <name>WAVE2</name>
              <bitOffset>22</bitOffset>
              <bitWidth>2</bitWidth>
            </field>
            <field>
              <name>MAMP2</name>
              <bitOffset>24</bitOffset>
              <bitWidth>4</bitWidth>
            </field>
            <field>
              <name>DMAEN2</name>
              <bitOffset>28</bitOffset>
              <bitWidth>1</bitWidth>
            </field>
            <field>
              <name>DMAUDRIE2</name>
              <bitOffset>29</bitOffset>
              <bitWidth>1</bitWidth>
            </field>
          </fields>
        </register>
        <register>
          <name>SWTRIGR</name>
          <addressOffset>0x4</addressOffset>
          <size>0x20</size>
          <fields>
            <field>
              <name>SWTRIG1</name>
              <bitOffset>0</bitOffset>
              <bitWidth>1</bitWidth>
            </field>
            <field>
              <name>SWTRIG2</name>
              <bitOffset>1</bitOffset>
              <bitWidth>1</bitWidth>
            </field>
          </fields>
        </register>
        <register>
          <name>DHR12R1</name>
          <addressOffset>0x8</addressOffset>
          <size>0x20</size>
          <fields>
            <field>
              <name>DACC1DHR</name>
              <bitOffset>0</bitOffset>
              <bitWidth>12</bitWidth>
            </field>
          </fields>
        </register>
        <register>
          <name>DHR12L1</name>
          <addressOffset>0xc</addressOffset>
          <size>0x20</size>
          <fields>
            <field>
              <name>DACC1DHR</name>
              <bitOffset>4</bitOffset>
              <bitWidth>12</bitWidth>
            </field>
          </fields>
        </register>
        <register>
          <name>DHR8R1</name>
          <addressOffset>0x10</addressOffset>
          <size>0x20</size>
          <fields>
            <field>
              <name>DACC1DHR</name>
              <bitOffset>0</bitOffset>
              <bitWidth>8</bitWidth>
            </field>
          </fields>
        </register>
        <register>
          <name>DHR12R2</name>
          <addressOffset>0x14</addressOffset>
          <size>0x20</size>
          <fields>
            <field>
              <name>DACC2DHR</name>
              <bitOffset>0</bitOffset>
              <bitWidth>12</bitWidth>
            </field>
          </fields>
        </register>
        <register>
          <name>DHR12L2</name>
          <addressOffset>0x18</addressOffset>
          <size>0x20</size>
          <fields>
            <field>
              <name>DACC2DHR</name>
              <bitOffset>4</bitOffset>
              <bitWidth>12</bitWidth>
            </field>
          </fields>
        </register>
        <register>
          <name>DHR8R2</name>
          <addressOffset>0x1c</addressOffset>
          <size>0x20</size>
          <fields>
            <field>
              <name>DACC2DHR</name>
              <bitOffset>0</bitOffset>
              <bitWidth>8</bitWidth>
            </field>
          </fields>
        </register>
        <register>
          <name>DHR12RD</name>
          <addressOffset>0x20</addressOffset>
          <size>0x20</size>
          <fields>
            <field>
              <name>DACC1DHR</name>
              <bitOffset>0</bitOffset>
              <bitWidth>12</bitWidth>
            </field>
            <field>
              <name>DACC2DHR</name>
              <bitOffset>16</bitOffset>
              <bitWidth>12</bitWidth>
            </field>
          </fields>
        </register>
        <register>
          <name>DHR12LD</name>
          <addressOffset>0x24</addressOffset>
          <size>0x20</size>
          <fields>
            <field>
              <name>DACC1DHR</name>
              <bitOffset>4</bitOffset>
              <bitWidth>12</bitWidth>
            </field>
            <field>
              <name>DACC2DHR</name>
              <bitOffset>20</bitOffset>
              <bitWidth>12</bitWidth>
            </field>
          </fields>
        </register>
        <register>
          <name>DHR8RD</name>
          <addressOffset>0x28</addressOffset>
          <size>0x20</size>
          <fields>
            <field>
              <name>DACC1DHR</name>
              <bitOffset>0</bitOffset>
              <bitWidth>8</bitWidth>
            </field>
            <field>
              <name>DACC2DHR</name>
              <bitOffset>8</bitOffset>
              <bitWidth>8</bitWidth>
            </field>
          </fields>
        </register>
        <register>
          <name>DOR1</name>
          <addressOffset>0x2c</addressOffset>
          <size>0x20</size>
          <fields>
            <field>
              <name>DACC1DOR</name>
              <bitOffset>0</bitOffset>
              <bitWidth>12</bitWidth>
            </field>
          </fields>
        </register>
        <register>
          <name>DOR2</name>
          <addressOffset>0x30</addressOffset>
          <size>0x20</size>
          <fields>
            <field>
              <name>DACC2DOR</name>
              <bitOffset>0</bitOffset>
              <bitWidth>12</bitWidth>
            </field>
          </fields>
        </register>
        <register>
          <name>SR</name>
          <addressOffset>0x34</addressOffset>
          <size>0x20</size>
          <fields>
            <field>
              <name>DMAUDR1</name>
              <bitOffset>13</bitOffset>
              <bitWidth>1</bitWidth>
            </field>
            <field>
              <name>DMAUDR2</name>
              <bitOffset>29</bitOffset>
              <bitWidth>1</bitWidth>
            </field>
          </fields>
        </register>
      </registers>
    </peripheral>
    <peripheral>
      <name>CEC</name>
      <baseAddress>0x40007800</baseAddress>
      <registers>
        <register>
          <name>CR</name>
          <addressOffset>0x0</addressOffset>
          <size>0x20</size>
          <fields>
            <field>
              <name>CECEN</name>
              <bitOffset>0</bitOffset>
              <bitWidth>1</bitWidth>
            </field>
            <field>
              <name>TXSOM</name>
              <bitOffset>1</bitOffset>
              <bitWidth>1</bitWidth>
            </field>
            <field>
              <name>TXEOM</name>
              <bitOffset>2</bitOffset>
              <bitWidth>1</bitWidth>
            </field>
          </fields>
        </register>
        <register>
          <name>CFGR</name>
          <addressOffset>0x4</addressOffset>
          <size>0x20</size>
          <fields>
            <field>
              <name>SFT</name>
              <bitOffset>0</bitOffset>
              <bitWidth>3</bitWidth>
            </field>
            <field>
              <name>RXTOL</name>
              <bitOffset>3</bitOffset>
              <bitWidth>1</bitWidth>
            </field>
            <field>
              <name>BRESTP</name>
              <bitOffset>4</bitOffset>
              <bitWidth>1</bitWidth>
            </field>
            <field>
              <name>BREGEN</name>
              <bitOffset>5</bitOffset>
              <bitWidth>1</bitWidth>
            </field>
            <field>
              <name>LBPEGEN</name>
              <bitOffset>6</bitOffset>
              <bitWidth>1</bitWidth>
            </field>
            <field>
              <name>BRDNOGEN</name>
              <bitOffset>7</bitOffset>
              <bitWidth>1</bitWidth>
            </field>
            <field>
              <name>SFTOPT</name>
              <bitOffset>8</bitOffset>
              <bitWidth>1</bitWidth>
            </field>
            <field>
              <name>OAR</name>
              <bitOffset>16</bitOffset>
              <bitWidth>15</bitWidth>
            </field>
            <field>
              <name>LSTN</name>
              <bitOffset>31</bitOffset>
              <bitWidth>1</bitWidth>
            </field>
          </fields>
        </register>
        <register>
          <name>TXDR</name>
          <addressOffset>0x8</addressOffset>
          <size>0x20</size>
          <fields>
            <field>
              <name>TXD</name>
              <bitOffset>0</bitOffset>
              <bitWidth>8</bitWidth>
            </field>
          </fields>
        </register>
        <register>
          <name>RXDR</name>
          <addressOffset>0xc</addressOffset>
          <size>0x20</size>
          <fields>
            <field>
              <name>RXD</name>
              <bitOffset>0</bitOffset>
              <bitWidth>8</bitWidth>
            </field>
          </fields>
        </register>
        <register>
          <name>ISR</name>
          <addressOffset>0x10</addressOffset>
          <size>0x20</size>
        </register>
        <register>
          <name>IER</name>
          <addressOffset>0x14</addressOffset>
          <size>0x20</size>
          <fields>
            <field>
              <name>RXBRIE</name>
              <bitOffset>0</bitOffset>
              <bitWidth>1</bitWidth>
            </field>
            <field>
              <name>RXENDIE</name>
              <bitOffset>1</bitOffset>
              <bitWidth>1</bitWidth>
            </field>
            <field>
              <name>RXOVRIE</name>
              <bitOffset>2</bitOffset>
              <bitWidth>1</bitWidth>
            </field>
            <field>
              <name>BREIE</name>
              <bitOffset>3</bitOffset>
              <bitWidth>1</bitWidth>
            </field>
            <field>
              <name>SBPEIE</name>
              <bitOffset>4</bitOffset>
              <bitWidth>1</bitWidth>
            </field>
            <field>
              <name>LBPEIE</name>
              <bitOffset>5</bitOffset>
              <bitWidth>1</bitWidth>
            </field>
            <field>
              <name>RXACKEIE</name>
              <bitOffset>6</bitOffset>
              <bitWidth>1</bitWidth>
            </field>
            <field>
              <name>ARBLSTIE</name>
              <bitOffset>7</bitOffset>
              <bitWidth>1</bitWidth>
            </field>
            <field>
              <name>TXBRIE</name>
              <bitOffset>8</bitOffset>
              <bitWidth>1</bitWidth>
            </field>
            <field>
              <name>TXENDIE</name>
              <bitOffset>9</bitOffset>
              <bitWidth>1</bitWidth>
            </field>
            <field>
              <name>TXUDRIE</name>
              <bitOffset>10</bitOffset>
              <bitWidth>1</bitWidth>
            </field>
            <field>
              <name>TXERRIE</name>
              <bitOffset>11</bitOffset>
              <bitWidth>1</bitWidth>
            </field>
            <field>
              <name>TXACKEIE</name>
              <bitOffset>12</bitOffset>
              <bitWidth>1</bitWidth>
            </field>
          </fields>
        </register>
      </registers>
    </peripheral>
    <peripheral>
      <name>SYSCFG</name>
      <baseAddress>0x40010000</baseAddress>
      <registers>
        <register>
          <name>CFGR1</name>
          <addressOffset>0x0</addressOffset>
          <size>0x20</size>
          <fields>
            <field>
              <name>MEM_MODE</name>
              <bitOffset>0</bitOffset>
              <bitWidth>2</bitWidth>
            </field>
            <field>
              <name>DMA_RMP</name>
              <bitOffset>8</bitOffset>
              <bitWidth>23</bitWidth>
            </field>
            <field>
              <name>USART1TX_DMA_RMP</name>
              <bitOffset>9</bitOffset>
              <bitWidth>1</bitWidth>
            </field>
            <field>
              <name>USART1RX_DMA_RMP</name>
              <bitOffset>10</bitOffset>
              <bitWidth>1</bitWidth>
            </field>
            <field>
              <name>TIM16_DMA_RMP</name>
              <bitOffset>11</bitOffset>
              <bitWidth>1</bitWidth>
            </field>
            <field>
              <name>TIM17_DMA_RMP</name>
              <bitOffset>12</bitOffset>
              <bitWidth>1</bitWidth>
            </field>
            <field>
              <name>TIM16_DMA_RMP2</name>
              <bitOffset>13</bitOffset>
              <bitWidth>1</bitWidth>
            </field>
            <field>
              <name>TIM17_DMA_RMP2</name>
              <bitOffset>14</bitOffset>
              <bitWidth>1</bitWidth>
            </field>
            <field>
              <name>I2C_FMP_PB6</name>
              <bitOffset>16</bitOffset>
              <bitWidth>1</bitWidth>
            </field>
            <field>
              <name>I2C_FMP_PB7</name>
              <bitOffset>17</bitOffset>
              <bitWidth>1</bitWidth>
            </field>
            <field>
              <name>I2C_FMP_PB8</name>
              <bitOffset>18</bitOffset>
              <bitWidth>1</bitWidth>
            </field>
            <field>
              <name>I2C_FMP_PB9</name>
              <bitOffset>19</bitOffset>
              <bitWidth>1</bitWidth>
            </field>
            <field>
              <name>I2C_FMP_I2C1</name>
              <bitOffset>20</bitOffset>
              <bitWidth>1</bitWidth>
            </field>
            <field>
              <name>I2C_FMP_I2C2</name>
              <bitOffset>21</bitOffset>
              <bitWidth>1</bitWidth>
            </field>
            <field>
              <name>SPI2_DMA_RMP</name>
              <bitOffset>24</bitOffset>
              <bitWidth>1</bitWidth>
            </field>
            <field>
              <name>USART2_DMA_RMP</name>
              <bitOffset>25</bitOffset>
              <bitWidth>1</bitWidth>
            </field>
            <field>
              <name>USART3_DMA_RMP</name>
              <bitOffset>26</bitOffset>
              <bitWidth>1</bitWidth>
            </field>
            <field>
              <name>I2C1_DMA_RMP</name>
              <bitOffset>27</bitOffset>
              <bitWidth>1</bitWidth>
            </field>
            <field>
              <name>TIM1_DMA_RMP</name>
              <bitOffset>28</bitOffset>
              <bitWidth>1</bitWidth>
            </field>
            <field>
              <name>TIM2_DMA_RMP</name>
              <bitOffset>29</bitOffset>
              <bitWidth>1</bitWidth>
            </field>
            <field>
              <name>TIM3_DMA_RMP</name>
              <bitOffset>30</bitOffset>
              <bitWidth>1</bitWidth>
            </field>
          </fields>
        </register>
        <register>
          <name>EXTICR.0</name>
          <addressOffset>0x8</addressOffset>
          <size>0x20</size>
          <fields>
            <field>
              <name>EXTI0</name>
              <bitOffset>0</bitOffset>
              <bitWidth>4</bitWidth>
            </field>
            <field>
              <name>EXTI1</name>
              <bitOffset>4</bitOffset>
              <bitWidth>4</bitWidth>
            </field>
            <field>
              <name>EXTI2</name>
              <bitOffset>8</bitOffset>
              <bitWidth>4</bitWidth>
            </field>
            <field>
              <name>EXTI3</name>
              <bitOffset>12</bitOffset>
              <bitWidth>4</bitWidth>
            </field>
          </fields>
        </register>
        <register>
          <name>EXTICR.1</name>
          <addressOffset>0xc</addressOffset>
          <size>0x20</size>
          <fields>
            <field>
              <name>EXTI4</name>
              <bitOffset>0</bitOffset>
              <bitWidth>4</bitWidth>
            </field>
            <field>
              <name>EXTI5</name>
              <bitOffset>4</bitOffset>
              <bitWidth>4</bitWidth>
            </field>
            <field>
              <name>EXTI6</name>
              <bitOffset>8</bitOffset>
              <bitWidth>4</bitWidth>
            </field>
            <field>
              <name>EXTI7</name>
              <bitOffset>12</bitOffset>
              <bitWidth>4</bitWidth>
            </field>
          </fields>
        </register>
        <register>
          <name>EXTICR.2</name>
          <addressOffset>0x10</addressOffset>
          <size>0x20</size>
          <fields>
            <field>
              <name>EXTI8</name>
              <bitOffset>0</bitOffset>
              <bitWidth>4</bitWidth>
            </field>
            <field>
              <name>EXTI9</name>
              <bitOffset>4</bitOffset>
              <bitWidth>4</bitWidth>
            </field>
            <field>
              <name>EXTI10</name>
              <bitOffset>8</bitOffset>
              <bitWidth>4</bitWidth>
            </field>
            <field>
              <name>EXTI11</name>
              <bitOffset>12</bitOffset>
              <bitWidth>4</bitWidth>
            </field>
          </fields>
        </register>
        <register>
          <name>EXTICR.3</name>
          <addressOffset>0x14</addressOffset>
          <size>0x20</size>
          <fields>
            <field>
              <name>EXTI12</name>
              <bitOffset>0</bitOffset>
              <bitWidth>4</bitWidth>
            </field>
            <field>
              <name>EXTI13</name>
              <bitOffset>4</bitOffset>
              <bitWidth>4</bitWidth>
            </field>
            <field>
              <name>EXTI14</name>
              <bitOffset>8</bitOffset>
              <bitWidth>4</bitWidth>
            </field>
            <field>
              <name>EXTI15</name>
              <bitOffset>12</bitOffset>
              <bitWidth>4</bitWidth>
            </field>
          </fields>
        </register>
        <register>
          <name>CFGR2</name>
          <addressOffset>0x18</addressOffset>
          <size>0x20</size>
          <fields>
            <field>
              <name>LOCKUP_LOCK</name>
              <bitOffset>0</bitOffset>
              <bitWidth>1</bitWidth>
            </field>
            <field>
              <name>SRAM_PARITY_LOCK</name>
              <bitOffset>1</bitOffset>
              <bitWidth>1</bitWidth>
            </field>
            <field>
              <name>PVD_LOCK</name>
              <bitOffset>2</bitOffset>
              <bitWidth>1</bitWidth>
            </field>
            <field>
              <name>SRAM_PEF</name>
              <bitOffset>8</bitOffset>
              <bitWidth>1</bitWidth>
            </field>
          </fields>
        </register>
      </registers>
    </peripheral>
    <peripheral>
      <name>COMP1</name>
      <baseAddress>0x4001001c</baseAddress>
      <registers>
        <register>
          <name>CSR</name>
          <addressOffset>0x0</addressOffset>
          <size>0x10</size>
          <fields>
            <field>
              <name>COMPxEN</name>
              <bitOffset>0</bitOffset>
              <bitWidth>1</bitWidth>
            </field>
            <field>
              <name>COMP1SW1</name>
              <bitOffset>1</bitOffset>
              <bitWidth>1</bitWidth>
            </field>
            <field>
              <name>COMPxMODE</name>
              <bitOffset>2</bitOffset>
              <bitWidth>2</bitWidth>
            </field>
            <field>
              <name>COMPxINSEL</name>
              <bitOffset>4</bitOffset>
              <bitWidth>3</bitWidth>
            </field>
            <field>
              <name>COMPxOUTSEL</name>
              <bitOffset>8</bitOffset>
              <bitWidth>3</bitWidth>
            </field>
            <field>
              <name>COMPxPOL</name>
              <bitOffset>11</bitOffset>
              <bitWidth>1</bitWidth>
            </field>
            <field>
              <name>COMPxHYST</name>
              <bitOffset>12</bitOffset>
              <bitWidth>2</bitWidth>
            </field>
            <field>
              <name>COMPxOUT</name>
              <bitOffset>14</bitOffset>
              <bitWidth>1</bitWidth>
            </field>
            <field>
              <name>COMPxLOCK</name>
              <bitOffset>15</bitOffset>
              <bitWidth>1</bitWidth>
            </field>
            <field>
              <name>COMP2EN</name>
              <bitOffset>16</bitOffset>
              <bitWidth>1</bitWidth>
            </field>
            <field>
              <name>COMP2MODE</name>
              <bitOffset>18</bitOffset>
              <bitWidth>2</bitWidth>
            </field>
            <field>
              <name>COMP2INSEL</name>
              <bitOffset>20</bitOffset>
              <bitWidth>3</bitWidth>
            </field>
            <field>
              <name>WNDWEN</name>
              <bitOffset>23</bitOffset>
              <bitWidth>1</bitWidth>
            </field>
            <field>
              <name>COMP2OUTSEL</name>
              <bitOffset>24</bitOffset>
              <bitWidth>3</bitWidth>
            </field>
            <field>
              <name>COMP2POL</name>
              <bitOffset>27</bitOffset>
              <bitWidth>1</bitWidth>
            </field>
            <field>
              <name>COMP2HYST</name>
              <bitOffset>28</bitOffset>
              <bitWidth>2</bitWidth>
            </field>
            <field>
              <name>COMP2OUT</name>
              <bitOffset>30</bitOffset>
              <bitWidth>1</bitWidth>
            </field>
            <field>
              <name>COMP2LOCK</name>
              <bitOffset>31</bitOffset>
              <bitWidth>1</bitWidth>
            </field>
          </fields>
        </register>
      </registers>
    </peripheral>
    <peripheral>
      <name>COMP12_COMMON</name>
      <baseAddress>0x4001001c</baseAddress>
      <registers>
        <register>
          <name>CSR</name>
          <addressOffset>0x0</addressOffset>
          <size>0x20</size>
          <fields>
            <field>
              <name>COMPxEN</name>
              <bitOffset>0</bitOffset>
              <bitWidth>1</bitWidth>
            </field>
            <field>
              <name>COMP1SW1</name>
              <bitOffset>1</bitOffset>
              <bitWidth>1</bitWidth>
            </field>
            <field>
              <name>COMPxMODE</name>
              <bitOffset>2</bitOffset>
              <bitWidth>2</bitWidth>
            </field>
            <field>
              <name>COMPxINSEL</name>
              <bitOffset>4</bitOffset>
              <bitWidth>3</bitWidth>
            </field>
            <field>
              <name>COMPxOUTSEL</name>
              <bitOffset>8</bitOffset>
              <bitWidth>3</bitWidth>
            </field>
            <field>
              <name>COMPxPOL</name>
              <bitOffset>11</bitOffset>
              <bitWidth>1</bitWidth>
            </field>
            <field>
              <name>COMPxHYST</name>
              <bitOffset>12</bitOffset>
              <bitWidth>2</bitWidth>
            </field>
            <field>
              <name>COMPxOUT</name>
              <bitOffset>14</bitOffset>
              <bitWidth>1</bitWidth>
            </field>
            <field>
              <name>COMPxLOCK</name>
              <bitOffset>15</bitOffset>
              <bitWidth>1</bitWidth>
            </field>
            <field>
              <name>COMP2EN</name>
              <bitOffset>16</bitOffset>
              <bitWidth>1</bitWidth>
            </field>
            <field>
              <name>COMP2MODE</name>
              <bitOffset>18</bitOffset>
              <bitWidth>2</bitWidth>
            </field>
            <field>
              <name>COMP2INSEL</name>
              <bitOffset>20</bitOffset>
              <bitWidth>3</bitWidth>
            </field>
            <field>
              <name>WNDWEN</name>
              <bitOffset>23</bitOffset>
              <bitWidth>1</bitWidth>
            </field>
            <field>
              <name>COMP2OUTSEL</name>
              <bitOffset>24</bitOffset>
              <bitWidth>3</bitWidth>
            </field>
            <field>
              <name>COMP2POL</name>
              <bitOffset>27</bitOffset>
              <bitWidth>1</bitWidth>
            </field>
            <field>
              <name>COMP2HYST</name>
              <bitOffset>28</bitOffset>
              <bitWidth>2</bitWidth>
            </field>
            <field>
              <name>COMP2OUT</name>
              <bitOffset>30</bitOffset>
              <bitWidth>1</bitWidth>
            </field>
            <field>
              <name>COMP2LOCK</name>
              <bitOffset>31</bitOffset>
              <bitWidth>1</bitWidth>
            </field>
          </fields>
        </register>
      </registers>
    </peripheral>
    <peripheral>
      <name>COMP2</name>
      <baseAddress>0x4001001e</baseAddress>
      <registers>
        <register>
          <name>CSR</name>
          <addressOffset>0x0</addressOffset>
          <size>0x10</size>
          <fields>
            <field>
              <name>COMPxEN</name>
              <bitOffset>0</bitOffset>
              <bitWidth>1</bitWidth>
            </field>
            <field>
              <name>COMP1SW1</name>
              <bitOffset>1</bitOffset>
              <bitWidth>1</bitWidth>
            </field>
            <field>
              <name>COMPxMODE</name>
              <bitOffset>2</bitOffset>
              <bitWidth>2</bitWidth>
            </field>
            <field>
              <name>COMPxINSEL</name>
              <bitOffset>4</bitOffset>
              <bitWidth>3</bitWidth>
            </field>
            <field>
              <name>COMPxOUTSEL</name>
              <bitOffset>8</bitOffset>
              <bitWidth>3</bitWidth>
            </field>
            <field>
              <name>COMPxPOL</name>
              <bitOffset>11</bitOffset>
              <bitWidth>1</bitWidth>
            </field>
            <field>
              <name>COMPxHYST</name>
              <bitOffset>12</bitOffset>
              <bitWidth>2</bitWidth>
            </field>
            <field>
              <name>COMPxOUT</name>
              <bitOffset>14</bitOffset>
              <bitWidth>1</bitWidth>
            </field>
            <field>
              <name>COMPxLOCK</name>
              <bitOffset>15</bitOffset>
              <bitWidth>1</bitWidth>
            </field>
            <field>
              <name>COMP2EN</name>
              <bitOffset>16</bitOffset>
              <bitWidth>1</bitWidth>
            </field>
            <field>
              <name>COMP2MODE</name>
              <bitOffset>18</bitOffset>
              <bitWidth>2</bitWidth>
            </field>
            <field>
              <name>COMP2INSEL</name>
              <bitOffset>20</bitOffset>
              <bitWidth>3</bitWidth>
            </field>
            <field>
              <name>WNDWEN</name>
              <bitOffset>23</bitOffset>
              <bitWidth>1</bitWidth>
            </field>
            <field>
              <name>COMP2OUTSEL</name>
              <bitOffset>24</bitOffset>
              <bitWidth>3</bitWidth>
            </field>
            <field>
              <name>COMP2POL</name>
              <bitOffset>27</bitOffset>
              <bitWidth>1</bitWidth>
            </field>
            <field>
              <name>COMP2HYST</name>
              <bitOffset>28</bitOffset>
              <bitWidth>2</bitWidth>
            </field>
            <field>
              <name>COMP2OUT</name>
              <bitOffset>30</bitOffset>
              <bitWidth>1</bitWidth>
            </field>
            <field>
              <name>COMP2LOCK</name>
              <bitOffset>31</bitOffset>
              <bitWidth>1</bitWidth>
            </field>
          </fields>
        </register>
      </registers>
    </peripheral>
    <peripheral>
      <name>EXTI</name>
      <baseAddress>0x40010400</baseAddress>
      <registers>
        <register>
          <name>IMR</name>
          <addressOffset>0x0</addressOffset>
          <size>0x20</size>
          <fields>
            <field>
              <name>MR0</name>
              <bitOffset>0</bitOffset>
              <bitWidth>1</bitWidth>
            </field>
            <field>
              <name>MR1</name>
              <bitOffset>1</bitOffset>
              <bitWidth>1</bitWidth>
            </field>
            <field>
              <name>MR2</name>
              <bitOffset>2</bitOffset>
              <bitWidth>1</bitWidth>
            </field>
            <field>
              <name>MR3</name>
              <bitOffset>3</bitOffset>
              <bitWidth>1</bitWidth>
            </field>
            <field>
              <name>MR4</name>
              <bitOffset>4</bitOffset>
              <bitWidth>1</bitWidth>
            </field>
            <field>
              <name>MR5</name>
              <bitOffset>5</bitOffset>
              <bitWidth>1</bitWidth>
            </field>
            <field>
              <name>MR6</name>
              <bitOffset>6</bitOffset>
              <bitWidth>1</bitWidth>
            </field>
            <field>
              <name>MR7</name>
              <bitOffset>7</bitOffset>
              <bitWidth>1</bitWidth>
            </field>
            <field>
              <name>MR8</name>
              <bitOffset>8</bitOffset>
              <bitWidth>1</bitWidth>
            </field>
            <field>
              <name>MR9</name>
              <bitOffset>9</bitOffset>
              <bitWidth>1</bitWidth>
            </field>
            <field>
              <name>MR10</name>
              <bitOffset>10</bitOffset>
              <bitWidth>1</bitWidth>
            </field>
            <field>
              <name>MR11</name>
              <bitOffset>11</bitOffset>
              <bitWidth>1</bitWidth>
            </field>
            <field>
              <name>MR12</name>
              <bitOffset>12</bitOffset>
              <bitWidth>1</bitWidth>
            </field>
            <field>
              <name>MR13</name>
              <bitOffset>13</bitOffset>
              <bitWidth>1</bitWidth>
            </field>
            <field>
              <name>MR14</name>
              <bitOffset>14</bitOffset>
              <bitWidth>1</bitWidth>
            </field>
            <field>
              <name>MR15</name>
              <bitOffset>15</bitOffset>
              <bitWidth>1</bitWidth>
            </field>
            <field>
              <name>MR16</name>
              <bitOffset>16</bitOffset>
              <bitWidth>1</bitWidth>
            </field>
            <field>
              <name>MR17</name>
              <bitOffset>17</bitOffset>
              <bitWidth>1</bitWidth>
            </field>
            <field>
              <name>MR18</name>
              <bitOffset>18</bitOffset>
              <bitWidth>1</bitWidth>
            </field>
            <field>
              <name>MR19</name>
              <bitOffset>19</bitOffset>
              <bitWidth>1</bitWidth>
            </field>
            <field>
              <name>MR20</name>
              <bitOffset>20</bitOffset>
              <bitWidth>1</bitWidth>
            </field>
            <field>
              <name>MR21</name>
              <bitOffset>21</bitOffset>
              <bitWidth>1</bitWidth>
            </field>
            <field>
              <name>MR22</name>
              <bitOffset>22</bitOffset>
              <bitWidth>1</bitWidth>
            </field>
            <field>
              <name>MR23</name>
              <bitOffset>23</bitOffset>
              <bitWidth>1</bitWidth>
            </field>
            <field>
              <name>MR25</name>
              <bitOffset>25</bitOffset>
              <bitWidth>1</bitWidth>
            </field>
            <field>
              <name>MR26</name>
              <bitOffset>26</bitOffset>
              <bitWidth>1</bitWidth>
            </field>
            <field>
              <name>MR27</name>
              <bitOffset>27</bitOffset>
              <bitWidth>1</bitWidth>
            </field>
            <field>
              <name>MR31</name>
              <bitOffset>31</bitOffset>
              <bitWidth>1</bitWidth>
            </field>
          </fields>
        </register>
        <register>
          <name>EMR</name>
          <addressOffset>0x4</addressOffset>
          <size>0x20</size>
          <fields>
            <field>
              <name>MR0</name>
              <bitOffset>0</bitOffset>
              <bitWidth>1</bitWidth>
            </field>
            <field>
              <name>MR1</name>
              <bitOffset>1</bitOffset>
              <bitWidth>1</bitWidth>
            </field>
            <field>
              <name>MR2</name>
              <bitOffset>2</bitOffset>
              <bitWidth>1</bitWidth>
            </field>
            <field>
              <name>MR3</name>
              <bitOffset>3</bitOffset>
              <bitWidth>1</bitWidth>
            </field>
            <field>
              <name>MR4</name>
              <bitOffset>4</bitOffset>
              <bitWidth>1</bitWidth>
            </field>
            <field>
              <name>MR5</name>
              <bitOffset>5</bitOffset>
              <bitWidth>1</bitWidth>
            </field>
            <field>
              <name>MR6</name>
              <bitOffset>6</bitOffset>
              <bitWidth>1</bitWidth>
            </field>
            <field>
              <name>MR7</name>
              <bitOffset>7</bitOffset>
              <bitWidth>1</bitWidth>
            </field>
            <field>
              <name>MR8</name>
              <bitOffset>8</bitOffset>
              <bitWidth>1</bitWidth>
            </field>
            <field>
              <name>MR9</name>
              <bitOffset>9</bitOffset>
              <bitWidth>1</bitWidth>
            </field>
            <field>
              <name>MR10</name>
              <bitOffset>10</bitOffset>
              <bitWidth>1</bitWidth>
            </field>
            <field>
              <name>MR11</name>
              <bitOffset>11</bitOffset>
              <bitWidth>1</bitWidth>
            </field>
            <field>
              <name>MR12</name>
              <bitOffset>12</bitOffset>
              <bitWidth>1</bitWidth>
            </field>
            <field>
              <name>MR13</name>
              <bitOffset>13</bitOffset>
              <bitWidth>1</bitWidth>
            </field>
            <field>
              <name>MR14</name>
              <bitOffset>14</bitOffset>
              <bitWidth>1</bitWidth>
            </field>
            <field>
              <name>MR15</name>
              <bitOffset>15</bitOffset>
              <bitWidth>1</bitWidth>
            </field>
            <field>
              <name>MR16</name>
              <bitOffset>16</bitOffset>
              <bitWidth>1</bitWidth>
            </field>
            <field>
              <name>MR17</name>
              <bitOffset>17</bitOffset>
              <bitWidth>1</bitWidth>
            </field>
            <field>
              <name>MR18</name>
              <bitOffset>18</bitOffset>
              <bitWidth>1</bitWidth>
            </field>
            <field>
              <name>MR19</name>
              <bitOffset>19</bitOffset>
              <bitWidth>1</bitWidth>
            </field>
            <field>
              <name>MR20</name>
              <bitOffset>20</bitOffset>
              <bitWidth>1</bitWidth>
            </field>
            <field>
              <name>MR21</name>
              <bitOffset>21</bitOffset>
              <bitWidth>1</bitWidth>
            </field>
            <field>
              <name>MR22</name>
              <bitOffset>22</bitOffset>
              <bitWidth>1</bitWidth>
            </field>
            <field>
              <name>MR23</name>
              <bitOffset>23</bitOffset>
              <bitWidth>1</bitWidth>
            </field>
            <field>
              <name>MR25</name>
              <bitOffset>25</bitOffset>
              <bitWidth>1</bitWidth>
            </field>
            <field>
              <name>MR26</name>
              <bitOffset>26</bitOffset>
              <bitWidth>1</bitWidth>
            </field>
            <field>
              <name>MR27</name>
              <bitOffset>27</bitOffset>
              <bitWidth>1</bitWidth>
            </field>
            <field>
              <name>MR31</name>
              <bitOffset>31</bitOffset>
              <bitWidth>1</bitWidth>
            </field>
          </fields>
        </register>
        <register>
          <name>RTSR</name>
          <addressOffset>0x8</addressOffset>
          <size>0x20</size>
          <fields>
            <field>
              <name>TR0</name>
              <bitOffset>0</bitOffset>
              <bitWidth>1</bitWidth>
            </field>
            <field>
              <name>TR1</name>
              <bitOffset>1</bitOffset>
              <bitWidth>1</bitWidth>
            </field>
            <field>
              <name>TR2</name>
              <bitOffset>2</bitOffset>
              <bitWidth>1</bitWidth>
            </field>
            <field>
              <name>TR3</name>
              <bitOffset>3</bitOffset>
              <bitWidth>1</bitWidth>
            </field>
            <field>
              <name>TR4</name>
              <bitOffset>4</bitOffset>
              <bitWidth>1</bitWidth>
            </field>
            <field>
              <name>TR5</name>
              <bitOffset>5</bitOffset>
              <bitWidth>1</bitWidth>
            </field>
            <field>
              <name>TR6</name>
              <bitOffset>6</bitOffset>
              <bitWidth>1</bitWidth>
            </field>
            <field>
              <name>TR7</name>
              <bitOffset>7</bitOffset>
              <bitWidth>1</bitWidth>
            </field>
            <field>
              <name>TR8</name>
              <bitOffset>8</bitOffset>
              <bitWidth>1</bitWidth>
            </field>
            <field>
              <name>TR9</name>
              <bitOffset>9</bitOffset>
              <bitWidth>1</bitWidth>
            </field>
            <field>
              <name>TR10</name>
              <bitOffset>10</bitOffset>
              <bitWidth>1</bitWidth>
            </field>
            <field>
              <name>TR11</name>
              <bitOffset>11</bitOffset>
              <bitWidth>1</bitWidth>
            </field>
            <field>
              <name>TR12</name>
              <bitOffset>12</bitOffset>
              <bitWidth>1</bitWidth>
            </field>
            <field>
              <name>TR13</name>
              <bitOffset>13</bitOffset>
              <bitWidth>1</bitWidth>
            </field>
            <field>
              <name>TR14</name>
              <bitOffset>14</bitOffset>
              <bitWidth>1</bitWidth>
            </field>
            <field>
              <name>TR15</name>
              <bitOffset>15</bitOffset>
              <bitWidth>1</bitWidth>
            </field>
            <field>
              <name>TR16</name>
              <bitOffset>16</bitOffset>
              <bitWidth>1</bitWidth>
            </field>
            <field>
              <name>TR17</name>
              <bitOffset>17</bitOffset>
              <bitWidth>1</bitWidth>
            </field>
            <field>
              <name>TR19</name>
              <bitOffset>19</bitOffset>
              <bitWidth>1</bitWidth>
            </field>
            <field>
              <name>TR20</name>
              <bitOffset>20</bitOffset>
              <bitWidth>1</bitWidth>
            </field>
            <field>
              <name>TR21</name>
              <bitOffset>21</bitOffset>
              <bitWidth>1</bitWidth>
            </field>
            <field>
              <name>TR22</name>
              <bitOffset>22</bitOffset>
              <bitWidth>1</bitWidth>
            </field>
            <field>
              <name>TR31</name>
              <bitOffset>31</bitOffset>
              <bitWidth>1</bitWidth>
            </field>
          </fields>
        </register>
        <register>
          <name>FTSR</name>
          <addressOffset>0xc</addressOffset>
          <size>0x20</size>
          <fields>
            <field>
              <name>TR0</name>
              <bitOffset>0</bitOffset>
              <bitWidth>1</bitWidth>
            </field>
            <field>
              <name>TR1</name>
              <bitOffset>1</bitOffset>
              <bitWidth>1</bitWidth>
            </field>
            <field>
              <name>TR2</name>
              <bitOffset>2</bitOffset>
              <bitWidth>1</bitWidth>
            </field>
            <field>
              <name>TR3</name>
              <bitOffset>3</bitOffset>
              <bitWidth>1</bitWidth>
            </field>
            <field>
              <name>TR4</name>
              <bitOffset>4</bitOffset>
              <bitWidth>1</bitWidth>
            </field>
            <field>
              <name>TR5</name>
              <bitOffset>5</bitOffset>
              <bitWidth>1</bitWidth>
            </field>
            <field>
              <name>TR6</name>
              <bitOffset>6</bitOffset>
              <bitWidth>1</bitWidth>
            </field>
            <field>
              <name>TR7</name>
              <bitOffset>7</bitOffset>
              <bitWidth>1</bitWidth>
            </field>
            <field>
              <name>TR8</name>
              <bitOffset>8</bitOffset>
              <bitWidth>1</bitWidth>
            </field>
            <field>
              <name>TR9</name>
              <bitOffset>9</bitOffset>
              <bitWidth>1</bitWidth>
            </field>
            <field>
              <name>TR10</name>
              <bitOffset>10</bitOffset>
              <bitWidth>1</bitWidth>
            </field>
            <field>
              <name>TR11</name>
              <bitOffset>11</bitOffset>
              <bitWidth>1</bitWidth>
            </field>
            <field>
              <name>TR12</name>
              <bitOffset>12</bitOffset>
              <bitWidth>1</bitWidth>
            </field>
            <field>
              <name>TR13</name>
              <bitOffset>13</bitOffset>
              <bitWidth>1</bitWidth>
            </field>
            <field>
              <name>TR14</name>
              <bitOffset>14</bitOffset>
              <bitWidth>1</bitWidth>
            </field>
            <field>
              <name>TR15</name>
              <bitOffset>15</bitOffset>
              <bitWidth>1</bitWidth>
            </field>
            <field>
              <name>TR16</name>
              <bitOffset>16</bitOffset>
              <bitWidth>1</bitWidth>
            </field>
            <field>
              <name>TR17</name>
              <bitOffset>17</bitOffset>
              <bitWidth>1</bitWidth>
            </field>
            <field>
              <name>TR19</name>
              <bitOffset>19</bitOffset>
              <bitWidth>1</bitWidth>
            </field>
            <field>
              <name>TR20</name>
              <bitOffset>20</bitOffset>
              <bitWidth>1</bitWidth>
            </field>
            <field>
              <name>TR21</name>
              <bitOffset>21</bitOffset>
              <bitWidth>1</bitWidth>
            </field>
            <field>
              <name>TR22</name>
              <bitOffset>22</bitOffset>
              <bitWidth>1</bitWidth>
            </field>
            <field>
              <name>TR31</name>
              <bitOffset>31</bitOffset>
              <bitWidth>1</bitWidth>
            </field>
          </fields>
        </register>
        <register>
          <name>SWIER</name>
          <addressOffset>0x10</addressOffset>
          <size>0x20</size>
          <fields>
            <field>
              <name>SWIER0</name>
              <bitOffset>0</bitOffset>
              <bitWidth>1</bitWidth>
            </field>
            <field>
              <name>SWIER1</name>
              <bitOffset>1</bitOffset>
              <bitWidth>1</bitWidth>
            </field>
            <field>
              <name>SWIER2</name>
              <bitOffset>2</bitOffset>
              <bitWidth>1</bitWidth>
            </field>
            <field>
              <name>SWIER3</name>
              <bitOffset>3</bitOffset>
              <bitWidth>1</bitWidth>
            </field>
            <field>
              <name>SWIER4</name>
              <bitOffset>4</bitOffset>
              <bitWidth>1</bitWidth>
            </field>
            <field>
              <name>SWIER5</name>
              <bitOffset>5</bitOffset>
              <bitWidth>1</bitWidth>
            </field>
            <field>
              <name>SWIER6</name>
              <bitOffset>6</bitOffset>
              <bitWidth>1</bitWidth>
            </field>
            <field>
              <name>SWIER7</name>
              <bitOffset>7</bitOffset>
              <bitWidth>1</bitWidth>
            </field>
            <field>
              <name>SWIER8</name>
              <bitOffset>8</bitOffset>
              <bitWidth>1</bitWidth>
            </field>
            <field>
              <name>SWIER9</name>
              <bitOffset>9</bitOffset>
              <bitWidth>1</bitWidth>
            </field>
            <field>
              <name>SWIER10</name>
              <bitOffset>10</bitOffset>
              <bitWidth>1</bitWidth>
            </field>
            <field>
              <name>SWIER11</name>
              <bitOffset>11</bitOffset>
              <bitWidth>1</bitWidth>
            </field>
            <field>
              <name>SWIER12</name>
              <bitOffset>12</bitOffset>
              <bitWidth>1</bitWidth>
            </field>
            <field>
              <name>SWIER13</name>
              <bitOffset>13</bitOffset>
              <bitWidth>1</bitWidth>
            </field>
            <field>
              <name>SWIER14</name>
              <bitOffset>14</bitOffset>
              <bitWidth>1</bitWidth>
            </field>
            <field>
              <name>SWIER15</name>
              <bitOffset>15</bitOffset>
              <bitWidth>1</bitWidth>
            </field>
            <field>
              <name>SWIER16</name>
              <bitOffset>16</bitOffset>
              <bitWidth>1</bitWidth>
            </field>
            <field>
              <name>SWIER17</name>
              <bitOffset>17</bitOffset>
              <bitWidth>1</bitWidth>
            </field>
            <field>
              <name>SWIER19</name>
              <bitOffset>19</bitOffset>
              <bitWidth>1</bitWidth>
            </field>
            <field>
              <name>SWIER20</name>
              <bitOffset>20</bitOffset>
              <bitWidth>1</bitWidth>
            </field>
            <field>
              <name>SWIER21</name>
              <bitOffset>21</bitOffset>
              <bitWidth>1</bitWidth>
            </field>
            <field>
              <name>SWIER22</name>
              <bitOffset>22</bitOffset>
              <bitWidth>1</bitWidth>
            </field>
            <field>
              <name>SWIER31</name>
              <bitOffset>31</bitOffset>
              <bitWidth>1</bitWidth>
            </field>
          </fields>
        </register>
        <register>
          <name>PR</name>
          <addressOffset>0x14</addressOffset>
          <size>0x20</size>
          <fields>
            <field>
              <name>PR0</name>
              <bitOffset>0</bitOffset>
              <bitWidth>1</bitWidth>
            </field>
            <field>
              <name>PR1</name>
              <bitOffset>1</bitOffset>
              <bitWidth>1</bitWidth>
            </field>
            <field>
              <name>PR2</name>
              <bitOffset>2</bitOffset>
              <bitWidth>1</bitWidth>
            </field>
            <field>
              <name>PR3</name>
              <bitOffset>3</bitOffset>
              <bitWidth>1</bitWidth>
            </field>
            <field>
              <name>PR4</name>
              <bitOffset>4</bitOffset>
              <bitWidth>1</bitWidth>
            </field>
            <field>
              <name>PR5</name>
              <bitOffset>5</bitOffset>
              <bitWidth>1</bitWidth>
            </field>
            <field>
              <name>PR6</name>
              <bitOffset>6</bitOffset>
              <bitWidth>1</bitWidth>
            </field>
            <field>
              <name>PR7</name>
              <bitOffset>7</bitOffset>
              <bitWidth>1</bitWidth>
            </field>
            <field>
              <name>PR8</name>
              <bitOffset>8</bitOffset>
              <bitWidth>1</bitWidth>
            </field>
            <field>
              <name>PR9</name>
              <bitOffset>9</bitOffset>
              <bitWidth>1</bitWidth>
            </field>
            <field>
              <name>PR10</name>
              <bitOffset>10</bitOffset>
              <bitWidth>1</bitWidth>
            </field>
            <field>
              <name>PR11</name>
              <bitOffset>11</bitOffset>
              <bitWidth>1</bitWidth>
            </field>
            <field>
              <name>PR12</name>
              <bitOffset>12</bitOffset>
              <bitWidth>1</bitWidth>
            </field>
            <field>
              <name>PR13</name>
              <bitOffset>13</bitOffset>
              <bitWidth>1</bitWidth>
            </field>
            <field>
              <name>PR14</name>
              <bitOffset>14</bitOffset>
              <bitWidth>1</bitWidth>
            </field>
            <field>
              <name>PR15</name>
              <bitOffset>15</bitOffset>
              <bitWidth>1</bitWidth>
            </field>
            <field>
              <name>PR16</name>
              <bitOffset>16</bitOffset>
              <bitWidth>1</bitWidth>
            </field>
            <field>
              <name>PR17</name>
              <bitOffset>17</bitOffset>
              <bitWidth>1</bitWidth>
            </field>
            <field>
              <name>PR19</name>
              <bitOffset>19</bitOffset>
              <bitWidth>1</bitWidth>
            </field>
            <field>
              <name>PR20</name>
              <bitOffset>20</bitOffset>
              <bitWidth>1</bitWidth>
            </field>
            <field>
              <name>PR21</name>
              <bitOffset>21</bitOffset>
              <bitWidth>1</bitWidth>
            </field>
            <field>
              <name>PR22</name>
              <bitOffset>22</bitOffset>
              <bitWidth>1</bitWidth>
            </field>
            <field>
              <name>PR31</name>
              <bitOffset>31</bitOffset>
              <bitWidth>1</bitWidth>
            </field>
          </fields>
        </register>
      </registers>
    </peripheral>
    <peripheral>
      <name>ADC1</name>
      <baseAddress>0x40012400</baseAddress>
      <registers>
        <register>
          <name>ISR</name>
          <addressOffset>0x0</addressOffset>
          <size>0x20</size>
          <fields>
            <field>
              <name>ADRDY</name>
              <bitOffset>0</bitOffset>
              <bitWidth>1</bitWidth>
            </field>
            <field>
              <name>EOSMP</name>
              <bitOffset>1</bitOffset>
              <bitWidth>1</bitWidth>
            </field>
            <field>
              <name>EOC</name>
              <bitOffset>2</bitOffset>
              <bitWidth>1</bitWidth>
            </field>
            <field>
              <name>EOS</name>
              <bitOffset>3</bitOffset>
              <bitWidth>1</bitWidth>
            </field>
            <field>
              <name>OVR</name>
              <bitOffset>4</bitOffset>
              <bitWidth>1</bitWidth>
            </field>
            <field>
              <name>AWD1</name>
              <bitOffset>7</bitOffset>
              <bitWidth>1</bitWidth>
            </field>
          </fields>
        </register>
        <register>
          <name>IER</name>
          <addressOffset>0x4</addressOffset>
          <size>0x20</size>
          <fields>
            <field>
              <name>ADRDYIE</name>
              <bitOffset>0</bitOffset>
              <bitWidth>1</bitWidth>
            </field>
            <field>
              <name>EOSMPIE</name>
              <bitOffset>1</bitOffset>
              <bitWidth>1</bitWidth>
            </field>
            <field>
              <name>EOCIE</name>
              <bitOffset>2</bitOffset>
              <bitWidth>1</bitWidth>
            </field>
            <field>
              <name>EOSIE</name>
              <bitOffset>3</bitOffset>
              <bitWidth>1</bitWidth>
            </field>
            <field>
              <name>OVRIE</name>
              <bitOffset>4</bitOffset>
              <bitWidth>1</bitWidth>
            </field>
            <field>
              <name>AWD1IE</name>
              <bitOffset>7</bitOffset>
              <bitWidth>1</bitWidth>
            </field>
          </fields>
        </register>
        <register>
          <name>CR</name>
          <addressOffset>0x8</addressOffset>
          <size>0x20</size>
          <fields>
            <field>
              <name>ADEN</name>
              <bitOffset>0</bitOffset>
              <bitWidth>1</bitWidth>
            </field>
            <field>
              <name>ADDIS</name>
              <bitOffset>1</bitOffset>
              <bitWidth>1</bitWidth>
            </field>
            <field>
              <name>ADSTART</name>
              <bitOffset>2</bitOffset>
              <bitWidth>1</bitWidth>
            </field>
            <field>
              <name>ADSTP</name>
              <bitOffset>4</bitOffset>
              <bitWidth>1</bitWidth>
            </field>
            <field>
              <name>ADCAL</name>
              <bitOffset>31</bitOffset>
              <bitWidth>1</bitWidth>
            </field>
          </fields>
        </register>
        <register>
          <name>CFGR1</name>
          <addressOffset>0xc</addressOffset>
          <size>0x20</size>
          <fields>
            <field>
              <name>DMAEN</name>
              <bitOffset>0</bitOffset>
              <bitWidth>1</bitWidth>
            </field>
            <field>
              <name>DMACFG</name>
              <bitOffset>1</bitOffset>
              <bitWidth>1</bitWidth>
            </field>
            <field>
              <name>SCANDIR</name>
              <bitOffset>2</bitOffset>
              <bitWidth>1</bitWidth>
            </field>
            <field>
              <name>RES</name>
              <bitOffset>3</bitOffset>
              <bitWidth>2</bitWidth>
            </field>
            <field>
              <name>ALIGN</name>
              <bitOffset>5</bitOffset>
              <bitWidth>1</bitWidth>
            </field>
            <field>
              <name>EXTSEL</name>
              <bitOffset>6</bitOffset>
              <bitWidth>3</bitWidth>
            </field>
            <field>
              <name>EXTEN</name>
              <bitOffset>10</bitOffset>
              <bitWidth>2</bitWidth>
            </field>
            <field>
              <name>OVRMOD</name>
              <bitOffset>12</bitOffset>
              <bitWidth>1</bitWidth>
            </field>
            <field>
              <name>CONT</name>
              <bitOffset>13</bitOffset>
              <bitWidth>1</bitWidth>
            </field>
            <field>
              <name>WAIT</name>
              <bitOffset>14</bitOffset>
              <bitWidth>1</bitWidth>
            </field>
            <field>
              <name>AUTOFF</name>
              <bitOffset>15</bitOffset>
              <bitWidth>1</bitWidth>
            </field>
            <field>
              <name>DISCEN</name>
              <bitOffset>16</bitOffset>
              <bitWidth>1</bitWidth>
            </field>
            <field>
              <name>AWD1SGL</name>
              <bitOffset>22</bitOffset>
              <bitWidth>1</bitWidth>
            </field>
            <field>
              <name>AWD1EN</name>
              <bitOffset>23</bitOffset>
              <bitWidth>1</bitWidth>
            </field>
            <field>
              <name>AWD1CH</name>
              <bitOffset>26</bitOffset>
              <bitWidth>5</bitWidth>
            </field>
          </fields>
        </register>
        <register>
          <name>CFGR2</name>
          <addressOffset>0x10</addressOffset>
          <size>0x20</size>
          <fields>
            <field>
              <name>CKMODE</name>
              <bitOffset>30</bitOffset>
              <bitWidth>2</bitWidth>
            </field>
          </fields>
        </register>
        <register>
          <name>SMPR</name>
          <addressOffset>0x14</addressOffset>
          <size>0x20</size>
          <fields>
            <field>
              <name>SMP</name>
              <bitOffset>0</bitOffset>
              <bitWidth>3</bitWidth>
            </field>
          </fields>
        </register>
        <register>
          <name>TR</name>
          <addressOffset>0x20</addressOffset>
          <size>0x20</size>
          <fields>
            <field>
              <name>LT1</name>
              <bitOffset>0</bitOffset>
              <bitWidth>12</bitWidth>
            </field>
            <field>
              <name>HT1</name>
              <bitOffset>16</bitOffset>
              <bitWidth>12</bitWidth>
            </field>
          </fields>
        </register>
        <register>
          <name>CHSELR</name>
          <addressOffset>0x28</addressOffset>
          <size>0x20</size>
          <fields>
            <field>
              <name>CHSEL0</name>
              <bitOffset>0</bitOffset>
              <bitWidth>1</bitWidth>
            </field>
            <field>
              <name>CHSEL1</name>
              <bitOffset>1</bitOffset>
              <bitWidth>1</bitWidth>
            </field>
            <field>
              <name>CHSEL2</name>
              <bitOffset>2</bitOffset>
              <bitWidth>1</bitWidth>
            </field>
            <field>
              <name>CHSEL3</name>
              <bitOffset>3</bitOffset>
              <bitWidth>1</bitWidth>
            </field>
            <field>
              <name>CHSEL4</name>
              <bitOffset>4</bitOffset>
              <bitWidth>1</bitWidth>
            </field>
            <field>
              <name>CHSEL5</name>
              <bitOffset>5</bitOffset>
              <bitWidth>1</bitWidth>
            </field>
            <field>
              <name>CHSEL6</name>
              <bitOffset>6</bitOffset>
              <bitWidth>1</bitWidth>
            </field>
            <field>
              <name>CHSEL7</name>
              <bitOffset>7</bitOffset>
              <bitWidth>1</bitWidth>
            </field>
            <field>
              <name>CHSEL8</name>
              <bitOffset>8</bitOffset>
              <bitWidth>1</bitWidth>
            </field>
            <field>
              <name>CHSEL9</name>
              <bitOffset>9</bitOffset>
              <bitWidth>1</bitWidth>
            </field>
            <field>
              <name>CHSEL10</name>
              <bitOffset>10</bitOffset>
              <bitWidth>1</bitWidth>
            </field>
            <field>
              <name>CHSEL11</name>
              <bitOffset>11</bitOffset>
              <bitWidth>1</bitWidth>
            </field>
            <field>
              <name>CHSEL12</name>
              <bitOffset>12</bitOffset>
              <bitWidth>1</bitWidth>
            </field>
            <field>
              <name>CHSEL13</name>
              <bitOffset>13</bitOffset>
              <bitWidth>1</bitWidth>
            </field>
            <field>
              <name>CHSEL14</name>
              <bitOffset>14</bitOffset>
              <bitWidth>1</bitWidth>
            </field>
            <field>
              <name>CHSEL15</name>
              <bitOffset>15</bitOffset>
              <bitWidth>1</bitWidth>
            </field>
            <field>
              <name>CHSEL16</name>
              <bitOffset>16</bitOffset>
              <bitWidth>1</bitWidth>
            </field>
            <field>
              <name>CHSEL17</name>
              <bitOffset>17</bitOffset>
              <bitWidth>1</bitWidth>
            </field>
            <field>
              <name>CHSEL18</name>
              <bitOffset>18</bitOffset>
              <bitWidth>1</bitWidth>
            </field>
          </fields>
        </register>
        <register>
          <name>DR</name>
          <addressOffset>0x40</addressOffset>
          <size>0x20</size>
          <fields>
            <field>
              <name>DATA</name>
              <bitOffset>0</bitOffset>
              <bitWidth>16</bitWidth>
            </field>
          </fields>
        </register>
        <register>
          <name>CCR</name>
          <addressOffset>0x308</addressOffset>
          <size>0x20</size>
          <fields>
            <field>
              <name>VREFEN</name>
              <bitOffset>22</bitOffset>
              <bitWidth>1</bitWidth>
            </field>
            <field>
              <name>TSEN</name>
              <bitOffset>23</bitOffset>
              <bitWidth>1</bitWidth>
            </field>
            <field>
              <name>VBATEN</name>
              <bitOffset>24</bitOffset>
              <bitWidth>1</bitWidth>
            </field>
          </fields>
        </register>
      </registers>
    </peripheral>
    <peripheral>
      <name>TIM1</name>
      <baseAddress>0x40012c00</baseAddress>
      <registers>
        <register>
          <name>CR1</name>
          <addressOffset>0x0</addressOffset>
          <size>0x20</size>
          <fields>
            <field>
              <name>CEN</name>
              <bitOffset>0</bitOffset>
              <bitWidth>1</bitWidth>
            </field>
            <field>
              <name>UDIS</name>
              <bitOffset>1</bitOffset>
              <bitWidth>1</bitWidth>
            </field>
            <field>
              <name>URS</name>
              <bitOffset>2</bitOffset>
              <bitWidth>1</bitWidth>
            </field>
            <field>
              <name>OPM</name>
              <bitOffset>3</bitOffset>
              <bitWidth>1</bitWidth>
            </field>
            <field>
              <name>DIR</name>
              <bitOffset>4</bitOffset>
              <bitWidth>1</bitWidth>
            </field>
            <field>
              <name>CMS</name>
              <bitOffset>5</bitOffset>
              <bitWidth>2</bitWidth>
            </field>
            <field>
              <name>ARPE</name>
              <bitOffset>7</bitOffset>
              <bitWidth>1</bitWidth>
            </field>
            <field>
              <name>CKD</name>
              <bitOffset>8</bitOffset>
              <bitWidth>2</bitWidth>
            </field>
          </fields>
        </register>
        <register>
          <name>CR2</name>
          <addressOffset>0x4</addressOffset>
          <size>0x20</size>
          <fields>
            <field>
              <name>CCPC</name>
              <bitOffset>0</bitOffset>
              <bitWidth>1</bitWidth>
            </field>
            <field>
              <name>CCUS</name>
              <bitOffset>2</bitOffset>
              <bitWidth>1</bitWidth>
            </field>
            <field>
              <name>CCDS</name>
              <bitOffset>3</bitOffset>
              <bitWidth>1</bitWidth>
            </field>
            <field>
              <name>MMS</name>
              <bitOffset>4</bitOffset>
              <bitWidth>3</bitWidth>
            </field>
            <field>
              <name>TI1S</name>
              <bitOffset>7</bitOffset>
              <bitWidth>1</bitWidth>
            </field>
            <field>
              <name>OIS1</name>
              <bitOffset>8</bitOffset>
              <bitWidth>1</bitWidth>
            </field>
            <field>
              <name>OIS1N</name>
              <bitOffset>9</bitOffset>
              <bitWidth>1</bitWidth>
            </field>
            <field>
              <name>OIS2</name>
              <bitOffset>10</bitOffset>
              <bitWidth>1</bitWidth>
            </field>
            <field>
              <name>OIS2N</name>
              <bitOffset>11</bitOffset>
              <bitWidth>1</bitWidth>
            </field>
            <field>
              <name>OIS3</name>
              <bitOffset>12</bitOffset>
              <bitWidth>1</bitWidth>
            </field>
            <field>
              <name>OIS3N</name>
              <bitOffset>13</bitOffset>
              <bitWidth>1</bitWidth>
            </field>
            <field>
              <name>OIS4</name>
              <bitOffset>14</bitOffset>
              <bitWidth>1</bitWidth>
            </field>
          </fields>
        </register>
        <register>
          <name>SMCR</name>
          <addressOffset>0x8</addressOffset>
          <size>0x20</size>
          <fields>
            <field>
              <name>SMS</name>
              <bitOffset>0</bitOffset>
              <bitWidth>3</bitWidth>
            </field>
            <field>
              <name>OCCS</name>
              <bitOffset>3</bitOffset>
              <bitWidth>1</bitWidth>
            </field>
            <field>
              <name>TS</name>
              <bitOffset>4</bitOffset>
              <bitWidth>3</bitWidth>
            </field>
            <field>
              <name>MSM</name>
              <bitOffset>7</bitOffset>
              <bitWidth>1</bitWidth>
            </field>
            <field>
              <name>ETF</name>
              <bitOffset>8</bitOffset>
              <bitWidth>4</bitWidth>
            </field>
            <field>
              <name>ETPS</name>
              <bitOffset>12</bitOffset>
              <bitWidth>2</bitWidth>
            </field>
            <field>
              <name>ECE</name>
              <bitOffset>14</bitOffset>
              <bitWidth>1</bitWidth>
            </field>
            <field>
              <name>ETP</name>
              <bitOffset>15</bitOffset>
              <bitWidth>1</bitWidth>
            </field>
          </fields>
        </register>
        <register>
          <name>DIER</name>
          <addressOffset>0xc</addressOffset>
          <size>0x20</size>
          <fields>
            <field>
              <name>UIE</name>
              <bitOffset>0</bitOffset>
              <bitWidth>1</bitWidth>
            </field>
            <field>
              <name>CC1IE</name>
              <bitOffset>1</bitOffset>
              <bitWidth>1</bitWidth>
            </field>
            <field>
              <name>CC2IE</name>
              <bitOffset>2</bitOffset>
              <bitWidth>1</bitWidth>
            </field>
            <field>
              <name>CC3IE</name>
              <bitOffset>3</bitOffset>
              <bitWidth>1</bitWidth>
            </field>
            <field>
              <name>CC4IE</name>
              <bitOffset>4</bitOffset>
              <bitWidth>1</bitWidth>
            </field>
            <field>
              <name>COMIE</name>
              <bitOffset>5</bitOffset>
              <bitWidth>1</bitWidth>
            </field>
            <field>
              <name>TIE</name>
              <bitOffset>6</bitOffset>
              <bitWidth>1</bitWidth>
            </field>
            <field>
              <name>BIE</name>
              <bitOffset>7</bitOffset>
              <bitWidth>1</bitWidth>
            </field>
            <field>
              <name>UDE</name>
              <bitOffset>8</bitOffset>
              <bitWidth>1</bitWidth>
            </field>
            <field>
              <name>CC1DE</name>
              <bitOffset>9</bitOffset>
              <bitWidth>1</bitWidth>
            </field>
            <field>
              <name>CC2DE</name>
              <bitOffset>10</bitOffset>
              <bitWidth>1</bitWidth>
            </field>
            <field>
              <name>CC3DE</name>
              <bitOffset>11</bitOffset>
              <bitWidth>1</bitWidth>
            </field>
            <field>
              <name>CC4DE</name>
              <bitOffset>12</bitOffset>
              <bitWidth>1</bitWidth>
            </field>
            <field>
              <name>COMDE</name>
              <bitOffset>13</bitOffset>
              <bitWidth>1</bitWidth>
            </field>
            <field>
              <name>TDE</name>
              <bitOffset>14</bitOffset>
              <bitWidth>1</bitWidth>
            </field>
          </fields>
        </register>
        <register>
          <name>SR</name>
          <addressOffset>0x10</addressOffset>
          <size>0x20</size>
          <fields>
            <field>
              <name>UIF</name>
              <bitOffset>0</bitOffset>
              <bitWidth>1</bitWidth>
            </field>
            <field>
              <name>CC1IF</name>
              <bitOffset>1</bitOffset>
              <bitWidth>1</bitWidth>
            </field>
            <field>
              <name>CC2IF</name>
              <bitOffset>2</bitOffset>
              <bitWidth>1</bitWidth>
            </field>
            <field>
              <name>CC3IF</name>
              <bitOffset>3</bitOffset>
              <bitWidth>1</bitWidth>
            </field>
            <field>
              <name>CC4IF</name>
              <bitOffset>4</bitOffset>
              <bitWidth>1</bitWidth>
            </field>
            <field>
              <name>COMIF</name>
              <bitOffset>5</bitOffset>
              <bitWidth>1</bitWidth>
            </field>
            <field>
              <name>TIF</name>
              <bitOffset>6</bitOffset>
              <bitWidth>1</bitWidth>
            </field>
            <field>
              <name>BIF</name>
              <bitOffset>7</bitOffset>
              <bitWidth>1</bitWidth>
            </field>
            <field>
              <name>CC1OF</name>
              <bitOffset>9</bitOffset>
              <bitWidth>1</bitWidth>
            </field>
            <field>
              <name>CC2OF</name>
              <bitOffset>10</bitOffset>
              <bitWidth>1</bitWidth>
            </field>
            <field>
              <name>CC3OF</name>
              <bitOffset>11</bitOffset>
              <bitWidth>1</bitWidth>
            </field>
            <field>
              <name>CC4OF</name>
              <bitOffset>12</bitOffset>
              <bitWidth>1</bitWidth>
            </field>
          </fields>
        </register>
        <register>
          <name>EGR</name>
          <addressOffset>0x14</addressOffset>
          <size>0x20</size>
          <fields>
            <field>
              <name>UG</name>
              <bitOffset>0</bitOffset>
              <bitWidth>1</bitWidth>
            </field>
            <field>
              <name>CC1G</name>
              <bitOffset>1</bitOffset>
              <bitWidth>1</bitWidth>
            </field>
            <field>
              <name>CC2G</name>
              <bitOffset>2</bitOffset>
              <bitWidth>1</bitWidth>
            </field>
            <field>
              <name>CC3G</name>
              <bitOffset>3</bitOffset>
              <bitWidth>1</bitWidth>
            </field>
            <field>
              <name>CC4G</name>
              <bitOffset>4</bitOffset>
              <bitWidth>1</bitWidth>
            </field>
            <field>
              <name>COMG</name>
              <bitOffset>5</bitOffset>
              <bitWidth>1</bitWidth>
            </field>
            <field>
              <name>TG</name>
              <bitOffset>6</bitOffset>
              <bitWidth>1</bitWidth>
            </field>
            <field>
              <name>BG</name>
              <bitOffset>7</bitOffset>
              <bitWidth>1</bitWidth>
            </field>
          </fields>
        </register>
        <register>
          <name>CCMR1</name>
          <addressOffset>0x18</addressOffset>
          <size>0x20</size>
          <fields>
            <field>
              <name>CC1S</name>
              <bitOffset>0</bitOffset>
              <bitWidth>2</bitWidth>
            </field>
            <field>
              <name>OC1FE</name>
              <bitOffset>2</bitOffset>
              <bitWidth>1</bitWidth>
            </field>
            <field>
              <name>OC1PE</name>
              <bitOffset>3</bitOffset>
              <bitWidth>1</bitWidth>
            </field>
            <field>
              <name>OC1M</name>
              <bitOffset>4</bitOffset>
              <bitWidth>3</bitWidth>
            </field>
            <field>
              <name>OC1CE</name>
              <bitOffset>7</bitOffset>
              <bitWidth>1</bitWidth>
            </field>
            <field>
              <name>CC2S</name>
              <bitOffset>8</bitOffset>
              <bitWidth>2</bitWidth>
            </field>
            <field>
              <name>OC2FE</name>
              <bitOffset>10</bitOffset>
              <bitWidth>1</bitWidth>
            </field>
            <field>
              <name>OC2PE</name>
              <bitOffset>11</bitOffset>
              <bitWidth>1</bitWidth>
            </field>
            <field>
              <name>OC2M</name>
              <bitOffset>12</bitOffset>
              <bitWidth>3</bitWidth>
            </field>
            <field>
              <name>OC2CE</name>
              <bitOffset>15</bitOffset>
              <bitWidth>1</bitWidth>
            </field>
          </fields>
        </register>
        <register>
          <name>CCMR2</name>
          <addressOffset>0x1c</addressOffset>
          <size>0x20</size>
          <fields>
            <field>
              <name>CC3S</name>
              <bitOffset>0</bitOffset>
              <bitWidth>2</bitWidth>
            </field>
            <field>
              <name>OC3FE</name>
              <bitOffset>2</bitOffset>
              <bitWidth>1</bitWidth>
            </field>
            <field>
              <name>OC3PE</name>
              <bitOffset>3</bitOffset>
              <bitWidth>1</bitWidth>
            </field>
            <field>
              <name>OC3M</name>
              <bitOffset>4</bitOffset>
              <bitWidth>3</bitWidth>
            </field>
            <field>
              <name>OC3CE</name>
              <bitOffset>7</bitOffset>
              <bitWidth>1</bitWidth>
            </field>
            <field>
              <name>CC4S</name>
              <bitOffset>8</bitOffset>
              <bitWidth>2</bitWidth>
            </field>
            <field>
              <name>OC4FE</name>
              <bitOffset>10</bitOffset>
              <bitWidth>1</bitWidth>
            </field>
            <field>
              <name>OC4PE</name>
              <bitOffset>11</bitOffset>
              <bitWidth>1</bitWidth>
            </field>
            <field>
              <name>OC4M</name>
              <bitOffset>12</bitOffset>
              <bitWidth>3</bitWidth>
            </field>
            <field>
              <name>OC4CE</name>
              <bitOffset>15</bitOffset>
              <bitWidth>1</bitWidth>
            </field>
          </fields>
        </register>
        <register>
          <name>CCER</name>
          <addressOffset>0x20</addressOffset>
          <size>0x20</size>
          <fields>
            <field>
              <name>CC1E</name>
              <bitOffset>0</bitOffset>
              <bitWidth>1</bitWidth>
            </field>
            <field>
              <name>CC1P</name>
              <bitOffset>1</bitOffset>
              <bitWidth>1</bitWidth>
            </field>
            <field>
              <name>CC1NE</name>
              <bitOffset>2</bitOffset>
              <bitWidth>1</bitWidth>
            </field>
            <field>
              <name>CC1NP</name>
              <bitOffset>3</bitOffset>
              <bitWidth>1</bitWidth>
            </field>
            <field>
              <name>CC2E</name>
              <bitOffset>4</bitOffset>
              <bitWidth>1</bitWidth>
            </field>
            <field>
              <name>CC2P</name>
              <bitOffset>5</bitOffset>
              <bitWidth>1</bitWidth>
            </field>
            <field>
              <name>CC2NE</name>
              <bitOffset>6</bitOffset>
              <bitWidth>1</bitWidth>
            </field>
            <field>
              <name>CC2NP</name>
              <bitOffset>7</bitOffset>
              <bitWidth>1</bitWidth>
            </field>
            <field>
              <name>CC3E</name>
              <bitOffset>8</bitOffset>
              <bitWidth>1</bitWidth>
            </field>
            <field>
              <name>CC3P</name>
              <bitOffset>9</bitOffset>
              <bitWidth>1</bitWidth>
            </field>
            <field>
              <name>CC3NE</name>
              <bitOffset>10</bitOffset>
              <bitWidth>1</bitWidth>
            </field>
            <field>
              <name>CC3NP</name>
              <bitOffset>11</bitOffset>
              <bitWidth>1</bitWidth>
            </field>
            <field>
              <name>CC4E</name>
              <bitOffset>12</bitOffset>
              <bitWidth>1</bitWidth>
            </field>
            <field>
              <name>CC4P</name>
              <bitOffset>13</bitOffset>
              <bitWidth>1</bitWidth>
            </field>
            <field>
              <name>CC4NP</name>
              <bitOffset>15</bitOffset>
              <bitWidth>1</bitWidth>
            </field>
          </fields>
        </register>
        <register>
          <name>CNT</name>
          <addressOffset>0x24</addressOffset>
          <size>0x20</size>
          <fields>
            <field>
              <name>CNT</name>
              <bitOffset>0</bitOffset>
              <bitWidth>32</bitWidth>
            </field>
          </fields>
        </register>
        <register>
          <name>PSC</name>
          <addressOffset>0x28</addressOffset>
          <size>0x20</size>
          <fields>
            <field>
              <name>PSC</name>
              <bitOffset>0</bitOffset>
              <bitWidth>16</bitWidth>
            </field>
          </fields>
        </register>
        <register>
          <name>ARR</name>
          <addressOffset>0x2c</addressOffset>
          <size>0x20</size>
          <fields>
            <field>
              <name>ARR</name>
              <bitOffset>0</bitOffset>
              <bitWidth>32</bitWidth>
            </field>
          </fields>
        </register>
        <register>
          <name>RCR</name>
          <addressOffset>0x30</addressOffset>
          <size>0x20</size>
          <fields>
            <field>
              <name>REP</name>
              <bitOffset>0</bitOffset>
              <bitWidth>8</bitWidth>
            </field>
          </fields>
        </register>
        <register>
          <name>CCR1</name>
          <addressOffset>0x34</addressOffset>
          <size>0x20</size>
          <fields>
            <field>
              <name>CCR1</name>
              <bitOffset>0</bitOffset>
              <bitWidth>16</bitWidth>
            </field>
          </fields>
        </register>
        <register>
          <name>CCR2</name>
          <addressOffset>0x38</addressOffset>
          <size>0x20</size>
          <fields>
            <field>
              <name>CCR2</name>
              <bitOffset>0</bitOffset>
              <bitWidth>16</bitWidth>
            </field>
          </fields>
        </register>
        <register>
          <name>CCR3</name>
          <addressOffset>0x3c</addressOffset>
          <size>0x20</size>
          <fields>
            <field>
              <name>CCR3</name>
              <bitOffset>0</bitOffset>
              <bitWidth>16</bitWidth>
            </field>
          </fields>
        </register>
        <register>
          <name>CCR4</name>
          <addressOffset>0x40</addressOffset>
          <size>0x20</size>
          <fields>
            <field>
              <name>CCR4</name>
              <bitOffset>0</bitOffset>
              <bitWidth>16</bitWidth>
            </field>
          </fields>
        </register>
        <register>
          <name>BDTR</name>
          <addressOffset>0x44</addressOffset>
          <size>0x20</size>
          <fields>
            <field>
              <name>DTG</name>
              <bitOffset>0</bitOffset>
              <bitWidth>8</bitWidth>
            </field>
            <field>
              <name>LOCK</name>
              <bitOffset>8</bitOffset>
              <bitWidth>2</bitWidth>
            </field>
            <field>
              <name>OSSI</name>
              <bitOffset>10</bitOffset>
              <bitWidth>1</bitWidth>
            </field>
            <field>
              <name>OSSR</name>
              <bitOffset>11</bitOffset>
              <bitWidth>1</bitWidth>
            </field>
            <field>
              <name>BKE</name>
              <bitOffset>12</bitOffset>
              <bitWidth>1</bitWidth>
            </field>
            <field>
              <name>BKP</name>
              <bitOffset>13</bitOffset>
              <bitWidth>1</bitWidth>
            </field>
            <field>
              <name>AOE</name>
              <bitOffset>14</bitOffset>
              <bitWidth>1</bitWidth>
            </field>
            <field>
              <name>MOE</name>
              <bitOffset>15</bitOffset>
              <bitWidth>1</bitWidth>
            </field>
          </fields>
        </register>
        <register>
          <name>DCR</name>
          <addressOffset>0x48</addressOffset>
          <size>0x20</size>
          <fields>
            <field>
              <name>DBA</name>
              <bitOffset>0</bitOffset>
              <bitWidth>5</bitWidth>
            </field>
            <field>
              <name>DBL</name>
              <bitOffset>8</bitOffset>
              <bitWidth>5</bitWidth>
            </field>
          </fields>
        </register>
        <register>
          <name>DMAR</name>
          <addressOffset>0x4c</addressOffset>
          <size>0x20</size>
          <fields>
            <field>
              <name>DMAB</name>
              <bitOffset>0</bitOffset>
              <bitWidth>16</bitWidth>
            </field>
          </fields>
        </register>
        <register>
          <name>OR</name>
          <addressOffset>0x50</addressOffset>
          <size>0x20</size>
        </register>
      </registers>
    </peripheral>
    <peripheral>
      <name>SPI1</name>
      <baseAddress>0x40013000</baseAddress>
      <registers>
        <register>
          <name>CR1</name>
          <addressOffset>0x0</addressOffset>
          <size>0x20</size>
          <fields>
            <field>
              <name>CPHA</name>
              <bitOffset>0</bitOffset>
              <bitWidth>1</bitWidth>
            </field>
            <field>
              <name>CPOL</name>
              <bitOffset>1</bitOffset>
              <bitWidth>1</bitWidth>
            </field>
            <field>
              <name>MSTR</name>
              <bitOffset>2</bitOffset>
              <bitWidth>1</bitWidth>
            </field>
            <field>
              <name>BR</name>
              <bitOffset>3</bitOffset>
              <bitWidth>3</bitWidth>
            </field>
            <field>
              <name>SPE</name>
              <bitOffset>6</bitOffset>
              <bitWidth>1</bitWidth>
            </field>
            <field>
              <name>LSBFIRST</name>
              <bitOffset>7</bitOffset>
              <bitWidth>1</bitWidth>
            </field>
            <field>
              <name>SSI</name>
              <bitOffset>8</bitOffset>
              <bitWidth>1</bitWidth>
            </field>
            <field>
              <name>SSM</name>
              <bitOffset>9</bitOffset>
              <bitWidth>1</bitWidth>
            </field>
            <field>
              <name>RXONLY</name>
              <bitOffset>10</bitOffset>
              <bitWidth>1</bitWidth>
            </field>
            <field>
              <name>CRCL</name>
              <bitOffset>11</bitOffset>
              <bitWidth>1</bitWidth>
            </field>
            <field>
              <name>CRCNEXT</name>
              <bitOffset>12</bitOffset>
              <bitWidth>1</bitWidth>
            </field>
            <field>
              <name>CRCEN</name>
              <bitOffset>13</bitOffset>
              <bitWidth>1</bitWidth>
            </field>
            <field>
              <name>BIDIOE</name>
              <bitOffset>14</bitOffset>
              <bitWidth>1</bitWidth>
            </field>
            <field>
              <name>BIDIMODE</name>
              <bitOffset>15</bitOffset>
              <bitWidth>1</bitWidth>
            </field>
          </fields>
        </register>
        <register>
          <name>CR2</name>
          <addressOffset>0x4</addressOffset>
          <size>0x20</size>
          <fields>
            <field>
              <name>RXDMAEN</name>
              <bitOffset>0</bitOffset>
              <bitWidth>1</bitWidth>
            </field>
            <field>
              <name>TXDMAEN</name>
              <bitOffset>1</bitOffset>
              <bitWidth>1</bitWidth>
            </field>
            <field>
              <name>SSOE</name>
              <bitOffset>2</bitOffset>
              <bitWidth>1</bitWidth>
            </field>
            <field>
              <name>NSSP</name>
              <bitOffset>3</bitOffset>
              <bitWidth>1</bitWidth>
            </field>
            <field>
              <name>FRF</name>
              <bitOffset>4</bitOffset>
              <bitWidth>1</bitWidth>
            </field>
            <field>
              <name>ERRIE</name>
              <bitOffset>5</bitOffset>
              <bitWidth>1</bitWidth>
            </field>
            <field>
              <name>RXNEIE</name>
              <bitOffset>6</bitOffset>
              <bitWidth>1</bitWidth>
            </field>
            <field>
              <name>TXEIE</name>
              <bitOffset>7</bitOffset>
              <bitWidth>1</bitWidth>
            </field>
            <field>
              <name>DS</name>
              <bitOffset>8</bitOffset>
              <bitWidth>4</bitWidth>
            </field>
            <field>
              <name>FRXTH</name>
              <bitOffset>12</bitOffset>
              <bitWidth>1</bitWidth>
            </field>
            <field>
              <name>LDMARX</name>
              <bitOffset>13</bitOffset>
              <bitWidth>1</bitWidth>
            </field>
            <field>
              <name>LDMATX</name>
              <bitOffset>14</bitOffset>
              <bitWidth>1</bitWidth>
            </field>
          </fields>
        </register>
        <register>
          <name>SR</name>
          <addressOffset>0x8</addressOffset>
          <size>0x20</size>
          <fields>
            <field>
              <name>RXNE</name>
              <bitOffset>0</bitOffset>
              <bitWidth>1</bitWidth>
            </field>
            <field>
              <name>TXE</name>
              <bitOffset>1</bitOffset>
              <bitWidth>1</bitWidth>
            </field>
            <field>
              <name>CHSIDE</name>
              <bitOffset>2</bitOffset>
              <bitWidth>1</bitWidth>
            </field>
            <field>
              <name>UDR</name>
              <bitOffset>3</bitOffset>
              <bitWidth>1</bitWidth>
            </field>
            <field>
              <name>CRCERR</name>
              <bitOffset>4</bitOffset>
              <bitWidth>1</bitWidth>
            </field>
            <field>
              <name>MODF</name>
              <bitOffset>5</bitOffset>
              <bitWidth>1</bitWidth>
            </field>
            <field>
              <name>OVR</name>
              <bitOffset>6</bitOffset>
              <bitWidth>1</bitWidth>
            </field>
            <field>
              <name>BSY</name>
              <bitOffset>7</bitOffset>
              <bitWidth>1</bitWidth>
            </field>
            <field>
              <name>FRE</name>
              <bitOffset>8</bitOffset>
              <bitWidth>1</bitWidth>
            </field>
            <field>
              <name>FRLVL</name>
              <bitOffset>9</bitOffset>
              <bitWidth>2</bitWidth>
            </field>
            <field>
              <name>FTLVL</name>
              <bitOffset>11</bitOffset>
              <bitWidth>2</bitWidth>
            </field>
          </fields>
        </register>
        <register>
          <name>DR</name>
          <addressOffset>0xc</addressOffset>
          <size>0x20</size>
          <fields>
            <field>
              <name>DR</name>
              <bitOffset>0</bitOffset>
              <bitWidth>32</bitWidth>
            </field>
          </fields>
        </register>
        <register>
          <name>CRCPR</name>
          <addressOffset>0x10</addressOffset>
          <size>0x20</size>
          <fields>
            <field>
              <name>CRCPOLY</name>
              <bitOffset>0</bitOffset>
              <bitWidth>32</bitWidth>
            </field>
          </fields>
        </register>
        <register>
          <name>RXCRCR</name>
          <addressOffset>0x14</addressOffset>
          <size>0x20</size>
          <fields>
            <field>
              <name>RXCRC</name>
              <bitOffset>0</bitOffset>
              <bitWidth>32</bitWidth>
            </field>
          </fields>
        </register>
        <register>
          <name>TXCRCR</name>
          <addressOffset>0x18</addressOffset>
          <size>0x20</size>
          <fields>
            <field>
              <name>TXCRC</name>
              <bitOffset>0</bitOffset>
              <bitWidth>32</bitWidth>
            </field>
          </fields>
        </register>
        <register>
          <name>I2SCFGR</name>
          <addressOffset>0x1c</addressOffset>
          <size>0x20</size>
          <fields>
            <field>
              <name>CHLEN</name>
              <bitOffset>0</bitOffset>
              <bitWidth>1</bitWidth>
            </field>
            <field>
              <name>DATLEN</name>
              <bitOffset>1</bitOffset>
              <bitWidth>2</bitWidth>
            </field>
            <field>
              <name>CKPOL</name>
              <bitOffset>3</bitOffset>
              <bitWidth>1</bitWidth>
            </field>
            <field>
              <name>I2SSTD</name>
              <bitOffset>4</bitOffset>
              <bitWidth>2</bitWidth>
            </field>
            <field>
              <name>PCMSYNC</name>
              <bitOffset>7</bitOffset>
              <bitWidth>1</bitWidth>
            </field>
            <field>
              <name>I2SCFG</name>
              <bitOffset>8</bitOffset>
              <bitWidth>2</bitWidth>
            </field>
            <field>
              <name>I2SE</name>
              <bitOffset>10</bitOffset>
              <bitWidth>1</bitWidth>
            </field>
            <field>
              <name>I2SMOD</name>
              <bitOffset>11</bitOffset>
              <bitWidth>1</bitWidth>
            </field>
          </fields>
        </register>
        <register>
          <name>I2SPR</name>
          <addressOffset>0x20</addressOffset>
          <size>0x20</size>
          <fields>
            <field>
              <name>I2SDIV</name>
              <bitOffset>0</bitOffset>
              <bitWidth>8</bitWidth>
            </field>
            <field>
              <name>ODD</name>
              <bitOffset>8</bitOffset>
              <bitWidth>1</bitWidth>
            </field>
            <field>
              <name>MCKOE</name>
              <bitOffset>9</bitOffset>
              <bitWidth>1</bitWidth>
            </field>
          </fields>
        </register>
      </registers>
    </peripheral>
    <peripheral>
      <name>USART1</name>
      <baseAddress>0x40013800</baseAddress>
      <registers>
        <register>
          <name>CR1</name>
          <addressOffset>0x0</addressOffset>
          <size>0x20</size>
          <fields>
            <field>
              <name>UE</name>
              <bitOffset>0</bitOffset>
              <bitWidth>1</bitWidth>
            </field>
            <field>
              <name>UESM</name>
              <bitOffset>1</bitOffset>
              <bitWidth>1</bitWidth>
            </field>
            <field>
              <name>RE</name>
              <bitOffset>2</bitOffset>
              <bitWidth>1</bitWidth>
            </field>
            <field>
              <name>TE</name>
              <bitOffset>3</bitOffset>
              <bitWidth>1</bitWidth>
            </field>
            <field>
              <name>IDLEIE</name>
              <bitOffset>4</bitOffset>
              <bitWidth>1</bitWidth>
            </field>
            <field>
              <name>RXNEIE</name>
              <bitOffset>5</bitOffset>
              <bitWidth>1</bitWidth>
            </field>
            <field>
              <name>TCIE</name>
              <bitOffset>6</bitOffset>
              <bitWidth>1</bitWidth>
            </field>
            <field>
              <name>TXEIE</name>
              <bitOffset>7</bitOffset>
              <bitWidth>1</bitWidth>
            </field>
            <field>
              <name>PEIE</name>
              <bitOffset>8</bitOffset>
              <bitWidth>1</bitWidth>
            </field>
            <field>
              <name>PS</name>
              <bitOffset>9</bitOffset>
              <bitWidth>1</bitWidth>
            </field>
            <field>
              <name>PCE</name>
              <bitOffset>10</bitOffset>
              <bitWidth>1</bitWidth>
            </field>
            <field>
              <name>WAKE</name>
              <bitOffset>11</bitOffset>
              <bitWidth>1</bitWidth>
            </field>
            <field>
              <name>M0</name>
              <bitOffset>12</bitOffset>
              <bitWidth>1</bitWidth>
            </field>
            <field>
              <name>MME</name>
              <bitOffset>13</bitOffset>
              <bitWidth>1</bitWidth>
            </field>
            <field>
              <name>CMIE</name>
              <bitOffset>14</bitOffset>
              <bitWidth>1</bitWidth>
            </field>
            <field>
              <name>OVER8</name>
              <bitOffset>15</bitOffset>
              <bitWidth>1</bitWidth>
            </field>
            <field>
              <name>DEDT</name>
              <bitOffset>16</bitOffset>
              <bitWidth>5</bitWidth>
            </field>
            <field>
              <name>DEAT</name>
              <bitOffset>21</bitOffset>
              <bitWidth>5</bitWidth>
            </field>
            <field>
              <name>RTOIE</name>
              <bitOffset>26</bitOffset>
              <bitWidth>1</bitWidth>
            </field>
            <field>
              <name>EOBIE</name>
              <bitOffset>27</bitOffset>
              <bitWidth>1</bitWidth>
            </field>
            <field>
              <name>M1</name>
              <bitOffset>28</bitOffset>
              <bitWidth>1</bitWidth>
            </field>
          </fields>
        </register>
        <register>
          <name>CR2</name>
          <addressOffset>0x4</addressOffset>
          <size>0x20</size>
          <fields>
            <field>
              <name>ADDM7</name>
              <bitOffset>4</bitOffset>
              <bitWidth>1</bitWidth>
            </field>
            <field>
              <name>LBDL</name>
              <bitOffset>5</bitOffset>
              <bitWidth>1</bitWidth>
            </field>
            <field>
              <name>LBDIE</name>
              <bitOffset>6</bitOffset>
              <bitWidth>1</bitWidth>
            </field>
            <field>
              <name>LBCL</name>
              <bitOffset>8</bitOffset>
              <bitWidth>1</bitWidth>
            </field>
            <field>
              <name>CPHA</name>
              <bitOffset>9</bitOffset>
              <bitWidth>1</bitWidth>
            </field>
            <field>
              <name>CPOL</name>
              <bitOffset>10</bitOffset>
              <bitWidth>1</bitWidth>
            </field>
            <field>
              <name>CLKEN</name>
              <bitOffset>11</bitOffset>
              <bitWidth>1</bitWidth>
            </field>
            <field>
              <name>STOP</name>
              <bitOffset>12</bitOffset>
              <bitWidth>2</bitWidth>
            </field>
            <field>
              <name>LINEN</name>
              <bitOffset>14</bitOffset>
              <bitWidth>1</bitWidth>
            </field>
            <field>
              <name>SWAP</name>
              <bitOffset>15</bitOffset>
              <bitWidth>1</bitWidth>
            </field>
            <field>
              <name>RXINV</name>
              <bitOffset>16</bitOffset>
              <bitWidth>1</bitWidth>
            </field>
            <field>
              <name>TXINV</name>
              <bitOffset>17</bitOffset>
              <bitWidth>1</bitWidth>
            </field>
            <field>
              <name>DATAINV</name>
              <bitOffset>18</bitOffset>
              <bitWidth>1</bitWidth>
            </field>
            <field>
              <name>MSBFIRST</name>
              <bitOffset>19</bitOffset>
              <bitWidth>1</bitWidth>
            </field>
            <field>
              <name>ABREN</name>
              <bitOffset>20</bitOffset>
              <bitWidth>1</bitWidth>
            </field>
            <field>
              <name>ABRMODE</name>
              <bitOffset>21</bitOffset>
              <bitWidth>2</bitWidth>
            </field>
            <field>
              <name>RTOEN</name>
              <bitOffset>23</bitOffset>
              <bitWidth>1</bitWidth>
            </field>
            <field>
              <name>ADD</name>
              <bitOffset>24</bitOffset>
              <bitWidth>8</bitWidth>
            </field>
          </fields>
        </register>
        <register>
          <name>CR3</name>
          <addressOffset>0x8</addressOffset>
          <size>0x20</size>
          <fields>
            <field>
              <name>EIE</name>
              <bitOffset>0</bitOffset>
              <bitWidth>1</bitWidth>
            </field>
            <field>
              <name>IREN</name>
              <bitOffset>1</bitOffset>
              <bitWidth>1</bitWidth>
            </field>
            <field>
              <name>IRLP</name>
              <bitOffset>2</bitOffset>
              <bitWidth>1</bitWidth>
            </field>
            <field>
              <name>HDSEL</name>
              <bitOffset>3</bitOffset>
              <bitWidth>1</bitWidth>
            </field>
            <field>
              <name>NACK</name>
              <bitOffset>4</bitOffset>
              <bitWidth>1</bitWidth>
            </field>
            <field>
              <name>SCEN</name>
              <bitOffset>5</bitOffset>
              <bitWidth>1</bitWidth>
            </field>
            <field>
              <name>DMAR</name>
              <bitOffset>6</bitOffset>
              <bitWidth>1</bitWidth>
            </field>
            <field>
              <name>DMAT</name>
              <bitOffset>7</bitOffset>
              <bitWidth>1</bitWidth>
            </field>
            <field>
              <name>RTSE</name>
              <bitOffset>8</bitOffset>
              <bitWidth>1</bitWidth>
            </field>
            <field>
              <name>CTSE</name>
              <bitOffset>9</bitOffset>
              <bitWidth>1</bitWidth>
            </field>
            <field>
              <name>CTSIE</name>
              <bitOffset>10</bitOffset>
              <bitWidth>1</bitWidth>
            </field>
            <field>
              <name>ONEBIT</name>
              <bitOffset>11</bitOffset>
              <bitWidth>1</bitWidth>
            </field>
            <field>
              <name>OVRDIS</name>
              <bitOffset>12</bitOffset>
              <bitWidth>1</bitWidth>
            </field>
            <field>
              <name>DDRE</name>
              <bitOffset>13</bitOffset>
              <bitWidth>1</bitWidth>
            </field>
            <field>
              <name>DEM</name>
              <bitOffset>14</bitOffset>
              <bitWidth>1</bitWidth>
            </field>
            <field>
              <name>DEP</name>
              <bitOffset>15</bitOffset>
              <bitWidth>1</bitWidth>
            </field>
            <field>
              <name>SCARCNT</name>
              <bitOffset>17</bitOffset>
              <bitWidth>3</bitWidth>
            </field>
            <field>
              <name>WUS</name>
              <bitOffset>20</bitOffset>
              <bitWidth>2</bitWidth>
            </field>
            <field>
              <name>WUFIE</name>
              <bitOffset>22</bitOffset>
              <bitWidth>1</bitWidth>
            </field>
          </fields>
        </register>
        <register>
          <name>BRR</name>
          <addressOffset>0xc</addressOffset>
          <size>0x20</size>
          <fields>
            <field>
              <name>DIV_FRACTION</name>
              <bitOffset>0</bitOffset>
              <bitWidth>4</bitWidth>
            </field>
            <field>
              <name>DIV_MANTISSA</name>
              <bitOffset>4</bitOffset>
              <bitWidth>12</bitWidth>
            </field>
          </fields>
        </register>
        <register>
          <name>GTPR</name>
          <addressOffset>0x10</addressOffset>
          <size>0x20</size>
          <fields>
            <field>
              <name>PSC</name>
              <bitOffset>0</bitOffset>
              <bitWidth>8</bitWidth>
            </field>
            <field>
              <name>GT</name>
              <bitOffset>8</bitOffset>
              <bitWidth>8</bitWidth>
            </field>
          </fields>
        </register>
        <register>
          <name>RTOR</name>
          <addressOffset>0x14</addressOffset>
          <size>0x20</size>
          <fields>
            <field>
              <name>RTO</name>
              <bitOffset>0</bitOffset>
              <bitWidth>24</bitWidth>
            </field>
            <field>
              <name>BLEN</name>
              <bitOffset>24</bitOffset>
              <bitWidth>8</bitWidth>
            </field>
          </fields>
        </register>
        <register>
          <name>RQR</name>
          <addressOffset>0x18</addressOffset>
          <size>0x20</size>
          <fields>
            <field>
              <name>ABRRQ</name>
              <bitOffset>0</bitOffset>
              <bitWidth>1</bitWidth>
            </field>
            <field>
              <name>SBKRQ</name>
              <bitOffset>1</bitOffset>
              <bitWidth>1</bitWidth>
            </field>
            <field>
              <name>MMRQ</name>
              <bitOffset>2</bitOffset>
              <bitWidth>1</bitWidth>
            </field>
            <field>
              <name>RXFRQ</name>
              <bitOffset>3</bitOffset>
              <bitWidth>1</bitWidth>
            </field>
            <field>
              <name>TXFRQ</name>
              <bitOffset>4</bitOffset>
              <bitWidth>1</bitWidth>
            </field>
          </fields>
        </register>
        <register>
          <name>ISR</name>
          <addressOffset>0x1c</addressOffset>
          <size>0x20</size>
          <fields>
            <field>
              <name>PE</name>
              <bitOffset>0</bitOffset>
              <bitWidth>1</bitWidth>
            </field>
            <field>
              <name>FE</name>
              <bitOffset>1</bitOffset>
              <bitWidth>1</bitWidth>
            </field>
            <field>
              <name>NE</name>
              <bitOffset>2</bitOffset>
              <bitWidth>1</bitWidth>
            </field>
            <field>
              <name>ORE</name>
              <bitOffset>3</bitOffset>
              <bitWidth>1</bitWidth>
            </field>
            <field>
              <name>IDLE</name>
              <bitOffset>4</bitOffset>
              <bitWidth>1</bitWidth>
            </field>
            <field>
              <name>RXNE</name>
              <bitOffset>5</bitOffset>
              <bitWidth>1</bitWidth>
            </field>
            <field>
              <name>TC</name>
              <bitOffset>6</bitOffset>
              <bitWidth>1</bitWidth>
            </field>
            <field>
              <name>TXE</name>
              <bitOffset>7</bitOffset>
              <bitWidth>1</bitWidth>
            </field>
            <field>
              <name>LBDF</name>
              <bitOffset>8</bitOffset>
              <bitWidth>1</bitWidth>
            </field>
            <field>
              <name>CTSIF</name>
              <bitOffset>9</bitOffset>
              <bitWidth>1</bitWidth>
            </field>
            <field>
              <name>CTS</name>
              <bitOffset>10</bitOffset>
              <bitWidth>1</bitWidth>
            </field>
            <field>
              <name>RTOF</name>
              <bitOffset>11</bitOffset>
              <bitWidth>1</bitWidth>
            </field>
            <field>
              <name>EOBF</name>
              <bitOffset>12</bitOffset>
              <bitWidth>1</bitWidth>
            </field>
            <field>
              <name>ABRE</name>
              <bitOffset>14</bitOffset>
              <bitWidth>1</bitWidth>
            </field>
            <field>
              <name>ABRF</name>
              <bitOffset>15</bitOffset>
              <bitWidth>1</bitWidth>
            </field>
            <field>
              <name>BUSY</name>
              <bitOffset>16</bitOffset>
              <bitWidth>1</bitWidth>
            </field>
            <field>
              <name>CMF</name>
              <bitOffset>17</bitOffset>
              <bitWidth>1</bitWidth>
            </field>
            <field>
              <name>SBKF</name>
              <bitOffset>18</bitOffset>
              <bitWidth>1</bitWidth>
            </field>
            <field>
              <name>RWU</name>
              <bitOffset>19</bitOffset>
              <bitWidth>1</bitWidth>
            </field>
            <field>
              <name>WUF</name>
              <bitOffset>20</bitOffset>
              <bitWidth>1</bitWidth>
            </field>
            <field>
              <name>TEACK</name>
              <bitOffset>21</bitOffset>
              <bitWidth>1</bitWidth>
            </field>
            <field>
              <name>REACK</name>
              <bitOffset>22</bitOffset>
              <bitWidth>1</bitWidth>
            </field>
          </fields>
        </register>
        <register>
          <name>ICR</name>
          <addressOffset>0x20</addressOffset>
          <size>0x20</size>
          <fields>
            <field>
              <name>PECF</name>
              <bitOffset>0</bitOffset>
              <bitWidth>1</bitWidth>
            </field>
            <field>
              <name>FECF</name>
              <bitOffset>1</bitOffset>
              <bitWidth>1</bitWidth>
            </field>
            <field>
              <name>NCF</name>
              <bitOffset>2</bitOffset>
              <bitWidth>1</bitWidth>
            </field>
            <field>
              <name>ORECF</name>
              <bitOffset>3</bitOffset>
              <bitWidth>1</bitWidth>
            </field>
            <field>
              <name>IDLECF</name>
              <bitOffset>4</bitOffset>
              <bitWidth>1</bitWidth>
            </field>
            <field>
              <name>TCCF</name>
              <bitOffset>6</bitOffset>
              <bitWidth>1</bitWidth>
            </field>
            <field>
              <name>LBDCF</name>
              <bitOffset>8</bitOffset>
              <bitWidth>1</bitWidth>
            </field>
            <field>
              <name>CTSCF</name>
              <bitOffset>9</bitOffset>
              <bitWidth>1</bitWidth>
            </field>
            <field>
              <name>RTOCF</name>
              <bitOffset>11</bitOffset>
              <bitWidth>1</bitWidth>
            </field>
            <field>
              <name>EOBCF</name>
              <bitOffset>12</bitOffset>
              <bitWidth>1</bitWidth>
            </field>
            <field>
              <name>CMCF</name>
              <bitOffset>17</bitOffset>
              <bitWidth>1</bitWidth>
            </field>
            <field>
              <name>WUCF</name>
              <bitOffset>20</bitOffset>
              <bitWidth>1</bitWidth>
            </field>
          </fields>
        </register>
        <register>
          <name>RDR</name>
          <addressOffset>0x24</addressOffset>
          <size>0x10</size>
        </register>
        <register>
          <name>TDR</name>
          <addressOffset>0x28</addressOffset>
          <size>0x10</size>
        </register>
      </registers>
    </peripheral>
    <peripheral>
      <name>TIM15</name>
      <baseAddress>0x40014000</baseAddress>
      <registers>
        <register>
          <name>CR1</name>
          <addressOffset>0x0</addressOffset>
          <size>0x20</size>
          <fields>
            <field>
              <name>CEN</name>
              <bitOffset>0</bitOffset>
              <bitWidth>1</bitWidth>
            </field>
            <field>
              <name>UDIS</name>
              <bitOffset>1</bitOffset>
              <bitWidth>1</bitWidth>
            </field>
            <field>
              <name>URS</name>
              <bitOffset>2</bitOffset>
              <bitWidth>1</bitWidth>
            </field>
            <field>
              <name>OPM</name>
              <bitOffset>3</bitOffset>
              <bitWidth>1</bitWidth>
            </field>
            <field>
              <name>DIR</name>
              <bitOffset>4</bitOffset>
              <bitWidth>1</bitWidth>
            </field>
            <field>
              <name>CMS</name>
              <bitOffset>5</bitOffset>
              <bitWidth>2</bitWidth>
            </field>
            <field>
              <name>ARPE</name>
              <bitOffset>7</bitOffset>
              <bitWidth>1</bitWidth>
            </field>
            <field>
              <name>CKD</name>
              <bitOffset>8</bitOffset>
              <bitWidth>2</bitWidth>
            </field>
          </fields>
        </register>
        <register>
          <name>CR2</name>
          <addressOffset>0x4</addressOffset>
          <size>0x20</size>
          <fields>
            <field>
              <name>CCPC</name>
              <bitOffset>0</bitOffset>
              <bitWidth>1</bitWidth>
            </field>
            <field>
              <name>CCUS</name>
              <bitOffset>2</bitOffset>
              <bitWidth>1</bitWidth>
            </field>
            <field>
              <name>CCDS</name>
              <bitOffset>3</bitOffset>
              <bitWidth>1</bitWidth>
            </field>
            <field>
              <name>MMS</name>
              <bitOffset>4</bitOffset>
              <bitWidth>3</bitWidth>
            </field>
            <field>
              <name>TI1S</name>
              <bitOffset>7</bitOffset>
              <bitWidth>1</bitWidth>
            </field>
            <field>
              <name>OIS1</name>
              <bitOffset>8</bitOffset>
              <bitWidth>1</bitWidth>
            </field>
            <field>
              <name>OIS1N</name>
              <bitOffset>9</bitOffset>
              <bitWidth>1</bitWidth>
            </field>
            <field>
              <name>OIS2</name>
              <bitOffset>10</bitOffset>
              <bitWidth>1</bitWidth>
            </field>
            <field>
              <name>OIS2N</name>
              <bitOffset>11</bitOffset>
              <bitWidth>1</bitWidth>
            </field>
            <field>
              <name>OIS3</name>
              <bitOffset>12</bitOffset>
              <bitWidth>1</bitWidth>
            </field>
            <field>
              <name>OIS3N</name>
              <bitOffset>13</bitOffset>
              <bitWidth>1</bitWidth>
            </field>
            <field>
              <name>OIS4</name>
              <bitOffset>14</bitOffset>
              <bitWidth>1</bitWidth>
            </field>
          </fields>
        </register>
        <register>
          <name>SMCR</name>
          <addressOffset>0x8</addressOffset>
          <size>0x20</size>
          <fields>
            <field>
              <name>SMS</name>
              <bitOffset>0</bitOffset>
              <bitWidth>3</bitWidth>
            </field>
            <field>
              <name>OCCS</name>
              <bitOffset>3</bitOffset>
              <bitWidth>1</bitWidth>
            </field>
            <field>
              <name>TS</name>
              <bitOffset>4</bitOffset>
              <bitWidth>3</bitWidth>
            </field>
            <field>
              <name>MSM</name>
              <bitOffset>7</bitOffset>
              <bitWidth>1</bitWidth>
            </field>
            <field>
              <name>ETF</name>
              <bitOffset>8</bitOffset>
              <bitWidth>4</bitWidth>
            </field>
            <field>
              <name>ETPS</name>
              <bitOffset>12</bitOffset>
              <bitWidth>2</bitWidth>
            </field>
            <field>
              <name>ECE</name>
              <bitOffset>14</bitOffset>
              <bitWidth>1</bitWidth>
            </field>
            <field>
              <name>ETP</name>
              <bitOffset>15</bitOffset>
              <bitWidth>1</bitWidth>
            </field>
          </fields>
        </register>
        <register>
          <name>DIER</name>
          <addressOffset>0xc</addressOffset>
          <size>0x20</size>
          <fields>
            <field>
              <name>UIE</name>
              <bitOffset>0</bitOffset>
              <bitWidth>1</bitWidth>
            </field>
            <field>
              <name>CC1IE</name>
              <bitOffset>1</bitOffset>
              <bitWidth>1</bitWidth>
            </field>
            <field>
              <name>CC2IE</name>
              <bitOffset>2</bitOffset>
              <bitWidth>1</bitWidth>
            </field>
            <field>
              <name>CC3IE</name>
              <bitOffset>3</bitOffset>
              <bitWidth>1</bitWidth>
            </field>
            <field>
              <name>CC4IE</name>
              <bitOffset>4</bitOffset>
              <bitWidth>1</bitWidth>
            </field>
            <field>
              <name>COMIE</name>
              <bitOffset>5</bitOffset>
              <bitWidth>1</bitWidth>
            </field>
            <field>
              <name>TIE</name>
              <bitOffset>6</bitOffset>
              <bitWidth>1</bitWidth>
            </field>
            <field>
              <name>BIE</name>
              <bitOffset>7</bitOffset>
              <bitWidth>1</bitWidth>
            </field>
            <field>
              <name>UDE</name>
              <bitOffset>8</bitOffset>
              <bitWidth>1</bitWidth>
            </field>
            <field>
              <name>CC1DE</name>
              <bitOffset>9</bitOffset>
              <bitWidth>1</bitWidth>
            </field>
            <field>
              <name>CC2DE</name>
              <bitOffset>10</bitOffset>
              <bitWidth>1</bitWidth>
            </field>
            <field>
              <name>CC3DE</name>
              <bitOffset>11</bitOffset>
              <bitWidth>1</bitWidth>
            </field>
            <field>
              <name>CC4DE</name>
              <bitOffset>12</bitOffset>
              <bitWidth>1</bitWidth>
            </field>
            <field>
              <name>COMDE</name>
              <bitOffset>13</bitOffset>
              <bitWidth>1</bitWidth>
            </field>
            <field>
              <name>TDE</name>
              <bitOffset>14</bitOffset>
              <bitWidth>1</bitWidth>
            </field>
          </fields>
        </register>
        <register>
          <name>SR</name>
          <addressOffset>0x10</addressOffset>
          <size>0x20</size>
          <fields>
            <field>
              <name>UIF</name>
              <bitOffset>0</bitOffset>
              <bitWidth>1</bitWidth>
            </field>
            <field>
              <name>CC1IF</name>
              <bitOffset>1</bitOffset>
              <bitWidth>1</bitWidth>
            </field>
            <field>
              <name>CC2IF</name>
              <bitOffset>2</bitOffset>
              <bitWidth>1</bitWidth>
            </field>
            <field>
              <name>CC3IF</name>
              <bitOffset>3</bitOffset>
              <bitWidth>1</bitWidth>
            </field>
            <field>
              <name>CC4IF</name>
              <bitOffset>4</bitOffset>
              <bitWidth>1</bitWidth>
            </field>
            <field>
              <name>COMIF</name>
              <bitOffset>5</bitOffset>
              <bitWidth>1</bitWidth>
            </field>
            <field>
              <name>TIF</name>
              <bitOffset>6</bitOffset>
              <bitWidth>1</bitWidth>
            </field>
            <field>
              <name>BIF</name>
              <bitOffset>7</bitOffset>
              <bitWidth>1</bitWidth>
            </field>
            <field>
              <name>CC1OF</name>
              <bitOffset>9</bitOffset>
              <bitWidth>1</bitWidth>
            </field>
            <field>
              <name>CC2OF</name>
              <bitOffset>10</bitOffset>
              <bitWidth>1</bitWidth>
            </field>
            <field>
              <name>CC3OF</name>
              <bitOffset>11</bitOffset>
              <bitWidth>1</bitWidth>
            </field>
            <field>
              <name>CC4OF</name>
              <bitOffset>12</bitOffset>
              <bitWidth>1</bitWidth>
            </field>
          </fields>
        </register>
        <register>
          <name>EGR</name>
          <addressOffset>0x14</addressOffset>
          <size>0x20</size>
          <fields>
            <field>
              <name>UG</name>
              <bitOffset>0</bitOffset>
              <bitWidth>1</bitWidth>
            </field>
            <field>
              <name>CC1G</name>
              <bitOffset>1</bitOffset>
              <bitWidth>1</bitWidth>
            </field>
            <field>
              <name>CC2G</name>
              <bitOffset>2</bitOffset>
              <bitWidth>1</bitWidth>
            </field>
            <field>
              <name>CC3G</name>
              <bitOffset>3</bitOffset>
              <bitWidth>1</bitWidth>
            </field>
            <field>
              <name>CC4G</name>
              <bitOffset>4</bitOffset>
              <bitWidth>1</bitWidth>
            </field>
            <field>
              <name>COMG</name>
              <bitOffset>5</bitOffset>
              <bitWidth>1</bitWidth>
            </field>
            <field>
              <name>TG</name>
              <bitOffset>6</bitOffset>
              <bitWidth>1</bitWidth>
            </field>
            <field>
              <name>BG</name>
              <bitOffset>7</bitOffset>
              <bitWidth>1</bitWidth>
            </field>
          </fields>
        </register>
        <register>
          <name>CCMR1</name>
          <addressOffset>0x18</addressOffset>
          <size>0x20</size>
          <fields>
            <field>
              <name>CC1S</name>
              <bitOffset>0</bitOffset>
              <bitWidth>2</bitWidth>
            </field>
            <field>
              <name>OC1FE</name>
              <bitOffset>2</bitOffset>
              <bitWidth>1</bitWidth>
            </field>
            <field>
              <name>OC1PE</name>
              <bitOffset>3</bitOffset>
              <bitWidth>1</bitWidth>
            </field>
            <field>
              <name>OC1M</name>
              <bitOffset>4</bitOffset>
              <bitWidth>3</bitWidth>
            </field>
            <field>
              <name>OC1CE</name>
              <bitOffset>7</bitOffset>
              <bitWidth>1</bitWidth>
            </field>
            <field>
              <name>CC2S</name>
              <bitOffset>8</bitOffset>
              <bitWidth>2</bitWidth>
            </field>
            <field>
              <name>OC2FE</name>
              <bitOffset>10</bitOffset>
              <bitWidth>1</bitWidth>
            </field>
            <field>
              <name>OC2PE</name>
              <bitOffset>11</bitOffset>
              <bitWidth>1</bitWidth>
            </field>
            <field>
              <name>OC2M</name>
              <bitOffset>12</bitOffset>
              <bitWidth>3</bitWidth>
            </field>
            <field>
              <name>OC2CE</name>
              <bitOffset>15</bitOffset>
              <bitWidth>1</bitWidth>
            </field>
          </fields>
        </register>
        <register>
          <name>CCMR2</name>
          <addressOffset>0x1c</addressOffset>
          <size>0x20</size>
          <fields>
            <field>
              <name>CC3S</name>
              <bitOffset>0</bitOffset>
              <bitWidth>2</bitWidth>
            </field>
            <field>
              <name>OC3FE</name>
              <bitOffset>2</bitOffset>
              <bitWidth>1</bitWidth>
            </field>
            <field>
              <name>OC3PE</name>
              <bitOffset>3</bitOffset>
              <bitWidth>1</bitWidth>
            </field>
            <field>
              <name>OC3M</name>
              <bitOffset>4</bitOffset>
              <bitWidth>3</bitWidth>
            </field>
            <field>
              <name>OC3CE</name>
              <bitOffset>7</bitOffset>
              <bitWidth>1</bitWidth>
            </field>
            <field>
              <name>CC4S</name>
              <bitOffset>8</bitOffset>
              <bitWidth>2</bitWidth>
            </field>
            <field>
              <name>OC4FE</name>
              <bitOffset>10</bitOffset>
              <bitWidth>1</bitWidth>
            </field>
            <field>
              <name>OC4PE</name>
              <bitOffset>11</bitOffset>
              <bitWidth>1</bitWidth>
            </field>
            <field>
              <name>OC4M</name>
              <bitOffset>12</bitOffset>
              <bitWidth>3</bitWidth>
            </field>
            <field>
              <name>OC4CE</name>
              <bitOffset>15</bitOffset>
              <bitWidth>1</bitWidth>
            </field>
          </fields>
        </register>
        <register>
          <name>CCER</name>
          <addressOffset>0x20</addressOffset>
          <size>0x20</size>
          <fields>
            <field>
              <name>CC1E</name>
              <bitOffset>0</bitOffset>
              <bitWidth>1</bitWidth>
            </field>
            <field>
              <name>CC1P</name>
              <bitOffset>1</bitOffset>
              <bitWidth>1</bitWidth>
            </field>
            <field>
              <name>CC1NE</name>
              <bitOffset>2</bitOffset>
              <bitWidth>1</bitWidth>
            </field>
            <field>
              <name>CC1NP</name>
              <bitOffset>3</bitOffset>
              <bitWidth>1</bitWidth>
            </field>
            <field>
              <name>CC2E</name>
              <bitOffset>4</bitOffset>
              <bitWidth>1</bitWidth>
            </field>
            <field>
              <name>CC2P</name>
              <bitOffset>5</bitOffset>
              <bitWidth>1</bitWidth>
            </field>
            <field>
              <name>CC2NE</name>
              <bitOffset>6</bitOffset>
              <bitWidth>1</bitWidth>
            </field>
            <field>
              <name>CC2NP</name>
              <bitOffset>7</bitOffset>
              <bitWidth>1</bitWidth>
            </field>
            <field>
              <name>CC3E</name>
              <bitOffset>8</bitOffset>
              <bitWidth>1</bitWidth>
            </field>
            <field>
              <name>CC3P</name>
              <bitOffset>9</bitOffset>
              <bitWidth>1</bitWidth>
            </field>
            <field>
              <name>CC3NE</name>
              <bitOffset>10</bitOffset>
              <bitWidth>1</bitWidth>
            </field>
            <field>
              <name>CC3NP</name>
              <bitOffset>11</bitOffset>
              <bitWidth>1</bitWidth>
            </field>
            <field>
              <name>CC4E</name>
              <bitOffset>12</bitOffset>
              <bitWidth>1</bitWidth>
            </field>
            <field>
              <name>CC4P</name>
              <bitOffset>13</bitOffset>
              <bitWidth>1</bitWidth>
            </field>
            <field>
              <name>CC4NP</name>
              <bitOffset>15</bitOffset>
              <bitWidth>1</bitWidth>
            </field>
          </fields>
        </register>
        <register>
          <name>CNT</name>
          <addressOffset>0x24</addressOffset>
          <size>0x20</size>
          <fields>
            <field>
              <name>CNT</name>
              <bitOffset>0</bitOffset>
              <bitWidth>32</bitWidth>
            </field>
          </fields>
        </register>
        <register>
          <name>PSC</name>
          <addressOffset>0x28</addressOffset>
          <size>0x20</size>
          <fields>
            <field>
              <name>PSC</name>
              <bitOffset>0</bitOffset>
              <bitWidth>16</bitWidth>
            </field>
          </fields>
        </register>
        <register>
          <name>ARR</name>
          <addressOffset>0x2c</addressOffset>
          <size>0x20</size>
          <fields>
            <field>
              <name>ARR</name>
              <bitOffset>0</bitOffset>
              <bitWidth>32</bitWidth>
            </field>
          </fields>
        </register>
        <register>
          <name>RCR</name>
          <addressOffset>0x30</addressOffset>
          <size>0x20</size>
          <fields>
            <field>
              <name>REP</name>
              <bitOffset>0</bitOffset>
              <bitWidth>8</bitWidth>
            </field>
          </fields>
        </register>
        <register>
          <name>CCR1</name>
          <addressOffset>0x34</addressOffset>
          <size>0x20</size>
          <fields>
            <field>
              <name>CCR1</name>
              <bitOffset>0</bitOffset>
              <bitWidth>16</bitWidth>
            </field>
          </fields>
        </register>
        <register>
          <name>CCR2</name>
          <addressOffset>0x38</addressOffset>
          <size>0x20</size>
          <fields>
            <field>
              <name>CCR2</name>
              <bitOffset>0</bitOffset>
              <bitWidth>16</bitWidth>
            </field>
          </fields>
        </register>
        <register>
          <name>CCR3</name>
          <addressOffset>0x3c</addressOffset>
          <size>0x20</size>
          <fields>
            <field>
              <name>CCR3</name>
              <bitOffset>0</bitOffset>
              <bitWidth>16</bitWidth>
            </field>
          </fields>
        </register>
        <register>
          <name>CCR4</name>
          <addressOffset>0x40</addressOffset>
          <size>0x20</size>
          <fields>
            <field>
              <name>CCR4</name>
              <bitOffset>0</bitOffset>
              <bitWidth>16</bitWidth>
            </field>
          </fields>
        </register>
        <register>
          <name>BDTR</name>
          <addressOffset>0x44</addressOffset>
          <size>0x20</size>
          <fields>
            <field>
              <name>DTG</name>
              <bitOffset>0</bitOffset>
              <bitWidth>8</bitWidth>
            </field>
            <field>
              <name>LOCK</name>
              <bitOffset>8</bitOffset>
              <bitWidth>2</bitWidth>
            </field>
            <field>
              <name>OSSI</name>
              <bitOffset>10</bitOffset>
              <bitWidth>1</bitWidth>
            </field>
            <field>
              <name>OSSR</name>
              <bitOffset>11</bitOffset>
              <bitWidth>1</bitWidth>
            </field>
            <field>
              <name>BKE</name>
              <bitOffset>12</bitOffset>
              <bitWidth>1</bitWidth>
            </field>
            <field>
              <name>BKP</name>
              <bitOffset>13</bitOffset>
              <bitWidth>1</bitWidth>
            </field>
            <field>
              <name>AOE</name>
              <bitOffset>14</bitOffset>
              <bitWidth>1</bitWidth>
            </field>
            <field>
              <name>MOE</name>
              <bitOffset>15</bitOffset>
              <bitWidth>1</bitWidth>
            </field>
          </fields>
        </register>
        <register>
          <name>DCR</name>
          <addressOffset>0x48</addressOffset>
          <size>0x20</size>
          <fields>
            <field>
              <name>DBA</name>
              <bitOffset>0</bitOffset>
              <bitWidth>5</bitWidth>
            </field>
            <field>
              <name>DBL</name>
              <bitOffset>8</bitOffset>
              <bitWidth>5</bitWidth>
            </field>
          </fields>
        </register>
        <register>
          <name>DMAR</name>
          <addressOffset>0x4c</addressOffset>
          <size>0x20</size>
          <fields>
            <field>
              <name>DMAB</name>
              <bitOffset>0</bitOffset>
              <bitWidth>16</bitWidth>
            </field>
          </fields>
        </register>
        <register>
          <name>OR</name>
          <addressOffset>0x50</addressOffset>
          <size>0x20</size>
        </register>
      </registers>
    </peripheral>
    <peripheral>
      <name>TIM16</name>
      <baseAddress>0x40014400</baseAddress>
      <registers>
        <register>
          <name>CR1</name>
          <addressOffset>0x0</addressOffset>
          <size>0x20</size>
          <fields>
            <field>
              <name>CEN</name>
              <bitOffset>0</bitOffset>
              <bitWidth>1</bitWidth>
            </field>
            <field>
              <name>UDIS</name>
              <bitOffset>1</bitOffset>
              <bitWidth>1</bitWidth>
            </field>
            <field>
              <name>URS</name>
              <bitOffset>2</bitOffset>
              <bitWidth>1</bitWidth>
            </field>
            <field>
              <name>OPM</name>
              <bitOffset>3</bitOffset>
              <bitWidth>1</bitWidth>
            </field>
            <field>
              <name>DIR</name>
              <bitOffset>4</bitOffset>
              <bitWidth>1</bitWidth>
            </field>
            <field>
              <name>CMS</name>
              <bitOffset>5</bitOffset>
              <bitWidth>2</bitWidth>
            </field>
            <field>
              <name>ARPE</name>
              <bitOffset>7</bitOffset>
              <bitWidth>1</bitWidth>
            </field>
            <field>
              <name>CKD</name>
              <bitOffset>8</bitOffset>
              <bitWidth>2</bitWidth>
            </field>
          </fields>
        </register>
        <register>
          <name>CR2</name>
          <addressOffset>0x4</addressOffset>
          <size>0x20</size>
          <fields>
            <field>
              <name>CCPC</name>
              <bitOffset>0</bitOffset>
              <bitWidth>1</bitWidth>
            </field>
            <field>
              <name>CCUS</name>
              <bitOffset>2</bitOffset>
              <bitWidth>1</bitWidth>
            </field>
            <field>
              <name>CCDS</name>
              <bitOffset>3</bitOffset>
              <bitWidth>1</bitWidth>
            </field>
            <field>
              <name>MMS</name>
              <bitOffset>4</bitOffset>
              <bitWidth>3</bitWidth>
            </field>
            <field>
              <name>TI1S</name>
              <bitOffset>7</bitOffset>
              <bitWidth>1</bitWidth>
            </field>
            <field>
              <name>OIS1</name>
              <bitOffset>8</bitOffset>
              <bitWidth>1</bitWidth>
            </field>
            <field>
              <name>OIS1N</name>
              <bitOffset>9</bitOffset>
              <bitWidth>1</bitWidth>
            </field>
            <field>
              <name>OIS2</name>
              <bitOffset>10</bitOffset>
              <bitWidth>1</bitWidth>
            </field>
            <field>
              <name>OIS2N</name>
              <bitOffset>11</bitOffset>
              <bitWidth>1</bitWidth>
            </field>
            <field>
              <name>OIS3</name>
              <bitOffset>12</bitOffset>
              <bitWidth>1</bitWidth>
            </field>
            <field>
              <name>OIS3N</name>
              <bitOffset>13</bitOffset>
              <bitWidth>1</bitWidth>
            </field>
            <field>
              <name>OIS4</name>
              <bitOffset>14</bitOffset>
              <bitWidth>1</bitWidth>
            </field>
          </fields>
        </register>
        <register>
          <name>SMCR</name>
          <addressOffset>0x8</addressOffset>
          <size>0x20</size>
          <fields>
            <field>
              <name>SMS</name>
              <bitOffset>0</bitOffset>
              <bitWidth>3</bitWidth>
            </field>
            <field>
              <name>OCCS</name>
              <bitOffset>3</bitOffset>
              <bitWidth>1</bitWidth>
            </field>
            <field>
              <name>TS</name>
              <bitOffset>4</bitOffset>
              <bitWidth>3</bitWidth>
            </field>
            <field>
              <name>MSM</name>
              <bitOffset>7</bitOffset>
              <bitWidth>1</bitWidth>
            </field>
            <field>
              <name>ETF</name>
              <bitOffset>8</bitOffset>
              <bitWidth>4</bitWidth>
            </field>
            <field>
              <name>ETPS</name>
              <bitOffset>12</bitOffset>
              <bitWidth>2</bitWidth>
            </field>
            <field>
              <name>ECE</name>
              <bitOffset>14</bitOffset>
              <bitWidth>1</bitWidth>
            </field>
            <field>
              <name>ETP</name>
              <bitOffset>15</bitOffset>
              <bitWidth>1</bitWidth>
            </field>
          </fields>
        </register>
        <register>
          <name>DIER</name>
          <addressOffset>0xc</addressOffset>
          <size>0x20</size>
          <fields>
            <field>
              <name>UIE</name>
              <bitOffset>0</bitOffset>
              <bitWidth>1</bitWidth>
            </field>
            <field>
              <name>CC1IE</name>
              <bitOffset>1</bitOffset>
              <bitWidth>1</bitWidth>
            </field>
            <field>
              <name>CC2IE</name>
              <bitOffset>2</bitOffset>
              <bitWidth>1</bitWidth>
            </field>
            <field>
              <name>CC3IE</name>
              <bitOffset>3</bitOffset>
              <bitWidth>1</bitWidth>
            </field>
            <field>
              <name>CC4IE</name>
              <bitOffset>4</bitOffset>
              <bitWidth>1</bitWidth>
            </field>
            <field>
              <name>COMIE</name>
              <bitOffset>5</bitOffset>
              <bitWidth>1</bitWidth>
            </field>
            <field>
              <name>TIE</name>
              <bitOffset>6</bitOffset>
              <bitWidth>1</bitWidth>
            </field>
            <field>
              <name>BIE</name>
              <bitOffset>7</bitOffset>
              <bitWidth>1</bitWidth>
            </field>
            <field>
              <name>UDE</name>
              <bitOffset>8</bitOffset>
              <bitWidth>1</bitWidth>
            </field>
            <field>
              <name>CC1DE</name>
              <bitOffset>9</bitOffset>
              <bitWidth>1</bitWidth>
            </field>
            <field>
              <name>CC2DE</name>
              <bitOffset>10</bitOffset>
              <bitWidth>1</bitWidth>
            </field>
            <field>
              <name>CC3DE</name>
              <bitOffset>11</bitOffset>
              <bitWidth>1</bitWidth>
            </field>
            <field>
              <name>CC4DE</name>
              <bitOffset>12</bitOffset>
              <bitWidth>1</bitWidth>
            </field>
            <field>
              <name>COMDE</name>
              <bitOffset>13</bitOffset>
              <bitWidth>1</bitWidth>
            </field>
            <field>
              <name>TDE</name>
              <bitOffset>14</bitOffset>
              <bitWidth>1</bitWidth>
            </field>
          </fields>
        </register>
        <register>
          <name>SR</name>
          <addressOffset>0x10</addressOffset>
          <size>0x20</size>
          <fields>
            <field>
              <name>UIF</name>
              <bitOffset>0</bitOffset>
              <bitWidth>1</bitWidth>
            </field>
            <field>
              <name>CC1IF</name>
              <bitOffset>1</bitOffset>
              <bitWidth>1</bitWidth>
            </field>
            <field>
              <name>CC2IF</name>
              <bitOffset>2</bitOffset>
              <bitWidth>1</bitWidth>
            </field>
            <field>
              <name>CC3IF</name>
              <bitOffset>3</bitOffset>
              <bitWidth>1</bitWidth>
            </field>
            <field>
              <name>CC4IF</name>
              <bitOffset>4</bitOffset>
              <bitWidth>1</bitWidth>
            </field>
            <field>
              <name>COMIF</name>
              <bitOffset>5</bitOffset>
              <bitWidth>1</bitWidth>
            </field>
            <field>
              <name>TIF</name>
              <bitOffset>6</bitOffset>
              <bitWidth>1</bitWidth>
            </field>
            <field>
              <name>BIF</name>
              <bitOffset>7</bitOffset>
              <bitWidth>1</bitWidth>
            </field>
            <field>
              <name>CC1OF</name>
              <bitOffset>9</bitOffset>
              <bitWidth>1</bitWidth>
            </field>
            <field>
              <name>CC2OF</name>
              <bitOffset>10</bitOffset>
              <bitWidth>1</bitWidth>
            </field>
            <field>
              <name>CC3OF</name>
              <bitOffset>11</bitOffset>
              <bitWidth>1</bitWidth>
            </field>
            <field>
              <name>CC4OF</name>
              <bitOffset>12</bitOffset>
              <bitWidth>1</bitWidth>
            </field>
          </fields>
        </register>
        <register>
          <name>EGR</name>
          <addressOffset>0x14</addressOffset>
          <size>0x20</size>
          <fields>
            <field>
              <name>UG</name>
              <bitOffset>0</bitOffset>
              <bitWidth>1</bitWidth>
            </field>
            <field>
              <name>CC1G</name>
              <bitOffset>1</bitOffset>
              <bitWidth>1</bitWidth>
            </field>
            <field>
              <name>CC2G</name>
              <bitOffset>2</bitOffset>
              <bitWidth>1</bitWidth>
            </field>
            <field>
              <name>CC3G</name>
              <bitOffset>3</bitOffset>
              <bitWidth>1</bitWidth>
            </field>
            <field>
              <name>CC4G</name>
              <bitOffset>4</bitOffset>
              <bitWidth>1</bitWidth>
            </field>
            <field>
              <name>COMG</name>
              <bitOffset>5</bitOffset>
              <bitWidth>1</bitWidth>
            </field>
            <field>
              <name>TG</name>
              <bitOffset>6</bitOffset>
              <bitWidth>1</bitWidth>
            </field>
            <field>
              <name>BG</name>
              <bitOffset>7</bitOffset>
              <bitWidth>1</bitWidth>
            </field>
          </fields>
        </register>
        <register>
          <name>CCMR1</name>
          <addressOffset>0x18</addressOffset>
          <size>0x20</size>
          <fields>
            <field>
              <name>CC1S</name>
              <bitOffset>0</bitOffset>
              <bitWidth>2</bitWidth>
            </field>
            <field>
              <name>OC1FE</name>
              <bitOffset>2</bitOffset>
              <bitWidth>1</bitWidth>
            </field>
            <field>
              <name>OC1PE</name>
              <bitOffset>3</bitOffset>
              <bitWidth>1</bitWidth>
            </field>
            <field>
              <name>OC1M</name>
              <bitOffset>4</bitOffset>
              <bitWidth>3</bitWidth>
            </field>
            <field>
              <name>OC1CE</name>
              <bitOffset>7</bitOffset>
              <bitWidth>1</bitWidth>
            </field>
            <field>
              <name>CC2S</name>
              <bitOffset>8</bitOffset>
              <bitWidth>2</bitWidth>
            </field>
            <field>
              <name>OC2FE</name>
              <bitOffset>10</bitOffset>
              <bitWidth>1</bitWidth>
            </field>
            <field>
              <name>OC2PE</name>
              <bitOffset>11</bitOffset>
              <bitWidth>1</bitWidth>
            </field>
            <field>
              <name>OC2M</name>
              <bitOffset>12</bitOffset>
              <bitWidth>3</bitWidth>
            </field>
            <field>
              <name>OC2CE</name>
              <bitOffset>15</bitOffset>
              <bitWidth>1</bitWidth>
            </field>
          </fields>
        </register>
        <register>
          <name>CCMR2</name>
          <addressOffset>0x1c</addressOffset>
          <size>0x20</size>
          <fields>
            <field>
              <name>CC3S</name>
              <bitOffset>0</bitOffset>
              <bitWidth>2</bitWidth>
            </field>
            <field>
              <name>OC3FE</name>
              <bitOffset>2</bitOffset>
              <bitWidth>1</bitWidth>
            </field>
            <field>
              <name>OC3PE</name>
              <bitOffset>3</bitOffset>
              <bitWidth>1</bitWidth>
            </field>
            <field>
              <name>OC3M</name>
              <bitOffset>4</bitOffset>
              <bitWidth>3</bitWidth>
            </field>
            <field>
              <name>OC3CE</name>
              <bitOffset>7</bitOffset>
              <bitWidth>1</bitWidth>
            </field>
            <field>
              <name>CC4S</name>
              <bitOffset>8</bitOffset>
              <bitWidth>2</bitWidth>
            </field>
            <field>
              <name>OC4FE</name>
              <bitOffset>10</bitOffset>
              <bitWidth>1</bitWidth>
            </field>
            <field>
              <name>OC4PE</name>
              <bitOffset>11</bitOffset>
              <bitWidth>1</bitWidth>
            </field>
            <field>
              <name>OC4M</name>
              <bitOffset>12</bitOffset>
              <bitWidth>3</bitWidth>
            </field>
            <field>
              <name>OC4CE</name>
              <bitOffset>15</bitOffset>
              <bitWidth>1</bitWidth>
            </field>
          </fields>
        </register>
        <register>
          <name>CCER</name>
          <addressOffset>0x20</addressOffset>
          <size>0x20</size>
          <fields>
            <field>
              <name>CC1E</name>
              <bitOffset>0</bitOffset>
              <bitWidth>1</bitWidth>
            </field>
            <field>
              <name>CC1P</name>
              <bitOffset>1</bitOffset>
              <bitWidth>1</bitWidth>
            </field>
            <field>
              <name>CC1NE</name>
              <bitOffset>2</bitOffset>
              <bitWidth>1</bitWidth>
            </field>
            <field>
              <name>CC1NP</name>
              <bitOffset>3</bitOffset>
              <bitWidth>1</bitWidth>
            </field>
            <field>
              <name>CC2E</name>
              <bitOffset>4</bitOffset>
              <bitWidth>1</bitWidth>
            </field>
            <field>
              <name>CC2P</name>
              <bitOffset>5</bitOffset>
              <bitWidth>1</bitWidth>
            </field>
            <field>
              <name>CC2NE</name>
              <bitOffset>6</bitOffset>
              <bitWidth>1</bitWidth>
            </field>
            <field>
              <name>CC2NP</name>
              <bitOffset>7</bitOffset>
              <bitWidth>1</bitWidth>
            </field>
            <field>
              <name>CC3E</name>
              <bitOffset>8</bitOffset>
              <bitWidth>1</bitWidth>
            </field>
            <field>
              <name>CC3P</name>
              <bitOffset>9</bitOffset>
              <bitWidth>1</bitWidth>
            </field>
            <field>
              <name>CC3NE</name>
              <bitOffset>10</bitOffset>
              <bitWidth>1</bitWidth>
            </field>
            <field>
              <name>CC3NP</name>
              <bitOffset>11</bitOffset>
              <bitWidth>1</bitWidth>
            </field>
            <field>
              <name>CC4E</name>
              <bitOffset>12</bitOffset>
              <bitWidth>1</bitWidth>
            </field>
            <field>
              <name>CC4P</name>
              <bitOffset>13</bitOffset>
              <bitWidth>1</bitWidth>
            </field>
            <field>
              <name>CC4NP</name>
              <bitOffset>15</bitOffset>
              <bitWidth>1</bitWidth>
            </field>
          </fields>
        </register>
        <register>
          <name>CNT</name>
          <addressOffset>0x24</addressOffset>
          <size>0x20</size>
          <fields>
            <field>
              <name>CNT</name>
              <bitOffset>0</bitOffset>
              <bitWidth>32</bitWidth>
            </field>
          </fields>
        </register>
        <register>
          <name>PSC</name>
          <addressOffset>0x28</addressOffset>
          <size>0x20</size>
          <fields>
            <field>
              <name>PSC</name>
              <bitOffset>0</bitOffset>
              <bitWidth>16</bitWidth>
            </field>
          </fields>
        </register>
        <register>
          <name>ARR</name>
          <addressOffset>0x2c</addressOffset>
          <size>0x20</size>
          <fields>
            <field>
              <name>ARR</name>
              <bitOffset>0</bitOffset>
              <bitWidth>32</bitWidth>
            </field>
          </fields>
        </register>
        <register>
          <name>RCR</name>
          <addressOffset>0x30</addressOffset>
          <size>0x20</size>
          <fields>
            <field>
              <name>REP</name>
              <bitOffset>0</bitOffset>
              <bitWidth>8</bitWidth>
            </field>
          </fields>
        </register>
        <register>
          <name>CCR1</name>
          <addressOffset>0x34</addressOffset>
          <size>0x20</size>
          <fields>
            <field>
              <name>CCR1</name>
              <bitOffset>0</bitOffset>
              <bitWidth>16</bitWidth>
            </field>
          </fields>
        </register>
        <register>
          <name>CCR2</name>
          <addressOffset>0x38</addressOffset>
          <size>0x20</size>
          <fields>
            <field>
              <name>CCR2</name>
              <bitOffset>0</bitOffset>
              <bitWidth>16</bitWidth>
            </field>
          </fields>
        </register>
        <register>
          <name>CCR3</name>
          <addressOffset>0x3c</addressOffset>
          <size>0x20</size>
          <fields>
            <field>
              <name>CCR3</name>
              <bitOffset>0</bitOffset>
              <bitWidth>16</bitWidth>
            </field>
          </fields>
        </register>
        <register>
          <name>CCR4</name>
          <addressOffset>0x40</addressOffset>
          <size>0x20</size>
          <fields>
            <field>
              <name>CCR4</name>
              <bitOffset>0</bitOffset>
              <bitWidth>16</bitWidth>
            </field>
          </fields>
        </register>
        <register>
          <name>BDTR</name>
          <addressOffset>0x44</addressOffset>
          <size>0x20</size>
          <fields>
            <field>
              <name>DTG</name>
              <bitOffset>0</bitOffset>
              <bitWidth>8</bitWidth>
            </field>
            <field>
              <name>LOCK</name>
              <bitOffset>8</bitOffset>
              <bitWidth>2</bitWidth>
            </field>
            <field>
              <name>OSSI</name>
              <bitOffset>10</bitOffset>
              <bitWidth>1</bitWidth>
            </field>
            <field>
              <name>OSSR</name>
              <bitOffset>11</bitOffset>
              <bitWidth>1</bitWidth>
            </field>
            <field>
              <name>BKE</name>
              <bitOffset>12</bitOffset>
              <bitWidth>1</bitWidth>
            </field>
            <field>
              <name>BKP</name>
              <bitOffset>13</bitOffset>
              <bitWidth>1</bitWidth>
            </field>
            <field>
              <name>AOE</name>
              <bitOffset>14</bitOffset>
              <bitWidth>1</bitWidth>
            </field>
            <field>
              <name>MOE</name>
              <bitOffset>15</bitOffset>
              <bitWidth>1</bitWidth>
            </field>
          </fields>
        </register>
        <register>
          <name>DCR</name>
          <addressOffset>0x48</addressOffset>
          <size>0x20</size>
          <fields>
            <field>
              <name>DBA</name>
              <bitOffset>0</bitOffset>
              <bitWidth>5</bitWidth>
            </field>
            <field>
              <name>DBL</name>
              <bitOffset>8</bitOffset>
              <bitWidth>5</bitWidth>
            </field>
          </fields>
        </register>
        <register>
          <name>DMAR</name>
          <addressOffset>0x4c</addressOffset>
          <size>0x20</size>
          <fields>
            <field>
              <name>DMAB</name>
              <bitOffset>0</bitOffset>
              <bitWidth>16</bitWidth>
            </field>
          </fields>
        </register>
        <register>
          <name>OR</name>
          <addressOffset>0x50</addressOffset>
          <size>0x20</size>
        </register>
      </registers>
    </peripheral>
    <peripheral>
      <name>TIM17</name>
      <baseAddress>0x40014800</baseAddress>
      <registers>
        <register>
          <name>CR1</name>
          <addressOffset>0x0</addressOffset>
          <size>0x20</size>
          <fields>
            <field>
              <name>CEN</name>
              <bitOffset>0</bitOffset>
              <bitWidth>1</bitWidth>
            </field>
            <field>
              <name>UDIS</name>
              <bitOffset>1</bitOffset>
              <bitWidth>1</bitWidth>
            </field>
            <field>
              <name>URS</name>
              <bitOffset>2</bitOffset>
              <bitWidth>1</bitWidth>
            </field>
            <field>
              <name>OPM</name>
              <bitOffset>3</bitOffset>
              <bitWidth>1</bitWidth>
            </field>
            <field>
              <name>DIR</name>
              <bitOffset>4</bitOffset>
              <bitWidth>1</bitWidth>
            </field>
            <field>
              <name>CMS</name>
              <bitOffset>5</bitOffset>
              <bitWidth>2</bitWidth>
            </field>
            <field>
              <name>ARPE</name>
              <bitOffset>7</bitOffset>
              <bitWidth>1</bitWidth>
            </field>
            <field>
              <name>CKD</name>
              <bitOffset>8</bitOffset>
              <bitWidth>2</bitWidth>
            </field>
          </fields>
        </register>
        <register>
          <name>CR2</name>
          <addressOffset>0x4</addressOffset>
          <size>0x20</size>
          <fields>
            <field>
              <name>CCPC</name>
              <bitOffset>0</bitOffset>
              <bitWidth>1</bitWidth>
            </field>
            <field>
              <name>CCUS</name>
              <bitOffset>2</bitOffset>
              <bitWidth>1</bitWidth>
            </field>
            <field>
              <name>CCDS</name>
              <bitOffset>3</bitOffset>
              <bitWidth>1</bitWidth>
            </field>
            <field>
              <name>MMS</name>
              <bitOffset>4</bitOffset>
              <bitWidth>3</bitWidth>
            </field>
            <field>
              <name>TI1S</name>
              <bitOffset>7</bitOffset>
              <bitWidth>1</bitWidth>
            </field>
            <field>
              <name>OIS1</name>
              <bitOffset>8</bitOffset>
              <bitWidth>1</bitWidth>
            </field>
            <field>
              <name>OIS1N</name>
              <bitOffset>9</bitOffset>
              <bitWidth>1</bitWidth>
            </field>
            <field>
              <name>OIS2</name>
              <bitOffset>10</bitOffset>
              <bitWidth>1</bitWidth>
            </field>
            <field>
              <name>OIS2N</name>
              <bitOffset>11</bitOffset>
              <bitWidth>1</bitWidth>
            </field>
            <field>
              <name>OIS3</name>
              <bitOffset>12</bitOffset>
              <bitWidth>1</bitWidth>
            </field>
            <field>
              <name>OIS3N</name>
              <bitOffset>13</bitOffset>
              <bitWidth>1</bitWidth>
            </field>
            <field>
              <name>OIS4</name>
              <bitOffset>14</bitOffset>
              <bitWidth>1</bitWidth>
            </field>
          </fields>
        </register>
        <register>
          <name>SMCR</name>
          <addressOffset>0x8</addressOffset>
          <size>0x20</size>
          <fields>
            <field>
              <name>SMS</name>
              <bitOffset>0</bitOffset>
              <bitWidth>3</bitWidth>
            </field>
            <field>
              <name>OCCS</name>
              <bitOffset>3</bitOffset>
              <bitWidth>1</bitWidth>
            </field>
            <field>
              <name>TS</name>
              <bitOffset>4</bitOffset>
              <bitWidth>3</bitWidth>
            </field>
            <field>
              <name>MSM</name>
              <bitOffset>7</bitOffset>
              <bitWidth>1</bitWidth>
            </field>
            <field>
              <name>ETF</name>
              <bitOffset>8</bitOffset>
              <bitWidth>4</bitWidth>
            </field>
            <field>
              <name>ETPS</name>
              <bitOffset>12</bitOffset>
              <bitWidth>2</bitWidth>
            </field>
            <field>
              <name>ECE</name>
              <bitOffset>14</bitOffset>
              <bitWidth>1</bitWidth>
            </field>
            <field>
              <name>ETP</name>
              <bitOffset>15</bitOffset>
              <bitWidth>1</bitWidth>
            </field>
          </fields>
        </register>
        <register>
          <name>DIER</name>
          <addressOffset>0xc</addressOffset>
          <size>0x20</size>
          <fields>
            <field>
              <name>UIE</name>
              <bitOffset>0</bitOffset>
              <bitWidth>1</bitWidth>
            </field>
            <field>
              <name>CC1IE</name>
              <bitOffset>1</bitOffset>
              <bitWidth>1</bitWidth>
            </field>
            <field>
              <name>CC2IE</name>
              <bitOffset>2</bitOffset>
              <bitWidth>1</bitWidth>
            </field>
            <field>
              <name>CC3IE</name>
              <bitOffset>3</bitOffset>
              <bitWidth>1</bitWidth>
            </field>
            <field>
              <name>CC4IE</name>
              <bitOffset>4</bitOffset>
              <bitWidth>1</bitWidth>
            </field>
            <field>
              <name>COMIE</name>
              <bitOffset>5</bitOffset>
              <bitWidth>1</bitWidth>
            </field>
            <field>
              <name>TIE</name>
              <bitOffset>6</bitOffset>
              <bitWidth>1</bitWidth>
            </field>
            <field>
              <name>BIE</name>
              <bitOffset>7</bitOffset>
              <bitWidth>1</bitWidth>
            </field>
            <field>
              <name>UDE</name>
              <bitOffset>8</bitOffset>
              <bitWidth>1</bitWidth>
            </field>
            <field>
              <name>CC1DE</name>
              <bitOffset>9</bitOffset>
              <bitWidth>1</bitWidth>
            </field>
            <field>
              <name>CC2DE</name>
              <bitOffset>10</bitOffset>
              <bitWidth>1</bitWidth>
            </field>
            <field>
              <name>CC3DE</name>
              <bitOffset>11</bitOffset>
              <bitWidth>1</bitWidth>
            </field>
            <field>
              <name>CC4DE</name>
              <bitOffset>12</bitOffset>
              <bitWidth>1</bitWidth>
            </field>
            <field>
              <name>COMDE</name>
              <bitOffset>13</bitOffset>
              <bitWidth>1</bitWidth>
            </field>
            <field>
              <name>TDE</name>
              <bitOffset>14</bitOffset>
              <bitWidth>1</bitWidth>
            </field>
          </fields>
        </register>
        <register>
          <name>SR</name>
          <addressOffset>0x10</addressOffset>
          <size>0x20</size>
          <fields>
            <field>
              <name>UIF</name>
              <bitOffset>0</bitOffset>
              <bitWidth>1</bitWidth>
            </field>
            <field>
              <name>CC1IF</name>
              <bitOffset>1</bitOffset>
              <bitWidth>1</bitWidth>
            </field>
            <field>
              <name>CC2IF</name>
              <bitOffset>2</bitOffset>
              <bitWidth>1</bitWidth>
            </field>
            <field>
              <name>CC3IF</name>
              <bitOffset>3</bitOffset>
              <bitWidth>1</bitWidth>
            </field>
            <field>
              <name>CC4IF</name>
              <bitOffset>4</bitOffset>
              <bitWidth>1</bitWidth>
            </field>
            <field>
              <name>COMIF</name>
              <bitOffset>5</bitOffset>
              <bitWidth>1</bitWidth>
            </field>
            <field>
              <name>TIF</name>
              <bitOffset>6</bitOffset>
              <bitWidth>1</bitWidth>
            </field>
            <field>
              <name>BIF</name>
              <bitOffset>7</bitOffset>
              <bitWidth>1</bitWidth>
            </field>
            <field>
              <name>CC1OF</name>
              <bitOffset>9</bitOffset>
              <bitWidth>1</bitWidth>
            </field>
            <field>
              <name>CC2OF</name>
              <bitOffset>10</bitOffset>
              <bitWidth>1</bitWidth>
            </field>
            <field>
              <name>CC3OF</name>
              <bitOffset>11</bitOffset>
              <bitWidth>1</bitWidth>
            </field>
            <field>
              <name>CC4OF</name>
              <bitOffset>12</bitOffset>
              <bitWidth>1</bitWidth>
            </field>
          </fields>
        </register>
        <register>
          <name>EGR</name>
          <addressOffset>0x14</addressOffset>
          <size>0x20</size>
          <fields>
            <field>
              <name>UG</name>
              <bitOffset>0</bitOffset>
              <bitWidth>1</bitWidth>
            </field>
            <field>
              <name>CC1G</name>
              <bitOffset>1</bitOffset>
              <bitWidth>1</bitWidth>
            </field>
            <field>
              <name>CC2G</name>
              <bitOffset>2</bitOffset>
              <bitWidth>1</bitWidth>
            </field>
            <field>
              <name>CC3G</name>
              <bitOffset>3</bitOffset>
              <bitWidth>1</bitWidth>
            </field>
            <field>
              <name>CC4G</name>
              <bitOffset>4</bitOffset>
              <bitWidth>1</bitWidth>
            </field>
            <field>
              <name>COMG</name>
              <bitOffset>5</bitOffset>
              <bitWidth>1</bitWidth>
            </field>
            <field>
              <name>TG</name>
              <bitOffset>6</bitOffset>
              <bitWidth>1</bitWidth>
            </field>
            <field>
              <name>BG</name>
              <bitOffset>7</bitOffset>
              <bitWidth>1</bitWidth>
            </field>
          </fields>
        </register>
        <register>
          <name>CCMR1</name>
          <addressOffset>0x18</addressOffset>
          <size>0x20</size>
          <fields>
            <field>
              <name>CC1S</name>
              <bitOffset>0</bitOffset>
              <bitWidth>2</bitWidth>
            </field>
            <field>
              <name>OC1FE</name>
              <bitOffset>2</bitOffset>
              <bitWidth>1</bitWidth>
            </field>
            <field>
              <name>OC1PE</name>
              <bitOffset>3</bitOffset>
              <bitWidth>1</bitWidth>
            </field>
            <field>
              <name>OC1M</name>
              <bitOffset>4</bitOffset>
              <bitWidth>3</bitWidth>
            </field>
            <field>
              <name>OC1CE</name>
              <bitOffset>7</bitOffset>
              <bitWidth>1</bitWidth>
            </field>
            <field>
              <name>CC2S</name>
              <bitOffset>8</bitOffset>
              <bitWidth>2</bitWidth>
            </field>
            <field>
              <name>OC2FE</name>
              <bitOffset>10</bitOffset>
              <bitWidth>1</bitWidth>
            </field>
            <field>
              <name>OC2PE</name>
              <bitOffset>11</bitOffset>
              <bitWidth>1</bitWidth>
            </field>
            <field>
              <name>OC2M</name>
              <bitOffset>12</bitOffset>
              <bitWidth>3</bitWidth>
            </field>
            <field>
              <name>OC2CE</name>
              <bitOffset>15</bitOffset>
              <bitWidth>1</bitWidth>
            </field>
          </fields>
        </register>
        <register>
          <name>CCMR2</name>
          <addressOffset>0x1c</addressOffset>
          <size>0x20</size>
          <fields>
            <field>
              <name>CC3S</name>
              <bitOffset>0</bitOffset>
              <bitWidth>2</bitWidth>
            </field>
            <field>
              <name>OC3FE</name>
              <bitOffset>2</bitOffset>
              <bitWidth>1</bitWidth>
            </field>
            <field>
              <name>OC3PE</name>
              <bitOffset>3</bitOffset>
              <bitWidth>1</bitWidth>
            </field>
            <field>
              <name>OC3M</name>
              <bitOffset>4</bitOffset>
              <bitWidth>3</bitWidth>
            </field>
            <field>
              <name>OC3CE</name>
              <bitOffset>7</bitOffset>
              <bitWidth>1</bitWidth>
            </field>
            <field>
              <name>CC4S</name>
              <bitOffset>8</bitOffset>
              <bitWidth>2</bitWidth>
            </field>
            <field>
              <name>OC4FE</name>
              <bitOffset>10</bitOffset>
              <bitWidth>1</bitWidth>
            </field>
            <field>
              <name>OC4PE</name>
              <bitOffset>11</bitOffset>
              <bitWidth>1</bitWidth>
            </field>
            <field>
              <name>OC4M</name>
              <bitOffset>12</bitOffset>
              <bitWidth>3</bitWidth>
            </field>
            <field>
              <name>OC4CE</name>
              <bitOffset>15</bitOffset>
              <bitWidth>1</bitWidth>
            </field>
          </fields>
        </register>
        <register>
          <name>CCER</name>
          <addressOffset>0x20</addressOffset>
          <size>0x20</size>
          <fields>
            <field>
              <name>CC1E</name>
              <bitOffset>0</bitOffset>
              <bitWidth>1</bitWidth>
            </field>
            <field>
              <name>CC1P</name>
              <bitOffset>1</bitOffset>
              <bitWidth>1</bitWidth>
            </field>
            <field>
              <name>CC1NE</name>
              <bitOffset>2</bitOffset>
              <bitWidth>1</bitWidth>
            </field>
            <field>
              <name>CC1NP</name>
              <bitOffset>3</bitOffset>
              <bitWidth>1</bitWidth>
            </field>
            <field>
              <name>CC2E</name>
              <bitOffset>4</bitOffset>
              <bitWidth>1</bitWidth>
            </field>
            <field>
              <name>CC2P</name>
              <bitOffset>5</bitOffset>
              <bitWidth>1</bitWidth>
            </field>
            <field>
              <name>CC2NE</name>
              <bitOffset>6</bitOffset>
              <bitWidth>1</bitWidth>
            </field>
            <field>
              <name>CC2NP</name>
              <bitOffset>7</bitOffset>
              <bitWidth>1</bitWidth>
            </field>
            <field>
              <name>CC3E</name>
              <bitOffset>8</bitOffset>
              <bitWidth>1</bitWidth>
            </field>
            <field>
              <name>CC3P</name>
              <bitOffset>9</bitOffset>
              <bitWidth>1</bitWidth>
            </field>
            <field>
              <name>CC3NE</name>
              <bitOffset>10</bitOffset>
              <bitWidth>1</bitWidth>
            </field>
            <field>
              <name>CC3NP</name>
              <bitOffset>11</bitOffset>
              <bitWidth>1</bitWidth>
            </field>
            <field>
              <name>CC4E</name>
              <bitOffset>12</bitOffset>
              <bitWidth>1</bitWidth>
            </field>
            <field>
              <name>CC4P</name>
              <bitOffset>13</bitOffset>
              <bitWidth>1</bitWidth>
            </field>
            <field>
              <name>CC4NP</name>
              <bitOffset>15</bitOffset>
              <bitWidth>1</bitWidth>
            </field>
          </fields>
        </register>
        <register>
          <name>CNT</name>
          <addressOffset>0x24</addressOffset>
          <size>0x20</size>
          <fields>
            <field>
              <name>CNT</name>
              <bitOffset>0</bitOffset>
              <bitWidth>32</bitWidth>
            </field>
          </fields>
        </register>
        <register>
          <name>PSC</name>
          <addressOffset>0x28</addressOffset>
          <size>0x20</size>
          <fields>
            <field>
              <name>PSC</name>
              <bitOffset>0</bitOffset>
              <bitWidth>16</bitWidth>
            </field>
          </fields>
        </register>
        <register>
          <name>ARR</name>
          <addressOffset>0x2c</addressOffset>
          <size>0x20</size>
          <fields>
            <field>
              <name>ARR</name>
              <bitOffset>0</bitOffset>
              <bitWidth>32</bitWidth>
            </field>
          </fields>
        </register>
        <register>
          <name>RCR</name>
          <addressOffset>0x30</addressOffset>
          <size>0x20</size>
          <fields>
            <field>
              <name>REP</name>
              <bitOffset>0</bitOffset>
              <bitWidth>8</bitWidth>
            </field>
          </fields>
        </register>
        <register>
          <name>CCR1</name>
          <addressOffset>0x34</addressOffset>
          <size>0x20</size>
          <fields>
            <field>
              <name>CCR1</name>
              <bitOffset>0</bitOffset>
              <bitWidth>16</bitWidth>
            </field>
          </fields>
        </register>
        <register>
          <name>CCR2</name>
          <addressOffset>0x38</addressOffset>
          <size>0x20</size>
          <fields>
            <field>
              <name>CCR2</name>
              <bitOffset>0</bitOffset>
              <bitWidth>16</bitWidth>
            </field>
          </fields>
        </register>
        <register>
          <name>CCR3</name>
          <addressOffset>0x3c</addressOffset>
          <size>0x20</size>
          <fields>
            <field>
              <name>CCR3</name>
              <bitOffset>0</bitOffset>
              <bitWidth>16</bitWidth>
            </field>
          </fields>
        </register>
        <register>
          <name>CCR4</name>
          <addressOffset>0x40</addressOffset>
          <size>0x20</size>
          <fields>
            <field>
              <name>CCR4</name>
              <bitOffset>0</bitOffset>
              <bitWidth>16</bitWidth>
            </field>
          </fields>
        </register>
        <register>
          <name>BDTR</name>
          <addressOffset>0x44</addressOffset>
          <size>0x20</size>
          <fields>
            <field>
              <name>DTG</name>
              <bitOffset>0</bitOffset>
              <bitWidth>8</bitWidth>
            </field>
            <field>
              <name>LOCK</name>
              <bitOffset>8</bitOffset>
              <bitWidth>2</bitWidth>
            </field>
            <field>
              <name>OSSI</name>
              <bitOffset>10</bitOffset>
              <bitWidth>1</bitWidth>
            </field>
            <field>
              <name>OSSR</name>
              <bitOffset>11</bitOffset>
              <bitWidth>1</bitWidth>
            </field>
            <field>
              <name>BKE</name>
              <bitOffset>12</bitOffset>
              <bitWidth>1</bitWidth>
            </field>
            <field>
              <name>BKP</name>
              <bitOffset>13</bitOffset>
              <bitWidth>1</bitWidth>
            </field>
            <field>
              <name>AOE</name>
              <bitOffset>14</bitOffset>
              <bitWidth>1</bitWidth>
            </field>
            <field>
              <name>MOE</name>
              <bitOffset>15</bitOffset>
              <bitWidth>1</bitWidth>
            </field>
          </fields>
        </register>
        <register>
          <name>DCR</name>
          <addressOffset>0x48</addressOffset>
          <size>0x20</size>
          <fields>
            <field>
              <name>DBA</name>
              <bitOffset>0</bitOffset>
              <bitWidth>5</bitWidth>
            </field>
            <field>
              <name>DBL</name>
              <bitOffset>8</bitOffset>
              <bitWidth>5</bitWidth>
            </field>
          </fields>
        </register>
        <register>
          <name>DMAR</name>
          <addressOffset>0x4c</addressOffset>
          <size>0x20</size>
          <fields>
            <field>
              <name>DMAB</name>
              <bitOffset>0</bitOffset>
              <bitWidth>16</bitWidth>
            </field>
          </fields>
        </register>
        <register>
          <name>OR</name>
          <addressOffset>0x50</addressOffset>
          <size>0x20</size>
        </register>
      </registers>
    </peripheral>
    <peripheral>
      <name>DBGMCU</name>
      <baseAddress>0x40015800</baseAddress>
      <registers>
        <register>
          <name>IDCODE</name>
          <addressOffset>0x0</addressOffset>
          <size>0x20</size>
          <fields>
            <field>
              <name>DEV_ID</name>
              <bitOffset>0</bitOffset>
              <bitWidth>12</bitWidth>
            </field>
            <field>
              <name>REV_ID</name>
              <bitOffset>16</bitOffset>
              <bitWidth>16</bitWidth>
            </field>
          </fields>
        </register>
        <register>
          <name>CR</name>
          <addressOffset>0x4</addressOffset>
          <size>0x20</size>
          <fields>
            <field>
              <name>DBG_STOP</name>
              <bitOffset>1</bitOffset>
              <bitWidth>1</bitWidth>
            </field>
            <field>
              <name>DBG_STANDBY</name>
              <bitOffset>2</bitOffset>
              <bitWidth>1</bitWidth>
            </field>
          </fields>
        </register>
        <register>
          <name>APB1FZ</name>
          <addressOffset>0x8</addressOffset>
          <size>0x20</size>
          <fields>
            <field>
              <name>DBG_TIM2_STOP</name>
              <bitOffset>0</bitOffset>
              <bitWidth>1</bitWidth>
            </field>
            <field>
              <name>DBG_TIM3_STOP</name>
              <bitOffset>1</bitOffset>
              <bitWidth>1</bitWidth>
            </field>
            <field>
              <name>DBG_TIM6_STOP</name>
              <bitOffset>4</bitOffset>
              <bitWidth>1</bitWidth>
            </field>
            <field>
              <name>DBG_TIM7_STOP</name>
              <bitOffset>5</bitOffset>
              <bitWidth>1</bitWidth>
            </field>
            <field>
              <name>DBG_TIM14_STOP</name>
              <bitOffset>8</bitOffset>
              <bitWidth>1</bitWidth>
            </field>
            <field>
              <name>DBG_RTC_STOP</name>
              <bitOffset>10</bitOffset>
              <bitWidth>1</bitWidth>
            </field>
            <field>
              <name>DBG_WWDG_STOP</name>
              <bitOffset>11</bitOffset>
              <bitWidth>1</bitWidth>
            </field>
            <field>
              <name>DBG_IWDG_STOP</name>
              <bitOffset>12</bitOffset>
              <bitWidth>1</bitWidth>
            </field>
            <field>
              <name>DBG_I2C1_SMBUS_TIMEOUT</name>
              <bitOffset>21</bitOffset>
              <bitWidth>1</bitWidth>
            </field>
            <field>
              <name>DBG_CAN_STOP</name>
              <bitOffset>25</bitOffset>
              <bitWidth>1</bitWidth>
            </field>
          </fields>
        </register>
        <register>
          <name>APB2FZ</name>
          <addressOffset>0xc</addressOffset>
          <size>0x20</size>
          <fields>
            <field>
              <name>DBG_TIM1_STOP</name>
              <bitOffset>11</bitOffset>
              <bitWidth>1</bitWidth>
            </field>
            <field>
              <name>DBG_TIM15_STOP</name>
              <bitOffset>16</bitOffset>
              <bitWidth>1</bitWidth>
            </field>
            <field>
              <name>DBG_TIM16_STOP</name>
              <bitOffset>17</bitOffset>
              <bitWidth>1</bitWidth>
            </field>
            <field>
              <name>DBG_TIM17_STOP</name>
              <bitOffset>18</bitOffset>
              <bitWidth>1</bitWidth>
            </field>
          </fields>
        </register>
      </registers>
    </peripheral>
    <peripheral>
      <name>DMA1</name>
      <baseAddress>0x40020000</baseAddress>
      <registers>
        <register>
          <name>ISR</name>
          <addressOffset>0x0</addressOffset>
          <size>0x20</size>
          <fields>
            <field>
              <name>GIF1</name>
              <bitOffset>0</bitOffset>
              <bitWidth>1</bitWidth>
            </field>
            <field>
              <name>TCIF1</name>
              <bitOffset>1</bitOffset>
              <bitWidth>1</bitWidth>
            </field>
            <field>
              <name>HTIF1</name>
              <bitOffset>2</bitOffset>
              <bitWidth>1</bitWidth>
            </field>
            <field>
              <name>TEIF1</name>
              <bitOffset>3</bitOffset>
              <bitWidth>1</bitWidth>
            </field>
            <field>
              <name>GIF2</name>
              <bitOffset>4</bitOffset>
              <bitWidth>1</bitWidth>
            </field>
            <field>
              <name>TCIF2</name>
              <bitOffset>5</bitOffset>
              <bitWidth>1</bitWidth>
            </field>
            <field>
              <name>HTIF2</name>
              <bitOffset>6</bitOffset>
              <bitWidth>1</bitWidth>
            </field>
            <field>
              <name>TEIF2</name>
              <bitOffset>7</bitOffset>
              <bitWidth>1</bitWidth>
            </field>
            <field>
              <name>GIF3</name>
              <bitOffset>8</bitOffset>
              <bitWidth>1</bitWidth>
            </field>
            <field>
              <name>TCIF3</name>
              <bitOffset>9</bitOffset>
              <bitWidth>1</bitWidth>
            </field>
            <field>
              <name>HTIF3</name>
              <bitOffset>10</bitOffset>
              <bitWidth>1</bitWidth>
            </field>
            <field>
              <name>TEIF3</name>
              <bitOffset>11</bitOffset>
              <bitWidth>1</bitWidth>
            </field>
            <field>
              <name>GIF4</name>
              <bitOffset>12</bitOffset>
              <bitWidth>1</bitWidth>
            </field>
            <field>
              <name>TCIF4</name>
              <bitOffset>13</bitOffset>
              <bitWidth>1</bitWidth>
            </field>
            <field>
              <name>HTIF4</name>
              <bitOffset>14</bitOffset>
              <bitWidth>1</bitWidth>
            </field>
            <field>
              <name>TEIF4</name>
              <bitOffset>15</bitOffset>
              <bitWidth>1</bitWidth>
            </field>
            <field>
              <name>GIF5</name>
              <bitOffset>16</bitOffset>
              <bitWidth>1</bitWidth>
            </field>
            <field>
              <name>TCIF5</name>
              <bitOffset>17</bitOffset>
              <bitWidth>1</bitWidth>
            </field>
            <field>
              <name>HTIF5</name>
              <bitOffset>18</bitOffset>
              <bitWidth>1</bitWidth>
            </field>
            <field>
              <name>TEIF5</name>
              <bitOffset>19</bitOffset>
              <bitWidth>1</bitWidth>
            </field>
            <field>
              <name>GIF6</name>
              <bitOffset>20</bitOffset>
              <bitWidth>1</bitWidth>
            </field>
            <field>
              <name>TCIF6</name>
              <bitOffset>21</bitOffset>
              <bitWidth>1</bitWidth>
            </field>
            <field>
              <name>HTIF6</name>
              <bitOffset>22</bitOffset>
              <bitWidth>1</bitWidth>
            </field>
            <field>
              <name>TEIF6</name>
              <bitOffset>23</bitOffset>
              <bitWidth>1</bitWidth>
            </field>
            <field>
              <name>GIF7</name>
              <bitOffset>24</bitOffset>
              <bitWidth>1</bitWidth>
            </field>
            <field>
              <name>TCIF7</name>
              <bitOffset>25</bitOffset>
              <bitWidth>1</bitWidth>
            </field>
            <field>
              <name>HTIF7</name>
              <bitOffset>26</bitOffset>
              <bitWidth>1</bitWidth>
            </field>
            <field>
              <name>TEIF7</name>
              <bitOffset>27</bitOffset>
              <bitWidth>1</bitWidth>
            </field>
          </fields>
        </register>
        <register>
          <name>IFCR</name>
          <addressOffset>0x4</addressOffset>
          <size>0x20</size>
          <fields>
            <field>
              <name>CGIF1</name>
              <bitOffset>0</bitOffset>
              <bitWidth>1</bitWidth>
            </field>
            <field>
              <name>CTCIF1</name>
              <bitOffset>1</bitOffset>
              <bitWidth>1</bitWidth>
            </field>
            <field>
              <name>CHTIF1</name>
              <bitOffset>2</bitOffset>
              <bitWidth>1</bitWidth>
            </field>
            <field>
              <name>CTEIF1</name>
              <bitOffset>3</bitOffset>
              <bitWidth>1</bitWidth>
            </field>
            <field>
              <name>CGIF2</name>
              <bitOffset>4</bitOffset>
              <bitWidth>1</bitWidth>
            </field>
            <field>
              <name>CTCIF2</name>
              <bitOffset>5</bitOffset>
              <bitWidth>1</bitWidth>
            </field>
            <field>
              <name>CHTIF2</name>
              <bitOffset>6</bitOffset>
              <bitWidth>1</bitWidth>
            </field>
            <field>
              <name>CTEIF2</name>
              <bitOffset>7</bitOffset>
              <bitWidth>1</bitWidth>
            </field>
            <field>
              <name>CGIF3</name>
              <bitOffset>8</bitOffset>
              <bitWidth>1</bitWidth>
            </field>
            <field>
              <name>CTCIF3</name>
              <bitOffset>9</bitOffset>
              <bitWidth>1</bitWidth>
            </field>
            <field>
              <name>CHTIF3</name>
              <bitOffset>10</bitOffset>
              <bitWidth>1</bitWidth>
            </field>
            <field>
              <name>CTEIF3</name>
              <bitOffset>11</bitOffset>
              <bitWidth>1</bitWidth>
            </field>
            <field>
              <name>CGIF4</name>
              <bitOffset>12</bitOffset>
              <bitWidth>1</bitWidth>
            </field>
            <field>
              <name>CTCIF4</name>
              <bitOffset>13</bitOffset>
              <bitWidth>1</bitWidth>
            </field>
            <field>
              <name>CHTIF4</name>
              <bitOffset>14</bitOffset>
              <bitWidth>1</bitWidth>
            </field>
            <field>
              <name>CTEIF4</name>
              <bitOffset>15</bitOffset>
              <bitWidth>1</bitWidth>
            </field>
            <field>
              <name>CGIF5</name>
              <bitOffset>16</bitOffset>
              <bitWidth>1</bitWidth>
            </field>
            <field>
              <name>CTCIF5</name>
              <bitOffset>17</bitOffset>
              <bitWidth>1</bitWidth>
            </field>
            <field>
              <name>CHTIF5</name>
              <bitOffset>18</bitOffset>
              <bitWidth>1</bitWidth>
            </field>
            <field>
              <name>CTEIF5</name>
              <bitOffset>19</bitOffset>
              <bitWidth>1</bitWidth>
            </field>
            <field>
              <name>CGIF6</name>
              <bitOffset>20</bitOffset>
              <bitWidth>1</bitWidth>
            </field>
            <field>
              <name>CTCIF6</name>
              <bitOffset>21</bitOffset>
              <bitWidth>1</bitWidth>
            </field>
            <field>
              <name>CHTIF6</name>
              <bitOffset>22</bitOffset>
              <bitWidth>1</bitWidth>
            </field>
            <field>
              <name>CTEIF6</name>
              <bitOffset>23</bitOffset>
              <bitWidth>1</bitWidth>
            </field>
            <field>
              <name>CGIF7</name>
              <bitOffset>24</bitOffset>
              <bitWidth>1</bitWidth>
            </field>
            <field>
              <name>CTCIF7</name>
              <bitOffset>25</bitOffset>
              <bitWidth>1</bitWidth>
            </field>
            <field>
              <name>CHTIF7</name>
              <bitOffset>26</bitOffset>
              <bitWidth>1</bitWidth>
            </field>
            <field>
              <name>CTEIF7</name>
              <bitOffset>27</bitOffset>
              <bitWidth>1</bitWidth>
            </field>
          </fields>
        </register>
        <register>
          <name>CCR1</name>
          <addressOffset>0x8</addressOffset>
          <size>0x20</size>
          <fields>
            <field>
              <name>EN</name>
              <bitOffset>0</bitOffset>
              <bitWidth>1</bitWidth>
            </field>
            <field>
              <name>TCIE</name>
              <bitOffset>1</bitOffset>
              <bitWidth>1</bitWidth>
            </field>
            <field>
              <name>HTIE</name>
              <bitOffset>2</bitOffset>
              <bitWidth>1</bitWidth>
            </field>
            <field>
              <name>TEIE</name>
              <bitOffset>3</bitOffset>
              <bitWidth>1</bitWidth>
            </field>
            <field>
              <name>DIR</name>
              <bitOffset>4</bitOffset>
              <bitWidth>1</bitWidth>
            </field>
            <field>
              <name>CIRC</name>
              <bitOffset>5</bitOffset>
              <bitWidth>1</bitWidth>
            </field>
            <field>
              <name>PINC</name>
              <bitOffset>6</bitOffset>
              <bitWidth>1</bitWidth>
            </field>
            <field>
              <name>MINC</name>
              <bitOffset>7</bitOffset>
              <bitWidth>1</bitWidth>
            </field>
            <field>
              <name>PSIZE</name>
              <bitOffset>8</bitOffset>
              <bitWidth>2</bitWidth>
            </field>
            <field>
              <name>MSIZE</name>
              <bitOffset>10</bitOffset>
              <bitWidth>2</bitWidth>
            </field>
            <field>
              <name>PL</name>
              <bitOffset>12</bitOffset>
              <bitWidth>2</bitWidth>
            </field>
            <field>
              <name>MEM2MEM</name>
              <bitOffset>14</bitOffset>
              <bitWidth>1</bitWidth>
            </field>
          </fields>
        </register>
        <register>
          <name>CNDTR1</name>
          <addressOffset>0xc</addressOffset>
          <size>0x20</size>
          <fields>
            <field>
              <name>NDT</name>
              <bitOffset>0</bitOffset>
              <bitWidth>16</bitWidth>
            </field>
          </fields>
        </register>
        <register>
          <name>CPAR1</name>
          <addressOffset>0x10</addressOffset>
          <size>0x20</size>
          <fields>
            <field>
              <name>PA</name>
              <bitOffset>0</bitOffset>
              <bitWidth>32</bitWidth>
            </field>
          </fields>
        </register>
        <register>
          <name>CMAR1</name>
          <addressOffset>0x14</addressOffset>
          <size>0x20</size>
          <fields>
            <field>
              <name>MA</name>
              <bitOffset>0</bitOffset>
              <bitWidth>32</bitWidth>
            </field>
          </fields>
        </register>
        <register>
          <name>CCR2</name>
          <addressOffset>0x1c</addressOffset>
          <size>0x20</size>
          <fields>
            <field>
              <name>EN</name>
              <bitOffset>0</bitOffset>
              <bitWidth>1</bitWidth>
            </field>
            <field>
              <name>TCIE</name>
              <bitOffset>1</bitOffset>
              <bitWidth>1</bitWidth>
            </field>
            <field>
              <name>HTIE</name>
              <bitOffset>2</bitOffset>
              <bitWidth>1</bitWidth>
            </field>
            <field>
              <name>TEIE</name>
              <bitOffset>3</bitOffset>
              <bitWidth>1</bitWidth>
            </field>
            <field>
              <name>DIR</name>
              <bitOffset>4</bitOffset>
              <bitWidth>1</bitWidth>
            </field>
            <field>
              <name>CIRC</name>
              <bitOffset>5</bitOffset>
              <bitWidth>1</bitWidth>
            </field>
            <field>
              <name>PINC</name>
              <bitOffset>6</bitOffset>
              <bitWidth>1</bitWidth>
            </field>
            <field>
              <name>MINC</name>
              <bitOffset>7</bitOffset>
              <bitWidth>1</bitWidth>
            </field>
            <field>
              <name>PSIZE</name>
              <bitOffset>8</bitOffset>
              <bitWidth>2</bitWidth>
            </field>
            <field>
              <name>MSIZE</name>
              <bitOffset>10</bitOffset>
              <bitWidth>2</bitWidth>
            </field>
            <field>
              <name>PL</name>
              <bitOffset>12</bitOffset>
              <bitWidth>2</bitWidth>
            </field>
            <field>
              <name>MEM2MEM</name>
              <bitOffset>14</bitOffset>
              <bitWidth>1</bitWidth>
            </field>
          </fields>
        </register>
        <register>
          <name>CNDTR2</name>
          <addressOffset>0x20</addressOffset>
          <size>0x20</size>
          <fields>
            <field>
              <name>NDT</name>
              <bitOffset>0</bitOffset>
              <bitWidth>16</bitWidth>
            </field>
          </fields>
        </register>
        <register>
          <name>CPAR2</name>
          <addressOffset>0x24</addressOffset>
          <size>0x20</size>
          <fields>
            <field>
              <name>PA</name>
              <bitOffset>0</bitOffset>
              <bitWidth>32</bitWidth>
            </field>
          </fields>
        </register>
        <register>
          <name>CMAR2</name>
          <addressOffset>0x28</addressOffset>
          <size>0x20</size>
          <fields>
            <field>
              <name>MA</name>
              <bitOffset>0</bitOffset>
              <bitWidth>32</bitWidth>
            </field>
          </fields>
        </register>
        <register>
          <name>CCR3</name>
          <addressOffset>0x30</addressOffset>
          <size>0x20</size>
          <fields>
            <field>
              <name>EN</name>
              <bitOffset>0</bitOffset>
              <bitWidth>1</bitWidth>
            </field>
            <field>
              <name>TCIE</name>
              <bitOffset>1</bitOffset>
              <bitWidth>1</bitWidth>
            </field>
            <field>
              <name>HTIE</name>
              <bitOffset>2</bitOffset>
              <bitWidth>1</bitWidth>
            </field>
            <field>
              <name>TEIE</name>
              <bitOffset>3</bitOffset>
              <bitWidth>1</bitWidth>
            </field>
            <field>
              <name>DIR</name>
              <bitOffset>4</bitOffset>
              <bitWidth>1</bitWidth>
            </field>
            <field>
              <name>CIRC</name>
              <bitOffset>5</bitOffset>
              <bitWidth>1</bitWidth>
            </field>
            <field>
              <name>PINC</name>
              <bitOffset>6</bitOffset>
              <bitWidth>1</bitWidth>
            </field>
            <field>
              <name>MINC</name>
              <bitOffset>7</bitOffset>
              <bitWidth>1</bitWidth>
            </field>
            <field>
              <name>PSIZE</name>
              <bitOffset>8</bitOffset>
              <bitWidth>2</bitWidth>
            </field>
            <field>
              <name>MSIZE</name>
              <bitOffset>10</bitOffset>
              <bitWidth>2</bitWidth>
            </field>
            <field>
              <name>PL</name>
              <bitOffset>12</bitOffset>
              <bitWidth>2</bitWidth>
            </field>
            <field>
              <name>MEM2MEM</name>
              <bitOffset>14</bitOffset>
              <bitWidth>1</bitWidth>
            </field>
          </fields>
        </register>
        <register>
          <name>CNDTR3</name>
          <addressOffset>0x34</addressOffset>
          <size>0x20</size>
          <fields>
            <field>
              <name>NDT</name>
              <bitOffset>0</bitOffset>
              <bitWidth>16</bitWidth>
            </field>
          </fields>
        </register>
        <register>
          <name>CPAR3</name>
          <addressOffset>0x38</addressOffset>
          <size>0x20</size>
          <fields>
            <field>
              <name>PA</name>
              <bitOffset>0</bitOffset>
              <bitWidth>32</bitWidth>
            </field>
          </fields>
        </register>
        <register>
          <name>CMAR3</name>
          <addressOffset>0x3c</addressOffset>
          <size>0x20</size>
          <fields>
            <field>
              <name>MA</name>
              <bitOffset>0</bitOffset>
              <bitWidth>32</bitWidth>
            </field>
          </fields>
        </register>
        <register>
          <name>CCR4</name>
          <addressOffset>0x44</addressOffset>
          <size>0x20</size>
          <fields>
            <field>
              <name>EN</name>
              <bitOffset>0</bitOffset>
              <bitWidth>1</bitWidth>
            </field>
            <field>
              <name>TCIE</name>
              <bitOffset>1</bitOffset>
              <bitWidth>1</bitWidth>
            </field>
            <field>
              <name>HTIE</name>
              <bitOffset>2</bitOffset>
              <bitWidth>1</bitWidth>
            </field>
            <field>
              <name>TEIE</name>
              <bitOffset>3</bitOffset>
              <bitWidth>1</bitWidth>
            </field>
            <field>
              <name>DIR</name>
              <bitOffset>4</bitOffset>
              <bitWidth>1</bitWidth>
            </field>
            <field>
              <name>CIRC</name>
              <bitOffset>5</bitOffset>
              <bitWidth>1</bitWidth>
            </field>
            <field>
              <name>PINC</name>
              <bitOffset>6</bitOffset>
              <bitWidth>1</bitWidth>
            </field>
            <field>
              <name>MINC</name>
              <bitOffset>7</bitOffset>
              <bitWidth>1</bitWidth>
            </field>
            <field>
              <name>PSIZE</name>
              <bitOffset>8</bitOffset>
              <bitWidth>2</bitWidth>
            </field>
            <field>
              <name>MSIZE</name>
              <bitOffset>10</bitOffset>
              <bitWidth>2</bitWidth>
            </field>
            <field>
              <name>PL</name>
              <bitOffset>12</bitOffset>
              <bitWidth>2</bitWidth>
            </field>
            <field>
              <name>MEM2MEM</name>
              <bitOffset>14</bitOffset>
              <bitWidth>1</bitWidth>
            </field>
          </fields>
        </register>
        <register>
          <name>CNDTR4</name>
          <addressOffset>0x48</addressOffset>
          <size>0x20</size>
          <fields>
            <field>
              <name>NDT</name>
              <bitOffset>0</bitOffset>
              <bitWidth>16</bitWidth>
            </field>
          </fields>
        </register>
        <register>
          <name>CPAR4</name>
          <addressOffset>0x4c</addressOffset>
          <size>0x20</size>
          <fields>
            <field>
              <name>PA</name>
              <bitOffset>0</bitOffset>
              <bitWidth>32</bitWidth>
            </field>
          </fields>
        </register>
        <register>
          <name>CMAR4</name>
          <addressOffset>0x50</addressOffset>
          <size>0x20</size>
          <fields>
            <field>
              <name>MA</name>
              <bitOffset>0</bitOffset>
              <bitWidth>32</bitWidth>
            </field>
          </fields>
        </register>
        <register>
          <name>CCR5</name>
          <addressOffset>0x58</addressOffset>
          <size>0x20</size>
          <fields>
            <field>
              <name>EN</name>
              <bitOffset>0</bitOffset>
              <bitWidth>1</bitWidth>
            </field>
            <field>
              <name>TCIE</name>
              <bitOffset>1</bitOffset>
              <bitWidth>1</bitWidth>
            </field>
            <field>
              <name>HTIE</name>
              <bitOffset>2</bitOffset>
              <bitWidth>1</bitWidth>
            </field>
            <field>
              <name>TEIE</name>
              <bitOffset>3</bitOffset>
              <bitWidth>1</bitWidth>
            </field>
            <field>
              <name>DIR</name>
              <bitOffset>4</bitOffset>
              <bitWidth>1</bitWidth>
            </field>
            <field>
              <name>CIRC</name>
              <bitOffset>5</bitOffset>
              <bitWidth>1</bitWidth>
            </field>
            <field>
              <name>PINC</name>
              <bitOffset>6</bitOffset>
              <bitWidth>1</bitWidth>
            </field>
            <field>
              <name>MINC</name>
              <bitOffset>7</bitOffset>
              <bitWidth>1</bitWidth>
            </field>
            <field>
              <name>PSIZE</name>
              <bitOffset>8</bitOffset>
              <bitWidth>2</bitWidth>
            </field>
            <field>
              <name>MSIZE</name>
              <bitOffset>10</bitOffset>
              <bitWidth>2</bitWidth>
            </field>
            <field>
              <name>PL</name>
              <bitOffset>12</bitOffset>
              <bitWidth>2</bitWidth>
            </field>
            <field>
              <name>MEM2MEM</name>
              <bitOffset>14</bitOffset>
              <bitWidth>1</bitWidth>
            </field>
          </fields>
        </register>
        <register>
          <name>CNDTR5</name>
          <addressOffset>0x5c</addressOffset>
          <size>0x20</size>
          <fields>
            <field>
              <name>NDT</name>
              <bitOffset>0</bitOffset>
              <bitWidth>16</bitWidth>
            </field>
          </fields>
        </register>
        <register>
          <name>CPAR5</name>
          <addressOffset>0x60</addressOffset>
          <size>0x20</size>
          <fields>
            <field>
              <name>PA</name>
              <bitOffset>0</bitOffset>
              <bitWidth>32</bitWidth>
            </field>
          </fields>
        </register>
        <register>
          <name>CMAR5</name>
          <addressOffset>0x64</addressOffset>
          <size>0x20</size>
          <fields>
            <field>
              <name>MA</name>
              <bitOffset>0</bitOffset>
              <bitWidth>32</bitWidth>
            </field>
          </fields>
        </register>
        <register>
          <name>CCR6</name>
          <addressOffset>0x6c</addressOffset>
          <size>0x20</size>
          <fields>
            <field>
              <name>EN</name>
              <bitOffset>0</bitOffset>
              <bitWidth>1</bitWidth>
            </field>
            <field>
              <name>TCIE</name>
              <bitOffset>1</bitOffset>
              <bitWidth>1</bitWidth>
            </field>
            <field>
              <name>HTIE</name>
              <bitOffset>2</bitOffset>
              <bitWidth>1</bitWidth>
            </field>
            <field>
              <name>TEIE</name>
              <bitOffset>3</bitOffset>
              <bitWidth>1</bitWidth>
            </field>
            <field>
              <name>DIR</name>
              <bitOffset>4</bitOffset>
              <bitWidth>1</bitWidth>
            </field>
            <field>
              <name>CIRC</name>
              <bitOffset>5</bitOffset>
              <bitWidth>1</bitWidth>
            </field>
            <field>
              <name>PINC</name>
              <bitOffset>6</bitOffset>
              <bitWidth>1</bitWidth>
            </field>
            <field>
              <name>MINC</name>
              <bitOffset>7</bitOffset>
              <bitWidth>1</bitWidth>
            </field>
            <field>
              <name>PSIZE</name>
              <bitOffset>8</bitOffset>
              <bitWidth>2</bitWidth>
            </field>
            <field>
              <name>MSIZE</name>
              <bitOffset>10</bitOffset>
              <bitWidth>2</bitWidth>
            </field>
            <field>
              <name>PL</name>
              <bitOffset>12</bitOffset>
              <bitWidth>2</bitWidth>
            </field>
            <field>
              <name>MEM2MEM</name>
              <bitOffset>14</bitOffset>
              <bitWidth>1</bitWidth>
            </field>
          </fields>
        </register>
        <register>
          <name>CNDTR6</name>
          <addressOffset>0x70</addressOffset>
          <size>0x20</size>
          <fields>
            <field>
              <name>NDT</name>
              <bitOffset>0</bitOffset>
              <bitWidth>16</bitWidth>
            </field>
          </fields>
        </register>
        <register>
          <name>CPAR6</name>
          <addressOffset>0x74</addressOffset>
          <size>0x20</size>
          <fields>
            <field>
              <name>PA</name>
              <bitOffset>0</bitOffset>
              <bitWidth>32</bitWidth>
            </field>
          </fields>
        </register>
        <register>
          <name>CMAR6</name>
          <addressOffset>0x78</addressOffset>
          <size>0x20</size>
          <fields>
            <field>
              <name>MA</name>
              <bitOffset>0</bitOffset>
              <bitWidth>32</bitWidth>
            </field>
          </fields>
        </register>
        <register>
          <name>CCR7</name>
          <addressOffset>0x80</addressOffset>
          <size>0x20</size>
          <fields>
            <field>
              <name>EN</name>
              <bitOffset>0</bitOffset>
              <bitWidth>1</bitWidth>
            </field>
            <field>
              <name>TCIE</name>
              <bitOffset>1</bitOffset>
              <bitWidth>1</bitWidth>
            </field>
            <field>
              <name>HTIE</name>
              <bitOffset>2</bitOffset>
              <bitWidth>1</bitWidth>
            </field>
            <field>
              <name>TEIE</name>
              <bitOffset>3</bitOffset>
              <bitWidth>1</bitWidth>
            </field>
            <field>
              <name>DIR</name>
              <bitOffset>4</bitOffset>
              <bitWidth>1</bitWidth>
            </field>
            <field>
              <name>CIRC</name>
              <bitOffset>5</bitOffset>
              <bitWidth>1</bitWidth>
            </field>
            <field>
              <name>PINC</name>
              <bitOffset>6</bitOffset>
              <bitWidth>1</bitWidth>
            </field>
            <field>
              <name>MINC</name>
              <bitOffset>7</bitOffset>
              <bitWidth>1</bitWidth>
            </field>
            <field>
              <name>PSIZE</name>
              <bitOffset>8</bitOffset>
              <bitWidth>2</bitWidth>
            </field>
            <field>
              <name>MSIZE</name>
              <bitOffset>10</bitOffset>
              <bitWidth>2</bitWidth>
            </field>
            <field>
              <name>PL</name>
              <bitOffset>12</bitOffset>
              <bitWidth>2</bitWidth>
            </field>
            <field>
              <name>MEM2MEM</name>
              <bitOffset>14</bitOffset>
              <bitWidth>1</bitWidth>
            </field>
          </fields>
        </register>
        <register>
          <name>CNDTR7</name>
          <addressOffset>0x84</addressOffset>
          <size>0x20</size>
          <fields>
            <field>
              <name>NDT</name>
              <bitOffset>0</bitOffset>
              <bitWidth>16</bitWidth>
            </field>
          </fields>
        </register>
        <register>
          <name>CPAR7</name>
          <addressOffset>0x88</addressOffset>
          <size>0x20</size>
          <fields>
            <field>
              <name>PA</name>
              <bitOffset>0</bitOffset>
              <bitWidth>32</bitWidth>
            </field>
          </fields>
        </register>
        <register>
          <name>CMAR7</name>
          <addressOffset>0x8c</addressOffset>
          <size>0x20</size>
          <fields>
            <field>
              <name>MA</name>
              <bitOffset>0</bitOffset>
              <bitWidth>32</bitWidth>
            </field>
          </fields>
        </register>
      </registers>
    </peripheral>
    <peripheral>
      <name>RCC</name>
      <baseAddress>0x40021000</baseAddress>
      <registers>
        <register>
          <name>CR</name>
          <addressOffset>0x0</addressOffset>
          <size>0x20</size>
          <fields>
            <field>
              <name>HSION</name>
              <bitOffset>0</bitOffset>
              <bitWidth>1</bitWidth>
            </field>
            <field>
              <name>HSIRDY</name>
              <bitOffset>1</bitOffset>
              <bitWidth>1</bitWidth>
            </field>
            <field>
              <name>HSITRIM</name>
              <bitOffset>3</bitOffset>
              <bitWidth>5</bitWidth>
            </field>
            <field>
              <name>HSICAL</name>
              <bitOffset>8</bitOffset>
              <bitWidth>8</bitWidth>
            </field>
            <field>
              <name>HSEON</name>
              <bitOffset>16</bitOffset>
              <bitWidth>1</bitWidth>
            </field>
            <field>
              <name>HSERDY</name>
              <bitOffset>17</bitOffset>
              <bitWidth>1</bitWidth>
            </field>
            <field>
              <name>HSEBYP</name>
              <bitOffset>18</bitOffset>
              <bitWidth>1</bitWidth>
            </field>
            <field>
              <name>CSSON</name>
              <bitOffset>19</bitOffset>
              <bitWidth>1</bitWidth>
            </field>
            <field>
              <name>PLLON</name>
              <bitOffset>24</bitOffset>
              <bitWidth>1</bitWidth>
            </field>
            <field>
              <name>PLLRDY</name>
              <bitOffset>25</bitOffset>
              <bitWidth>1</bitWidth>
            </field>
          </fields>
        </register>
        <register>
          <name>CFGR</name>
          <addressOffset>0x4</addressOffset>
          <size>0x20</size>
          <fields>
            <field>
              <name>SW</name>
              <bitOffset>0</bitOffset>
              <bitWidth>2</bitWidth>
            </field>
            <field>
              <name>SWS</name>
              <bitOffset>2</bitOffset>
              <bitWidth>2</bitWidth>
            </field>
            <field>
              <name>HPRE</name>
              <bitOffset>4</bitOffset>
              <bitWidth>4</bitWidth>
            </field>
            <field>
              <name>PPRE_DIV4</name>
              <bitOffset>8</bitOffset>
              <bitWidth>3</bitWidth>
            </field>
            <field>
              <name>PPRE_DIV8</name>
              <bitOffset>9</bitOffset>
              <bitWidth>2</bitWidth>
            </field>
            <field>
              <name>PPRE_DIV2</name>
              <bitOffset>10</bitOffset>
              <bitWidth>1</bitWidth>
            </field>
            <field>
              <name>ADCPRE</name>
              <bitOffset>14</bitOffset>
              <bitWidth>1</bitWidth>
            </field>
            <field>
              <name>PLLSRC</name>
              <bitOffset>15</bitOffset>
              <bitWidth>2</bitWidth>
            </field>
            <field>
              <name>PLLXTPRE</name>
              <bitOffset>17</bitOffset>
              <bitWidth>1</bitWidth>
            </field>
            <field>
              <name>PLLMUL</name>
              <bitOffset>18</bitOffset>
              <bitWidth>4</bitWidth>
            </field>
            <field>
              <name>USBPRE</name>
              <bitOffset>22</bitOffset>
              <bitWidth>1</bitWidth>
            </field>
            <field>
              <name>MCO</name>
              <bitOffset>24</bitOffset>
              <bitWidth>4</bitWidth>
            </field>
            <field>
              <name>MCOPRE</name>
              <bitOffset>28</bitOffset>
              <bitWidth>3</bitWidth>
            </field>
            <field>
              <name>PLLNODIV</name>
              <bitOffset>31</bitOffset>
              <bitWidth>1</bitWidth>
            </field>
          </fields>
        </register>
        <register>
          <name>CIR</name>
          <addressOffset>0x8</addressOffset>
          <size>0x20</size>
          <fields>
            <field>
              <name>LSIRDYF</name>
              <bitOffset>0</bitOffset>
              <bitWidth>1</bitWidth>
            </field>
            <field>
              <name>LSERDYF</name>
              <bitOffset>1</bitOffset>
              <bitWidth>1</bitWidth>
            </field>
            <field>
              <name>HSIRDYF</name>
              <bitOffset>2</bitOffset>
              <bitWidth>1</bitWidth>
            </field>
            <field>
              <name>HSERDYF</name>
              <bitOffset>3</bitOffset>
              <bitWidth>1</bitWidth>
            </field>
            <field>
              <name>PLLRDYF</name>
              <bitOffset>4</bitOffset>
              <bitWidth>1</bitWidth>
            </field>
            <field>
              <name>HSI14RDYF</name>
              <bitOffset>5</bitOffset>
              <bitWidth>1</bitWidth>
            </field>
            <field>
              <name>HSI48RDYF</name>
              <bitOffset>6</bitOffset>
              <bitWidth>1</bitWidth>
            </field>
            <field>
              <name>CSSF</name>
              <bitOffset>7</bitOffset>
              <bitWidth>1</bitWidth>
            </field>
            <field>
              <name>LSIRDYIE</name>
              <bitOffset>8</bitOffset>
              <bitWidth>1</bitWidth>
            </field>
            <field>
              <name>LSERDYIE</name>
              <bitOffset>9</bitOffset>
              <bitWidth>1</bitWidth>
            </field>
            <field>
              <name>HSIRDYIE</name>
              <bitOffset>10</bitOffset>
              <bitWidth>1</bitWidth>
            </field>
            <field>
              <name>HSERDYIE</name>
              <bitOffset>11</bitOffset>
              <bitWidth>1</bitWidth>
            </field>
            <field>
              <name>PLLRDYIE</name>
              <bitOffset>12</bitOffset>
              <bitWidth>1</bitWidth>
            </field>
            <field>
              <name>HSI14RDYIE</name>
              <bitOffset>13</bitOffset>
              <bitWidth>1</bitWidth>
            </field>
            <field>
              <name>HSI48RDYIE</name>
              <bitOffset>14</bitOffset>
              <bitWidth>1</bitWidth>
            </field>
            <field>
              <name>LSIRDYC</name>
              <bitOffset>16</bitOffset>
              <bitWidth>1</bitWidth>
            </field>
            <field>
              <name>LSERDYC</name>
              <bitOffset>17</bitOffset>
              <bitWidth>1</bitWidth>
            </field>
            <field>
              <name>HSIRDYC</name>
              <bitOffset>18</bitOffset>
              <bitWidth>1</bitWidth>
            </field>
            <field>
              <name>HSERDYC</name>
              <bitOffset>19</bitOffset>
              <bitWidth>1</bitWidth>
            </field>
            <field>
              <name>PLLRDYC</name>
              <bitOffset>20</bitOffset>
              <bitWidth>1</bitWidth>
            </field>
            <field>
              <name>HSI14RDYC</name>
              <bitOffset>21</bitOffset>
              <bitWidth>1</bitWidth>
            </field>
            <field>
              <name>HSI48RDYC</name>
              <bitOffset>22</bitOffset>
              <bitWidth>1</bitWidth>
            </field>
            <field>
              <name>CSSC</name>
              <bitOffset>23</bitOffset>
              <bitWidth>1</bitWidth>
            </field>
          </fields>
        </register>
        <register>
          <name>APB2RSTR</name>
          <addressOffset>0xc</addressOffset>
          <size>0x20</size>
          <fields>
            <field>
              <name>SYSCFGRST</name>
              <bitOffset>0</bitOffset>
              <bitWidth>1</bitWidth>
            </field>
            <field>
              <name>ADCRST</name>
              <bitOffset>9</bitOffset>
              <bitWidth>1</bitWidth>
            </field>
            <field>
              <name>TIM1RST</name>
              <bitOffset>11</bitOffset>
              <bitWidth>1</bitWidth>
            </field>
            <field>
              <name>SPI1RST</name>
              <bitOffset>12</bitOffset>
              <bitWidth>1</bitWidth>
            </field>
            <field>
              <name>USART1RST</name>
              <bitOffset>14</bitOffset>
              <bitWidth>1</bitWidth>
            </field>
            <field>
              <name>TIM15RST</name>
              <bitOffset>16</bitOffset>
              <bitWidth>1</bitWidth>
            </field>
            <field>
              <name>TIM16RST</name>
              <bitOffset>17</bitOffset>
              <bitWidth>1</bitWidth>
            </field>
            <field>
              <name>TIM17RST</name>
              <bitOffset>18</bitOffset>
              <bitWidth>1</bitWidth>
            </field>
            <field>
              <name>DBGMCURST</name>
              <bitOffset>22</bitOffset>
              <bitWidth>1</bitWidth>
            </field>
          </fields>
        </register>
        <register>
          <name>APB1RSTR</name>
          <addressOffset>0x10</addressOffset>
          <size>0x20</size>
          <fields>
            <field>
              <name>TIM2RST</name>
              <bitOffset>0</bitOffset>
              <bitWidth>1</bitWidth>
            </field>
            <field>
              <name>TIM3RST</name>
              <bitOffset>1</bitOffset>
              <bitWidth>1</bitWidth>
            </field>
            <field>
              <name>TIM6RST</name>
              <bitOffset>4</bitOffset>
              <bitWidth>1</bitWidth>
            </field>
            <field>
              <name>TIM7RST</name>
              <bitOffset>5</bitOffset>
              <bitWidth>1</bitWidth>
            </field>
            <field>
              <name>TIM14RST</name>
              <bitOffset>8</bitOffset>
              <bitWidth>1</bitWidth>
            </field>
            <field>
              <name>WWDGRST</name>
              <bitOffset>11</bitOffset>
              <bitWidth>1</bitWidth>
            </field>
            <field>
              <name>SPI2RST</name>
              <bitOffset>14</bitOffset>
              <bitWidth>1</bitWidth>
            </field>
            <field>
              <name>USART2RST</name>
              <bitOffset>17</bitOffset>
              <bitWidth>1</bitWidth>
            </field>
            <field>
              <name>USART3RST</name>
              <bitOffset>18</bitOffset>
              <bitWidth>1</bitWidth>
            </field>
            <field>
              <name>USART4RST</name>
              <bitOffset>19</bitOffset>
              <bitWidth>1</bitWidth>
            </field>
            <field>
              <name>I2C1RST</name>
              <bitOffset>21</bitOffset>
              <bitWidth>1</bitWidth>
            </field>
            <field>
              <name>I2C2RST</name>
              <bitOffset>22</bitOffset>
              <bitWidth>1</bitWidth>
            </field>
            <field>
              <name>USBRST</name>
              <bitOffset>23</bitOffset>
              <bitWidth>1</bitWidth>
            </field>
            <field>
              <name>CANRST</name>
              <bitOffset>25</bitOffset>
              <bitWidth>1</bitWidth>
            </field>
            <field>
              <name>CRSRST</name>
              <bitOffset>27</bitOffset>
              <bitWidth>1</bitWidth>
            </field>
            <field>
              <name>PWRRST</name>
              <bitOffset>28</bitOffset>
              <bitWidth>1</bitWidth>
            </field>
            <field>
              <name>DACRST</name>
              <bitOffset>29</bitOffset>
              <bitWidth>1</bitWidth>
            </field>
            <field>
              <name>CECRST</name>
              <bitOffset>30</bitOffset>
              <bitWidth>1</bitWidth>
            </field>
          </fields>
        </register>
        <register>
          <name>AHBENR</name>
          <addressOffset>0x14</addressOffset>
          <size>0x20</size>
          <fields>
            <field>
              <name>DMAEN</name>
              <bitOffset>0</bitOffset>
              <bitWidth>1</bitWidth>
            </field>
            <field>
              <name>SRAMEN</name>
              <bitOffset>2</bitOffset>
              <bitWidth>1</bitWidth>
            </field>
            <field>
              <name>FLITFEN</name>
              <bitOffset>4</bitOffset>
              <bitWidth>1</bitWidth>
            </field>
            <field>
              <name>CRCEN</name>
              <bitOffset>6</bitOffset>
              <bitWidth>1</bitWidth>
            </field>
            <field>
              <name>GPIOAEN</name>
              <bitOffset>17</bitOffset>
              <bitWidth>1</bitWidth>
            </field>
            <field>
              <name>GPIOBEN</name>
              <bitOffset>18</bitOffset>
              <bitWidth>1</bitWidth>
            </field>
            <field>
              <name>GPIOCEN</name>
              <bitOffset>19</bitOffset>
              <bitWidth>1</bitWidth>
            </field>
            <field>
              <name>GPIODEN</name>
              <bitOffset>20</bitOffset>
              <bitWidth>1</bitWidth>
            </field>
            <field>
              <name>GPIOEEN</name>
              <bitOffset>21</bitOffset>
              <bitWidth>1</bitWidth>
            </field>
            <field>
              <name>GPIOFEN</name>
              <bitOffset>22</bitOffset>
              <bitWidth>1</bitWidth>
            </field>
            <field>
              <name>TSCEN</name>
              <bitOffset>24</bitOffset>
              <bitWidth>1</bitWidth>
            </field>
          </fields>
        </register>
        <register>
          <name>APB2ENR</name>
          <addressOffset>0x18</addressOffset>
          <size>0x20</size>
          <fields>
            <field>
              <name>SYSCFGCOMPEN</name>
              <bitOffset>0</bitOffset>
              <bitWidth>1</bitWidth>
            </field>
            <field>
              <name>ADCEN</name>
              <bitOffset>9</bitOffset>
              <bitWidth>1</bitWidth>
            </field>
            <field>
              <name>TIM1EN</name>
              <bitOffset>11</bitOffset>
              <bitWidth>1</bitWidth>
            </field>
            <field>
              <name>SPI1EN</name>
              <bitOffset>12</bitOffset>
              <bitWidth>1</bitWidth>
            </field>
            <field>
              <name>USART1EN</name>
              <bitOffset>14</bitOffset>
              <bitWidth>1</bitWidth>
            </field>
            <field>
              <name>TIM15EN</name>
              <bitOffset>16</bitOffset>
              <bitWidth>1</bitWidth>
            </field>
            <field>
              <name>TIM16EN</name>
              <bitOffset>17</bitOffset>
              <bitWidth>1</bitWidth>
            </field>
            <field>
              <name>TIM17EN</name>
              <bitOffset>18</bitOffset>
              <bitWidth>1</bitWidth>
            </field>
            <field>
              <name>DBGMCUEN</name>
              <bitOffset>22</bitOffset>
              <bitWidth>1</bitWidth>
            </field>
          </fields>
        </register>
        <register>
          <name>APB1ENR</name>
          <addressOffset>0x1c</addressOffset>
          <size>0x20</size>
          <fields>
            <field>
              <name>TIM2EN</name>
              <bitOffset>0</bitOffset>
              <bitWidth>1</bitWidth>
            </field>
            <field>
              <name>TIM3EN</name>
              <bitOffset>1</bitOffset>
              <bitWidth>1</bitWidth>
            </field>
            <field>
              <name>TIM6EN</name>
              <bitOffset>4</bitOffset>
              <bitWidth>1</bitWidth>
            </field>
            <field>
              <name>TIM7EN</name>
              <bitOffset>5</bitOffset>
              <bitWidth>1</bitWidth>
            </field>
            <field>
              <name>TIM14EN</name>
              <bitOffset>8</bitOffset>
              <bitWidth>1</bitWidth>
            </field>
            <field>
              <name>WWDGEN</name>
              <bitOffset>11</bitOffset>
              <bitWidth>1</bitWidth>
            </field>
            <field>
              <name>SPI2EN</name>
              <bitOffset>14</bitOffset>
              <bitWidth>1</bitWidth>
            </field>
            <field>
              <name>USART2EN</name>
              <bitOffset>17</bitOffset>
              <bitWidth>1</bitWidth>
            </field>
            <field>
              <name>USART3EN</name>
              <bitOffset>18</bitOffset>
              <bitWidth>1</bitWidth>
            </field>
            <field>
              <name>USART4EN</name>
              <bitOffset>19</bitOffset>
              <bitWidth>1</bitWidth>
            </field>
            <field>
              <name>I2C1EN</name>
              <bitOffset>21</bitOffset>
              <bitWidth>1</bitWidth>
            </field>
            <field>
              <name>I2C2EN</name>
              <bitOffset>22</bitOffset>
              <bitWidth>1</bitWidth>
            </field>
            <field>
              <name>USBEN</name>
              <bitOffset>23</bitOffset>
              <bitWidth>1</bitWidth>
            </field>
            <field>
              <name>CANEN</name>
              <bitOffset>25</bitOffset>
              <bitWidth>1</bitWidth>
            </field>
            <field>
              <name>CRSEN</name>
              <bitOffset>27</bitOffset>
              <bitWidth>1</bitWidth>
            </field>
            <field>
              <name>PWREN</name>
              <bitOffset>28</bitOffset>
              <bitWidth>1</bitWidth>
            </field>
            <field>
              <name>DACEN</name>
              <bitOffset>29</bitOffset>
              <bitWidth>1</bitWidth>
            </field>
            <field>
              <name>CECEN</name>
              <bitOffset>30</bitOffset>
              <bitWidth>1</bitWidth>
            </field>
          </fields>
        </register>
        <register>
          <name>BDCR</name>
          <addressOffset>0x20</addressOffset>
          <size>0x20</size>
          <fields>
            <field>
              <name>LSEON</name>
              <bitOffset>0</bitOffset>
              <bitWidth>1</bitWidth>
            </field>
            <field>
              <name>LSERDY</name>
              <bitOffset>1</bitOffset>
              <bitWidth>1</bitWidth>
            </field>
            <field>
              <name>LSEBYP</name>
              <bitOffset>2</bitOffset>
              <bitWidth>1</bitWidth>
            </field>
            <field>
              <name>LSEDRV</name>
              <bitOffset>3</bitOffset>
              <bitWidth>2</bitWidth>
            </field>
            <field>
              <name>RTCSEL</name>
              <bitOffset>8</bitOffset>
              <bitWidth>2</bitWidth>
            </field>
            <field>
              <name>RTCEN</name>
              <bitOffset>15</bitOffset>
              <bitWidth>1</bitWidth>
            </field>
            <field>
              <name>BDRST</name>
              <bitOffset>16</bitOffset>
              <bitWidth>1</bitWidth>
            </field>
          </fields>
        </register>
        <register>
          <name>CSR</name>
          <addressOffset>0x24</addressOffset>
          <size>0x20</size>
          <fields>
            <field>
              <name>LSION</name>
              <bitOffset>0</bitOffset>
              <bitWidth>1</bitWidth>
            </field>
            <field>
              <name>LSIRDY</name>
              <bitOffset>1</bitOffset>
              <bitWidth>1</bitWidth>
            </field>
            <field>
              <name>V18PWRRSTF</name>
              <bitOffset>23</bitOffset>
              <bitWidth>1</bitWidth>
            </field>
            <field>
              <name>RMVF</name>
              <bitOffset>24</bitOffset>
              <bitWidth>1</bitWidth>
            </field>
            <field>
              <name>OBLRSTF</name>
              <bitOffset>25</bitOffset>
              <bitWidth>1</bitWidth>
            </field>
            <field>
              <name>PINRSTF</name>
              <bitOffset>26</bitOffset>
              <bitWidth>1</bitWidth>
            </field>
            <field>
              <name>PORRSTF</name>
              <bitOffset>27</bitOffset>
              <bitWidth>1</bitWidth>
            </field>
            <field>
              <name>SFTRSTF</name>
              <bitOffset>28</bitOffset>
              <bitWidth>1</bitWidth>
            </field>
            <field>
              <name>IWDGRSTF</name>
              <bitOffset>29</bitOffset>
              <bitWidth>1</bitWidth>
            </field>
            <field>
              <name>WWDGRSTF</name>
              <bitOffset>30</bitOffset>
              <bitWidth>1</bitWidth>
            </field>
            <field>
              <name>LPWRRSTF</name>
              <bitOffset>31</bitOffset>
              <bitWidth>1</bitWidth>
            </field>
          </fields>
        </register>
        <register>
          <name>AHBRSTR</name>
          <addressOffset>0x28</addressOffset>
          <size>0x20</size>
          <fields>
            <field>
              <name>GPIOARST</name>
              <bitOffset>17</bitOffset>
              <bitWidth>1</bitWidth>
            </field>
            <field>
              <name>GPIOBRST</name>
              <bitOffset>18</bitOffset>
              <bitWidth>1</bitWidth>
            </field>
            <field>
              <name>GPIOCRST</name>
              <bitOffset>19</bitOffset>
              <bitWidth>1</bitWidth>
            </field>
            <field>
              <name>GPIODRST</name>
              <bitOffset>20</bitOffset>
              <bitWidth>1</bitWidth>
            </field>
            <field>
              <name>GPIOERST</name>
              <bitOffset>21</bitOffset>
              <bitWidth>1</bitWidth>
            </field>
            <field>
              <name>GPIOFRST</name>
              <bitOffset>22</bitOffset>
              <bitWidth>1</bitWidth>
            </field>
            <field>
              <name>TSCRST</name>
              <bitOffset>24</bitOffset>
              <bitWidth>1</bitWidth>
            </field>
          </fields>
        </register>
        <register>
          <name>CFGR2</name>
          <addressOffset>0x2c</addressOffset>
          <size>0x20</size>
          <fields>
            <field>
              <name>PREDIV</name>
              <bitOffset>0</bitOffset>
              <bitWidth>4</bitWidth>
            </field>
          </fields>
        </register>
        <register>
          <name>CFGR3</name>
          <addressOffset>0x30</addressOffset>
          <size>0x20</size>
          <fields>
            <field>
              <name>USART1SW</name>
              <bitOffset>0</bitOffset>
              <bitWidth>2</bitWidth>
            </field>
            <field>
              <name>I2C1SW_SYSCLK</name>
              <bitOffset>4</bitOffset>
              <bitWidth>1</bitWidth>
            </field>
            <field>
              <name>CECSW_LSE</name>
              <bitOffset>6</bitOffset>
              <bitWidth>1</bitWidth>
            </field>
            <field>
              <name>USBSW_PLLCLK</name>
              <bitOffset>7</bitOffset>
              <bitWidth>1</bitWidth>
            </field>
            <field>
              <name>USART2SW</name>
              <bitOffset>16</bitOffset>
              <bitWidth>2</bitWidth>
            </field>
          </fields>
        </register>
        <register>
          <name>CR2</name>
          <addressOffset>0x34</addressOffset>
          <size>0x20</size>
          <fields>
            <field>
              <name>HSI14ON</name>
              <bitOffset>0</bitOffset>
              <bitWidth>1</bitWidth>
            </field>
            <field>
              <name>HSI14RDY</name>
              <bitOffset>1</bitOffset>
              <bitWidth>1</bitWidth>
            </field>
            <field>
              <name>HSI14DIS</name>
              <bitOffset>2</bitOffset>
              <bitWidth>1</bitWidth>
            </field>
            <field>
              <name>HSI14TRIM</name>
              <bitOffset>3</bitOffset>
              <bitWidth>5</bitWidth>
            </field>
            <field>
              <name>HSI14CAL</name>
              <bitOffset>8</bitOffset>
              <bitWidth>8</bitWidth>
            </field>
            <field>
              <name>HSI48ON</name>
              <bitOffset>16</bitOffset>
              <bitWidth>1</bitWidth>
            </field>
            <field>
              <name>HSI48RDY</name>
              <bitOffset>17</bitOffset>
              <bitWidth>1</bitWidth>
            </field>
            <field>
              <name>HSI48CAL</name>
              <bitOffset>24</bitOffset>
              <bitWidth>8</bitWidth>
            </field>
          </fields>
        </register>
      </registers>
    </peripheral>
    <peripheral>
      <name>FLASH</name>
      <baseAddress>0x40022000</baseAddress>
      <registers>
        <register>
          <name>ACR</name>
          <addressOffset>0x0</addressOffset>
          <size>0x20</size>
          <fields>
            <field>
              <name>LATENCY</name>
              <bitOffset>0</bitOffset>
              <bitWidth>1</bitWidth>
            </field>
            <field>
              <name>PRFTBE</name>
              <bitOffset>4</bitOffset>
              <bitWidth>1</bitWidth>
            </field>
            <field>
              <name>PRFTBS</name>
              <bitOffset>5</bitOffset>
              <bitWidth>1</bitWidth>
            </field>
          </fields>
        </register>
        <register>
          <name>KEYR</name>
          <addressOffset>0x4</addressOffset>
          <size>0x20</size>
          <fields>
            <field>
              <name>FKEYR</name>
              <bitOffset>0</bitOffset>
              <bitWidth>32</bitWidth>
            </field>
          </fields>
        </register>
        <register>
          <name>OPTKEYR</name>
          <addressOffset>0x8</addressOffset>
          <size>0x20</size>
          <fields>
            <field>
              <name>OPTKEYR</name>
              <bitOffset>0</bitOffset>
              <bitWidth>32</bitWidth>
            </field>
          </fields>
        </register>
        <register>
          <name>SR</name>
          <addressOffset>0xc</addressOffset>
          <size>0x20</size>
          <fields>
            <field>
              <name>BSY</name>
              <bitOffset>0</bitOffset>
              <bitWidth>1</bitWidth>
            </field>
            <field>
              <name>PGERR</name>
              <bitOffset>2</bitOffset>
              <bitWidth>1</bitWidth>
            </field>
            <field>
              <name>WRPRTERR</name>
              <bitOffset>4</bitOffset>
              <bitWidth>1</bitWidth>
            </field>
            <field>
              <name>EOP</name>
              <bitOffset>5</bitOffset>
              <bitWidth>1</bitWidth>
            </field>
          </fields>
        </register>
        <register>
          <name>CR</name>
          <addressOffset>0x10</addressOffset>
          <size>0x20</size>
          <fields>
            <field>
              <name>PG</name>
              <bitOffset>0</bitOffset>
              <bitWidth>1</bitWidth>
            </field>
            <field>
              <name>PER</name>
              <bitOffset>1</bitOffset>
              <bitWidth>1</bitWidth>
            </field>
            <field>
              <name>MER</name>
              <bitOffset>2</bitOffset>
              <bitWidth>1</bitWidth>
            </field>
            <field>
              <name>OPTPG</name>
              <bitOffset>4</bitOffset>
              <bitWidth>1</bitWidth>
            </field>
            <field>
              <name>OPTER</name>
              <bitOffset>5</bitOffset>
              <bitWidth>1</bitWidth>
            </field>
            <field>
              <name>STRT</name>
              <bitOffset>6</bitOffset>
              <bitWidth>1</bitWidth>
            </field>
            <field>
              <name>LOCK</name>
              <bitOffset>7</bitOffset>
              <bitWidth>1</bitWidth>
            </field>
            <field>
              <name>OPTWRE</name>
              <bitOffset>9</bitOffset>
              <bitWidth>1</bitWidth>
            </field>
            <field>
              <name>ERRIE</name>
              <bitOffset>10</bitOffset>
              <bitWidth>1</bitWidth>
            </field>
            <field>
              <name>EOPIE</name>
              <bitOffset>12</bitOffset>
              <bitWidth>1</bitWidth>
            </field>
            <field>
              <name>OBL_LAUNCH</name>
              <bitOffset>13</bitOffset>
              <bitWidth>1</bitWidth>
            </field>
          </fields>
        </register>
        <register>
          <name>AR</name>
          <addressOffset>0x14</addressOffset>
          <size>0x20</size>
          <fields>
            <field>
              <name>FAR</name>
              <bitOffset>0</bitOffset>
              <bitWidth>32</bitWidth>
            </field>
          </fields>
        </register>
        <register>
          <name>OBR</name>
          <addressOffset>0x1c</addressOffset>
          <size>0x20</size>
          <fields>
            <field>
              <name>OPTERR</name>
              <bitOffset>0</bitOffset>
              <bitWidth>1</bitWidth>
            </field>
            <field>
              <name>RDPRT1</name>
              <bitOffset>1</bitOffset>
              <bitWidth>1</bitWidth>
            </field>
            <field>
              <name>RDPRT2</name>
              <bitOffset>2</bitOffset>
              <bitWidth>1</bitWidth>
            </field>
            <field>
              <name>USER</name>
              <bitOffset>8</bitOffset>
              <bitWidth>7</bitWidth>
            </field>
            <field>
              <name>nRST_STOP</name>
              <bitOffset>9</bitOffset>
              <bitWidth>1</bitWidth>
            </field>
            <field>
              <name>nRST_STDBY</name>
              <bitOffset>10</bitOffset>
              <bitWidth>1</bitWidth>
            </field>
            <field>
              <name>nBOOT1</name>
              <bitOffset>12</bitOffset>
              <bitWidth>1</bitWidth>
            </field>
            <field>
              <name>VDDA_MONITOR</name>
              <bitOffset>13</bitOffset>
              <bitWidth>1</bitWidth>
            </field>
            <field>
              <name>RAM_PARITY_CHECK</name>
              <bitOffset>14</bitOffset>
              <bitWidth>1</bitWidth>
            </field>
            <field>
              <name>DATA0</name>
              <bitOffset>16</bitOffset>
              <bitWidth>8</bitWidth>
            </field>
            <field>
              <name>DATA1</name>
              <bitOffset>24</bitOffset>
              <bitWidth>8</bitWidth>
            </field>
          </fields>
        </register>
        <register>
          <name>WRPR</name>
          <addressOffset>0x20</addressOffset>
          <size>0x20</size>
          <fields>
            <field>
              <name>WRP</name>
              <bitOffset>0</bitOffset>
              <bitWidth>16</bitWidth>
            </field>
          </fields>
        </register>
      </registers>
    </peripheral>
    <peripheral>
      <name>CRC</name>
      <baseAddress>0x40023000</baseAddress>
      <registers>
        <register>
          <name>DR</name>
          <addressOffset>0x0</addressOffset>
          <size>0x20</size>
          <fields>
            <field>
              <name>DR</name>
              <bitOffset>0</bitOffset>
              <bitWidth>32</bitWidth>
            </field>
          </fields>
        </register>
        <register>
          <name>IDR</name>
          <addressOffset>0x4</addressOffset>
          <size>0x8</size>
        </register>
        <register>
          <name>CR</name>
          <addressOffset>0x8</addressOffset>
          <size>0x20</size>
          <fields>
            <field>
              <name>RESET</name>
              <bitOffset>0</bitOffset>
              <bitWidth>1</bitWidth>
            </field>
            <field>
              <name>POLYSIZE</name>
              <bitOffset>3</bitOffset>
              <bitWidth>2</bitWidth>
            </field>
            <field>
              <name>REV_IN</name>
              <bitOffset>5</bitOffset>
              <bitWidth>2</bitWidth>
            </field>
            <field>
              <name>REV_OUT</name>
              <bitOffset>7</bitOffset>
              <bitWidth>1</bitWidth>
            </field>
          </fields>
        </register>
        <register>
          <name>INIT</name>
          <addressOffset>0x10</addressOffset>
          <size>0x20</size>
          <fields>
            <field>
              <name>INIT</name>
              <bitOffset>0</bitOffset>
              <bitWidth>32</bitWidth>
            </field>
          </fields>
        </register>
        <register>
          <name>POL</name>
          <addressOffset>0x14</addressOffset>
          <size>0x20</size>
          <fields>
            <field>
              <name>POL</name>
              <bitOffset>0</bitOffset>
              <bitWidth>32</bitWidth>
            </field>
          </fields>
        </register>
      </registers>
    </peripheral>
    <peripheral>
      <name>TSC</name>
      <baseAddress>0x40024000</baseAddress>
      <registers>
        <register>
          <name>CR</name>
          <addressOffset>0x0</addressOffset>
          <size>0x20</size>
          <fields>
            <field>
              <name>TSCE</name>
              <bitOffset>0</bitOffset>
              <bitWidth>1</bitWidth>
            </field>
            <field>
              <name>START</name>
              <bitOffset>1</bitOffset>
              <bitWidth>1</bitWidth>
            </field>
            <field>
              <name>AM</name>
              <bitOffset>2</bitOffset>
              <bitWidth>1</bitWidth>
            </field>
            <field>
              <name>SYNCPOL</name>
              <bitOffset>3</bitOffset>
              <bitWidth>1</bitWidth>
            </field>
            <field>
              <name>IODEF</name>
              <bitOffset>4</bitOffset>
              <bitWidth>1</bitWidth>
            </field>
            <field>
              <name>MCV</name>
              <bitOffset>5</bitOffset>
              <bitWidth>3</bitWidth>
            </field>
            <field>
              <name>PGPSC</name>
              <bitOffset>12</bitOffset>
              <bitWidth>3</bitWidth>
            </field>
            <field>
              <name>SSPSC</name>
              <bitOffset>15</bitOffset>
              <bitWidth>1</bitWidth>
            </field>
            <field>
              <name>SSE</name>
              <bitOffset>16</bitOffset>
              <bitWidth>1</bitWidth>
            </field>
            <field>
              <name>SSD</name>
              <bitOffset>17</bitOffset>
              <bitWidth>7</bitWidth>
            </field>
            <field>
              <name>CTPL</name>
              <bitOffset>24</bitOffset>
              <bitWidth>4</bitWidth>
            </field>
            <field>
              <name>CTPH</name>
              <bitOffset>28</bitOffset>
              <bitWidth>4</bitWidth>
            </field>
          </fields>
        </register>
        <register>
          <name>IER</name>
          <addressOffset>0x4</addressOffset>
          <size>0x20</size>
          <fields>
            <field>
              <name>EOAIE</name>
              <bitOffset>0</bitOffset>
              <bitWidth>1</bitWidth>
            </field>
            <field>
              <name>MCEIE</name>
              <bitOffset>1</bitOffset>
              <bitWidth>1</bitWidth>
            </field>
          </fields>
        </register>
        <register>
          <name>ICR</name>
          <addressOffset>0x8</addressOffset>
          <size>0x20</size>
          <fields>
            <field>
              <name>EOAIC</name>
              <bitOffset>0</bitOffset>
              <bitWidth>1</bitWidth>
            </field>
            <field>
              <name>MCEIC</name>
              <bitOffset>1</bitOffset>
              <bitWidth>1</bitWidth>
            </field>
          </fields>
        </register>
        <register>
          <name>ISR</name>
          <addressOffset>0xc</addressOffset>
          <size>0x20</size>
          <fields>
            <field>
              <name>EOAF</name>
              <bitOffset>0</bitOffset>
              <bitWidth>1</bitWidth>
            </field>
            <field>
              <name>MCEF</name>
              <bitOffset>1</bitOffset>
              <bitWidth>1</bitWidth>
            </field>
          </fields>
        </register>
        <register>
          <name>IOHCR</name>
          <addressOffset>0x10</addressOffset>
          <size>0x20</size>
          <fields>
            <field>
              <name>G1_IO1</name>
              <bitOffset>0</bitOffset>
              <bitWidth>1</bitWidth>
            </field>
            <field>
              <name>G1_IO2</name>
              <bitOffset>1</bitOffset>
              <bitWidth>1</bitWidth>
            </field>
            <field>
              <name>G1_IO3</name>
              <bitOffset>2</bitOffset>
              <bitWidth>1</bitWidth>
            </field>
            <field>
              <name>G1_IO4</name>
              <bitOffset>3</bitOffset>
              <bitWidth>1</bitWidth>
            </field>
            <field>
              <name>G2_IO1</name>
              <bitOffset>4</bitOffset>
              <bitWidth>1</bitWidth>
            </field>
            <field>
              <name>G2_IO2</name>
              <bitOffset>5</bitOffset>
              <bitWidth>1</bitWidth>
            </field>
            <field>
              <name>G2_IO3</name>
              <bitOffset>6</bitOffset>
              <bitWidth>1</bitWidth>
            </field>
            <field>
              <name>G2_IO4</name>
              <bitOffset>7</bitOffset>
              <bitWidth>1</bitWidth>
            </field>
            <field>
              <name>G3_IO1</name>
              <bitOffset>8</bitOffset>
              <bitWidth>1</bitWidth>
            </field>
            <field>
              <name>G3_IO2</name>
              <bitOffset>9</bitOffset>
              <bitWidth>1</bitWidth>
            </field>
            <field>
              <name>G3_IO3</name>
              <bitOffset>10</bitOffset>
              <bitWidth>1</bitWidth>
            </field>
            <field>
              <name>G3_IO4</name>
              <bitOffset>11</bitOffset>
              <bitWidth>1</bitWidth>
            </field>
            <field>
              <name>G4_IO1</name>
              <bitOffset>12</bitOffset>
              <bitWidth>1</bitWidth>
            </field>
            <field>
              <name>G4_IO2</name>
              <bitOffset>13</bitOffset>
              <bitWidth>1</bitWidth>
            </field>
            <field>
              <name>G4_IO3</name>
              <bitOffset>14</bitOffset>
              <bitWidth>1</bitWidth>
            </field>
            <field>
              <name>G4_IO4</name>
              <bitOffset>15</bitOffset>
              <bitWidth>1</bitWidth>
            </field>
            <field>
              <name>G5_IO1</name>
              <bitOffset>16</bitOffset>
              <bitWidth>1</bitWidth>
            </field>
            <field>
              <name>G5_IO2</name>
              <bitOffset>17</bitOffset>
              <bitWidth>1</bitWidth>
            </field>
            <field>
              <name>G5_IO3</name>
              <bitOffset>18</bitOffset>
              <bitWidth>1</bitWidth>
            </field>
            <field>
              <name>G5_IO4</name>
              <bitOffset>19</bitOffset>
              <bitWidth>1</bitWidth>
            </field>
            <field>
              <name>G6_IO1</name>
              <bitOffset>20</bitOffset>
              <bitWidth>1</bitWidth>
            </field>
            <field>
              <name>G6_IO2</name>
              <bitOffset>21</bitOffset>
              <bitWidth>1</bitWidth>
            </field>
            <field>
              <name>G6_IO3</name>
              <bitOffset>22</bitOffset>
              <bitWidth>1</bitWidth>
            </field>
            <field>
              <name>G6_IO4</name>
              <bitOffset>23</bitOffset>
              <bitWidth>1</bitWidth>
            </field>
            <field>
              <name>G7_IO1</name>
              <bitOffset>24</bitOffset>
              <bitWidth>1</bitWidth>
            </field>
            <field>
              <name>G7_IO2</name>
              <bitOffset>25</bitOffset>
              <bitWidth>1</bitWidth>
            </field>
            <field>
              <name>G7_IO3</name>
              <bitOffset>26</bitOffset>
              <bitWidth>1</bitWidth>
            </field>
            <field>
              <name>G7_IO4</name>
              <bitOffset>27</bitOffset>
              <bitWidth>1</bitWidth>
            </field>
            <field>
              <name>G8_IO1</name>
              <bitOffset>28</bitOffset>
              <bitWidth>1</bitWidth>
            </field>
            <field>
              <name>G8_IO2</name>
              <bitOffset>29</bitOffset>
              <bitWidth>1</bitWidth>
            </field>
            <field>
              <name>G8_IO3</name>
              <bitOffset>30</bitOffset>
              <bitWidth>1</bitWidth>
            </field>
            <field>
              <name>G8_IO4</name>
              <bitOffset>31</bitOffset>
              <bitWidth>1</bitWidth>
            </field>
          </fields>
        </register>
        <register>
          <name>IOASCR</name>
          <addressOffset>0x18</addressOffset>
          <size>0x20</size>
          <fields>
            <field>
              <name>G1_IO1</name>
              <bitOffset>0</bitOffset>
              <bitWidth>1</bitWidth>
            </field>
            <field>
              <name>G1_IO2</name>
              <bitOffset>1</bitOffset>
              <bitWidth>1</bitWidth>
            </field>
            <field>
              <name>G1_IO3</name>
              <bitOffset>2</bitOffset>
              <bitWidth>1</bitWidth>
            </field>
            <field>
              <name>G1_IO4</name>
              <bitOffset>3</bitOffset>
              <bitWidth>1</bitWidth>
            </field>
            <field>
              <name>G2_IO1</name>
              <bitOffset>4</bitOffset>
              <bitWidth>1</bitWidth>
            </field>
            <field>
              <name>G2_IO2</name>
              <bitOffset>5</bitOffset>
              <bitWidth>1</bitWidth>
            </field>
            <field>
              <name>G2_IO3</name>
              <bitOffset>6</bitOffset>
              <bitWidth>1</bitWidth>
            </field>
            <field>
              <name>G2_IO4</name>
              <bitOffset>7</bitOffset>
              <bitWidth>1</bitWidth>
            </field>
            <field>
              <name>G3_IO1</name>
              <bitOffset>8</bitOffset>
              <bitWidth>1</bitWidth>
            </field>
            <field>
              <name>G3_IO2</name>
              <bitOffset>9</bitOffset>
              <bitWidth>1</bitWidth>
            </field>
            <field>
              <name>G3_IO3</name>
              <bitOffset>10</bitOffset>
              <bitWidth>1</bitWidth>
            </field>
            <field>
              <name>G3_IO4</name>
              <bitOffset>11</bitOffset>
              <bitWidth>1</bitWidth>
            </field>
            <field>
              <name>G4_IO1</name>
              <bitOffset>12</bitOffset>
              <bitWidth>1</bitWidth>
            </field>
            <field>
              <name>G4_IO2</name>
              <bitOffset>13</bitOffset>
              <bitWidth>1</bitWidth>
            </field>
            <field>
              <name>G4_IO3</name>
              <bitOffset>14</bitOffset>
              <bitWidth>1</bitWidth>
            </field>
            <field>
              <name>G4_IO4</name>
              <bitOffset>15</bitOffset>
              <bitWidth>1</bitWidth>
            </field>
            <field>
              <name>G5_IO1</name>
              <bitOffset>16</bitOffset>
              <bitWidth>1</bitWidth>
            </field>
            <field>
              <name>G5_IO2</name>
              <bitOffset>17</bitOffset>
              <bitWidth>1</bitWidth>
            </field>
            <field>
              <name>G5_IO3</name>
              <bitOffset>18</bitOffset>
              <bitWidth>1</bitWidth>
            </field>
            <field>
              <name>G5_IO4</name>
              <bitOffset>19</bitOffset>
              <bitWidth>1</bitWidth>
            </field>
            <field>
              <name>G6_IO1</name>
              <bitOffset>20</bitOffset>
              <bitWidth>1</bitWidth>
            </field>
            <field>
              <name>G6_IO2</name>
              <bitOffset>21</bitOffset>
              <bitWidth>1</bitWidth>
            </field>
            <field>
              <name>G6_IO3</name>
              <bitOffset>22</bitOffset>
              <bitWidth>1</bitWidth>
            </field>
            <field>
              <name>G6_IO4</name>
              <bitOffset>23</bitOffset>
              <bitWidth>1</bitWidth>
            </field>
            <field>
              <name>G7_IO1</name>
              <bitOffset>24</bitOffset>
              <bitWidth>1</bitWidth>
            </field>
            <field>
              <name>G7_IO2</name>
              <bitOffset>25</bitOffset>
              <bitWidth>1</bitWidth>
            </field>
            <field>
              <name>G7_IO3</name>
              <bitOffset>26</bitOffset>
              <bitWidth>1</bitWidth>
            </field>
            <field>
              <name>G7_IO4</name>
              <bitOffset>27</bitOffset>
              <bitWidth>1</bitWidth>
            </field>
            <field>
              <name>G8_IO1</name>
              <bitOffset>28</bitOffset>
              <bitWidth>1</bitWidth>
            </field>
            <field>
              <name>G8_IO2</name>
              <bitOffset>29</bitOffset>
              <bitWidth>1</bitWidth>
            </field>
            <field>
              <name>G8_IO3</name>
              <bitOffset>30</bitOffset>
              <bitWidth>1</bitWidth>
            </field>
            <field>
              <name>G8_IO4</name>
              <bitOffset>31</bitOffset>
              <bitWidth>1</bitWidth>
            </field>
          </fields>
        </register>
        <register>
          <name>IOSCR</name>
          <addressOffset>0x20</addressOffset>
          <size>0x20</size>
          <fields>
            <field>
              <name>G1_IO1</name>
              <bitOffset>0</bitOffset>
              <bitWidth>1</bitWidth>
            </field>
            <field>
              <name>G1_IO2</name>
              <bitOffset>1</bitOffset>
              <bitWidth>1</bitWidth>
            </field>
            <field>
              <name>G1_IO3</name>
              <bitOffset>2</bitOffset>
              <bitWidth>1</bitWidth>
            </field>
            <field>
              <name>G1_IO4</name>
              <bitOffset>3</bitOffset>
              <bitWidth>1</bitWidth>
            </field>
            <field>
              <name>G2_IO1</name>
              <bitOffset>4</bitOffset>
              <bitWidth>1</bitWidth>
            </field>
            <field>
              <name>G2_IO2</name>
              <bitOffset>5</bitOffset>
              <bitWidth>1</bitWidth>
            </field>
            <field>
              <name>G2_IO3</name>
              <bitOffset>6</bitOffset>
              <bitWidth>1</bitWidth>
            </field>
            <field>
              <name>G2_IO4</name>
              <bitOffset>7</bitOffset>
              <bitWidth>1</bitWidth>
            </field>
            <field>
              <name>G3_IO1</name>
              <bitOffset>8</bitOffset>
              <bitWidth>1</bitWidth>
            </field>
            <field>
              <name>G3_IO2</name>
              <bitOffset>9</bitOffset>
              <bitWidth>1</bitWidth>
            </field>
            <field>
              <name>G3_IO3</name>
              <bitOffset>10</bitOffset>
              <bitWidth>1</bitWidth>
            </field>
            <field>
              <name>G3_IO4</name>
              <bitOffset>11</bitOffset>
              <bitWidth>1</bitWidth>
            </field>
            <field>
              <name>G4_IO1</name>
              <bitOffset>12</bitOffset>
              <bitWidth>1</bitWidth>
            </field>
            <field>
              <name>G4_IO2</name>
              <bitOffset>13</bitOffset>
              <bitWidth>1</bitWidth>
            </field>
            <field>
              <name>G4_IO3</name>
              <bitOffset>14</bitOffset>
              <bitWidth>1</bitWidth>
            </field>
            <field>
              <name>G4_IO4</name>
              <bitOffset>15</bitOffset>
              <bitWidth>1</bitWidth>
            </field>
            <field>
              <name>G5_IO1</name>
              <bitOffset>16</bitOffset>
              <bitWidth>1</bitWidth>
            </field>
            <field>
              <name>G5_IO2</name>
              <bitOffset>17</bitOffset>
              <bitWidth>1</bitWidth>
            </field>
            <field>
              <name>G5_IO3</name>
              <bitOffset>18</bitOffset>
              <bitWidth>1</bitWidth>
            </field>
            <field>
              <name>G5_IO4</name>
              <bitOffset>19</bitOffset>
              <bitWidth>1</bitWidth>
            </field>
            <field>
              <name>G6_IO1</name>
              <bitOffset>20</bitOffset>
              <bitWidth>1</bitWidth>
            </field>
            <field>
              <name>G6_IO2</name>
              <bitOffset>21</bitOffset>
              <bitWidth>1</bitWidth>
            </field>
            <field>
              <name>G6_IO3</name>
              <bitOffset>22</bitOffset>
              <bitWidth>1</bitWidth>
            </field>
            <field>
              <name>G6_IO4</name>
              <bitOffset>23</bitOffset>
              <bitWidth>1</bitWidth>
            </field>
            <field>
              <name>G7_IO1</name>
              <bitOffset>24</bitOffset>
              <bitWidth>1</bitWidth>
            </field>
            <field>
              <name>G7_IO2</name>
              <bitOffset>25</bitOffset>
              <bitWidth>1</bitWidth>
            </field>
            <field>
              <name>G7_IO3</name>
              <bitOffset>26</bitOffset>
              <bitWidth>1</bitWidth>
            </field>
            <field>
              <name>G7_IO4</name>
              <bitOffset>27</bitOffset>
              <bitWidth>1</bitWidth>
            </field>
            <field>
              <name>G8_IO1</name>
              <bitOffset>28</bitOffset>
              <bitWidth>1</bitWidth>
            </field>
            <field>
              <name>G8_IO2</name>
              <bitOffset>29</bitOffset>
              <bitWidth>1</bitWidth>
            </field>
            <field>
              <name>G8_IO3</name>
              <bitOffset>30</bitOffset>
              <bitWidth>1</bitWidth>
            </field>
            <field>
              <name>G8_IO4</name>
              <bitOffset>31</bitOffset>
              <bitWidth>1</bitWidth>
            </field>
          </fields>
        </register>
        <register>
          <name>IOCCR</name>
          <addressOffset>0x28</addressOffset>
          <size>0x20</size>
          <fields>
            <field>
              <name>G1_IO1</name>
              <bitOffset>0</bitOffset>
              <bitWidth>1</bitWidth>
            </field>
            <field>
              <name>G1_IO2</name>
              <bitOffset>1</bitOffset>
              <bitWidth>1</bitWidth>
            </field>
            <field>
              <name>G1_IO3</name>
              <bitOffset>2</bitOffset>
              <bitWidth>1</bitWidth>
            </field>
            <field>
              <name>G1_IO4</name>
              <bitOffset>3</bitOffset>
              <bitWidth>1</bitWidth>
            </field>
            <field>
              <name>G2_IO1</name>
              <bitOffset>4</bitOffset>
              <bitWidth>1</bitWidth>
            </field>
            <field>
              <name>G2_IO2</name>
              <bitOffset>5</bitOffset>
              <bitWidth>1</bitWidth>
            </field>
            <field>
              <name>G2_IO3</name>
              <bitOffset>6</bitOffset>
              <bitWidth>1</bitWidth>
            </field>
            <field>
              <name>G2_IO4</name>
              <bitOffset>7</bitOffset>
              <bitWidth>1</bitWidth>
            </field>
            <field>
              <name>G3_IO1</name>
              <bitOffset>8</bitOffset>
              <bitWidth>1</bitWidth>
            </field>
            <field>
              <name>G3_IO2</name>
              <bitOffset>9</bitOffset>
              <bitWidth>1</bitWidth>
            </field>
            <field>
              <name>G3_IO3</name>
              <bitOffset>10</bitOffset>
              <bitWidth>1</bitWidth>
            </field>
            <field>
              <name>G3_IO4</name>
              <bitOffset>11</bitOffset>
              <bitWidth>1</bitWidth>
            </field>
            <field>
              <name>G4_IO1</name>
              <bitOffset>12</bitOffset>
              <bitWidth>1</bitWidth>
            </field>
            <field>
              <name>G4_IO2</name>
              <bitOffset>13</bitOffset>
              <bitWidth>1</bitWidth>
            </field>
            <field>
              <name>G4_IO3</name>
              <bitOffset>14</bitOffset>
              <bitWidth>1</bitWidth>
            </field>
            <field>
              <name>G4_IO4</name>
              <bitOffset>15</bitOffset>
              <bitWidth>1</bitWidth>
            </field>
            <field>
              <name>G5_IO1</name>
              <bitOffset>16</bitOffset>
              <bitWidth>1</bitWidth>
            </field>
            <field>
              <name>G5_IO2</name>
              <bitOffset>17</bitOffset>
              <bitWidth>1</bitWidth>
            </field>
            <field>
              <name>G5_IO3</name>
              <bitOffset>18</bitOffset>
              <bitWidth>1</bitWidth>
            </field>
            <field>
              <name>G5_IO4</name>
              <bitOffset>19</bitOffset>
              <bitWidth>1</bitWidth>
            </field>
            <field>
              <name>G6_IO1</name>
              <bitOffset>20</bitOffset>
              <bitWidth>1</bitWidth>
            </field>
            <field>
              <name>G6_IO2</name>
              <bitOffset>21</bitOffset>
              <bitWidth>1</bitWidth>
            </field>
            <field>
              <name>G6_IO3</name>
              <bitOffset>22</bitOffset>
              <bitWidth>1</bitWidth>
            </field>
            <field>
              <name>G6_IO4</name>
              <bitOffset>23</bitOffset>
              <bitWidth>1</bitWidth>
            </field>
            <field>
              <name>G7_IO1</name>
              <bitOffset>24</bitOffset>
              <bitWidth>1</bitWidth>
            </field>
            <field>
              <name>G7_IO2</name>
              <bitOffset>25</bitOffset>
              <bitWidth>1</bitWidth>
            </field>
            <field>
              <name>G7_IO3</name>
              <bitOffset>26</bitOffset>
              <bitWidth>1</bitWidth>
            </field>
            <field>
              <name>G7_IO4</name>
              <bitOffset>27</bitOffset>
              <bitWidth>1</bitWidth>
            </field>
            <field>
              <name>G8_IO1</name>
              <bitOffset>28</bitOffset>
              <bitWidth>1</bitWidth>
            </field>
            <field>
              <name>G8_IO2</name>
              <bitOffset>29</bitOffset>
              <bitWidth>1</bitWidth>
            </field>
            <field>
              <name>G8_IO3</name>
              <bitOffset>30</bitOffset>
              <bitWidth>1</bitWidth>
            </field>
            <field>
              <name>G8_IO4</name>
              <bitOffset>31</bitOffset>
              <bitWidth>1</bitWidth>
            </field>
          </fields>
        </register>
        <register>
          <name>IOGCSR</name>
          <addressOffset>0x30</addressOffset>
          <size>0x20</size>
          <fields>
            <field>
              <name>G1E</name>
              <bitOffset>0</bitOffset>
              <bitWidth>1</bitWidth>
            </field>
            <field>
              <name>G2E</name>
              <bitOffset>1</bitOffset>
              <bitWidth>1</bitWidth>
            </field>
            <field>
              <name>G3E</name>
              <bitOffset>2</bitOffset>
              <bitWidth>1</bitWidth>
            </field>
            <field>
              <name>G4E</name>
              <bitOffset>3</bitOffset>
              <bitWidth>1</bitWidth>
            </field>
            <field>
              <name>G5E</name>
              <bitOffset>4</bitOffset>
              <bitWidth>1</bitWidth>
            </field>
            <field>
              <name>G6E</name>
              <bitOffset>5</bitOffset>
              <bitWidth>1</bitWidth>
            </field>
            <field>
              <name>G7E</name>
              <bitOffset>6</bitOffset>
              <bitWidth>1</bitWidth>
            </field>
            <field>
              <name>G8E</name>
              <bitOffset>7</bitOffset>
              <bitWidth>1</bitWidth>
            </field>
            <field>
              <name>G1S</name>
              <bitOffset>16</bitOffset>
              <bitWidth>1</bitWidth>
            </field>
            <field>
              <name>G2S</name>
              <bitOffset>17</bitOffset>
              <bitWidth>1</bitWidth>
            </field>
            <field>
              <name>G3S</name>
              <bitOffset>18</bitOffset>
              <bitWidth>1</bitWidth>
            </field>
            <field>
              <name>G4S</name>
              <bitOffset>19</bitOffset>
              <bitWidth>1</bitWidth>
            </field>
            <field>
              <name>G5S</name>
              <bitOffset>20</bitOffset>
              <bitWidth>1</bitWidth>
            </field>
            <field>
              <name>G6S</name>
              <bitOffset>21</bitOffset>
              <bitWidth>1</bitWidth>
            </field>
            <field>
              <name>G7S</name>
              <bitOffset>22</bitOffset>
              <bitWidth>1</bitWidth>
            </field>
            <field>
              <name>G8S</name>
              <bitOffset>23</bitOffset>
              <bitWidth>1</bitWidth>
            </field>
          </fields>
        </register>
        <register>
          <name>IOGXCR.0</name>
          <addressOffset>0x34</addressOffset>
          <size>0x20</size>
          <fields>
            <field>
              <name>CNT</name>
              <bitOffset>0</bitOffset>
              <bitWidth>14</bitWidth>
            </field>
          </fields>
        </register>
        <register>
          <name>IOGXCR.1</name>
          <addressOffset>0x38</addressOffset>
          <size>0x20</size>
          <fields>
            <field>
              <name>CNT</name>
              <bitOffset>0</bitOffset>
              <bitWidth>14</bitWidth>
            </field>
          </fields>
        </register>
        <register>
          <name>IOGXCR.2</name>
          <addressOffset>0x3c</addressOffset>
          <size>0x20</size>
          <fields>
            <field>
              <name>CNT</name>
              <bitOffset>0</bitOffset>
              <bitWidth>14</bitWidth>
            </field>
          </fields>
        </register>
        <register>
          <name>IOGXCR.3</name>
          <addressOffset>0x40</addressOffset>
          <size>0x20</size>
          <fields>
            <field>
              <name>CNT</name>
              <bitOffset>0</bitOffset>
              <bitWidth>14</bitWidth>
            </field>
          </fields>
        </register>
        <register>
          <name>IOGXCR.4</name>
          <addressOffset>0x44</addressOffset>
          <size>0x20</size>
          <fields>
            <field>
              <name>CNT</name>
              <bitOffset>0</bitOffset>
              <bitWidth>14</bitWidth>
            </field>
          </fields>
        </register>
        <register>
          <name>IOGXCR.5</name>
          <addressOffset>0x48</addressOffset>
          <size>0x20</size>
          <fields>
            <field>
              <name>CNT</name>
              <bitOffset>0</bitOffset>
              <bitWidth>14</bitWidth>
            </field>
          </fields>
        </register>
        <register>
          <name>IOGXCR.6</name>
          <addressOffset>0x4c</addressOffset>
          <size>0x20</size>
          <fields>
            <field>
              <name>CNT</name>
              <bitOffset>0</bitOffset>
              <bitWidth>14</bitWidth>
            </field>
          </fields>
        </register>
        <register>
          <name>IOGXCR.7</name>
          <addressOffset>0x50</addressOffset>
          <size>0x20</size>
          <fields>
            <field>
              <name>CNT</name>
              <bitOffset>0</bitOffset>
              <bitWidth>14</bitWidth>
            </field>
          </fields>
        </register>
      </registers>
    </peripheral>
    <peripheral>
      <name>GPIOA</name>
      <baseAddress>0x48000000</baseAddress>
      <registers>
        <register>
          <name>MODER</name>
          <addressOffset>0x0</addressOffset>
          <size>0x20</size>
          <fields>
            <field>
              <name>MODER0</name>
              <bitOffset>0</bitOffset>
              <bitWidth>2</bitWidth>
            </field>
            <field>
              <name>MODER1</name>
              <bitOffset>2</bitOffset>
              <bitWidth>2</bitWidth>
            </field>
            <field>
              <name>MODER2</name>
              <bitOffset>4</bitOffset>
              <bitWidth>2</bitWidth>
            </field>
            <field>
              <name>MODER3</name>
              <bitOffset>6</bitOffset>
              <bitWidth>2</bitWidth>
            </field>
            <field>
              <name>MODER4</name>
              <bitOffset>8</bitOffset>
              <bitWidth>2</bitWidth>
            </field>
            <field>
              <name>MODER5</name>
              <bitOffset>10</bitOffset>
              <bitWidth>2</bitWidth>
            </field>
            <field>
              <name>MODER6</name>
              <bitOffset>12</bitOffset>
              <bitWidth>2</bitWidth>
            </field>
            <field>
              <name>MODER7</name>
              <bitOffset>14</bitOffset>
              <bitWidth>2</bitWidth>
            </field>
            <field>
              <name>MODER8</name>
              <bitOffset>16</bitOffset>
              <bitWidth>2</bitWidth>
            </field>
            <field>
              <name>MODER9</name>
              <bitOffset>18</bitOffset>
              <bitWidth>2</bitWidth>
            </field>
            <field>
              <name>MODER10</name>
              <bitOffset>20</bitOffset>
              <bitWidth>2</bitWidth>
            </field>
            <field>
              <name>MODER11</name>
              <bitOffset>22</bitOffset>
              <bitWidth>2</bitWidth>
            </field>
            <field>
              <name>MODER12</name>
              <bitOffset>24</bitOffset>
              <bitWidth>2</bitWidth>
            </field>
            <field>
              <name>MODER13</name>
              <bitOffset>26</bitOffset>
              <bitWidth>2</bitWidth>
            </field>
            <field>
              <name>MODER14</name>
              <bitOffset>28</bitOffset>
              <bitWidth>2</bitWidth>
            </field>
            <field>
              <name>MODER15</name>
              <bitOffset>30</bitOffset>
              <bitWidth>2</bitWidth>
            </field>
          </fields>
        </register>
        <register>
          <name>OTYPER</name>
          <addressOffset>0x4</addressOffset>
          <size>0x20</size>
        </register>
        <register>
          <name>OSPEEDR</name>
          <addressOffset>0x8</addressOffset>
          <size>0x20</size>
          <fields>
            <field>
              <name>OSPEEDR0</name>
              <bitOffset>0</bitOffset>
              <bitWidth>2</bitWidth>
            </field>
            <field>
              <name>OSPEEDR1</name>
              <bitOffset>2</bitOffset>
              <bitWidth>2</bitWidth>
            </field>
            <field>
              <name>OSPEEDR2</name>
              <bitOffset>4</bitOffset>
              <bitWidth>2</bitWidth>
            </field>
            <field>
              <name>OSPEEDR3</name>
              <bitOffset>6</bitOffset>
              <bitWidth>2</bitWidth>
            </field>
            <field>
              <name>OSPEEDR4</name>
              <bitOffset>8</bitOffset>
              <bitWidth>2</bitWidth>
            </field>
            <field>
              <name>OSPEEDR5</name>
              <bitOffset>10</bitOffset>
              <bitWidth>2</bitWidth>
            </field>
            <field>
              <name>OSPEEDR6</name>
              <bitOffset>12</bitOffset>
              <bitWidth>2</bitWidth>
            </field>
            <field>
              <name>OSPEEDR7</name>
              <bitOffset>14</bitOffset>
              <bitWidth>2</bitWidth>
            </field>
            <field>
              <name>OSPEEDR8</name>
              <bitOffset>16</bitOffset>
              <bitWidth>2</bitWidth>
            </field>
            <field>
              <name>OSPEEDR9</name>
              <bitOffset>18</bitOffset>
              <bitWidth>2</bitWidth>
            </field>
            <field>
              <name>OSPEEDR10</name>
              <bitOffset>20</bitOffset>
              <bitWidth>2</bitWidth>
            </field>
            <field>
              <name>OSPEEDR11</name>
              <bitOffset>22</bitOffset>
              <bitWidth>2</bitWidth>
            </field>
            <field>
              <name>OSPEEDR12</name>
              <bitOffset>24</bitOffset>
              <bitWidth>2</bitWidth>
            </field>
            <field>
              <name>OSPEEDR13</name>
              <bitOffset>26</bitOffset>
              <bitWidth>2</bitWidth>
            </field>
            <field>
              <name>OSPEEDR14</name>
              <bitOffset>28</bitOffset>
              <bitWidth>2</bitWidth>
            </field>
            <field>
              <name>OSPEEDR15</name>
              <bitOffset>30</bitOffset>
              <bitWidth>2</bitWidth>
            </field>
          </fields>
        </register>
        <register>
          <name>PUPDR</name>
          <addressOffset>0xc</addressOffset>
          <size>0x20</size>
          <fields>
            <field>
              <name>PUPDR0</name>
              <bitOffset>0</bitOffset>
              <bitWidth>2</bitWidth>
            </field>
            <field>
              <name>PUPDR1</name>
              <bitOffset>2</bitOffset>
              <bitWidth>2</bitWidth>
            </field>
            <field>
              <name>PUPDR2</name>
              <bitOffset>4</bitOffset>
              <bitWidth>2</bitWidth>
            </field>
            <field>
              <name>PUPDR3</name>
              <bitOffset>6</bitOffset>
              <bitWidth>2</bitWidth>
            </field>
            <field>
              <name>PUPDR4</name>
              <bitOffset>8</bitOffset>
              <bitWidth>2</bitWidth>
            </field>
            <field>
              <name>PUPDR5</name>
              <bitOffset>10</bitOffset>
              <bitWidth>2</bitWidth>
            </field>
            <field>
              <name>PUPDR6</name>
              <bitOffset>12</bitOffset>
              <bitWidth>2</bitWidth>
            </field>
            <field>
              <name>PUPDR7</name>
              <bitOffset>14</bitOffset>
              <bitWidth>2</bitWidth>
            </field>
            <field>
              <name>PUPDR8</name>
              <bitOffset>16</bitOffset>
              <bitWidth>2</bitWidth>
            </field>
            <field>
              <name>PUPDR9</name>
              <bitOffset>18</bitOffset>
              <bitWidth>2</bitWidth>
            </field>
            <field>
              <name>PUPDR10</name>
              <bitOffset>20</bitOffset>
              <bitWidth>2</bitWidth>
            </field>
            <field>
              <name>PUPDR11</name>
              <bitOffset>22</bitOffset>
              <bitWidth>2</bitWidth>
            </field>
            <field>
              <name>PUPDR12</name>
              <bitOffset>24</bitOffset>
              <bitWidth>2</bitWidth>
            </field>
            <field>
              <name>PUPDR13</name>
              <bitOffset>26</bitOffset>
              <bitWidth>2</bitWidth>
            </field>
            <field>
              <name>PUPDR14</name>
              <bitOffset>28</bitOffset>
              <bitWidth>2</bitWidth>
            </field>
            <field>
              <name>PUPDR15</name>
              <bitOffset>30</bitOffset>
              <bitWidth>2</bitWidth>
            </field>
          </fields>
        </register>
        <register>
          <name>IDR</name>
          <addressOffset>0x10</addressOffset>
          <size>0x20</size>
        </register>
        <register>
          <name>ODR</name>
          <addressOffset>0x14</addressOffset>
          <size>0x20</size>
        </register>
        <register>
          <name>BSRR</name>
          <addressOffset>0x18</addressOffset>
          <size>0x20</size>
        </register>
        <register>
          <name>LCKR</name>
          <addressOffset>0x1c</addressOffset>
          <size>0x20</size>
          <fields>
            <field>
              <name>LCK0</name>
              <bitOffset>0</bitOffset>
              <bitWidth>1</bitWidth>
            </field>
            <field>
              <name>LCK1</name>
              <bitOffset>1</bitOffset>
              <bitWidth>1</bitWidth>
            </field>
            <field>
              <name>LCK2</name>
              <bitOffset>2</bitOffset>
              <bitWidth>1</bitWidth>
            </field>
            <field>
              <name>LCK3</name>
              <bitOffset>3</bitOffset>
              <bitWidth>1</bitWidth>
            </field>
            <field>
              <name>LCK4</name>
              <bitOffset>4</bitOffset>
              <bitWidth>1</bitWidth>
            </field>
            <field>
              <name>LCK5</name>
              <bitOffset>5</bitOffset>
              <bitWidth>1</bitWidth>
            </field>
            <field>
              <name>LCK6</name>
              <bitOffset>6</bitOffset>
              <bitWidth>1</bitWidth>
            </field>
            <field>
              <name>LCK7</name>
              <bitOffset>7</bitOffset>
              <bitWidth>1</bitWidth>
            </field>
            <field>
              <name>LCK8</name>
              <bitOffset>8</bitOffset>
              <bitWidth>1</bitWidth>
            </field>
            <field>
              <name>LCK9</name>
              <bitOffset>9</bitOffset>
              <bitWidth>1</bitWidth>
            </field>
            <field>
              <name>LCK10</name>
              <bitOffset>10</bitOffset>
              <bitWidth>1</bitWidth>
            </field>
            <field>
              <name>LCK11</name>
              <bitOffset>11</bitOffset>
              <bitWidth>1</bitWidth>
            </field>
            <field>
              <name>LCK12</name>
              <bitOffset>12</bitOffset>
              <bitWidth>1</bitWidth>
            </field>
            <field>
              <name>LCK13</name>
              <bitOffset>13</bitOffset>
              <bitWidth>1</bitWidth>
            </field>
            <field>
              <name>LCK14</name>
              <bitOffset>14</bitOffset>
              <bitWidth>1</bitWidth>
            </field>
            <field>
              <name>LCK15</name>
              <bitOffset>15</bitOffset>
              <bitWidth>1</bitWidth>
            </field>
            <field>
              <name>LCKK</name>
              <bitOffset>16</bitOffset>
              <bitWidth>1</bitWidth>
            </field>
          </fields>
        </register>
        <register>
          <name>AFR.0</name>
          <addressOffset>0x20</addressOffset>
          <size>0x20</size>
          <fields>
            <field>
              <name>AFSEL0</name>
              <bitOffset>0</bitOffset>
              <bitWidth>4</bitWidth>
            </field>
            <field>
              <name>AFSEL1</name>
              <bitOffset>4</bitOffset>
              <bitWidth>4</bitWidth>
            </field>
            <field>
              <name>AFSEL2</name>
              <bitOffset>8</bitOffset>
              <bitWidth>4</bitWidth>
            </field>
            <field>
              <name>AFSEL3</name>
              <bitOffset>12</bitOffset>
              <bitWidth>4</bitWidth>
            </field>
            <field>
              <name>AFSEL4</name>
              <bitOffset>16</bitOffset>
              <bitWidth>4</bitWidth>
            </field>
            <field>
              <name>AFSEL5</name>
              <bitOffset>20</bitOffset>
              <bitWidth>4</bitWidth>
            </field>
            <field>
              <name>AFSEL6</name>
              <bitOffset>24</bitOffset>
              <bitWidth>4</bitWidth>
            </field>
            <field>
              <name>AFSEL7</name>
              <bitOffset>28</bitOffset>
              <bitWidth>4</bitWidth>
            </field>
          </fields>
        </register>
        <register>
          <name>AFR.1</name>
          <addressOffset>0x24</addressOffset>
          <size>0x20</size>
          <fields>
            <field>
              <name>AFSEL8</name>
              <bitOffset>0</bitOffset>
              <bitWidth>4</bitWidth>
            </field>
            <field>
              <name>AFSEL9</name>
              <bitOffset>4</bitOffset>
              <bitWidth>4</bitWidth>
            </field>
            <field>
              <name>AFSEL10</name>
              <bitOffset>8</bitOffset>
              <bitWidth>4</bitWidth>
            </field>
            <field>
              <name>AFSEL11</name>
              <bitOffset>12</bitOffset>
              <bitWidth>4</bitWidth>
            </field>
            <field>
              <name>AFSEL12</name>
              <bitOffset>16</bitOffset>
              <bitWidth>4</bitWidth>
            </field>
            <field>
              <name>AFSEL13</name>
              <bitOffset>20</bitOffset>
              <bitWidth>4</bitWidth>
            </field>
            <field>
              <name>AFSEL14</name>
              <bitOffset>24</bitOffset>
              <bitWidth>4</bitWidth>
            </field>
            <field>
              <name>AFSEL15</name>
              <bitOffset>28</bitOffset>
              <bitWidth>4</bitWidth>
            </field>
          </fields>
        </register>
        <register>
          <name>BRR</name>
          <addressOffset>0x28</addressOffset>
          <size>0x20</size>
        </register>
      </registers>
    </peripheral>
    <peripheral>
      <name>GPIOB</name>
      <baseAddress>0x48000400</baseAddress>
      <registers>
        <register>
          <name>MODER</name>
          <addressOffset>0x0</addressOffset>
          <size>0x20</size>
          <fields>
            <field>
              <name>MODER0</name>
              <bitOffset>0</bitOffset>
              <bitWidth>2</bitWidth>
            </field>
            <field>
              <name>MODER1</name>
              <bitOffset>2</bitOffset>
              <bitWidth>2</bitWidth>
            </field>
            <field>
              <name>MODER2</name>
              <bitOffset>4</bitOffset>
              <bitWidth>2</bitWidth>
            </field>
            <field>
              <name>MODER3</name>
              <bitOffset>6</bitOffset>
              <bitWidth>2</bitWidth>
            </field>
            <field>
              <name>MODER4</name>
              <bitOffset>8</bitOffset>
              <bitWidth>2</bitWidth>
            </field>
            <field>
              <name>MODER5</name>
              <bitOffset>10</bitOffset>
              <bitWidth>2</bitWidth>
            </field>
            <field>
              <name>MODER6</name>
              <bitOffset>12</bitOffset>
              <bitWidth>2</bitWidth>
            </field>
            <field>
              <name>MODER7</name>
              <bitOffset>14</bitOffset>
              <bitWidth>2</bitWidth>
            </field>
            <field>
              <name>MODER8</name>
              <bitOffset>16</bitOffset>
              <bitWidth>2</bitWidth>
            </field>
            <field>
              <name>MODER9</name>
              <bitOffset>18</bitOffset>
              <bitWidth>2</bitWidth>
            </field>
            <field>
              <name>MODER10</name>
              <bitOffset>20</bitOffset>
              <bitWidth>2</bitWidth>
            </field>
            <field>
              <name>MODER11</name>
              <bitOffset>22</bitOffset>
              <bitWidth>2</bitWidth>
            </field>
            <field>
              <name>MODER12</name>
              <bitOffset>24</bitOffset>
              <bitWidth>2</bitWidth>
            </field>
            <field>
              <name>MODER13</name>
              <bitOffset>26</bitOffset>
              <bitWidth>2</bitWidth>
            </field>
            <field>
              <name>MODER14</name>
              <bitOffset>28</bitOffset>
              <bitWidth>2</bitWidth>
            </field>
            <field>
              <name>MODER15</name>
              <bitOffset>30</bitOffset>
              <bitWidth>2</bitWidth>
            </field>
          </fields>
        </register>
        <register>
          <name>OTYPER</name>
          <addressOffset>0x4</addressOffset>
          <size>0x20</size>
        </register>
        <register>
          <name>OSPEEDR</name>
          <addressOffset>0x8</addressOffset>
          <size>0x20</size>
          <fields>
            <field>
              <name>OSPEEDR0</name>
              <bitOffset>0</bitOffset>
              <bitWidth>2</bitWidth>
            </field>
            <field>
              <name>OSPEEDR1</name>
              <bitOffset>2</bitOffset>
              <bitWidth>2</bitWidth>
            </field>
            <field>
              <name>OSPEEDR2</name>
              <bitOffset>4</bitOffset>
              <bitWidth>2</bitWidth>
            </field>
            <field>
              <name>OSPEEDR3</name>
              <bitOffset>6</bitOffset>
              <bitWidth>2</bitWidth>
            </field>
            <field>
              <name>OSPEEDR4</name>
              <bitOffset>8</bitOffset>
              <bitWidth>2</bitWidth>
            </field>
            <field>
              <name>OSPEEDR5</name>
              <bitOffset>10</bitOffset>
              <bitWidth>2</bitWidth>
            </field>
            <field>
              <name>OSPEEDR6</name>
              <bitOffset>12</bitOffset>
              <bitWidth>2</bitWidth>
            </field>
            <field>
              <name>OSPEEDR7</name>
              <bitOffset>14</bitOffset>
              <bitWidth>2</bitWidth>
            </field>
            <field>
              <name>OSPEEDR8</name>
              <bitOffset>16</bitOffset>
              <bitWidth>2</bitWidth>
            </field>
            <field>
              <name>OSPEEDR9</name>
              <bitOffset>18</bitOffset>
              <bitWidth>2</bitWidth>
            </field>
            <field>
              <name>OSPEEDR10</name>
              <bitOffset>20</bitOffset>
              <bitWidth>2</bitWidth>
            </field>
            <field>
              <name>OSPEEDR11</name>
              <bitOffset>22</bitOffset>
              <bitWidth>2</bitWidth>
            </field>
            <field>
              <name>OSPEEDR12</name>
              <bitOffset>24</bitOffset>
              <bitWidth>2</bitWidth>
            </field>
            <field>
              <name>OSPEEDR13</name>
              <bitOffset>26</bitOffset>
              <bitWidth>2</bitWidth>
            </field>
            <field>
              <name>OSPEEDR14</name>
              <bitOffset>28</bitOffset>
              <bitWidth>2</bitWidth>
            </field>
            <field>
              <name>OSPEEDR15</name>
              <bitOffset>30</bitOffset>
              <bitWidth>2</bitWidth>
            </field>
          </fields>
        </register>
        <register>
          <name>PUPDR</name>
          <addressOffset>0xc</addressOffset>
          <size>0x20</size>
          <fields>
            <field>
              <name>PUPDR0</name>
              <bitOffset>0</bitOffset>
              <bitWidth>2</bitWidth>
            </field>
            <field>
              <name>PUPDR1</name>
              <bitOffset>2</bitOffset>
              <bitWidth>2</bitWidth>
            </field>
            <field>
              <name>PUPDR2</name>
              <bitOffset>4</bitOffset>
              <bitWidth>2</bitWidth>
            </field>
            <field>
              <name>PUPDR3</name>
              <bitOffset>6</bitOffset>
              <bitWidth>2</bitWidth>
            </field>
            <field>
              <name>PUPDR4</name>
              <bitOffset>8</bitOffset>
              <bitWidth>2</bitWidth>
            </field>
            <field>
              <name>PUPDR5</name>
              <bitOffset>10</bitOffset>
              <bitWidth>2</bitWidth>
            </field>
            <field>
              <name>PUPDR6</name>
              <bitOffset>12</bitOffset>
              <bitWidth>2</bitWidth>
            </field>
            <field>
              <name>PUPDR7</name>
              <bitOffset>14</bitOffset>
              <bitWidth>2</bitWidth>
            </field>
            <field>
              <name>PUPDR8</name>
              <bitOffset>16</bitOffset>
              <bitWidth>2</bitWidth>
            </field>
            <field>
              <name>PUPDR9</name>
              <bitOffset>18</bitOffset>
              <bitWidth>2</bitWidth>
            </field>
            <field>
              <name>PUPDR10</name>
              <bitOffset>20</bitOffset>
              <bitWidth>2</bitWidth>
            </field>
            <field>
              <name>PUPDR11</name>
              <bitOffset>22</bitOffset>
              <bitWidth>2</bitWidth>
            </field>
            <field>
              <name>PUPDR12</name>
              <bitOffset>24</bitOffset>
              <bitWidth>2</bitWidth>
            </field>
            <field>
              <name>PUPDR13</name>
              <bitOffset>26</bitOffset>
              <bitWidth>2</bitWidth>
            </field>
            <field>
              <name>PUPDR14</name>
              <bitOffset>28</bitOffset>
              <bitWidth>2</bitWidth>
            </field>
            <field>
              <name>PUPDR15</name>
              <bitOffset>30</bitOffset>
              <bitWidth>2</bitWidth>
            </field>
          </fields>
        </register>
        <register>
          <name>IDR</name>
          <addressOffset>0x10</addressOffset>
          <size>0x20</size>
        </register>
        <register>
          <name>ODR</name>
          <addressOffset>0x14</addressOffset>
          <size>0x20</size>
        </register>
        <register>
          <name>BSRR</name>
          <addressOffset>0x18</addressOffset>
          <size>0x20</size>
        </register>
        <register>
          <name>LCKR</name>
          <addressOffset>0x1c</addressOffset>
          <size>0x20</size>
          <fields>
            <field>
              <name>LCK0</name>
              <bitOffset>0</bitOffset>
              <bitWidth>1</bitWidth>
            </field>
            <field>
              <name>LCK1</name>
              <bitOffset>1</bitOffset>
              <bitWidth>1</bitWidth>
            </field>
            <field>
              <name>LCK2</name>
              <bitOffset>2</bitOffset>
              <bitWidth>1</bitWidth>
            </field>
            <field>
              <name>LCK3</name>
              <bitOffset>3</bitOffset>
              <bitWidth>1</bitWidth>
            </field>
            <field>
              <name>LCK4</name>
              <bitOffset>4</bitOffset>
              <bitWidth>1</bitWidth>
            </field>
            <field>
              <name>LCK5</name>
              <bitOffset>5</bitOffset>
              <bitWidth>1</bitWidth>
            </field>
            <field>
              <name>LCK6</name>
              <bitOffset>6</bitOffset>
              <bitWidth>1</bitWidth>
            </field>
            <field>
              <name>LCK7</name>
              <bitOffset>7</bitOffset>
              <bitWidth>1</bitWidth>
            </field>
            <field>
              <name>LCK8</name>
              <bitOffset>8</bitOffset>
              <bitWidth>1</bitWidth>
            </field>
            <field>
              <name>LCK9</name>
              <bitOffset>9</bitOffset>
              <bitWidth>1</bitWidth>
            </field>
            <field>
              <name>LCK10</name>
              <bitOffset>10</bitOffset>
              <bitWidth>1</bitWidth>
            </field>
            <field>
              <name>LCK11</name>
              <bitOffset>11</bitOffset>
              <bitWidth>1</bitWidth>
            </field>
            <field>
              <name>LCK12</name>
              <bitOffset>12</bitOffset>
              <bitWidth>1</bitWidth>
            </field>
            <field>
              <name>LCK13</name>
              <bitOffset>13</bitOffset>
              <bitWidth>1</bitWidth>
            </field>
            <field>
              <name>LCK14</name>
              <bitOffset>14</bitOffset>
              <bitWidth>1</bitWidth>
            </field>
            <field>
              <name>LCK15</name>
              <bitOffset>15</bitOffset>
              <bitWidth>1</bitWidth>
            </field>
            <field>
              <name>LCKK</name>
              <bitOffset>16</bitOffset>
              <bitWidth>1</bitWidth>
            </field>
          </fields>
        </register>
        <register>
          <name>AFR.0</name>
          <addressOffset>0x20</addressOffset>
          <size>0x20</size>
          <fields>
            <field>
              <name>AFSEL0</name>
              <bitOffset>0</bitOffset>
              <bitWidth>4</bitWidth>
            </field>
            <field>
              <name>AFSEL1</name>
              <bitOffset>4</bitOffset>
              <bitWidth>4</bitWidth>
            </field>
            <field>
              <name>AFSEL2</name>
              <bitOffset>8</bitOffset>
              <bitWidth>4</bitWidth>
            </field>
            <field>
              <name>AFSEL3</name>
              <bitOffset>12</bitOffset>
              <bitWidth>4</bitWidth>
            </field>
            <field>
              <name>AFSEL4</name>
              <bitOffset>16</bitOffset>
              <bitWidth>4</bitWidth>
            </field>
            <field>
              <name>AFSEL5</name>
              <bitOffset>20</bitOffset>
              <bitWidth>4</bitWidth>
            </field>
            <field>
              <name>AFSEL6</name>
              <bitOffset>24</bitOffset>
              <bitWidth>4</bitWidth>
            </field>
            <field>
              <name>AFSEL7</name>
              <bitOffset>28</bitOffset>
              <bitWidth>4</bitWidth>
            </field>
          </fields>
        </register>
        <register>
          <name>AFR.1</name>
          <addressOffset>0x24</addressOffset>
          <size>0x20</size>
          <fields>
            <field>
              <name>AFSEL8</name>
              <bitOffset>0</bitOffset>
              <bitWidth>4</bitWidth>
            </field>
            <field>
              <name>AFSEL9</name>
              <bitOffset>4</bitOffset>
              <bitWidth>4</bitWidth>
            </field>
            <field>
              <name>AFSEL10</name>
              <bitOffset>8</bitOffset>
              <bitWidth>4</bitWidth>
            </field>
            <field>
              <name>AFSEL11</name>
              <bitOffset>12</bitOffset>
              <bitWidth>4</bitWidth>
            </field>
            <field>
              <name>AFSEL12</name>
              <bitOffset>16</bitOffset>
              <bitWidth>4</bitWidth>
            </field>
            <field>
              <name>AFSEL13</name>
              <bitOffset>20</bitOffset>
              <bitWidth>4</bitWidth>
            </field>
            <field>
              <name>AFSEL14</name>
              <bitOffset>24</bitOffset>
              <bitWidth>4</bitWidth>
            </field>
            <field>
              <name>AFSEL15</name>
              <bitOffset>28</bitOffset>
              <bitWidth>4</bitWidth>
            </field>
          </fields>
        </register>
        <register>
          <name>BRR</name>
          <addressOffset>0x28</addressOffset>
          <size>0x20</size>
        </register>
      </registers>
    </peripheral>
    <peripheral>
      <name>GPIOC</name>
      <baseAddress>0x48000800</baseAddress>
      <registers>
        <register>
          <name>MODER</name>
          <addressOffset>0x0</addressOffset>
          <size>0x20</size>
          <fields>
            <field>
              <name>MODER0</name>
              <bitOffset>0</bitOffset>
              <bitWidth>2</bitWidth>
            </field>
            <field>
              <name>MODER1</name>
              <bitOffset>2</bitOffset>
              <bitWidth>2</bitWidth>
            </field>
            <field>
              <name>MODER2</name>
              <bitOffset>4</bitOffset>
              <bitWidth>2</bitWidth>
            </field>
            <field>
              <name>MODER3</name>
              <bitOffset>6</bitOffset>
              <bitWidth>2</bitWidth>
            </field>
            <field>
              <name>MODER4</name>
              <bitOffset>8</bitOffset>
              <bitWidth>2</bitWidth>
            </field>
            <field>
              <name>MODER5</name>
              <bitOffset>10</bitOffset>
              <bitWidth>2</bitWidth>
            </field>
            <field>
              <name>MODER6</name>
              <bitOffset>12</bitOffset>
              <bitWidth>2</bitWidth>
            </field>
            <field>
              <name>MODER7</name>
              <bitOffset>14</bitOffset>
              <bitWidth>2</bitWidth>
            </field>
            <field>
              <name>MODER8</name>
              <bitOffset>16</bitOffset>
              <bitWidth>2</bitWidth>
            </field>
            <field>
              <name>MODER9</name>
              <bitOffset>18</bitOffset>
              <bitWidth>2</bitWidth>
            </field>
            <field>
              <name>MODER10</name>
              <bitOffset>20</bitOffset>
              <bitWidth>2</bitWidth>
            </field>
            <field>
              <name>MODER11</name>
              <bitOffset>22</bitOffset>
              <bitWidth>2</bitWidth>
            </field>
            <field>
              <name>MODER12</name>
              <bitOffset>24</bitOffset>
              <bitWidth>2</bitWidth>
            </field>
            <field>
              <name>MODER13</name>
              <bitOffset>26</bitOffset>
              <bitWidth>2</bitWidth>
            </field>
            <field>
              <name>MODER14</name>
              <bitOffset>28</bitOffset>
              <bitWidth>2</bitWidth>
            </field>
            <field>
              <name>MODER15</name>
              <bitOffset>30</bitOffset>
              <bitWidth>2</bitWidth>
            </field>
          </fields>
        </register>
        <register>
          <name>OTYPER</name>
          <addressOffset>0x4</addressOffset>
          <size>0x20</size>
        </register>
        <register>
          <name>OSPEEDR</name>
          <addressOffset>0x8</addressOffset>
          <size>0x20</size>
          <fields>
            <field>
              <name>OSPEEDR0</name>
              <bitOffset>0</bitOffset>
              <bitWidth>2</bitWidth>
            </field>
            <field>
              <name>OSPEEDR1</name>
              <bitOffset>2</bitOffset>
              <bitWidth>2</bitWidth>
            </field>
            <field>
              <name>OSPEEDR2</name>
              <bitOffset>4</bitOffset>
              <bitWidth>2</bitWidth>
            </field>
            <field>
              <name>OSPEEDR3</name>
              <bitOffset>6</bitOffset>
              <bitWidth>2</bitWidth>
            </field>
            <field>
              <name>OSPEEDR4</name>
              <bitOffset>8</bitOffset>
              <bitWidth>2</bitWidth>
            </field>
            <field>
              <name>OSPEEDR5</name>
              <bitOffset>10</bitOffset>
              <bitWidth>2</bitWidth>
            </field>
            <field>
              <name>OSPEEDR6</name>
              <bitOffset>12</bitOffset>
              <bitWidth>2</bitWidth>
            </field>
            <field>
              <name>OSPEEDR7</name>
              <bitOffset>14</bitOffset>
              <bitWidth>2</bitWidth>
            </field>
            <field>
              <name>OSPEEDR8</name>
              <bitOffset>16</bitOffset>
              <bitWidth>2</bitWidth>
            </field>
            <field>
              <name>OSPEEDR9</name>
              <bitOffset>18</bitOffset>
              <bitWidth>2</bitWidth>
            </field>
            <field>
              <name>OSPEEDR10</name>
              <bitOffset>20</bitOffset>
              <bitWidth>2</bitWidth>
            </field>
            <field>
              <name>OSPEEDR11</name>
              <bitOffset>22</bitOffset>
              <bitWidth>2</bitWidth>
            </field>
            <field>
              <name>OSPEEDR12</name>
              <bitOffset>24</bitOffset>
              <bitWidth>2</bitWidth>
            </field>
            <field>
              <name>OSPEEDR13</name>
              <bitOffset>26</bitOffset>
              <bitWidth>2</bitWidth>
            </field>
            <field>
              <name>OSPEEDR14</name>
              <bitOffset>28</bitOffset>
              <bitWidth>2</bitWidth>
            </field>
            <field>
              <name>OSPEEDR15</name>
              <bitOffset>30</bitOffset>
              <bitWidth>2</bitWidth>
            </field>
          </fields>
        </register>
        <register>
          <name>PUPDR</name>
          <addressOffset>0xc</addressOffset>
          <size>0x20</size>
          <fields>
            <field>
              <name>PUPDR0</name>
              <bitOffset>0</bitOffset>
              <bitWidth>2</bitWidth>
            </field>
            <field>
              <name>PUPDR1</name>
              <bitOffset>2</bitOffset>
              <bitWidth>2</bitWidth>
            </field>
            <field>
              <name>PUPDR2</name>
              <bitOffset>4</bitOffset>
              <bitWidth>2</bitWidth>
            </field>
            <field>
              <name>PUPDR3</name>
              <bitOffset>6</bitOffset>
              <bitWidth>2</bitWidth>
            </field>
            <field>
              <name>PUPDR4</name>
              <bitOffset>8</bitOffset>
              <bitWidth>2</bitWidth>
            </field>
            <field>
              <name>PUPDR5</name>
              <bitOffset>10</bitOffset>
              <bitWidth>2</bitWidth>
            </field>
            <field>
              <name>PUPDR6</name>
              <bitOffset>12</bitOffset>
              <bitWidth>2</bitWidth>
            </field>
            <field>
              <name>PUPDR7</name>
              <bitOffset>14</bitOffset>
              <bitWidth>2</bitWidth>
            </field>
            <field>
              <name>PUPDR8</name>
              <bitOffset>16</bitOffset>
              <bitWidth>2</bitWidth>
            </field>
            <field>
              <name>PUPDR9</name>
              <bitOffset>18</bitOffset>
              <bitWidth>2</bitWidth>
            </field>
            <field>
              <name>PUPDR10</name>
              <bitOffset>20</bitOffset>
              <bitWidth>2</bitWidth>
            </field>
            <field>
              <name>PUPDR11</name>
              <bitOffset>22</bitOffset>
              <bitWidth>2</bitWidth>
            </field>
            <field>
              <name>PUPDR12</name>
              <bitOffset>24</bitOffset>
              <bitWidth>2</bitWidth>
            </field>
            <field>
              <name>PUPDR13</name>
              <bitOffset>26</bitOffset>
              <bitWidth>2</bitWidth>
            </field>
            <field>
              <name>PUPDR14</name>
              <bitOffset>28</bitOffset>
              <bitWidth>2</bitWidth>
            </field>
            <field>
              <name>PUPDR15</name>
              <bitOffset>30</bitOffset>
              <bitWidth>2</bitWidth>
            </field>
          </fields>
        </register>
        <register>
          <name>IDR</name>
          <addressOffset>0x10</addressOffset>
          <size>0x20</size>
        </register>
        <register>
          <name>ODR</name>
          <addressOffset>0x14</addressOffset>
          <size>0x20</size>
        </register>
        <register>
          <name>BSRR</name>
          <addressOffset>0x18</addressOffset>
          <size>0x20</size>
        </register>
        <register>
          <name>LCKR</name>
          <addressOffset>0x1c</addressOffset>
          <size>0x20</size>
          <fields>
            <field>
              <name>LCK0</name>
              <bitOffset>0</bitOffset>
              <bitWidth>1</bitWidth>
            </field>
            <field>
              <name>LCK1</name>
              <bitOffset>1</bitOffset>
              <bitWidth>1</bitWidth>
            </field>
            <field>
              <name>LCK2</name>
              <bitOffset>2</bitOffset>
              <bitWidth>1</bitWidth>
            </field>
            <field>
              <name>LCK3</name>
              <bitOffset>3</bitOffset>
              <bitWidth>1</bitWidth>
            </field>
            <field>
              <name>LCK4</name>
              <bitOffset>4</bitOffset>
              <bitWidth>1</bitWidth>
            </field>
            <field>
              <name>LCK5</name>
              <bitOffset>5</bitOffset>
              <bitWidth>1</bitWidth>
            </field>
            <field>
              <name>LCK6</name>
              <bitOffset>6</bitOffset>
              <bitWidth>1</bitWidth>
            </field>
            <field>
              <name>LCK7</name>
              <bitOffset>7</bitOffset>
              <bitWidth>1</bitWidth>
            </field>
            <field>
              <name>LCK8</name>
              <bitOffset>8</bitOffset>
              <bitWidth>1</bitWidth>
            </field>
            <field>
              <name>LCK9</name>
              <bitOffset>9</bitOffset>
              <bitWidth>1</bitWidth>
            </field>
            <field>
              <name>LCK10</name>
              <bitOffset>10</bitOffset>
              <bitWidth>1</bitWidth>
            </field>
            <field>
              <name>LCK11</name>
              <bitOffset>11</bitOffset>
              <bitWidth>1</bitWidth>
            </field>
            <field>
              <name>LCK12</name>
              <bitOffset>12</bitOffset>
              <bitWidth>1</bitWidth>
            </field>
            <field>
              <name>LCK13</name>
              <bitOffset>13</bitOffset>
              <bitWidth>1</bitWidth>
            </field>
            <field>
              <name>LCK14</name>
              <bitOffset>14</bitOffset>
              <bitWidth>1</bitWidth>
            </field>
            <field>
              <name>LCK15</name>
              <bitOffset>15</bitOffset>
              <bitWidth>1</bitWidth>
            </field>
            <field>
              <name>LCKK</name>
              <bitOffset>16</bitOffset>
              <bitWidth>1</bitWidth>
            </field>
          </fields>
        </register>
        <register>
          <name>AFR.0</name>
          <addressOffset>0x20</addressOffset>
          <size>0x20</size>
          <fields>
            <field>
              <name>AFSEL0</name>
              <bitOffset>0</bitOffset>
              <bitWidth>4</bitWidth>
            </field>
            <field>
              <name>AFSEL1</name>
              <bitOffset>4</bitOffset>
              <bitWidth>4</bitWidth>
            </field>
            <field>
              <name>AFSEL2</name>
              <bitOffset>8</bitOffset>
              <bitWidth>4</bitWidth>
            </field>
            <field>
              <name>AFSEL3</name>
              <bitOffset>12</bitOffset>
              <bitWidth>4</bitWidth>
            </field>
            <field>
              <name>AFSEL4</name>
              <bitOffset>16</bitOffset>
              <bitWidth>4</bitWidth>
            </field>
            <field>
              <name>AFSEL5</name>
              <bitOffset>20</bitOffset>
              <bitWidth>4</bitWidth>
            </field>
            <field>
              <name>AFSEL6</name>
              <bitOffset>24</bitOffset>
              <bitWidth>4</bitWidth>
            </field>
            <field>
              <name>AFSEL7</name>
              <bitOffset>28</bitOffset>
              <bitWidth>4</bitWidth>
            </field>
          </fields>
        </register>
        <register>
          <name>AFR.1</name>
          <addressOffset>0x24</addressOffset>
          <size>0x20</size>
          <fields>
            <field>
              <name>AFSEL8</name>
              <bitOffset>0</bitOffset>
              <bitWidth>4</bitWidth>
            </field>
            <field>
              <name>AFSEL9</name>
              <bitOffset>4</bitOffset>
              <bitWidth>4</bitWidth>
            </field>
            <field>
              <name>AFSEL10</name>
              <bitOffset>8</bitOffset>
              <bitWidth>4</bitWidth>
            </field>
            <field>
              <name>AFSEL11</name>
              <bitOffset>12</bitOffset>
              <bitWidth>4</bitWidth>
            </field>
            <field>
              <name>AFSEL12</name>
              <bitOffset>16</bitOffset>
              <bitWidth>4</bitWidth>
            </field>
            <field>
              <name>AFSEL13</name>
              <bitOffset>20</bitOffset>
              <bitWidth>4</bitWidth>
            </field>
            <field>
              <name>AFSEL14</name>
              <bitOffset>24</bitOffset>
              <bitWidth>4</bitWidth>
            </field>
            <field>
              <name>AFSEL15</name>
              <bitOffset>28</bitOffset>
              <bitWidth>4</bitWidth>
            </field>
          </fields>
        </register>
        <register>
          <name>BRR</name>
          <addressOffset>0x28</addressOffset>
          <size>0x20</size>
        </register>
      </registers>
    </peripheral>
    <peripheral>
      <name>GPIOD</name>
      <baseAddress>0x48000c00</baseAddress>
      <registers>
        <register>
          <name>MODER</name>
          <addressOffset>0x0</addressOffset>
          <size>0x20</size>
          <fields>
            <field>
              <name>MODER0</name>
              <bitOffset>0</bitOffset>
              <bitWidth>2</bitWidth>
            </field>
            <field>
              <name>MODER1</name>
              <bitOffset>2</bitOffset>
              <bitWidth>2</bitWidth>
            </field>
            <field>
              <name>MODER2</name>
              <bitOffset>4</bitOffset>
              <bitWidth>2</bitWidth>
            </field>
            <field>
              <name>MODER3</name>
              <bitOffset>6</bitOffset>
              <bitWidth>2</bitWidth>
            </field>
            <field>
              <name>MODER4</name>
              <bitOffset>8</bitOffset>
              <bitWidth>2</bitWidth>
            </field>
            <field>
              <name>MODER5</name>
              <bitOffset>10</bitOffset>
              <bitWidth>2</bitWidth>
            </field>
            <field>
              <name>MODER6</name>
              <bitOffset>12</bitOffset>
              <bitWidth>2</bitWidth>
            </field>
            <field>
              <name>MODER7</name>
              <bitOffset>14</bitOffset>
              <bitWidth>2</bitWidth>
            </field>
            <field>
              <name>MODER8</name>
              <bitOffset>16</bitOffset>
              <bitWidth>2</bitWidth>
            </field>
            <field>
              <name>MODER9</name>
              <bitOffset>18</bitOffset>
              <bitWidth>2</bitWidth>
            </field>
            <field>
              <name>MODER10</name>
              <bitOffset>20</bitOffset>
              <bitWidth>2</bitWidth>
            </field>
            <field>
              <name>MODER11</name>
              <bitOffset>22</bitOffset>
              <bitWidth>2</bitWidth>
            </field>
            <field>
              <name>MODER12</name>
              <bitOffset>24</bitOffset>
              <bitWidth>2</bitWidth>
            </field>
            <field>
              <name>MODER13</name>
              <bitOffset>26</bitOffset>
              <bitWidth>2</bitWidth>
            </field>
            <field>
              <name>MODER14</name>
              <bitOffset>28</bitOffset>
              <bitWidth>2</bitWidth>
            </field>
            <field>
              <name>MODER15</name>
              <bitOffset>30</bitOffset>
              <bitWidth>2</bitWidth>
            </field>
          </fields>
        </register>
        <register>
          <name>OTYPER</name>
          <addressOffset>0x4</addressOffset>
          <size>0x20</size>
        </register>
        <register>
          <name>OSPEEDR</name>
          <addressOffset>0x8</addressOffset>
          <size>0x20</size>
          <fields>
            <field>
              <name>OSPEEDR0</name>
              <bitOffset>0</bitOffset>
              <bitWidth>2</bitWidth>
            </field>
            <field>
              <name>OSPEEDR1</name>
              <bitOffset>2</bitOffset>
              <bitWidth>2</bitWidth>
            </field>
            <field>
              <name>OSPEEDR2</name>
              <bitOffset>4</bitOffset>
              <bitWidth>2</bitWidth>
            </field>
            <field>
              <name>OSPEEDR3</name>
              <bitOffset>6</bitOffset>
              <bitWidth>2</bitWidth>
            </field>
            <field>
              <name>OSPEEDR4</name>
              <bitOffset>8</bitOffset>
              <bitWidth>2</bitWidth>
            </field>
            <field>
              <name>OSPEEDR5</name>
              <bitOffset>10</bitOffset>
              <bitWidth>2</bitWidth>
            </field>
            <field>
              <name>OSPEEDR6</name>
              <bitOffset>12</bitOffset>
              <bitWidth>2</bitWidth>
            </field>
            <field>
              <name>OSPEEDR7</name>
              <bitOffset>14</bitOffset>
              <bitWidth>2</bitWidth>
            </field>
            <field>
              <name>OSPEEDR8</name>
              <bitOffset>16</bitOffset>
              <bitWidth>2</bitWidth>
            </field>
            <field>
              <name>OSPEEDR9</name>
              <bitOffset>18</bitOffset>
              <bitWidth>2</bitWidth>
            </field>
            <field>
              <name>OSPEEDR10</name>
              <bitOffset>20</bitOffset>
              <bitWidth>2</bitWidth>
            </field>
            <field>
              <name>OSPEEDR11</name>
              <bitOffset>22</bitOffset>
              <bitWidth>2</bitWidth>
            </field>
            <field>
              <name>OSPEEDR12</name>
              <bitOffset>24</bitOffset>
              <bitWidth>2</bitWidth>
            </field>
            <field>
              <name>OSPEEDR13</name>
              <bitOffset>26</bitOffset>
              <bitWidth>2</bitWidth>
            </field>
            <field>
              <name>OSPEEDR14</name>
              <bitOffset>28</bitOffset>
              <bitWidth>2</bitWidth>
            </field>
            <field>
              <name>OSPEEDR15</name>
              <bitOffset>30</bitOffset>
              <bitWidth>2</bitWidth>
            </field>
          </fields>
        </register>
        <register>
          <name>PUPDR</name>
          <addressOffset>0xc</addressOffset>
          <size>0x20</size>
          <fields>
            <field>
              <name>PUPDR0</name>
              <bitOffset>0</bitOffset>
              <bitWidth>2</bitWidth>
            </field>
            <field>
              <name>PUPDR1</name>
              <bitOffset>2</bitOffset>
              <bitWidth>2</bitWidth>
            </field>
            <field>
              <name>PUPDR2</name>
              <bitOffset>4</bitOffset>
              <bitWidth>2</bitWidth>
            </field>
            <field>
              <name>PUPDR3</name>
              <bitOffset>6</bitOffset>
              <bitWidth>2</bitWidth>
            </field>
            <field>
              <name>PUPDR4</name>
              <bitOffset>8</bitOffset>
              <bitWidth>2</bitWidth>
            </field>
            <field>
              <name>PUPDR5</name>
              <bitOffset>10</bitOffset>
              <bitWidth>2</bitWidth>
            </field>
            <field>
              <name>PUPDR6</name>
              <bitOffset>12</bitOffset>
              <bitWidth>2</bitWidth>
            </field>
            <field>
              <name>PUPDR7</name>
              <bitOffset>14</bitOffset>
              <bitWidth>2</bitWidth>
            </field>
            <field>
              <name>PUPDR8</name>
              <bitOffset>16</bitOffset>
              <bitWidth>2</bitWidth>
            </field>
            <field>
              <name>PUPDR9</name>
              <bitOffset>18</bitOffset>
              <bitWidth>2</bitWidth>
            </field>
            <field>
              <name>PUPDR10</name>
              <bitOffset>20</bitOffset>
              <bitWidth>2</bitWidth>
            </field>
            <field>
              <name>PUPDR11</name>
              <bitOffset>22</bitOffset>
              <bitWidth>2</bitWidth>
            </field>
            <field>
              <name>PUPDR12</name>
              <bitOffset>24</bitOffset>
              <bitWidth>2</bitWidth>
            </field>
            <field>
              <name>PUPDR13</name>
              <bitOffset>26</bitOffset>
              <bitWidth>2</bitWidth>
            </field>
            <field>
              <name>PUPDR14</name>
              <bitOffset>28</bitOffset>
              <bitWidth>2</bitWidth>
            </field>
            <field>
              <name>PUPDR15</name>
              <bitOffset>30</bitOffset>
              <bitWidth>2</bitWidth>
            </field>
          </fields>
        </register>
        <register>
          <name>IDR</name>
          <addressOffset>0x10</addressOffset>
          <size>0x20</size>
        </register>
        <register>
          <name>ODR</name>
          <addressOffset>0x14</addressOffset>
          <size>0x20</size>
        </register>
        <register>
          <name>BSRR</name>
          <addressOffset>0x18</addressOffset>
          <size>0x20</size>
        </register>
        <register>
          <name>LCKR</name>
          <addressOffset>0x1c</addressOffset>
          <size>0x20</size>
          <fields>
            <field>
              <name>LCK0</name>
              <bitOffset>0</bitOffset>
              <bitWidth>1</bitWidth>
            </field>
            <field>
              <name>LCK1</name>
              <bitOffset>1</bitOffset>
              <bitWidth>1</bitWidth>
            </field>
            <field>
              <name>LCK2</name>
              <bitOffset>2</bitOffset>
              <bitWidth>1</bitWidth>
            </field>
            <field>
              <name>LCK3</name>
              <bitOffset>3</bitOffset>
              <bitWidth>1</bitWidth>
            </field>
            <field>
              <name>LCK4</name>
              <bitOffset>4</bitOffset>
              <bitWidth>1</bitWidth>
            </field>
            <field>
              <name>LCK5</name>
              <bitOffset>5</bitOffset>
              <bitWidth>1</bitWidth>
            </field>
            <field>
              <name>LCK6</name>
              <bitOffset>6</bitOffset>
              <bitWidth>1</bitWidth>
            </field>
            <field>
              <name>LCK7</name>
              <bitOffset>7</bitOffset>
              <bitWidth>1</bitWidth>
            </field>
            <field>
              <name>LCK8</name>
              <bitOffset>8</bitOffset>
              <bitWidth>1</bitWidth>
            </field>
            <field>
              <name>LCK9</name>
              <bitOffset>9</bitOffset>
              <bitWidth>1</bitWidth>
            </field>
            <field>
              <name>LCK10</name>
              <bitOffset>10</bitOffset>
              <bitWidth>1</bitWidth>
            </field>
            <field>
              <name>LCK11</name>
              <bitOffset>11</bitOffset>
              <bitWidth>1</bitWidth>
            </field>
            <field>
              <name>LCK12</name>
              <bitOffset>12</bitOffset>
              <bitWidth>1</bitWidth>
            </field>
            <field>
              <name>LCK13</name>
              <bitOffset>13</bitOffset>
              <bitWidth>1</bitWidth>
            </field>
            <field>
              <name>LCK14</name>
              <bitOffset>14</bitOffset>
              <bitWidth>1</bitWidth>
            </field>
            <field>
              <name>LCK15</name>
              <bitOffset>15</bitOffset>
              <bitWidth>1</bitWidth>
            </field>
            <field>
              <name>LCKK</name>
              <bitOffset>16</bitOffset>
              <bitWidth>1</bitWidth>
            </field>
          </fields>
        </register>
        <register>
          <name>AFR.0</name>
          <addressOffset>0x20</addressOffset>
          <size>0x20</size>
          <fields>
            <field>
              <name>AFSEL0</name>
              <bitOffset>0</bitOffset>
              <bitWidth>4</bitWidth>
            </field>
            <field>
              <name>AFSEL1</name>
              <bitOffset>4</bitOffset>
              <bitWidth>4</bitWidth>
            </field>
            <field>
              <name>AFSEL2</name>
              <bitOffset>8</bitOffset>
              <bitWidth>4</bitWidth>
            </field>
            <field>
              <name>AFSEL3</name>
              <bitOffset>12</bitOffset>
              <bitWidth>4</bitWidth>
            </field>
            <field>
              <name>AFSEL4</name>
              <bitOffset>16</bitOffset>
              <bitWidth>4</bitWidth>
            </field>
            <field>
              <name>AFSEL5</name>
              <bitOffset>20</bitOffset>
              <bitWidth>4</bitWidth>
            </field>
            <field>
              <name>AFSEL6</name>
              <bitOffset>24</bitOffset>
              <bitWidth>4</bitWidth>
            </field>
            <field>
              <name>AFSEL7</name>
              <bitOffset>28</bitOffset>
              <bitWidth>4</bitWidth>
            </field>
          </fields>
        </register>
        <register>
          <name>AFR.1</name>
          <addressOffset>0x24</addressOffset>
          <size>0x20</size>
          <fields>
            <field>
              <name>AFSEL8</name>
              <bitOffset>0</bitOffset>
              <bitWidth>4</bitWidth>
            </field>
            <field>
              <name>AFSEL9</name>
              <bitOffset>4</bitOffset>
              <bitWidth>4</bitWidth>
            </field>
            <field>
              <name>AFSEL10</name>
              <bitOffset>8</bitOffset>
              <bitWidth>4</bitWidth>
            </field>
            <field>
              <name>AFSEL11</name>
              <bitOffset>12</bitOffset>
              <bitWidth>4</bitWidth>
            </field>
            <field>
              <name>AFSEL12</name>
              <bitOffset>16</bitOffset>
              <bitWidth>4</bitWidth>
            </field>
            <field>
              <name>AFSEL13</name>
              <bitOffset>20</bitOffset>
              <bitWidth>4</bitWidth>
            </field>
            <field>
              <name>AFSEL14</name>
              <bitOffset>24</bitOffset>
              <bitWidth>4</bitWidth>
            </field>
            <field>
              <name>AFSEL15</name>
              <bitOffset>28</bitOffset>
              <bitWidth>4</bitWidth>
            </field>
          </fields>
        </register>
        <register>
          <name>BRR</name>
          <addressOffset>0x28</addressOffset>
          <size>0x20</size>
        </register>
      </registers>
    </peripheral>
    <peripheral>
      <name>GPIOE</name>
      <baseAddress>0x48001000</baseAddress>
      <registers>
        <register>
          <name>MODER</name>
          <addressOffset>0x0</addressOffset>
          <size>0x20</size>
          <fields>
            <field>
              <name>MODER0</name>
              <bitOffset>0</bitOffset>
              <bitWidth>2</bitWidth>
            </field>
            <field>
              <name>MODER1</name>
              <bitOffset>2</bitOffset>
              <bitWidth>2</bitWidth>
            </field>
            <field>
              <name>MODER2</name>
              <bitOffset>4</bitOffset>
              <bitWidth>2</bitWidth>
            </field>
            <field>
              <name>MODER3</name>
              <bitOffset>6</bitOffset>
              <bitWidth>2</bitWidth>
            </field>
            <field>
              <name>MODER4</name>
              <bitOffset>8</bitOffset>
              <bitWidth>2</bitWidth>
            </field>
            <field>
              <name>MODER5</name>
              <bitOffset>10</bitOffset>
              <bitWidth>2</bitWidth>
            </field>
            <field>
              <name>MODER6</name>
              <bitOffset>12</bitOffset>
              <bitWidth>2</bitWidth>
            </field>
            <field>
              <name>MODER7</name>
              <bitOffset>14</bitOffset>
              <bitWidth>2</bitWidth>
            </field>
            <field>
              <name>MODER8</name>
              <bitOffset>16</bitOffset>
              <bitWidth>2</bitWidth>
            </field>
            <field>
              <name>MODER9</name>
              <bitOffset>18</bitOffset>
              <bitWidth>2</bitWidth>
            </field>
            <field>
              <name>MODER10</name>
              <bitOffset>20</bitOffset>
              <bitWidth>2</bitWidth>
            </field>
            <field>
              <name>MODER11</name>
              <bitOffset>22</bitOffset>
              <bitWidth>2</bitWidth>
            </field>
            <field>
              <name>MODER12</name>
              <bitOffset>24</bitOffset>
              <bitWidth>2</bitWidth>
            </field>
            <field>
              <name>MODER13</name>
              <bitOffset>26</bitOffset>
              <bitWidth>2</bitWidth>
            </field>
            <field>
              <name>MODER14</name>
              <bitOffset>28</bitOffset>
              <bitWidth>2</bitWidth>
            </field>
            <field>
              <name>MODER15</name>
              <bitOffset>30</bitOffset>
              <bitWidth>2</bitWidth>
            </field>
          </fields>
        </register>
        <register>
          <name>OTYPER</name>
          <addressOffset>0x4</addressOffset>
          <size>0x20</size>
        </register>
        <register>
          <name>OSPEEDR</name>
          <addressOffset>0x8</addressOffset>
          <size>0x20</size>
          <fields>
            <field>
              <name>OSPEEDR0</name>
              <bitOffset>0</bitOffset>
              <bitWidth>2</bitWidth>
            </field>
            <field>
              <name>OSPEEDR1</name>
              <bitOffset>2</bitOffset>
              <bitWidth>2</bitWidth>
            </field>
            <field>
              <name>OSPEEDR2</name>
              <bitOffset>4</bitOffset>
              <bitWidth>2</bitWidth>
            </field>
            <field>
              <name>OSPEEDR3</name>
              <bitOffset>6</bitOffset>
              <bitWidth>2</bitWidth>
            </field>
            <field>
              <name>OSPEEDR4</name>
              <bitOffset>8</bitOffset>
              <bitWidth>2</bitWidth>
            </field>
            <field>
              <name>OSPEEDR5</name>
              <bitOffset>10</bitOffset>
              <bitWidth>2</bitWidth>
            </field>
            <field>
              <name>OSPEEDR6</name>
              <bitOffset>12</bitOffset>
              <bitWidth>2</bitWidth>
            </field>
            <field>
              <name>OSPEEDR7</name>
              <bitOffset>14</bitOffset>
              <bitWidth>2</bitWidth>
            </field>
            <field>
              <name>OSPEEDR8</name>
              <bitOffset>16</bitOffset>
              <bitWidth>2</bitWidth>
            </field>
            <field>
              <name>OSPEEDR9</name>
              <bitOffset>18</bitOffset>
              <bitWidth>2</bitWidth>
            </field>
            <field>
              <name>OSPEEDR10</name>
              <bitOffset>20</bitOffset>
              <bitWidth>2</bitWidth>
            </field>
            <field>
              <name>OSPEEDR11</name>
              <bitOffset>22</bitOffset>
              <bitWidth>2</bitWidth>
            </field>
            <field>
              <name>OSPEEDR12</name>
              <bitOffset>24</bitOffset>
              <bitWidth>2</bitWidth>
            </field>
            <field>
              <name>OSPEEDR13</name>
              <bitOffset>26</bitOffset>
              <bitWidth>2</bitWidth>
            </field>
            <field>
              <name>OSPEEDR14</name>
              <bitOffset>28</bitOffset>
              <bitWidth>2</bitWidth>
            </field>
            <field>
              <name>OSPEEDR15</name>
              <bitOffset>30</bitOffset>
              <bitWidth>2</bitWidth>
            </field>
          </fields>
        </register>
        <register>
          <name>PUPDR</name>
          <addressOffset>0xc</addressOffset>
          <size>0x20</size>
          <fields>
            <field>
              <name>PUPDR0</name>
              <bitOffset>0</bitOffset>
              <bitWidth>2</bitWidth>
            </field>
            <field>
              <name>PUPDR1</name>
              <bitOffset>2</bitOffset>
              <bitWidth>2</bitWidth>
            </field>
            <field>
              <name>PUPDR2</name>
              <bitOffset>4</bitOffset>
              <bitWidth>2</bitWidth>
            </field>
            <field>
              <name>PUPDR3</name>
              <bitOffset>6</bitOffset>
              <bitWidth>2</bitWidth>
            </field>
            <field>
              <name>PUPDR4</name>
              <bitOffset>8</bitOffset>
              <bitWidth>2</bitWidth>
            </field>
            <field>
              <name>PUPDR5</name>
              <bitOffset>10</bitOffset>
              <bitWidth>2</bitWidth>
            </field>
            <field>
              <name>PUPDR6</name>
              <bitOffset>12</bitOffset>
              <bitWidth>2</bitWidth>
            </field>
            <field>
              <name>PUPDR7</name>
              <bitOffset>14</bitOffset>
              <bitWidth>2</bitWidth>
            </field>
            <field>
              <name>PUPDR8</name>
              <bitOffset>16</bitOffset>
              <bitWidth>2</bitWidth>
            </field>
            <field>
              <name>PUPDR9</name>
              <bitOffset>18</bitOffset>
              <bitWidth>2</bitWidth>
            </field>
            <field>
              <name>PUPDR10</name>
              <bitOffset>20</bitOffset>
              <bitWidth>2</bitWidth>
            </field>
            <field>
              <name>PUPDR11</name>
              <bitOffset>22</bitOffset>
              <bitWidth>2</bitWidth>
            </field>
            <field>
              <name>PUPDR12</name>
              <bitOffset>24</bitOffset>
              <bitWidth>2</bitWidth>
            </field>
            <field>
              <name>PUPDR13</name>
              <bitOffset>26</bitOffset>
              <bitWidth>2</bitWidth>
            </field>
            <field>
              <name>PUPDR14</name>
              <bitOffset>28</bitOffset>
              <bitWidth>2</bitWidth>
            </field>
            <field>
              <name>PUPDR15</name>
              <bitOffset>30</bitOffset>
              <bitWidth>2</bitWidth>
            </field>
          </fields>
        </register>
        <register>
          <name>IDR</name>
          <addressOffset>0x10</addressOffset>
          <size>0x20</size>
        </register>
        <register>
          <name>ODR</name>
          <addressOffset>0x14</addressOffset>
          <size>0x20</size>
        </register>
        <register>
          <name>BSRR</name>
          <addressOffset>0x18</addressOffset>
          <size>0x20</size>
        </register>
        <register>
          <name>LCKR</name>
          <addressOffset>0x1c</addressOffset>
          <size>0x20</size>
          <fields>
            <field>
              <name>LCK0</name>
              <bitOffset>0</bitOffset>
              <bitWidth>1</bitWidth>
            </field>
            <field>
              <name>LCK1</name>
              <bitOffset>1</bitOffset>
              <bitWidth>1</bitWidth>
            </field>
            <field>
              <name>LCK2</name>
              <bitOffset>2</bitOffset>
              <bitWidth>1</bitWidth>
            </field>
            <field>
              <name>LCK3</name>
              <bitOffset>3</bitOffset>
              <bitWidth>1</bitWidth>
            </field>
            <field>
              <name>LCK4</name>
              <bitOffset>4</bitOffset>
              <bitWidth>1</bitWidth>
            </field>
            <field>
              <name>LCK5</name>
              <bitOffset>5</bitOffset>
              <bitWidth>1</bitWidth>
            </field>
            <field>
              <name>LCK6</name>
              <bitOffset>6</bitOffset>
              <bitWidth>1</bitWidth>
            </field>
            <field>
              <name>LCK7</name>
              <bitOffset>7</bitOffset>
              <bitWidth>1</bitWidth>
            </field>
            <field>
              <name>LCK8</name>
              <bitOffset>8</bitOffset>
              <bitWidth>1</bitWidth>
            </field>
            <field>
              <name>LCK9</name>
              <bitOffset>9</bitOffset>
              <bitWidth>1</bitWidth>
            </field>
            <field>
              <name>LCK10</name>
              <bitOffset>10</bitOffset>
              <bitWidth>1</bitWidth>
            </field>
            <field>
              <name>LCK11</name>
              <bitOffset>11</bitOffset>
              <bitWidth>1</bitWidth>
            </field>
            <field>
              <name>LCK12</name>
              <bitOffset>12</bitOffset>
              <bitWidth>1</bitWidth>
            </field>
            <field>
              <name>LCK13</name>
              <bitOffset>13</bitOffset>
              <bitWidth>1</bitWidth>
            </field>
            <field>
              <name>LCK14</name>
              <bitOffset>14</bitOffset>
              <bitWidth>1</bitWidth>
            </field>
            <field>
              <name>LCK15</name>
              <bitOffset>15</bitOffset>
              <bitWidth>1</bitWidth>
            </field>
            <field>
              <name>LCKK</name>
              <bitOffset>16</bitOffset>
              <bitWidth>1</bitWidth>
            </field>
          </fields>
        </register>
        <register>
          <name>AFR.0</name>
          <addressOffset>0x20</addressOffset>
          <size>0x20</size>
          <fields>
            <field>
              <name>AFSEL0</name>
              <bitOffset>0</bitOffset>
              <bitWidth>4</bitWidth>
            </field>
            <field>
              <name>AFSEL1</name>
              <bitOffset>4</bitOffset>
              <bitWidth>4</bitWidth>
            </field>
            <field>
              <name>AFSEL2</name>
              <bitOffset>8</bitOffset>
              <bitWidth>4</bitWidth>
            </field>
            <field>
              <name>AFSEL3</name>
              <bitOffset>12</bitOffset>
              <bitWidth>4</bitWidth>
            </field>
            <field>
              <name>AFSEL4</name>
              <bitOffset>16</bitOffset>
              <bitWidth>4</bitWidth>
            </field>
            <field>
              <name>AFSEL5</name>
              <bitOffset>20</bitOffset>
              <bitWidth>4</bitWidth>
            </field>
            <field>
              <name>AFSEL6</name>
              <bitOffset>24</bitOffset>
              <bitWidth>4</bitWidth>
            </field>
            <field>
              <name>AFSEL7</name>
              <bitOffset>28</bitOffset>
              <bitWidth>4</bitWidth>
            </field>
          </fields>
        </register>
        <register>
          <name>AFR.1</name>
          <addressOffset>0x24</addressOffset>
          <size>0x20</size>
          <fields>
            <field>
              <name>AFSEL8</name>
              <bitOffset>0</bitOffset>
              <bitWidth>4</bitWidth>
            </field>
            <field>
              <name>AFSEL9</name>
              <bitOffset>4</bitOffset>
              <bitWidth>4</bitWidth>
            </field>
            <field>
              <name>AFSEL10</name>
              <bitOffset>8</bitOffset>
              <bitWidth>4</bitWidth>
            </field>
            <field>
              <name>AFSEL11</name>
              <bitOffset>12</bitOffset>
              <bitWidth>4</bitWidth>
            </field>
            <field>
              <name>AFSEL12</name>
              <bitOffset>16</bitOffset>
              <bitWidth>4</bitWidth>
            </field>
            <field>
              <name>AFSEL13</name>
              <bitOffset>20</bitOffset>
              <bitWidth>4</bitWidth>
            </field>
            <field>
              <name>AFSEL14</name>
              <bitOffset>24</bitOffset>
              <bitWidth>4</bitWidth>
            </field>
            <field>
              <name>AFSEL15</name>
              <bitOffset>28</bitOffset>
              <bitWidth>4</bitWidth>
            </field>
          </fields>
        </register>
        <register>
          <name>BRR</name>
          <addressOffset>0x28</addressOffset>
          <size>0x20</size>
        </register>
      </registers>
    </peripheral>
    <peripheral>
      <name>GPIOF</name>
      <baseAddress>0x48001400</baseAddress>
      <registers>
        <register>
          <name>MODER</name>
          <addressOffset>0x0</addressOffset>
          <size>0x20</size>
          <fields>
            <field>
              <name>MODER0</name>
              <bitOffset>0</bitOffset>
              <bitWidth>2</bitWidth>
            </field>
            <field>
              <name>MODER1</name>
              <bitOffset>2</bitOffset>
              <bitWidth>2</bitWidth>
            </field>
            <field>
              <name>MODER2</name>
              <bitOffset>4</bitOffset>
              <bitWidth>2</bitWidth>
            </field>
            <field>
              <name>MODER3</name>
              <bitOffset>6</bitOffset>
              <bitWidth>2</bitWidth>
            </field>
            <field>
              <name>MODER4</name>
              <bitOffset>8</bitOffset>
              <bitWidth>2</bitWidth>
            </field>
            <field>
              <name>MODER5</name>
              <bitOffset>10</bitOffset>
              <bitWidth>2</bitWidth>
            </field>
            <field>
              <name>MODER6</name>
              <bitOffset>12</bitOffset>
              <bitWidth>2</bitWidth>
            </field>
            <field>
              <name>MODER7</name>
              <bitOffset>14</bitOffset>
              <bitWidth>2</bitWidth>
            </field>
            <field>
              <name>MODER8</name>
              <bitOffset>16</bitOffset>
              <bitWidth>2</bitWidth>
            </field>
            <field>
              <name>MODER9</name>
              <bitOffset>18</bitOffset>
              <bitWidth>2</bitWidth>
            </field>
            <field>
              <name>MODER10</name>
              <bitOffset>20</bitOffset>
              <bitWidth>2</bitWidth>
            </field>
            <field>
              <name>MODER11</name>
              <bitOffset>22</bitOffset>
              <bitWidth>2</bitWidth>
            </field>
            <field>
              <name>MODER12</name>
              <bitOffset>24</bitOffset>
              <bitWidth>2</bitWidth>
            </field>
            <field>
              <name>MODER13</name>
              <bitOffset>26</bitOffset>
              <bitWidth>2</bitWidth>
            </field>
            <field>
              <name>MODER14</name>
              <bitOffset>28</bitOffset>
              <bitWidth>2</bitWidth>
            </field>
            <field>
              <name>MODER15</name>
              <bitOffset>30</bitOffset>
              <bitWidth>2</bitWidth>
            </field>
          </fields>
        </register>
        <register>
          <name>OTYPER</name>
          <addressOffset>0x4</addressOffset>
          <size>0x20</size>
        </register>
        <register>
          <name>OSPEEDR</name>
          <addressOffset>0x8</addressOffset>
          <size>0x20</size>
          <fields>
            <field>
              <name>OSPEEDR0</name>
              <bitOffset>0</bitOffset>
              <bitWidth>2</bitWidth>
            </field>
            <field>
              <name>OSPEEDR1</name>
              <bitOffset>2</bitOffset>
              <bitWidth>2</bitWidth>
            </field>
            <field>
              <name>OSPEEDR2</name>
              <bitOffset>4</bitOffset>
              <bitWidth>2</bitWidth>
            </field>
            <field>
              <name>OSPEEDR3</name>
              <bitOffset>6</bitOffset>
              <bitWidth>2</bitWidth>
            </field>
            <field>
              <name>OSPEEDR4</name>
              <bitOffset>8</bitOffset>
              <bitWidth>2</bitWidth>
            </field>
            <field>
              <name>OSPEEDR5</name>
              <bitOffset>10</bitOffset>
              <bitWidth>2</bitWidth>
            </field>
            <field>
              <name>OSPEEDR6</name>
              <bitOffset>12</bitOffset>
              <bitWidth>2</bitWidth>
            </field>
            <field>
              <name>OSPEEDR7</name>
              <bitOffset>14</bitOffset>
              <bitWidth>2</bitWidth>
            </field>
            <field>
              <name>OSPEEDR8</name>
              <bitOffset>16</bitOffset>
              <bitWidth>2</bitWidth>
            </field>
            <field>
              <name>OSPEEDR9</name>
              <bitOffset>18</bitOffset>
              <bitWidth>2</bitWidth>
            </field>
            <field>
              <name>OSPEEDR10</name>
              <bitOffset>20</bitOffset>
              <bitWidth>2</bitWidth>
            </field>
            <field>
              <name>OSPEEDR11</name>
              <bitOffset>22</bitOffset>
              <bitWidth>2</bitWidth>
            </field>
            <field>
              <name>OSPEEDR12</name>
              <bitOffset>24</bitOffset>
              <bitWidth>2</bitWidth>
            </field>
            <field>
              <name>OSPEEDR13</name>
              <bitOffset>26</bitOffset>
              <bitWidth>2</bitWidth>
            </field>
            <field>
              <name>OSPEEDR14</name>
              <bitOffset>28</bitOffset>
              <bitWidth>2</bitWidth>
            </field>
            <field>
              <name>OSPEEDR15</name>
              <bitOffset>30</bitOffset>
              <bitWidth>2</bitWidth>
            </field>
          </fields>
        </register>
        <register>
          <name>PUPDR</name>
          <addressOffset>0xc</addressOffset>
          <size>0x20</size>
          <fields>
            <field>
              <name>PUPDR0</name>
              <bitOffset>0</bitOffset>
              <bitWidth>2</bitWidth>
            </field>
            <field>
              <name>PUPDR1</name>
              <bitOffset>2</bitOffset>
              <bitWidth>2</bitWidth>
            </field>
            <field>
              <name>PUPDR2</name>
              <bitOffset>4</bitOffset>
              <bitWidth>2</bitWidth>
            </field>
            <field>
              <name>PUPDR3</name>
              <bitOffset>6</bitOffset>
              <bitWidth>2</bitWidth>
            </field>
            <field>
              <name>PUPDR4</name>
              <bitOffset>8</bitOffset>
              <bitWidth>2</bitWidth>
            </field>
            <field>
              <name>PUPDR5</name>
              <bitOffset>10</bitOffset>
              <bitWidth>2</bitWidth>
            </field>
            <field>
              <name>PUPDR6</name>
              <bitOffset>12</bitOffset>
              <bitWidth>2</bitWidth>
            </field>
            <field>
              <name>PUPDR7</name>
              <bitOffset>14</bitOffset>
              <bitWidth>2</bitWidth>
            </field>
            <field>
              <name>PUPDR8</name>
              <bitOffset>16</bitOffset>
              <bitWidth>2</bitWidth>
            </field>
            <field>
              <name>PUPDR9</name>
              <bitOffset>18</bitOffset>
              <bitWidth>2</bitWidth>
            </field>
            <field>
              <name>PUPDR10</name>
              <bitOffset>20</bitOffset>
              <bitWidth>2</bitWidth>
            </field>
            <field>
              <name>PUPDR11</name>
              <bitOffset>22</bitOffset>
              <bitWidth>2</bitWidth>
            </field>
            <field>
              <name>PUPDR12</name>
              <bitOffset>24</bitOffset>
              <bitWidth>2</bitWidth>
            </field>
            <field>
              <name>PUPDR13</name>
              <bitOffset>26</bitOffset>
              <bitWidth>2</bitWidth>
            </field>
            <field>
              <name>PUPDR14</name>
              <bitOffset>28</bitOffset>
              <bitWidth>2</bitWidth>
            </field>
            <field>
              <name>PUPDR15</name>
              <bitOffset>30</bitOffset>
              <bitWidth>2</bitWidth>
            </field>
          </fields>
        </register>
        <register>
          <name>IDR</name>
          <addressOffset>0x10</addressOffset>
          <size>0x20</size>
        </register>
        <register>
          <name>ODR</name>
          <addressOffset>0x14</addressOffset>
          <size>0x20</size>
        </register>
        <register>
          <name>BSRR</name>
          <addressOffset>0x18</addressOffset>
          <size>0x20</size>
        </register>
        <register>
          <name>LCKR</name>
          <addressOffset>0x1c</addressOffset>
          <size>0x20</size>
          <fields>
            <field>
              <name>LCK0</name>
              <bitOffset>0</bitOffset>
              <bitWidth>1</bitWidth>
            </field>
            <field>
              <name>LCK1</name>
              <bitOffset>1</bitOffset>
              <bitWidth>1</bitWidth>
            </field>
            <field>
              <name>LCK2</name>
              <bitOffset>2</bitOffset>
              <bitWidth>1</bitWidth>
            </field>
            <field>
              <name>LCK3</name>
              <bitOffset>3</bitOffset>
              <bitWidth>1</bitWidth>
            </field>
            <field>
              <name>LCK4</name>
              <bitOffset>4</bitOffset>
              <bitWidth>1</bitWidth>
            </field>
            <field>
              <name>LCK5</name>
              <bitOffset>5</bitOffset>
              <bitWidth>1</bitWidth>
            </field>
            <field>
              <name>LCK6</name>
              <bitOffset>6</bitOffset>
              <bitWidth>1</bitWidth>
            </field>
            <field>
              <name>LCK7</name>
              <bitOffset>7</bitOffset>
              <bitWidth>1</bitWidth>
            </field>
            <field>
              <name>LCK8</name>
              <bitOffset>8</bitOffset>
              <bitWidth>1</bitWidth>
            </field>
            <field>
              <name>LCK9</name>
              <bitOffset>9</bitOffset>
              <bitWidth>1</bitWidth>
            </field>
            <field>
              <name>LCK10</name>
              <bitOffset>10</bitOffset>
              <bitWidth>1</bitWidth>
            </field>
            <field>
              <name>LCK11</name>
              <bitOffset>11</bitOffset>
              <bitWidth>1</bitWidth>
            </field>
            <field>
              <name>LCK12</name>
              <bitOffset>12</bitOffset>
              <bitWidth>1</bitWidth>
            </field>
            <field>
              <name>LCK13</name>
              <bitOffset>13</bitOffset>
              <bitWidth>1</bitWidth>
            </field>
            <field>
              <name>LCK14</name>
              <bitOffset>14</bitOffset>
              <bitWidth>1</bitWidth>
            </field>
            <field>
              <name>LCK15</name>
              <bitOffset>15</bitOffset>
              <bitWidth>1</bitWidth>
            </field>
            <field>
              <name>LCKK</name>
              <bitOffset>16</bitOffset>
              <bitWidth>1</bitWidth>
            </field>
          </fields>
        </register>
        <register>
          <name>AFR.0</name>
          <addressOffset>0x20</addressOffset>
          <size>0x20</size>
          <fields>
            <field>
              <name>AFSEL0</name>
              <bitOffset>0</bitOffset>
              <bitWidth>4</bitWidth>
            </field>
            <field>
              <name>AFSEL1</name>
              <bitOffset>4</bitOffset>
              <bitWidth>4</bitWidth>
            </field>
            <field>
              <name>AFSEL2</name>
              <bitOffset>8</bitOffset>
              <bitWidth>4</bitWidth>
            </field>
            <field>
              <name>AFSEL3</name>
              <bitOffset>12</bitOffset>
              <bitWidth>4</bitWidth>
            </field>
            <field>
              <name>AFSEL4</name>
              <bitOffset>16</bitOffset>
              <bitWidth>4</bitWidth>
            </field>
            <field>
              <name>AFSEL5</name>
              <bitOffset>20</bitOffset>
              <bitWidth>4</bitWidth>
            </field>
            <field>
              <name>AFSEL6</name>
              <bitOffset>24</bitOffset>
              <bitWidth>4</bitWidth>
            </field>
            <field>
              <name>AFSEL7</name>
              <bitOffset>28</bitOffset>
              <bitWidth>4</bitWidth>
            </field>
          </fields>
        </register>
        <register>
          <name>AFR.1</name>
          <addressOffset>0x24</addressOffset>
          <size>0x20</size>
          <fields>
            <field>
              <name>AFSEL8</name>
              <bitOffset>0</bitOffset>
              <bitWidth>4</bitWidth>
            </field>
            <field>
              <name>AFSEL9</name>
              <bitOffset>4</bitOffset>
              <bitWidth>4</bitWidth>
            </field>
            <field>
              <name>AFSEL10</name>
              <bitOffset>8</bitOffset>
              <bitWidth>4</bitWidth>
            </field>
            <field>
              <name>AFSEL11</name>
              <bitOffset>12</bitOffset>
              <bitWidth>4</bitWidth>
            </field>
            <field>
              <name>AFSEL12</name>
              <bitOffset>16</bitOffset>
              <bitWidth>4</bitWidth>
            </field>
            <field>
              <name>AFSEL13</name>
              <bitOffset>20</bitOffset>
              <bitWidth>4</bitWidth>
            </field>
            <field>
              <name>AFSEL14</name>
              <bitOffset>24</bitOffset>
              <bitWidth>4</bitWidth>
            </field>
            <field>
              <name>AFSEL15</name>
              <bitOffset>28</bitOffset>
              <bitWidth>4</bitWidth>
            </field>
          </fields>
        </register>
        <register>
          <name>BRR</name>
          <addressOffset>0x28</addressOffset>
          <size>0x20</size>
        </register>
      </registers>
    </peripheral>
  </peripherals>
</device>
